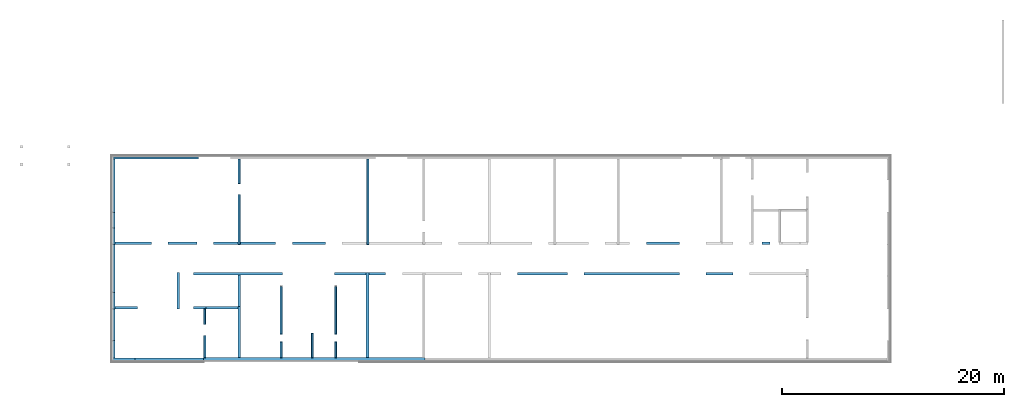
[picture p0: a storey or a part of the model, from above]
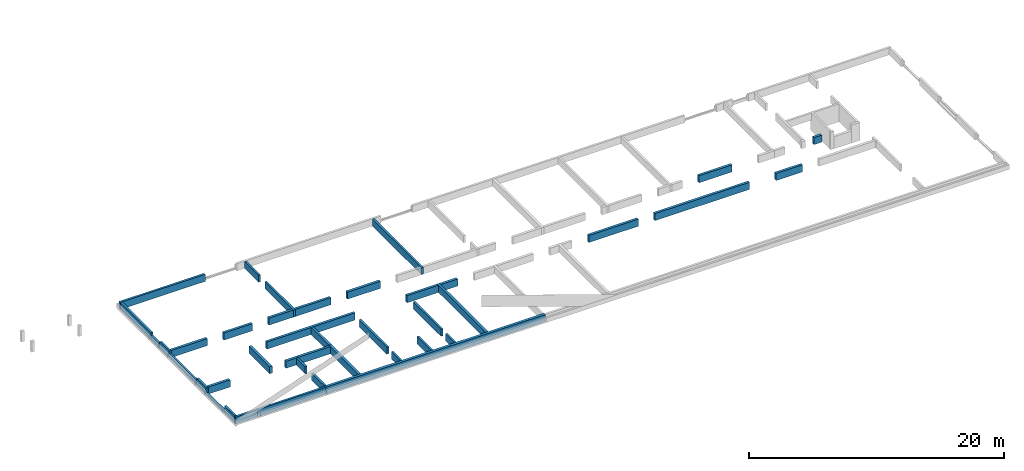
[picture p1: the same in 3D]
Properties of the parts of a building model (IFC2X3), part 1 of 8

# File
Description: ViewDefinition [CoordinationView_V2.0, SpaceBoundary2ndLevelAddOnView], Option [Elements to export: Visible elements (on all stories)], Option [Partial Structure Display: Entire Model], Option [IFC Domain: All], Option [Structural Function: All Elements], Option [Convert Grid elements: On], Option [Convert IFC Annotations and Archicad 2D elements: Off], Option [Convert 2D symbols of Doors and Windows: Off], Option [Export geometries that Participates in Collision Detection only: Off], Option [Split complex elements: On], Option [IFC Domain For Space Containment: Custom], Option [Elements in Solid Element Operations: BRep], Option [Elements with junctions: BRep], Option [IFC Model position: Survey Point and Project Origin], Option [Curtain Wall export mode: Container Element], Option [Railing export mode: Container Element], Option [Stair export mode: Container Element], Option [Properties To Export: All properties], Option [Space containment: Off], Option [Geometry to type objects: Off], Option [Element Properties: Visible Only], Option [Building Material Properties: Off], Option [Element Parameters: Off], Option [Component Parameters: Off], Option [IFC Base Quantities: Off], Option [Door Window Parameters: On], Option [IFC Space boundaries: On], Option [Archicad Zone Categories as IFC Space classification data: Off], Option [Element Classifications: On]
File name: C:\Users\User\OneDrive\Desktop\AK2_TP_AR.ifc
Time: 2025-07-31T16:51:45
Author: RKAS
Organization: Building Designer Office
Written by: DDS_IFC v3.0
Made in: IFC file generated by Graphisoft Archicad 26.0.0 INT FULL Windows version (IFC add-on version: 7004 INT FULL).
Authorization: RKAS

# IfcProject, METK Aretuskeskus 2
Phase: Tööprojekt

# IfcSite, ÜBN Kinnistu Nimi -> SOLIBRI
Description: Kinnistu Kirjeldus; RefLatitude: 59, 25, 17, 655600; RefLongitude: 24, 44, 44, 307600; RefElevation: 69000 mm; Classification: 1.0.1 IfcSite (kinnistu) (BIM ÜBN + Archicad Classification 26 + v 2.0)
AR_Kinnistu - 010_Katastritunnus: 24701:001:1420; 015_Ehitatav-pindala: 1380 m2; 020_Pindala: 7544 m2; 025_Max-kõrgus: 14000 mm

# IfcBuilding, METK ARETUSKESKUS II
Classification: 1.0.2 IfcBuilding (hoone) (BIM ÜBN + Archicad Classification 26 + v 2.0)
AR_Hoone - 030_Hoone-aadress: Seemne tn 10a, Jõgeva alevik, Jõgeva vald, Jõgeva maakond; 035_Sprinkler: no; 041_Sügavus: 0 mm; 701_ETAK-id: täiendamisel; 704_Kasutusotstarve: Büroohoone; 705_Kasutusotstarbe-kood: 12201; 707_Tuleohutusklass: TP2; 703_Kasutajate-arv: 100; 706_Eripõlemiskoormus: 599; 001_Nimetus: METK ARETUSKESKUS II; 040_Kõrgus: 10300 mm; 045_Hoonealune-pindala: 1334.3 m2; 050_Neto-pindala: 2214.8 m2; 055_Neto-ruumala: 9000 m3; 700_EHR-kood: 121423536; 702_ADS-OID: EE04134256

# IfcBuildingStorey (4)
In: METK ARETUSKESKUS II
Name | Elevation (mm) | 710_Määrusejärgne-korrus | 060_Korruse-nimi | 070_Maapealne
Vundament | -1610 | no | Vundament | no
Esimene korrus | 0 | yes | Esimene korrus | yes | Classification: 1.0.3 IfcBuildingStorey (korrus) (BIM ÜBN + Archicad Classification 26 + v 2.0); AR_Korrus - 065_Korruse-number: 1
Teine korrus | 4425 | yes | Teine korrus | yes | AR_Korrus - 065_Korruse-number: 2
Katus | 8635 | no | Katus | yes

# IfcBeam: 31 Konst: raudbetoon monoliitne 180 (28)
In: Vundament
Type - PredefinedType: BEAM
Classification: 1.01 IfcBeamType (tala) (BIM ÜBN + Archicad Classification); Material: 31 Konst: raudbetoon monoliitne
AR_ÜLD - 001_Nimetus: Tala; 009_Märkus: vt. EK-osa
Pset_BeamCommon - IsExternal: no; LoadBearing: yes
AC_Pset_RenovationAndPhasing - Renovation Status: New

# IfcBeam: 31 Konst: raudbetoon monoliitne 190 (22)
In: Vundament
Type - PredefinedType: BEAM
Classification: 1.01 IfcBeamType (tala) (BIM ÜBN + Archicad Classification); Material: 31 Konst: raudbetoon monoliitne
AR_ÜLD - 001_Nimetus: Tala; 009_Märkus: vt. EK-osa
AC_Pset_RenovationAndPhasing - Renovation Status: New
Pset_BeamCommon - IsExternal: no; LoadBearing: yes

# IfcBeam: 31 Konst: raudbetoon monoliitne 230 (17)
In: Vundament
Type - PredefinedType: BEAM
Classification: 1.01 IfcBeamType (tala) (BIM ÜBN + Archicad Classification); Material: 31 Konst: raudbetoon monoliitne
AR_ÜLD - 001_Nimetus: Tala; 009_Märkus: vt. EK-osa
AC_Pset_RenovationAndPhasing - Renovation Status: New
Pset_BeamCommon - IsExternal: no; LoadBearing: yes

# IfcBeam: 31 Konst: raudbetoon monoliitne 240
In: Vundament
Type - PredefinedType: BEAM
Classification: 1.01 IfcBeamType (tala) (BIM ÜBN + Archicad Classification); Material: 31 Konst: raudbetoon monoliitne
AC_Pset_RenovationAndPhasing - Renovation Status: New
Pset_BeamCommon - IsExternal: no; LoadBearing: yes
AR_ÜLD - 001_Nimetus: Tala; 009_Märkus: vt. EK-osa

# IfcBeam: 40 Kiht: Teras 150 x 1030, TALA
In: Teine korrus
Type - PredefinedType: BEAM
Classification: 1.01 IfcBeamType (tala) (BIM ÜBN + Archicad Classification); Material: 40 Kiht: Teras
Pset_BeamCommon - Span: 11650 mm; Slope: 0 deg; IsExternal: yes; LoadBearing: yes; Reference: 40 Kiht: Teras 150 x 1030
AC_Pset_RenovationAndPhasing - Renovation Status: New
AR_ÜLD - 009_Märkus: OMA märkus

# IfcBeam: 40 Kiht: Teras 300 x 490, TALA
In: Teine korrus
Type - PredefinedType: BEAM
Classification: 1.01 IfcBeamType (tala) (BIM ÜBN + Archicad Classification); Material: 40 Kiht: Teras
Pset_BeamCommon - Span: 11650 mm; Slope: 0 deg; IsExternal: yes; LoadBearing: yes; Reference: 40 Kiht: Teras 300 x 490
AC_Pset_RenovationAndPhasing - Renovation Status: New
AR_ÜLD - 009_Märkus: OMA märkus

# IfcBeam: 80 Siseviim: tolmutõke 180
In: Vundament
Type - PredefinedType: BEAM
Classification: 1.01 IfcBeamType (tala) (BIM ÜBN + Archicad Classification); Material: 80 Siseviim: tolmutõke
AR_ÜLD - 001_Nimetus: Tala; 009_Märkus: vt. EK-osa
AC_Pset_RenovationAndPhasing - Renovation Status: New
Pset_BeamCommon - IsExternal: no; LoadBearing: yes

# IfcBeam: 80 Siseviim: tolmutõke 230 (16)
In: Vundament
Type - PredefinedType: BEAM
Classification: 1.01 IfcBeamType (tala) (BIM ÜBN + Archicad Classification); Material: 80 Siseviim: tolmutõke
AR_ÜLD - 001_Nimetus: Tala; 009_Märkus: vt. EK-osa
AC_Pset_RenovationAndPhasing - Renovation Status: New
Pset_BeamCommon - IsExternal: no; LoadBearing: yes

# IfcBeam: Steel L Section 100 x 100 (3)
In: Esimene korrus
Type - PredefinedType: BEAM
Classification: 1.01 IfcBeamType (tala) (BIM ÜBN + Archicad Classification); Material: 30 Konst: Teras - Konstruktsioon
Pset_BeamCommon - IsExternal: yes; LoadBearing: yes; Reference: Steel L Section 100 x 100
AR_ÜLD - 001_Nimetus: Kandetala
AC_Pset_RenovationAndPhasing - Renovation Status: New
Name | Span (mm) | Slope (deg)
TALA | 9310 | 0
TALA | 9512.21 | 1.23489
TALA | 9510 | 0

# IfcBeam: Steel L Section 300 x 150 (3)
In: Esimene korrus
Type - PredefinedType: BEAM
Classification: 1.01 IfcBeamType (tala) (BIM ÜBN + Archicad Classification); Material: 30 Konst: Teras - Konstruktsioon
AR_ÜLD - 001_Nimetus: Kandetala
AC_Pset_RenovationAndPhasing - Renovation Status: New
Pset_BeamCommon - Slope: 0 deg; IsExternal: yes; LoadBearing: yes; Reference: Steel L Section 300 x 150
Name | Span (mm)
2 x TALA | 8700
TALA | 4350

# IfcBeam: Steel L Section 50 x 130 (3)
In: Teine korrus
Type - PredefinedType: BEAM
Classification: 1.01 IfcBeamType (tala) (BIM ÜBN + Archicad Classification); Material: 30 Konst: Teras - Konstruktsioon
Pset_BeamCommon - Slope: 0 deg; IsExternal: yes; LoadBearing: yes; Reference: Steel L Section 50 x 130
AR_ÜLD - 001_Nimetus: Kandetala
AC_Pset_RenovationAndPhasing - Renovation Status: New
Name | Span (mm)
TALA | 4028
2 x TALA | 8378

# IfcBeam: Steel L Section 50 x 50 (3)
In: Teine korrus
Type - PredefinedType: BEAM
Classification: 1.01 IfcBeamType (tala) (BIM ÜBN + Archicad Classification); Material: 30 Konst: Teras - Konstruktsioon
Pset_BeamCommon - Slope: 0 deg; IsExternal: yes; LoadBearing: yes; Reference: Steel L Section 50 x 50
AC_Pset_RenovationAndPhasing - Renovation Status: New
AR_ÜLD - 001_Nimetus: Kandetala
Name | Span (mm)
2 x TALA | 8398
TALA | 4048.01

# IfcBeam: Steel T Section 140 x 140, TALA
In: Esimene korrus
Type - PredefinedType: BEAM
Classification: 1.01 IfcBeamType (tala) (BIM ÜBN + Archicad Classification); Material: 40 Kiht: Teras
Pset_BeamCommon - Span: 4050 mm; Slope: 0 deg; IsExternal: yes; LoadBearing: yes; Reference: Steel T Section 140 x 140
AR_ÜLD - 001_Nimetus: Kandetala
AC_Pset_RenovationAndPhasing - Renovation Status: New

# IfcBeam: Trapets puit 50 x 195 (14)
In: Esimene korrus
Type - PredefinedType: BEAM
Classification: 1.01 IfcBeamType (tala) (BIM ÜBN + Archicad Classification); Material: 60 Plaat: liimpuitplaat
Pset_BeamCommon - Slope: 0 deg; IsExternal: yes; LoadBearing: yes; Reference: Trapets puit 50 x 195
AR_ÜLD - 001_Nimetus: Kandetala
AC_Pset_RenovationAndPhasing - Renovation Status: New
Name | Span (mm)
5 x TALA | 9940
3 x TALA | 3500.01
2 x TALA | 9940.01
4 x TALA | 1467

# IfcBeam: UPE100 60 x 140 (2)
In: Esimene korrus
Type - PredefinedType: BEAM
Classification: 1.01 IfcBeamType (tala) (BIM ÜBN + Archicad Classification); Material: 30 Konst: Teras - Konstruktsioon
Pset_BeamCommon - Span: 9799.39 mm; Slope: 0 deg; IsExternal: yes; LoadBearing: yes; Reference: UPE100 60 x 140
AR_ÜLD - 001_Nimetus: Kandetala
AC_Pset_RenovationAndPhasing - Renovation Status: New

# IfcBuildingElementPart (1536)
Name | In | Material | 009_Märkus
26 x 50 Soojustus: EPS | Vundament | 50 Soojustus: EPS
26 x 92 Viim: betoonlasuur | Vundament | 92 Viim: betoonlasuur
7 x 30 Konst: Columbia õõnesplokk | Esimene korrus | 30 Konst: Columbia õõnesplokk
17 x 50 Soojustus: PIR SW | Esimene korrus | 50 Soojustus: PIR SW
27 x 72 Kiht: SW plekk | Esimene korrus | 72 Kiht: SW plekk
28 x 50 Soojustus: EPS | Esimene korrus | 50 Soojustus: EPS | vt. EK-osa konstruktsioone
14 x 30 Konst: Raudbetoon monoliitne | Esimene korrus | 30 Konst: Raudbetoon monoliitne | vt. EK-osa konstruktsioone
28 x 20 Keskkond: killustikalus | Esimene korrus | 20 Keskkond: killustikalus | vt. EK-osa konstruktsioone
4 x 60 Plaat: Kipsplaat | Esimene korrus | 60 Plaat: Kipsplaat | SS-01 seinatüüp SL-01 lisavoodriga
4 x 50 Soojustus: PIR saun | Esimene korrus | 50 Soojustus: PIR saun | SS-01 seinatüüp SL-01 lisavoodriga
2 x 60 Plaat: Kipsplaat | Esimene korrus | 60 Plaat: Kipsplaat | SS-02 seinatüüp SL-01 lisavoodriga
2 x 50 Soojustus: PIR saun | Esimene korrus | 50 Soojustus: PIR saun | SS-02 seinatüüp SL-01 lisavoodriga
2 x 30 Konst: Columbia õõnesplokk | Esimene korrus | 30 Konst: Columbia õõnesplokk | SS-02 seinatüüp SL-01 lisavoodriga
2 x 60 Plaat: Kipsplaat | Esimene korrus | 60 Plaat: Kipsplaat | kergsein
2 x 60 Plaat: Kipsplaat tulekindel | Esimene korrus | 60 Plaat: Kipsplaat tulekindel | kergsein
50 Soojustus: klaasvill | Esimene korrus | 50 Soojustus: klaasvill | kergsein
16 x 50 Soojustus: XPS | Esimene korrus | 50 Soojustus: XPS | Põrand paksendatud betoonplaadiga, vt. EK-osa
16 x 20 Keskkond: killustikalus | Esimene korrus | 20 Keskkond: killustikalus | Põrand paksendatud betoonplaadiga, vt. EK-osa
8 x 30 Konst: Raudbetoon monoliitne | Esimene korrus | 30 Konst: Raudbetoon monoliitne | Põrand paksendatud betoonplaadiga, vt. EK-osa
8 x 50 Soojustus: PIR saun | Esimene korrus | 50 Soojustus: PIR saun | vt. SS-10/SS-10a konstruktsioonitüüpi
8 x 70 Kiht: Õhkvahe karkass | Esimene korrus | 70 Kiht: Õhkvahe karkass | vt. SS-10/SS-10a konstruktsioonitüüpi
8 x 92 Viim: Puit voodrilaud saun | Esimene korrus | 92 Viim: Puit voodrilaud saun | vt. SS-10/SS-10a konstruktsioonitüüpi
4 x 60 Plaat: Tsementkiudplaat | Esimene korrus | 60 Plaat: Tsementkiudplaat | vt. SA-osa
9 x 50 Soojustus: klaasvill | Esimene korrus | 50 Soojustus: klaasvill | vt. SA-osa
7 x 60 Plaat: Puitkiudplaat | Esimene korrus | 60 Plaat: Puitkiudplaat | vt. SA-osa
30 Konst: Raudbetoon monoliitne | Esimene korrus | 30 Konst: Raudbetoon monoliitne | vt. EK-osa
20 Keskkond: killustikalus | Esimene korrus | 20 Keskkond: killustikalus | vt. EK-osa
2 x 50 Soojustus: klaasvill | Esimene korrus | 50 Soojustus: klaasvill | Loputuskasti tagune
4 x 60 Plaat: Tsementkiudplaat | Esimene korrus | 60 Plaat: Tsementkiudplaat | Loputuskasti tagune
4 x 20 Keskkond: killustikalus | Esimene korrus | 20 Keskkond: killustikalus | NB! jälgida SA-osa porivaipa! Betoonplaadi paksus 80mm
4 x 50 Soojustus: EPS | Esimene korrus | 50 Soojustus: EPS | NB! jälgida SA-osa porivaipa! Betoonplaadi paksus 80mm
2 x 30 Konst: Raudbetoon monoliitne | Esimene korrus | 30 Konst: Raudbetoon monoliitne | NB! jälgida SA-osa porivaipa! Betoonplaadi paksus 80mm
101 x 71 Kiht: MDF | Esimene korrus | 71 Kiht: MDF | OMA märkus
101 x 80 Siseviimistlus dold | Esimene korrus | 80 Siseviimistlus dold | OMA märkus
10 x 60 Plaat: Kipsplaat | Esimene korrus | 60 Plaat: Kipsplaat | OMA märkus
12 x 50 Soojustus: kivivill | Esimene korrus | 50 Soojustus: kivivill | OMA märkus
29 x 70 Kiht: Õhkvahe karkass | Esimene korrus | 70 Kiht: Õhkvahe karkass | OMA märkus
50 Soojustus: XPS | Esimene korrus | 50 Soojustus: XPS | pinnase vastas
30 Konst: Columbia õõnesplokk | Esimene korrus | 30 Konst: Columbia õõnesplokk | pinnase vastas
15 x 50 Soojustus: klaasvill | Esimene korrus | 50 Soojustus: klaasvill | vt. AR-8 konstruktsioonitüüpe
15 x 60 Plaat: Puitkiudplaat | Esimene korrus | 60 Plaat: Puitkiudplaat | vt. AR-8 konstruktsioonitüüpe
15 x 50 Soojustus: klaasvill | Esimene korrus | 50 Soojustus: klaasvill | OMA märkus
15 x 60 Plaat: Puitkiudplaat | Esimene korrus | 60 Plaat: Puitkiudplaat | OMA märkus
20 x 60 Plaat: Kipsplaat | Esimene korrus | 60 Plaat: Kipsplaat | Akustiline paneel
10 x 50 Soojustus: klaasvill | Esimene korrus | 50 Soojustus: klaasvill | Akustiline paneel
2 x 71 Kiht: akustiline plaat | Esimene korrus | 71 Kiht: akustiline plaat | OMA märkus
2 x 92 Viim: Puit voodrilaud saun | Esimene korrus | 92 Viim: Puit voodrilaud saun | OMA märkus
4 x 72 Kiht: SW plekk | Esimene korrus | 72 Kiht: SW plekk | OMA märkus
2 x 50 Soojustus: PIR SW | Esimene korrus | 50 Soojustus: PIR SW | OMA märkus
2 x 50 Soojustus: PIR saun | Esimene korrus | 50 Soojustus: PIR saun | OMA märkus
4 x 60 Plaat: Kipsplaat | Esimene korrus | 60 Plaat: Kipsplaat | Šahtisein
2 x 50 Soojustus: klaasvill | Esimene korrus | 50 Soojustus: klaasvill | Šahtisein
4 x 40 Kiht: Teras | Esimene korrus | 40 Kiht: Teras | vt. AR-8 kujujooniseid
4 x 44 Konst: Alumiinium | Esimene korrus | 44 Konst: Alumiinium | vt. AR-8 kujujooniseid
2 x 45 Konst: puit hor | Esimene korrus | 45 Konst: puit hor | OMA märkus
30 Konstr: CLT-talad | Esimene korrus | 30 Konstr: CLT-talad | OMA märkus
2 x Concrete - Structural | Esimene korrus | Concrete - Structural | OMA märkus
2 x 60 Plaat: Vineer veekindel | Esimene korrus | 60 Plaat: Vineer veekindel | vt. EK-osa. Mudelis jaotatud osadeks
2 x 72 Kiht: SBS-katusekate | Esimene korrus | 72 Kiht: SBS-katusekate | vt. EK-osa. Mudelis jaotatud osadeks
2 x 72 Kiht: drenaažimatt | Esimene korrus | 72 Kiht: drenaažimatt | vt. EK-osa. Mudelis jaotatud osadeks
2 x 20 Keskkond: Pinnas | Esimene korrus | 20 Keskkond: Pinnas | vt. EK-osa. Mudelis jaotatud osadeks
2 x 21 Keskkond: Pinnas 01 | Esimene korrus | 21 Keskkond: Pinnas 01 | vt. EK-osa. Mudelis jaotatud osadeks
80 Siseviimistlus dold | Esimene korrus | 80 Siseviimistlus dold
70 Kiht: Õhkvahe karkass | Esimene korrus | 70 Kiht: Õhkvahe karkass
50 Soojustus: PIR SW | Esimene korrus | 50 Soojustus: PIR SW | vt. AR-8 konstruktsioonitüüpe
2 x 72 Kiht: SW plekk | Esimene korrus | 72 Kiht: SW plekk | vt. AR-8 konstruktsioonitüüpe
14 x 50 Soojustus: PIR SW | Teine korrus | 50 Soojustus: PIR SW
15 x 72 Kiht: SW plekk | Teine korrus | 72 Kiht: SW plekk
13 x 30 Konst: Columbia õõnesplokk | Teine korrus | 30 Konst: Columbia õõnesplokk
9 x 30 Konst: Raudbetoon monoliitne pealevalu | Teine korrus | 30 Konst: Raudbetoon monoliitne pealevalu | vt. EK-osa
18 x 50 Soojustus: EPS | Teine korrus | 50 Soojustus: EPS | vt. EK-osa
9 x 30 Konst: Raudbetoon monteeritav | Teine korrus | 30 Konst: Raudbetoon monteeritav | vt. EK-osa
4 x 72 Kiht: SW plekk | Teine korrus | 72 Kiht: SW plekk | vt. VS-08
2 x 50 Soojustus: PIR SW | Teine korrus | 50 Soojustus: PIR SW | vt. VS-08
92 x 60 Plaat: Kipsplaat | Teine korrus | 60 Plaat: Kipsplaat | kergsein
50 x 50 Soojustus: klaasvill | Teine korrus | 50 Soojustus: klaasvill | kergsein
92 x 60 Plaat: Kipsplaat tulekindel | Teine korrus | 60 Plaat: Kipsplaat tulekindel | kergsein
7 x 72 Kiht: SW plekk | Teine korrus | 72 Kiht: SW plekk | vt. AR-7 sõlmlahendusi
3 x 30 Konst: Columbia õõnesplokk | Teine korrus | 30 Konst: Columbia õõnesplokk | vt. AR-7 sõlmlahendusi
4 x 50 Soojustus: PIR SW | Teine korrus | 50 Soojustus: PIR SW | vt. AR-7 sõlmlahendusi
4 x 79 Kiht: õhkvahe | Teine korrus | 79 Kiht: õhkvahe | kergsein
32 x 60 Plaat: Kipsplaat | Teine korrus | 60 Plaat: Kipsplaat
8 x 60 Plaat: Kipsplaat tulekindel | Teine korrus | 60 Plaat: Kipsplaat tulekindel
12 x 50 Soojustus: klaasvill | Teine korrus | 50 Soojustus: klaasvill
6 x 60 Plaat: Kipsplaat | Teine korrus | 60 Plaat: Kipsplaat | Šahtisein
3 x 50 Soojustus: klaasvill | Teine korrus | 50 Soojustus: klaasvill | Šahtisein
3 x 30 Konst: Betoonplaat | Teine korrus | 30 Konst: Betoonplaat | vt. EK-osa. Mudelis jaotatud osadeks
13 x 72 Kiht: SBS-katusekate | Teine korrus | 72 Kiht: SBS-katusekate | vt. EK-osa. Mudelis jaotatud osadeks
15 x 50 Soojustus: EPS | Teine korrus | 50 Soojustus: EPS | vt. EK-osa. Mudelis jaotatud osadeks
3 x 72 Kiht: SBS-aurutõke | Teine korrus | 72 Kiht: SBS-aurutõke | vt. EK-osa. Mudelis jaotatud osadeks
2 x 64 Plaat: vineer | Teine korrus | 64 Plaat: vineer
6 x 72 Kiht: veeplekk | Teine korrus | 72 Kiht: veeplekk
8 x 60 Plaat: Tsementkiudplaat | Teine korrus | 60 Plaat: Tsementkiudplaat | Loputuskasti tagune
4 x 50 Soojustus: klaasvill | Teine korrus | 50 Soojustus: klaasvill | Loputuskasti tagune
2 x 92 Viim: Puit voodrilaud | Teine korrus | 92 Viim: Puit voodrilaud | 1. korruse lõuna ja põhja fassaadi välisuste kohal. vt. skeemi joonisel. vt. täpsemalt EK-osa ja AR-7 sõlmlahendusi
2 x 30 Konst: Teras - Konstruktsioon | Teine korrus | 30 Konst: Teras - Konstruktsioon | 1. korruse lõuna ja põhja fassaadi välisuste kohal. vt. skeemi joonisel. vt. täpsemalt EK-osa ja AR-7 sõlmlahendusi
2 x 40 Kiht: Teras | Teine korrus | 40 Kiht: Teras | 1. korruse lõuna ja põhja fassaadi välisuste kohal. vt. skeemi joonisel. vt. täpsemalt EK-osa ja AR-7 sõlmlahendusi
2 x 30 Konst: puit 01 | Teine korrus | 30 Konst: puit 01 | 1. korruse lõuna ja põhja fassaadi välisuste kohal. vt. skeemi joonisel. vt. täpsemalt EK-osa ja AR-7 sõlmlahendusi
4 x 60 Plaat: Tsementkiudplaat | Teine korrus | 60 Plaat: Tsementkiudplaat | vt. SA-osa
2 x 50 Soojustus: klaasvill | Teine korrus | 50 Soojustus: klaasvill | vt. SA-osa
6 x 60 Plaat: Kipsplaat | Teine korrus | 60 Plaat: Kipsplaat | Akustiline paneel
3 x 50 Soojustus: klaasvill | Teine korrus | 50 Soojustus: klaasvill | Akustiline paneel
6 x 80 Siseviimistlus dold | Teine korrus | 80 Siseviimistlus dold | OMA märkus
14 x 70 Kiht: Õhkvahe karkass | Teine korrus | 70 Kiht: Õhkvahe karkass | OMA märkus
9 x 60 Plaat: Kipsplaat | Teine korrus | 60 Plaat: Kipsplaat | OMA märkus
10 x 50 Soojustus: kivivill | Teine korrus | 50 Soojustus: kivivill | OMA märkus
2 x 71 Kiht: akustiline plaat | Teine korrus | 71 Kiht: akustiline plaat | OMA märkus
2 x 92 Viim: Puit voodrilaud | Teine korrus | 92 Viim: Puit voodrilaud | vt. AR-7 sõlmlahendusi
4 x 70 Kiht: Õhkvahe karkass | Teine korrus | 70 Kiht: Õhkvahe karkass | vt. AR-7 sõlmlahendusi
2 x 71 Kiht: MDF | Teine korrus | 71 Kiht: MDF
2 x 80 Siseviimistlus dold | Teine korrus | 80 Siseviimistlus dold
92 Viim: Puit voodrilaud | Teine korrus | 92 Viim: Puit voodrilaud | 1. korruse ida fassaadi välisukse kohal. vt. skeemi joonisel. vt. täpsemalt EK-osa ja AR-7 sõlmlahendusi
30 Konst: Teras - Konstruktsioon | Teine korrus | 30 Konst: Teras - Konstruktsioon | 1. korruse ida fassaadi välisukse kohal. vt. skeemi joonisel. vt. täpsemalt EK-osa ja AR-7 sõlmlahendusi
30 Konst: puit 01 | Teine korrus | 30 Konst: puit 01 | 1. korruse ida fassaadi välisukse kohal. vt. skeemi joonisel. vt. täpsemalt EK-osa ja AR-7 sõlmlahendusi
4 x 50 Soojustus: PIR | Teine korrus | 50 Soojustus: PIR | vt. EK-osa ja AR-7 sõlmlahendusi
4 x 72 Kiht: SBS-katusekate | Teine korrus | 72 Kiht: SBS-katusekate | vt. EK-osa ja AR-7 sõlmlahendusi
4 x 50 Soojustus: EPS | Teine korrus | 50 Soojustus: EPS | vt. EK-osa ja AR-7 sõlmlahendusi
2 x 72 Kiht: SW plekk | Teine korrus | 72 Kiht: SW plekk | vt. AR-7 sõlmlahendusi. KL-01 lisaks
50 Soojustus: PIR SW | Teine korrus | 50 Soojustus: PIR SW | vt. AR-7 sõlmlahendusi. KL-01 lisaks
2 x 72 Kiht: SBS-katusekate | Teine korrus | 72 Kiht: SBS-katusekate | vt. AR-7 sõlmlahendusi
2 x 60 Plaat: Vineer veekindel | Teine korrus | 60 Plaat: Vineer veekindel | vt. AR-7 sõlmlahendusi
5 x 92 Viim: Puit voodrilaud | Teine korrus | 92 Viim: Puit voodrilaud | vt. VS-08
5 x 90 Viim: Õhkvahe karkass | Teine korrus | 90 Viim: Õhkvahe karkass | vt. VS-08
60 Plaat: Kipsplaat tulekindel | Teine korrus | 60 Plaat: Kipsplaat tulekindel | OMA märkus
3 x 45 Konst: puit hor | Teine korrus | 45 Konst: puit hor | OMA märkus
2 x Concrete - Structural | Teine korrus | Concrete - Structural | OMA märkus
10 x 60 Plaat: Vineer veekindel | Teine korrus | 60 Plaat: Vineer veekindel | vt. EK-osa. Mudelis jaotatud osadeks
10 x 72 Kiht: drenaažimatt | Teine korrus | 72 Kiht: drenaažimatt | vt. EK-osa. Mudelis jaotatud osadeks
10 x 20 Keskkond: Pinnas | Teine korrus | 20 Keskkond: Pinnas | vt. EK-osa. Mudelis jaotatud osadeks
10 x 21 Keskkond: Pinnas 01 | Teine korrus | 21 Keskkond: Pinnas 01 | vt. EK-osa. Mudelis jaotatud osadeks
28 x 50 Soojustus: PIR | Katus | 50 Soojustus: PIR | vt. AR-7 sõlmlahendusi
33 x 72 Kiht: SBS-katusekate | Katus | 72 Kiht: SBS-katusekate | vt. AR-7 sõlmlahendusi
28 x 30 Konst: Columbia õõnesplokk | Katus | 30 Konst: Columbia õõnesplokk | vt. AR-7 sõlmlahendusi
8 x 72 Kiht: SBS-katusekate | Katus | 72 Kiht: SBS-katusekate
13 x 72 Kiht: SW plekk | Katus | 72 Kiht: SW plekk
8 x 50 Soojustus: PIR SW | Katus | 50 Soojustus: PIR SW
3 x 50 Soojustus: PIR | Katus | 50 Soojustus: PIR
3 x 30 Konst: Columbia õõnesplokk | Katus | 30 Konst: Columbia õõnesplokk
6 x 72 Kiht: veeplekk | Katus | 72 Kiht: veeplekk | vt. AR-7 sõlmlhaendusi
6 x 64 Plaat: vineer | Katus | 64 Plaat: vineer | vt. AR-7 sõlmlhaendusi
30 Konst: Teras - Konstruktsioon | Katus | 30 Konst: Teras - Konstruktsioon | 2. korruse lõuna fassaadi akna kohal. vt. skeemi joonisel. vt. täpsemalt EK-osa ja AR-7 sõlmlahendusi
40 Kiht: Teras | Katus | 40 Kiht: Teras | 2. korruse lõuna fassaadi akna kohal. vt. skeemi joonisel. vt. täpsemalt EK-osa ja AR-7 sõlmlahendusi
30 Konst: puit 01 | Katus | 30 Konst: puit 01 | 2. korruse lõuna fassaadi akna kohal. vt. skeemi joonisel. vt. täpsemalt EK-osa ja AR-7 sõlmlahendusi
92 Viim: Puit voodrilaud | Katus | 92 Viim: Puit voodrilaud | 2. korruse lõuna fassaadi akna kohal. vt. skeemi joonisel. vt. täpsemalt EK-osa ja AR-7 sõlmlahendusi
2 x 72 Kiht: SBS-katusekate | Katus | 72 Kiht: SBS-katusekate | vt. EK-osa, mudelis jaotatud osadeks
2 x 50 Soojustus: PIR | Katus | 50 Soojustus: PIR | vt. EK-osa, mudelis jaotatud osadeks
2 x 50 Soojustus: EPS | Katus | 50 Soojustus: EPS | vt. EK-osa, mudelis jaotatud osadeks
30 x 72 Kiht: SBS-katusekate | Katus | 72 Kiht: SBS-katusekate | vt. EK-osa. Mudelis jaotatud osadeks
29 x 50 Soojustus: EPS | Katus | 50 Soojustus: EPS | vt. EK-osa. Mudelis jaotatud osadeks
5 x 60 Plaat: Vineer veekindel | Katus | 60 Plaat: Vineer veekindel | vt. AR-7 sõlmlahendusi
5 x 70 Kiht: Õhkvahe karkass | Katus | 70 Kiht: Õhkvahe karkass | vt. AR-7 sõlmlahendusi
30 x 50 Soojustus: PIR | Katus | 50 Soojustus: PIR | vt. EK-osa. Mudelis jaotatud osadeks
72 Kiht: SW plekk | Katus | 72 Kiht: SW plekk | vt. AR-7 sõlmlahendusi
50 Soojustus: PIR SW | Katus | 50 Soojustus: PIR SW | vt. AR-7 sõlmlahendusi
92 Viim: Puit voodrilaud | Katus | 92 Viim: Puit voodrilaud | vt. AR-7 sõlmlahendusi

# IfcBuildingElementProxy: 01 Üldine: projekteeritud 50 x 50 (6)
In: Esimene korrus
Material: 01 Üldine: projekteeritud
AC_Pset_RenovationAndPhasing - Renovation Status: New

# IfcBuildingElementProxy: 30 Konst: Teras - Konstruktsioon 60 x 160 (85)
In: Katus
Classification: 1.02 IfcBuildingElementProxyType (objekt) (BIM ÜBN + Archicad Classification); Material: 30 Konst: Teras - Konstruktsioon
AR_ÜLD - 001_Nimetus: KF-profiil; 009_Märkus: vt. AR-8 spetsifikatsioone
AC_Pset_RenovationAndPhasing - Renovation Status: New
Name
7 x KA-16
10 x KA-12
7 x KA-14
7 x KA-10
28 x KA-11
19 x KA-13
7 x KA-15

# IfcBuildingElementProxy: 40 Kiht: Alumiinium profiilid 150 x 25 (3)
In: Teine korrus
Classification: 1.02 IfcBuildingElementProxyType (objekt) (BIM ÜBN + Archicad Classification); Material: 40 Kiht: Alumiinium profiilid
AR_ÜLD - 001_Nimetus: KF-profiil; 009_Märkus: vt. AR-8 spetsifikatsioone
AC_Pset_RenovationAndPhasing - Renovation Status: New

# IfcBuildingElementProxy: 40 Kiht: Alumiinium profiilid 180 x 25 (17)
In: Teine korrus
Classification: 1.02 IfcBuildingElementProxyType (objekt) (BIM ÜBN + Archicad Classification); Material: 40 Kiht: Alumiinium profiilid
AR_ÜLD - 001_Nimetus: KF-profiil; 009_Märkus: vt. AR-8 spetsifikatsioone
AC_Pset_RenovationAndPhasing - Renovation Status: New
Name
8 x KF-2
6 x KF-1
KF-3
2 x 

# IfcBuildingElementProxy: 40 Kiht: Alumiinium profiilid 75 x 25 (4)
In: Teine korrus
Classification: 1.02 IfcBuildingElementProxyType (objekt) (BIM ÜBN + Archicad Classification); Material: 40 Kiht: Alumiinium profiilid
AR_ÜLD - 001_Nimetus: KF-profiil; 009_Märkus: vt. AR-8 spetsifikatsioone
AC_Pset_RenovationAndPhasing - Renovation Status: New
Name
2 x KF-3
KF-2
KF-1

# IfcBuildingElementProxy: 40 Kiht: Teras 10 x 100
In: Esimene korrus
Material: 40 Kiht: Teras
AC_Pset_RenovationAndPhasing - Renovation Status: New

# IfcBuildingElementProxy: 40 Kiht: Teras D10
In: Esimene korrus
Material: 40 Kiht: Teras
AC_Pset_RenovationAndPhasing - Renovation Status: New

# IfcBuildingElementProxy: 45 Konst: Puit 01 10 x 1850 (12)
Material: 45 Konst: Puit 01
AC_Pset_RenovationAndPhasing - Renovation Status: New
Name | In
EM-04 | Esimene korrus
5 x  | Esimene korrus
5 x  | Teine korrus
EM-04 | Teine korrus

# IfcBuildingElementProxy: 45 Konst: Puit 01 126 x 20
In: Teine korrus
Material: 45 Konst: Puit 01
AC_Pset_RenovationAndPhasing - Renovation Status: New

# IfcBuildingElementProxy: 45 Konst: Puit 01 126 x 40 (2)
In: Teine korrus
Material: 45 Konst: Puit 01
AC_Pset_RenovationAndPhasing - Renovation Status: New
Name

S-08

# IfcBuildingElementProxy: 45 Konst: Puit 01 190 x 20 (12)
Material: 45 Konst: Puit 01
AC_Pset_RenovationAndPhasing - Renovation Status: New
Name | In
6 x  | Esimene korrus
6 x  | Teine korrus

# IfcBuildingElementProxy: 45 Konst: Puit 01 20 x 1660 (8)
Material: 45 Konst: Puit 01
AC_Pset_RenovationAndPhasing - Renovation Status: New
Name | In
2 x  | Esimene korrus
2 x EM-210 | Esimene korrus
2 x  | Teine korrus
2 x EM-210 | Teine korrus

# IfcBuildingElementProxy: 45 Konst: Puit 01 210 x 10 (8)
Material: 45 Konst: Puit 01
AC_Pset_RenovationAndPhasing - Renovation Status: New
Name | In
4 x  | Esimene korrus
4 x  | Teine korrus

# IfcBuildingElementProxy: 45 Konst: Puit 01 210 x 20 (2)
Material: 45 Konst: Puit 01
AC_Pset_RenovationAndPhasing - Renovation Status: New
Name | In
 | Esimene korrus
 | Teine korrus

# IfcBuildingElementProxy: 45 Konst: Puit 01 210 x 42
In: Teine korrus
Material: 45 Konst: Puit 01
AC_Pset_RenovationAndPhasing - Renovation Status: New

# IfcBuildingElementProxy: 45 Konst: Puit 01 250 x 150 (2)
In: Esimene korrus
Material: 45 Konst: Puit 01
AC_Pset_RenovationAndPhasing - Renovation Status: New

# IfcBuildingElementProxy: 45 Konst: Puit 01 260 x 5, S-02c
In: Esimene korrus
Material: 45 Konst: Puit 01
AC_Pset_RenovationAndPhasing - Renovation Status: New

# IfcBuildingElementProxy: 45 Konst: Puit 01 28 x 120 (4)
In: Esimene korrus
Material: 45 Konst: Puit 01
AC_Pset_RenovationAndPhasing - Renovation Status: New

# IfcBuildingElementProxy: 45 Konst: Puit 01 28 x 90 (20)
In: Esimene korrus
Material: 45 Konst: Puit 01
AC_Pset_RenovationAndPhasing - Renovation Status: New

# IfcBuildingElementProxy: 45 Konst: Puit 01 281 x 10 (2)
In: Esimene korrus
Material: 45 Konst: Puit 01
AC_Pset_RenovationAndPhasing - Renovation Status: New

# IfcBuildingElementProxy: 45 Konst: Puit 01 50 x 20 (5)
In: Esimene korrus
Material: 45 Konst: Puit 01
AC_Pset_RenovationAndPhasing - Renovation Status: New

# IfcBuildingElementProxy: 45 Konst: Puit 01 50 x 50 (15)
In: Esimene korrus
Material: 45 Konst: Puit 01
AC_Pset_RenovationAndPhasing - Renovation Status: New

# IfcBuildingElementProxy: 45 Konst: Puit 01 50 x 75 (20)
In: Esimene korrus
Material: 45 Konst: Puit 01
AC_Pset_RenovationAndPhasing - Renovation Status: New
Name
6 x TALA
14 x karkass

# IfcBuildingElementProxy: 45 Konst: Puit 01 90 x 28 (22)
In: Esimene korrus
Material: 45 Konst: Puit 01
AC_Pset_RenovationAndPhasing - Renovation Status: New

# IfcBuildingElementProxy: 45 Konst: puit hor 50 x 1 (4)
In: Teine korrus
Material: 45 Konst: puit hor
AC_Pset_RenovationAndPhasing - Renovation Status: New

# IfcBuildingElementProxy: 71 Kiht: MDF 19
In: Teine korrus
Material: 71 Kiht: MDF
AC_Pset_RenovationAndPhasing - Renovation Status: New

# IfcBuildingElementProxy: 80 Siseviimistlus dold 20 x 40 (116)
In: Teine korrus
Material: 80 Siseviimistlus dold
AC_Pset_RenovationAndPhasing - Renovation Status: New
Name
47 x POST
69 x S-02

# IfcBuildingElementProxy: 80 Siseviimistlus dold 40 x 160 (2)
In: Teine korrus
Material: 80 Siseviimistlus dold
AC_Pset_RenovationAndPhasing - Renovation Status: New

# IfcBuildingElementProxy: 80 Siseviimistlus dold 40 x 20 (371)
Material: 80 Siseviimistlus dold
AC_Pset_RenovationAndPhasing - Renovation Status: New
Name | In
41 x POST | Esimene korrus
325 x S-02 | Teine korrus
5 x POST | Teine korrus

# IfcBuildingElementProxy: 80 Siseviimistlus dold 41 x 20 (3)
In: Teine korrus
Material: 80 Siseviimistlus dold
AC_Pset_RenovationAndPhasing - Renovation Status: New

# IfcBuildingElementProxy: 80 Siseviimistlus dold 43 x 20 (12)
In: Esimene korrus
Material: 80 Siseviimistlus dold
AC_Pset_RenovationAndPhasing - Renovation Status: New

# IfcBuildingElementProxy: 92 Viim: Puit terrass 50 x 1 (4)
Material: 92 Viim: Puit terrass
AC_Pset_RenovationAndPhasing - Renovation Status: New
Name | In
profiil | Esimene korrus
3 x profiil | Teine korrus

# IfcBuildingElementProxy: FSP-01a (14)
In: Esimene korrus
Classification: 1.02 IfcBuildingElementProxyType (objekt) (BIM ÜBN + Archicad Classification); Material: 40 Kiht: Teras
AR_ÜLD - 001_Nimetus: Aknaplekk; 009_Märkus: vt. AR-7 sõlmlahendusi
AC_Pset_RenovationAndPhasing - Renovation Status: New

# IfcBuildingElementProxy: FSP-01b (5)
In: Esimene korrus
Classification: 1.02 IfcBuildingElementProxyType (objekt) (BIM ÜBN + Archicad Classification); Material: 40 Kiht: Teras
AR_ÜLD - 001_Nimetus: Aknaplekk; 009_Märkus: vt. AR-7 sõlmlahendusi
AC_Pset_RenovationAndPhasing - Renovation Status: New

# IfcBuildingElementProxy: FSP-02a (2)
In: Esimene korrus
Classification: 1.02 IfcBuildingElementProxyType (objekt) (BIM ÜBN + Archicad Classification); Material: 40 Kiht: Teras
AR_ÜLD - 001_Nimetus: Aknaplekk; 009_Märkus: vt. AR-7 sõlmlahendusi
AC_Pset_RenovationAndPhasing - Renovation Status: New

# IfcBuildingElementProxy: FSP-02b (2)
In: Esimene korrus
Classification: 1.02 IfcBuildingElementProxyType (objekt) (BIM ÜBN + Archicad Classification); Material: 40 Kiht: Teras
AR_ÜLD - 001_Nimetus: Aknaplekk; 009_Märkus: vt. AR-7 sõlmlahendusi
AC_Pset_RenovationAndPhasing - Renovation Status: New

# IfcBuildingElementProxy: FSP-03a (13)
In: Teine korrus
Classification: 1.02 IfcBuildingElementProxyType (objekt) (BIM ÜBN + Archicad Classification); Material: 40 Kiht: Teras
AR_ÜLD - 001_Nimetus: Aknaplekk; 009_Märkus: vt. AR-7 sõlmlahendusi
AC_Pset_RenovationAndPhasing - Renovation Status: New

# IfcBuildingElementProxy: FSP-03b (16)
In: Teine korrus
Classification: 1.02 IfcBuildingElementProxyType (objekt) (BIM ÜBN + Archicad Classification); Material: 40 Kiht: Teras
AR_ÜLD - 001_Nimetus: Aknaplekk; 009_Märkus: vt. AR-7 sõlmlahendusi
AC_Pset_RenovationAndPhasing - Renovation Status: New

# IfcBuildingElementProxy: FSP-04 (2)
In: Esimene korrus
Classification: 1.02 IfcBuildingElementProxyType (objekt) (BIM ÜBN + Archicad Classification); Material: 40 Kiht: Teras
AR_ÜLD - 001_Nimetus: Aknaplekk; 009_Märkus: vt. AR-7 sõlmlahendusi
AC_Pset_RenovationAndPhasing - Renovation Status: New

# IfcBuildingElementProxy: FSP-05
In: Esimene korrus
Classification: 1.02 IfcBuildingElementProxyType (objekt) (BIM ÜBN + Archicad Classification); Material: 40 Kiht: Teras
AR_ÜLD - 001_Nimetus: Aknaplekk; 009_Märkus: vt. AR-7 sõlmlahendusi
AC_Pset_RenovationAndPhasing - Renovation Status: New

# IfcBuildingElementProxy: FSP-06
In: Esimene korrus
Classification: 1.02 IfcBuildingElementProxyType (objekt) (BIM ÜBN + Archicad Classification); Material: 40 Kiht: Teras
AR_ÜLD - 001_Nimetus: Aknaplekk; 009_Märkus: vt. AR-7 sõlmlahendusi
AC_Pset_RenovationAndPhasing - Renovation Status: New

# IfcBuildingElementProxy: FSP-07 (5)
In: Esimene korrus
Classification: 1.02 IfcBuildingElementProxyType (objekt) (BIM ÜBN + Archicad Classification); Material: 40 Kiht: Teras
AR_ÜLD - 001_Nimetus: Aknaplekk; 009_Märkus: vt. AR-7 sõlmlahendusi
AC_Pset_RenovationAndPhasing - Renovation Status: New

# IfcBuildingElementProxy: FSP-08
In: Esimene korrus
Classification: 1.02 IfcBuildingElementProxyType (objekt) (BIM ÜBN + Archicad Classification); Material: 40 Kiht: Teras
AR_ÜLD - 001_Nimetus: Aknaplekk; 009_Märkus: vt. AR-7 sõlmlahendusi
AC_Pset_RenovationAndPhasing - Renovation Status: New

# IfcBuildingElementProxy: FSP-09 (2)
In: Esimene korrus
Classification: 1.02 IfcBuildingElementProxyType (objekt) (BIM ÜBN + Archicad Classification); Material: 40 Kiht: Teras
AC_Pset_RenovationAndPhasing - Renovation Status: New
AR_ÜLD - 001_Nimetus: Aknaplekk; 009_Märkus: vt. AR-7 sõlmlahendusi

# IfcBuildingElementProxy: FSP-10
In: Teine korrus
Classification: 1.02 IfcBuildingElementProxyType (objekt) (BIM ÜBN + Archicad Classification); Material: 40 Kiht: Teras
AR_ÜLD - 001_Nimetus: Aknaplekk; 009_Märkus: vt. AR-7 sõlmlahendusi
AC_Pset_RenovationAndPhasing - Renovation Status: New

# IfcBuildingElementProxy: FSP-11 (3)
In: Teine korrus
Classification: 1.02 IfcBuildingElementProxyType (objekt) (BIM ÜBN + Archicad Classification); Material: 40 Kiht: Teras
AR_ÜLD - 001_Nimetus: Aknaplekk; 009_Märkus: vt. AR-7 sõlmlahendusi
AC_Pset_RenovationAndPhasing - Renovation Status: New

# IfcBuildingElementProxy: FSP-12 (3)
In: Teine korrus
Classification: 1.02 IfcBuildingElementProxyType (objekt) (BIM ÜBN + Archicad Classification); Material: 40 Kiht: Teras
AC_Pset_RenovationAndPhasing - Renovation Status: New
AR_ÜLD - 001_Nimetus: Aknaplekk; 009_Märkus: vt. AR-7 sõlmlahendusi

# IfcBuildingElementProxy: FSP-13
In: Teine korrus
Classification: 1.02 IfcBuildingElementProxyType (objekt) (BIM ÜBN + Archicad Classification); Material: 40 Kiht: Teras
AR_ÜLD - 001_Nimetus: Aknaplekk; 009_Märkus: vt. AR-7 sõlmlahendusi
AC_Pset_RenovationAndPhasing - Renovation Status: New

# IfcBuildingElementProxy: FSP-14
In: Teine korrus
Classification: 1.02 IfcBuildingElementProxyType (objekt) (BIM ÜBN + Archicad Classification); Material: 40 Kiht: Teras
AR_ÜLD - 001_Nimetus: Aknaplekk; 009_Märkus: vt. AR-7 sõlmlahendusi
AC_Pset_RenovationAndPhasing - Renovation Status: New

# IfcBuildingElementProxy: FSV-10 (2)
In: Teine korrus
Classification: 1.02 IfcBuildingElementProxyType (objekt) (BIM ÜBN + Archicad Classification)
AR_ÜLD - 001_Nimetus: Varjestus-varjualune; 009_Märkus: 1. korruse lõuna ja põhja fassaadi välisuste kohal. vt. skeemi joonisel. vt. täpsemalt EK-osa ja AR-7 sõlmlahendusi
AC_Pset_RenovationAndPhasing - Renovation Status: New

# IfcBuildingElementProxy: FSV-11
In: Katus
Classification: 1.02 IfcBuildingElementProxyType (objekt) (BIM ÜBN + Archicad Classification)
AR_ÜLD - 001_Nimetus: Varjestus-varjualune; 009_Märkus: 2. korruse lõuna fassaadi akna kohal. vt. skeemi joonisel. vt. täpsemalt EK-osa ja AR-7 sõlmlahendusi
AC_Pset_RenovationAndPhasing - Renovation Status: New

# IfcBuildingElementProxy: FSV-12
In: Teine korrus
Classification: 1.02 IfcBuildingElementProxyType (objekt) (BIM ÜBN + Archicad Classification)
AR_ÜLD - 001_Nimetus: Varjestus-varjualune; 009_Märkus: 1. korruse ida fassaadi välisukse kohal. vt. skeemi joonisel. vt. täpsemalt EK-osa ja AR-7 sõlmlahendusi
AC_Pset_RenovationAndPhasing - Renovation Status: New

# IfcBuildingElementProxy: IfcBuildingElementProxy (5)
AC_Pset_RenovationAndPhasing - Renovation Status: New
Name | In | Material
TT KONSTRUKTSIOON - 009 | Esimene korrus | 30 Konst: Raudbetoon monteeritav
TT KONSTRUKTSIOON - 009 | Esimene korrus | 30 Konst: Raudbetoon monoliitne
TT KONSTRUKTSIOON - 010 | Esimene korrus | 30 Konst: Raudbetoon monoliitne
TT KONSTRUKTSIOON - 010 | Teine korrus | 30 Konst: Raudbetoon monteeritav
TT KONSTRUKTSIOON - 009 | Teine korrus | 30 Konst: Raudbetoon monoliitne

# IfcBuildingElementProxy: JUNG LS 990 1-gang (89)
Classification: 1.09 IfcDiscreteAccessoryType (tarvik) (RKAS BIM + ARCHICAD Classification)
AC_Pset_RenovationAndPhasing - Renovation Status: New
Name | In
17 x MÖÖBEL | Esimene korrus
2 x Pistik fööni jaoks | Esimene korrus
70 x MÖÖBEL | Teine korrus

# IfcBuildingElementProxy: JUNG LS 990 2-gang (84)
AC_Pset_RenovationAndPhasing - Renovation Status: New
Name | In | Classification
26 x MÖÖBEL | Esimene korrus | 1.09 IfcDiscreteAccessoryType (tarvik) (RKAS BIM + ARCHICAD Classification)
57 x MÖÖBEL | Teine korrus | 1.09 IfcDiscreteAccessoryType (tarvik) (RKAS BIM + ARCHICAD Classification)
MÖÖBEL | Teine korrus

# IfcBuildingElementProxy: JUNG LS 990 3-gang (17)
Classification: 1.09 IfcDiscreteAccessoryType (tarvik) (RKAS BIM + ARCHICAD Classification)
AC_Pset_RenovationAndPhasing - Renovation Status: New
Name | In
3 x MÖÖBEL | Esimene korrus
14 x MÖÖBEL | Teine korrus

# IfcBuildingElementProxy: JUNG LS 990 4-gang (11)
AC_Pset_RenovationAndPhasing - Renovation Status: New
Name | In | Classification
5 x MÖÖBEL | Esimene korrus
6 x MÖÖBEL | Teine korrus | 1.09 IfcDiscreteAccessoryType (tarvik) (RKAS BIM + ARCHICAD Classification)

# IfcBuildingElementProxy: JUNG LS 990 5-gang, MÖÖBEL
In: Esimene korrus
Classification: 1.09 IfcDiscreteAccessoryType (tarvik) (RKAS BIM + ARCHICAD Classification)
AC_Pset_RenovationAndPhasing - Renovation Status: New

# IfcBuildingElementProxy: Parapeti plekk R1 424 x 154 (2)
In: Teine korrus
Classification: 1.02 IfcBuildingElementProxyType (objekt) (BIM ÜBN + Archicad Classification)
AR_ÜLD - 001_Nimetus: Parapeti plekk
AC_Pset_RenovationAndPhasing - Renovation Status: New

# IfcBuildingElementProxy: Seinapaneel 13x12 b (2)
In: Teine korrus
AC_Pset_RenovationAndPhasing - Renovation Status: New

# IfcBuildingElementProxy: Venetian Blind 26, K-02
In: Teine korrus
AR_001-002 - 001_Nimetus: Kabineti poolpimendav ruloo
AC_Pset_RenovationAndPhasing - Renovation Status: Existing

# IfcColumn: 30 Konst: Teras - Konstruktsioon 140 x 140 (5)
In: Esimene korrus
Type - PredefinedType: COLUMN
Classification: 1.03 IfcColumnType (post) (BIM ÜBN + Archicad Classification); Material: 30 Konst: Teras - Konstruktsioon
Pset_ColumnCommon - Slope: 90 deg; IsExternal: yes; LoadBearing: yes; Reference: 30 Konst: Teras - Konstruktsioon 140 x 140
AR_ÜLD - 001_Nimetus: Kandepost
AC_Pset_RenovationAndPhasing - Renovation Status: New

# IfcColumn: 40 Kiht: Teras 180 x 180, S-04
In: Teine korrus
Type - PredefinedType: COLUMN
Classification: 1.03 IfcColumnType (post) (BIM ÜBN + Archicad Classification); Material: 40 Kiht: Teras
Pset_ColumnCommon - Slope: 90 deg; Reference: 40 Kiht: Teras 180 x 180
AR_ÜLD - 009_Märkus: OMA märkus
AC_Pset_RenovationAndPhasing - Renovation Status: New

# IfcColumn: Steel Universal Section 140 x 133 (4)
In: Esimene korrus
Type - PredefinedType: COLUMN
Classification: 1.03 IfcColumnType (post) (BIM ÜBN + Archicad Classification); Material: 30 Konst: Teras - Konstruktsioon
AR_ÜLD - 001_Nimetus: Kandepost
AC_Pset_RenovationAndPhasing - Renovation Status: New
Pset_ColumnCommon - Slope: 90 deg; IsExternal: yes; LoadBearing: yes; Reference: Steel Universal Section 140 x 133

# IfcCovering: 40 Kiht: Teras - Roostevaba 5, S-01.2
In: Esimene korrus
Type - PredefinedType: CLADDING
Classification: 1.05 IfcCoveringType.CLADDING (seina viimistlus) (BIM ÜBN + Archicad Classification); Material: 40 Kiht: Teras - Roostevaba
AR_ÜLD - 001_Nimetus: Puhasvuuk sein, värvitud helehalliks.
AR_ABI - 200_Materjal (MUDELIS): 40 Kiht: Teras - Roostevaba
AR_Viimistlus - 001_Nimetus: Puhasvuuk sein, värvitud helehalliks.; 200_Materjal: 40 Kiht: Teras - Roostevaba; 205_Tähis: S-01.2; 215_Tuletundlikkus: -; 220_Viimistlus: Jura 60 L88C1 H92; 230_Niiskuskindel: no; 900_Tootja: Caparol; 905_Mudel: Amphibolin; 910_Tooteinfo: ootel; 915_Kasutus-ja-hooldusjuhend: ootel; 240_Märghõõrdekindlus: ootel; 245_Aluspind: ootel; 225_Pindala: 4.784 m2; 210_Paksus: 5 mm
Pset_CoveringCommon - Reference: S-01.2; Material: 40 Kiht: Teras - Roostevaba; TotalThickness: 5 mm
AC_Pset_RenovationAndPhasing - Renovation Status: New

# IfcCovering: 45 Konst: Puit 01 126 x 40 (5)
In: Teine korrus
Type - PredefinedType: CLADDING
Classification: 1.05 IfcCoveringType.CLADDING (seina viimistlus) (BIM ÜBN + Archicad Classification); Material: 45 Konst: Puit 01
Pset_CoveringCommon - Reference: S-08b; Material: 45 Konst: Puit 01
AR_Viimistlus - 001_Nimetus: Ristkihtpuitpaneel (dold) 19 mm; 200_Materjal: 45 Konst: Puit 01; 205_Tähis: S-08b; 215_Tuletundlikkus: -; 220_Viimistlus: valge tooniv õlivaha Osmo 3111.; 230_Niiskuskindel: no; 900_Tootja: Dold Puidutööstus; 905_Mudel: -; 910_Tooteinfo: ootel; 915_Kasutus-ja-hooldusjuhend: ootel; 240_Märghõõrdekindlus: ootel; 245_Aluspind: ootel; 210_Paksus: 126 mm
AR_ÜLD - 001_Nimetus: Ristkihtpuitpaneel (dold) 19 mm; 009_Märkus: OMA märkus
AR_ABI - 200_Materjal (MUDELIS): 45 Konst: Puit 01
AC_Pset_RenovationAndPhasing - Renovation Status: New

# IfcCovering: 45 Konst: Puit 01 160 x 40, S-08b
In: Teine korrus
Type - PredefinedType: CLADDING
Classification: 1.05 IfcCoveringType.CLADDING (seina viimistlus) (BIM ÜBN + Archicad Classification); Material: 45 Konst: Puit 01
AR_Viimistlus - 001_Nimetus: Ristkihtpuitpaneel (dold) 19 mm; 200_Materjal: 45 Konst: Puit 01; 205_Tähis: S-08b; 215_Tuletundlikkus: -; 220_Viimistlus: valge tooniv õlivaha Osmo 3111.; 230_Niiskuskindel: no; 900_Tootja: Dold Puidutööstus; 905_Mudel: -; 910_Tooteinfo: ootel; 915_Kasutus-ja-hooldusjuhend: ootel; 240_Märghõõrdekindlus: ootel; 245_Aluspind: ootel; 210_Paksus: 160 mm
Pset_CoveringCommon - Reference: S-08b; Material: 45 Konst: Puit 01
AC_Pset_RenovationAndPhasing - Renovation Status: New
AR_ÜLD - 001_Nimetus: Ristkihtpuitpaneel (dold) 19 mm; 009_Märkus: OMA märkus
AR_ABI - 200_Materjal (MUDELIS): 45 Konst: Puit 01

# IfcCovering: 45 Konst: Puit 01 210 x 10 (2)
In: Esimene korrus
Type - PredefinedType: CLADDING
Classification: 1.05 IfcCoveringType.CLADDING (seina viimistlus) (BIM ÜBN + Archicad Classification); Material: 45 Konst: Puit 01
Pset_CoveringCommon - Reference: S-8b; Material: 45 Konst: Puit 01
AR_Viimistlus - 001_Nimetus: Uksepale, tume; 200_Materjal: 45 Konst: Puit 01; 205_Tähis: S-8b; 215_Tuletundlikkus: -; 220_Viimistlus: Matt must; 230_Niiskuskindel: no; 900_Tootja: Eritellimus; 905_Mudel: -; 910_Tooteinfo: ootel; 915_Kasutus-ja-hooldusjuhend: ootel; 240_Märghõõrdekindlus: ootel; 245_Aluspind: ootel; 210_Paksus: 210 mm
AR_ÜLD - 001_Nimetus: Uksepale, tume; 009_Märkus: OMA märkus
AR_ABI - 200_Materjal (MUDELIS): 45 Konst: Puit 01
AC_Pset_RenovationAndPhasing - Renovation Status: New

# IfcCovering: 45 Konst: Puit 01 227 x 20, S-08b
In: Teine korrus
Type - PredefinedType: CLADDING
Classification: 1.05 IfcCoveringType.CLADDING (seina viimistlus) (BIM ÜBN + Archicad Classification); Material: 45 Konst: Puit 01
Pset_CoveringCommon - Reference: S-08b; Material: 45 Konst: Puit 01
AR_Viimistlus - 001_Nimetus: Ristkihtpuitpaneel (dold) 19 mm; 200_Materjal: 45 Konst: Puit 01; 205_Tähis: S-08b; 215_Tuletundlikkus: -; 220_Viimistlus: valge tooniv õlivaha Osmo 3111.; 230_Niiskuskindel: no; 900_Tootja: Dold Puidutööstus; 905_Mudel: -; 910_Tooteinfo: ootel; 915_Kasutus-ja-hooldusjuhend: ootel; 240_Märghõõrdekindlus: ootel; 245_Aluspind: ootel; 210_Paksus: 227 mm
AR_ÜLD - 001_Nimetus: Ristkihtpuitpaneel (dold) 19 mm; 009_Märkus: OMA märkus
AR_ABI - 200_Materjal (MUDELIS): 45 Konst: Puit 01
AC_Pset_RenovationAndPhasing - Renovation Status: New

# IfcCovering: 45 Konst: Puit 01 260 x 20 (4)
In: Teine korrus
Type - PredefinedType: CLADDING
Classification: 1.05 IfcCoveringType.CLADDING (seina viimistlus) (BIM ÜBN + Archicad Classification); Material: 45 Konst: Puit 01
Pset_CoveringCommon - Reference: S-08b; Material: 45 Konst: Puit 01
AR_Viimistlus - 001_Nimetus: Ristkihtpuitpaneel (dold) 19 mm; 200_Materjal: 45 Konst: Puit 01; 205_Tähis: S-08b; 215_Tuletundlikkus: -; 220_Viimistlus: valge tooniv õlivaha Osmo 3111.; 230_Niiskuskindel: no; 900_Tootja: Dold Puidutööstus; 905_Mudel: -; 910_Tooteinfo: ootel; 915_Kasutus-ja-hooldusjuhend: ootel; 240_Märghõõrdekindlus: ootel; 245_Aluspind: ootel; 210_Paksus: 260 mm
AR_ABI - 200_Materjal (MUDELIS): 45 Konst: Puit 01
AC_Pset_RenovationAndPhasing - Renovation Status: New
AR_ÜLD - 001_Nimetus: Ristkihtpuitpaneel (dold) 19 mm; 009_Märkus: OMA märkus

# IfcCovering: 45 Konst: Puit 01 261 x 1, S-8b
In: Esimene korrus
Type - PredefinedType: CLADDING
Classification: 1.05 IfcCoveringType.CLADDING (seina viimistlus) (BIM ÜBN + Archicad Classification); Material: 45 Konst: Puit 01
Pset_CoveringCommon - Reference: S-8b; Material: 45 Konst: Puit 01
AR_Viimistlus - 001_Nimetus: Uksepale, tume; 200_Materjal: 45 Konst: Puit 01; 205_Tähis: S-8b; 215_Tuletundlikkus: -; 220_Viimistlus: Matt must; 230_Niiskuskindel: no; 900_Tootja: Eritellimus; 905_Mudel: -; 910_Tooteinfo: ootel; 915_Kasutus-ja-hooldusjuhend: ootel; 240_Märghõõrdekindlus: ootel; 245_Aluspind: ootel; 210_Paksus: 261 mm
AR_ABI - 200_Materjal (MUDELIS): 45 Konst: Puit 01
AC_Pset_RenovationAndPhasing - Renovation Status: New
AR_ÜLD - 001_Nimetus: Uksepale, tume; 009_Märkus: OMA märkus

# IfcCovering: 45 Konst: Puit 01 298 x 20 (2)
In: Teine korrus
Type - PredefinedType: CLADDING
Classification: 1.05 IfcCoveringType.CLADDING (seina viimistlus) (BIM ÜBN + Archicad Classification); Material: 45 Konst: Puit 01
AR_ABI - 200_Materjal (MUDELIS): 45 Konst: Puit 01
AC_Pset_RenovationAndPhasing - Renovation Status: New
AR_ÜLD - 001_Nimetus: Ristkihtpuitpaneel (dold) 19 mm; 009_Märkus: OMA märkus
Pset_CoveringCommon - Reference: S-08b; Material: 45 Konst: Puit 01
AR_Viimistlus - 001_Nimetus: Ristkihtpuitpaneel (dold) 19 mm; 200_Materjal: 45 Konst: Puit 01; 205_Tähis: S-08b; 215_Tuletundlikkus: -; 220_Viimistlus: valge tooniv õlivaha Osmo 3111.; 230_Niiskuskindel: no; 900_Tootja: Dold Puidutööstus; 905_Mudel: -; 910_Tooteinfo: ootel; 915_Kasutus-ja-hooldusjuhend: ootel; 240_Märghõõrdekindlus: ootel; 245_Aluspind: ootel; 210_Paksus: 298 mm

# IfcCovering: 45 Konst: Puit 01 40 x 20 (1344)
Type - PredefinedType: CEILING
Classification: 1.04 IfcCoveringType.CEILING (ripplagi) (BIM ÜBN + Archicad Classification); Material: 45 Konst: Puit 01
Pset_CoveringCommon - Reference: L-03a; Material: 45 Konst: Puit 01
AR_Viimistlus - 001_Nimetus: Puitribilagi; 200_Materjal: 45 Konst: Puit 01; 205_Tähis: L-03a; 215_Tuletundlikkus: C-s2,d1; 220_Viimistlus: 1 kiht valge tooniv õlivaha Osmo 3111; 230_Niiskuskindel: no; 235_Karkass: CD-kandekarkass 27mm; 900_Tootja: IWS; 905_Mudel: Linear 20C; 910_Tooteinfo: ootel; 915_Kasutus-ja-hooldusjuhend: ootel; 210_Paksus: 40 mm
AR_ÜLD - 001_Nimetus: Puitribilagi; 009_Märkus: OMA märkus
AR_ABI - 200_Materjal (MUDELIS): 45 Konst: Puit 01
AC_Pset_RenovationAndPhasing - Renovation Status: New
Name | In
580 x L-03a | Esimene korrus
764 x L-03a | Teine korrus

# IfcCovering: 45 Konst: Puit 01 41 x 20 (8)
Type - PredefinedType: CEILING
Classification: 1.04 IfcCoveringType.CEILING (ripplagi) (BIM ÜBN + Archicad Classification); Material: 45 Konst: Puit 01
Pset_CoveringCommon - Reference: L-03a; Material: 45 Konst: Puit 01
AR_Viimistlus - 001_Nimetus: Puitribilagi; 200_Materjal: 45 Konst: Puit 01; 205_Tähis: L-03a; 215_Tuletundlikkus: C-s2,d1; 220_Viimistlus: 1 kiht valge tooniv õlivaha Osmo 3111; 230_Niiskuskindel: no; 235_Karkass: CD-kandekarkass 27mm; 900_Tootja: IWS; 905_Mudel: Linear 20C; 910_Tooteinfo: ootel; 915_Kasutus-ja-hooldusjuhend: ootel; 210_Paksus: 41 mm
AR_ÜLD - 001_Nimetus: Puitribilagi; 009_Märkus: OMA märkus
AR_ABI - 200_Materjal (MUDELIS): 45 Konst: Puit 01
AC_Pset_RenovationAndPhasing - Renovation Status: New
Name | In
2 x L-03a | Esimene korrus
6 x L-03a | Teine korrus

# IfcCovering: 45 Konst: puit hor 50 x 1, Tala: puitprofiil
In: Esimene korrus
Type - PredefinedType: CLADDING
Classification: 1.05 IfcCoveringType.CLADDING (seina viimistlus) (BIM ÜBN + Archicad Classification); Material: 45 Konst: puit hor
Pset_CoveringCommon - Reference: Tala: puitprofiil; Material: 45 Konst: puit hor
AR_Viimistlus - 001_Nimetus: Märgitus; 200_Materjal: 45 Konst: puit hor; 205_Tähis: Tala: puitprofiil; 215_Tuletundlikkus: -; 220_Viimistlus: ootel; 230_Niiskuskindel: no; 900_Tootja: ootel; 905_Mudel: ootel; 910_Tooteinfo: ootel; 915_Kasutus-ja-hooldusjuhend: ootel; 240_Märghõõrdekindlus: ootel; 245_Aluspind: ootel; 210_Paksus: 50 mm
AR_ÜLD - 001_Nimetus: Märgitus; 009_Märkus: OMA märkus
AR_ABI - 200_Materjal (MUDELIS): 45 Konst: puit hor
AC_Pset_RenovationAndPhasing - Renovation Status: New

# IfcCovering: 60 Plaat: liimpuitplaat 41 (4)
In: Teine korrus
Type - PredefinedType: CLADDING
Classification: 1.05 IfcCoveringType.CLADDING (seina viimistlus) (BIM ÜBN + Archicad Classification); Material: 60 Plaat: liimpuitplaat
Pset_CoveringCommon - Reference: S-08b; Material: 60 Plaat: liimpuitplaat; TotalThickness: 41 mm
AR_Viimistlus - 001_Nimetus: Ristkihtpuitpaneel (dold) 19 mm; 200_Materjal: 60 Plaat: liimpuitplaat; 205_Tähis: S-08b; 215_Tuletundlikkus: -; 220_Viimistlus: valge tooniv õlivaha Osmo 3111.; 230_Niiskuskindel: no; 900_Tootja: Dold Puidutööstus; 905_Mudel: -; 910_Tooteinfo: ootel; 915_Kasutus-ja-hooldusjuhend: ootel; 240_Märghõõrdekindlus: ootel; 245_Aluspind: ootel; 210_Paksus: 41 mm
AR_ÜLD - 001_Nimetus: Ristkihtpuitpaneel (dold) 19 mm; 009_Märkus: OMA märkus
AR_ABI - 200_Materjal (MUDELIS): 60 Plaat: liimpuitplaat
AC_Pset_RenovationAndPhasing - Renovation Status: New
Name | 225_Pindala (m2)
S-08b | 18.1883
S-08b | 2.1966
S-08b | 2.27052
S-08b | 16.4077

# IfcCovering: 70 Kiht: Õhkvahe karkass 12, L-03c
In: Esimene korrus
Type - PredefinedType: CEILING
Classification: 1.04 IfcCoveringType.CEILING (ripplagi) (BIM ÜBN + Archicad Classification); Material: 70 Kiht: Õhkvahe karkass
Pset_CoveringCommon - Reference: L-03c; Material: 70 Kiht: Õhkvahe karkass; TotalThickness: 12 mm
AR_Viimistlus - 001_Nimetus: Puitribilae karkass; 200_Materjal: 70 Kiht: Õhkvahe karkass; 205_Tähis: L-03c; 215_Tuletundlikkus: -; 220_Viimistlus: ootel; 230_Niiskuskindel: no; 235_Karkass: -; 900_Tootja: ootel; 905_Mudel: ootel; 910_Tooteinfo: ootel; 915_Kasutus-ja-hooldusjuhend: ootel; 225_Pindala: 28.7259 m2; 210_Paksus: 12 mm
AR_ÜLD - 001_Nimetus: Puitribilae karkass; 009_Märkus: OMA märkus
AC_Pset_RenovationAndPhasing - Renovation Status: New
AR_ABI - 200_Materjal (MUDELIS): 70 Kiht: Õhkvahe karkass

# IfcCovering: 70 Kiht: Õhkvahe karkass 40, L-03b
In: Teine korrus
Type - PredefinedType: CEILING
Classification: 1.04 IfcCoveringType.CEILING (ripplagi) (BIM ÜBN + Archicad Classification); Material: 70 Kiht: Õhkvahe karkass
Pset_CoveringCommon - Reference: L-03b; Material: 70 Kiht: Õhkvahe karkass; TotalThickness: 40 mm
AR_Viimistlus - 001_Nimetus: Akustline villaplaat 40 mm, must.; 200_Materjal: 70 Kiht: Õhkvahe karkass; 205_Tähis: L-03b; 215_Tuletundlikkus: A2-s1,d0; 220_Viimistlus: Must; 230_Niiskuskindel: no; 235_Karkass: -; 900_Tootja: Ecophon; 905_Mudel: Industry; 910_Tooteinfo: ootel; 915_Kasutus-ja-hooldusjuhend: ootel; 225_Pindala: 93.0149 m2; 210_Paksus: 40 mm
AR_ÜLD - 001_Nimetus: Akustline villaplaat 40 mm, must.; 009_Märkus: OMA märkus
AR_ABI - 200_Materjal (MUDELIS): 70 Kiht: Õhkvahe karkass
AC_Pset_RenovationAndPhasing - Renovation Status: New

# IfcCovering: 71 Kiht: MDF 10 (8)
In: Esimene korrus
Type - PredefinedType: CLADDING
Classification: 1.05 IfcCoveringType.CLADDING (seina viimistlus) (BIM ÜBN + Archicad Classification); Material: 71 Kiht: MDF
Pset_CoveringCommon - Material: 71 Kiht: MDF; TotalThickness: 10 mm
AR_ABI - 200_Materjal (MUDELIS): 71 Kiht: MDF
AC_Pset_RenovationAndPhasing - Renovation Status: New
AR_Viimistlus - 200_Materjal: 71 Kiht: MDF; 215_Tuletundlikkus: -; 230_Niiskuskindel: no; 905_Mudel: -; 910_Tooteinfo: ootel; 915_Kasutus-ja-hooldusjuhend: ootel; 240_Märghõõrdekindlus: ootel; 245_Aluspind: ootel; 210_Paksus: 10 mm
Name | Reference = 205_Tähis | AR_ÜLD, 001_Nimetus = AR_Viimistlus, 001_Nimetus | 220_Viimistlus | 900_Tootja | 225_Pindala (m2)
2 x S-08b | S-08b | Ristkihtpuitpaneel (dold) 19 mm | valge tooniv õlivaha Osmo 3111. | Dold Puidutööstus | 0.7518
3 x S-8b | S-8b | Uksepale, tume | Matt must | Eritellimus | 0.61539
S-8b | S-8b | Uksepale, tume | Matt must | Eritellimus | 0.6182
2 x S-8b | S-8b | Uksepale, tume | Matt must | Eritellimus | 0.4599

# IfcCovering: 71 Kiht: MDF 20 (14)
Type - PredefinedType: CLADDING
Classification: 1.05 IfcCoveringType.CLADDING (seina viimistlus) (BIM ÜBN + Archicad Classification); Material: 71 Kiht: MDF
Pset_CoveringCommon - Reference: S-08b; Material: 71 Kiht: MDF; TotalThickness: 20 mm
AR_Viimistlus - 001_Nimetus: Ristkihtpuitpaneel (dold) 19 mm; 200_Materjal: 71 Kiht: MDF; 205_Tähis: S-08b; 215_Tuletundlikkus: -; 220_Viimistlus: valge tooniv õlivaha Osmo 3111.; 230_Niiskuskindel: no; 900_Tootja: Dold Puidutööstus; 905_Mudel: -; 910_Tooteinfo: ootel; 915_Kasutus-ja-hooldusjuhend: ootel; 240_Märghõõrdekindlus: ootel; 245_Aluspind: ootel; 210_Paksus: 20 mm
AR_ÜLD - 001_Nimetus: Ristkihtpuitpaneel (dold) 19 mm
AC_Pset_RenovationAndPhasing - Renovation Status: New
AR_ABI - 200_Materjal (MUDELIS): 71 Kiht: MDF
Name | In | 225_Pindala (m2)
2 x S-08b | Esimene korrus | 0.7518
2 x S-08b | Teine korrus | 0.90592
8 x S-08b | Teine korrus | 0.7904
2 x S-08b | Teine korrus | 0.49329

# IfcCovering: 71 Kiht: MDF 21, S-02
In: Teine korrus
Type - PredefinedType: CLADDING
Classification: 1.05 IfcCoveringType.CLADDING (seina viimistlus) (BIM ÜBN + Archicad Classification); Material: 71 Kiht: MDF
AR_Viimistlus - 001_Nimetus: Puitribi paneel, musta kangaga; 200_Materjal: 71 Kiht: MDF; 205_Tähis: S-02; 215_Tuletundlikkus: -; 220_Viimistlus: ootel; 230_Niiskuskindel: no; 900_Tootja: IWS; 905_Mudel: ootel; 910_Tooteinfo: ootel; 915_Kasutus-ja-hooldusjuhend: ootel; 240_Märghõõrdekindlus: ootel; 245_Aluspind: ootel; 225_Pindala: 3.71435 m2; 210_Paksus: 21 mm
AR_ÜLD - 001_Nimetus: Puitribi paneel, musta kangaga
Pset_CoveringCommon - Reference: S-02; Material: 71 Kiht: MDF; TotalThickness: 21 mm
AC_Pset_RenovationAndPhasing - Renovation Status: New
AR_ABI - 200_Materjal (MUDELIS): 71 Kiht: MDF

# IfcCovering: 71 Kiht: MDF 40 (3)
In: Teine korrus
Type - PredefinedType: CLADDING
Classification: 1.05 IfcCoveringType.CLADDING (seina viimistlus) (BIM ÜBN + Archicad Classification); Material: 71 Kiht: MDF
Pset_CoveringCommon - Reference: S-08b; Material: 71 Kiht: MDF; TotalThickness: 40 mm
AR_Viimistlus - 001_Nimetus: Ristkihtpuitpaneel (dold) 19 mm; 200_Materjal: 71 Kiht: MDF; 205_Tähis: S-08b; 215_Tuletundlikkus: -; 220_Viimistlus: valge tooniv õlivaha Osmo 3111.; 230_Niiskuskindel: no; 900_Tootja: Dold Puidutööstus; 905_Mudel: -; 910_Tooteinfo: ootel; 915_Kasutus-ja-hooldusjuhend: ootel; 240_Märghõõrdekindlus: ootel; 245_Aluspind: ootel; 210_Paksus: 40 mm
AR_ÜLD - 001_Nimetus: Ristkihtpuitpaneel (dold) 19 mm
AR_ABI - 200_Materjal (MUDELIS): 71 Kiht: MDF
AC_Pset_RenovationAndPhasing - Renovation Status: New
Name | 225_Pindala (m2)
2 x S-08b | 0.63448
S-08b | 0.56916

# IfcCovering: 71 Kiht: MDF 41 (14)
In: Teine korrus
Type - PredefinedType: CLADDING
Classification: 1.05 IfcCoveringType.CLADDING (seina viimistlus) (BIM ÜBN + Archicad Classification); Material: 71 Kiht: MDF
Pset_CoveringCommon - Material: 71 Kiht: MDF; TotalThickness: 41 mm
AR_Viimistlus - 200_Materjal: 71 Kiht: MDF; 215_Tuletundlikkus: -; 230_Niiskuskindel: no; 910_Tooteinfo: ootel; 915_Kasutus-ja-hooldusjuhend: ootel; 240_Märghõõrdekindlus: ootel; 245_Aluspind: ootel; 210_Paksus: 41 mm
AR_ABI - 200_Materjal (MUDELIS): 71 Kiht: MDF
AC_Pset_RenovationAndPhasing - Renovation Status: New
Name | Reference = 205_Tähis | AR_Viimistlus, 001_Nimetus = AR_ÜLD, 001_Nimetus | 220_Viimistlus | 900_Tootja | 905_Mudel | 225_Pindala (m2)
S-08b | S-08b | Ristkihtpuitpaneel (dold) 19 mm | valge tooniv õlivaha Osmo 3111. | Dold Puidutööstus | - | 2.45706
S-08b | S-08b | Ristkihtpuitpaneel (dold) 19 mm | valge tooniv õlivaha Osmo 3111. | Dold Puidutööstus | - | 5.40743
S-08b | S-08b | Ristkihtpuitpaneel (dold) 19 mm | valge tooniv õlivaha Osmo 3111. | Dold Puidutööstus | - | 2.1157
S-08b | S-08b | Ristkihtpuitpaneel (dold) 19 mm | valge tooniv õlivaha Osmo 3111. | Dold Puidutööstus | - | 4.70155
S-08b | S-08b | Ristkihtpuitpaneel (dold) 19 mm | valge tooniv õlivaha Osmo 3111. | Dold Puidutööstus | - | 2.2364
S-08b | S-08b | Ristkihtpuitpaneel (dold) 19 mm | valge tooniv õlivaha Osmo 3111. | Dold Puidutööstus | - | 4.27358
S-08b | S-08b | Ristkihtpuitpaneel (dold) 19 mm | valge tooniv õlivaha Osmo 3111. | Dold Puidutööstus | - | 10.9198
S-02 | S-02 | Puitribi paneel, musta kangaga | Valge tooniv õlivaha Osmo 3111. | IWS | IWS | 4.89118
S-08b | S-08b | Ristkihtpuitpaneel (dold) 19 mm | valge tooniv õlivaha Osmo 3111. | Dold Puidutööstus | - | 2.38776
S-02 | S-02 | Puitribi paneel, musta kangaga | Valge tooniv õlivaha Osmo 3111. | IWS | IWS | 2.3865
S-08b | S-08b | Ristkihtpuitpaneel (dold) 19 mm | valge tooniv õlivaha Osmo 3111. | Dold Puidutööstus | - | 4.5738
S-08b | S-08b | Ristkihtpuitpaneel (dold) 19 mm | valge tooniv õlivaha Osmo 3111. | Dold Puidutööstus | - | 10.6604
S-08b | S-08b | Ristkihtpuitpaneel (dold) 19 mm | valge tooniv õlivaha Osmo 3111. | Dold Puidutööstus | - | 2.4495
S-08b | S-08b | Ristkihtpuitpaneel (dold) 19 mm | valge tooniv õlivaha Osmo 3111. | Dold Puidutööstus | - | 3.6087

# IfcCovering: 71 Kiht: MDF 5 (4)
Type - PredefinedType: CLADDING
Classification: 1.05 IfcCoveringType.CLADDING (seina viimistlus) (BIM ÜBN + Archicad Classification); Material: 71 Kiht: MDF
Pset_CoveringCommon - Material: 71 Kiht: MDF; TotalThickness: 5 mm
AR_Viimistlus - 200_Materjal: 71 Kiht: MDF; 215_Tuletundlikkus: -; 230_Niiskuskindel: no; 910_Tooteinfo: ootel; 915_Kasutus-ja-hooldusjuhend: ootel; 240_Märghõõrdekindlus: ootel; 245_Aluspind: ootel; 210_Paksus: 5 mm
AR_ABI - 200_Materjal (MUDELIS): 71 Kiht: MDF
AC_Pset_RenovationAndPhasing - Renovation Status: New
Name | In | Reference = 205_Tähis | AR_Viimistlus, 001_Nimetus = AR_ÜLD, 001_Nimetus | 220_Viimistlus | 900_Tootja | 905_Mudel | 225_Pindala (m2)
S-8b | Esimene korrus | S-8b | Uksepale, tume | Matt must | Eritellimus | - | 0.539
S-08b | Esimene korrus | S-08b | Ristkihtpuitpaneel (dold) 19 mm | valge tooniv õlivaha Osmo 3111. | Dold Puidutööstus | - | 0.0507381
2 x S-10 | Teine korrus | S-10 | Roheline viltsein 9mm, toon roheline Glade | Glade | Soundtect | Wallpanel | 1.8224

# IfcCovering: 71 Kiht: MDF 9 (4)
In: Teine korrus
Type - PredefinedType: CLADDING
Classification: 1.05 IfcCoveringType.CLADDING (seina viimistlus) (BIM ÜBN + Archicad Classification); Material: 71 Kiht: MDF
Pset_CoveringCommon - Reference: S-10; Material: 71 Kiht: MDF; TotalThickness: 9 mm
AR_ÜLD - 001_Nimetus: Roheline viltsein 9mm, toon roheline Glade
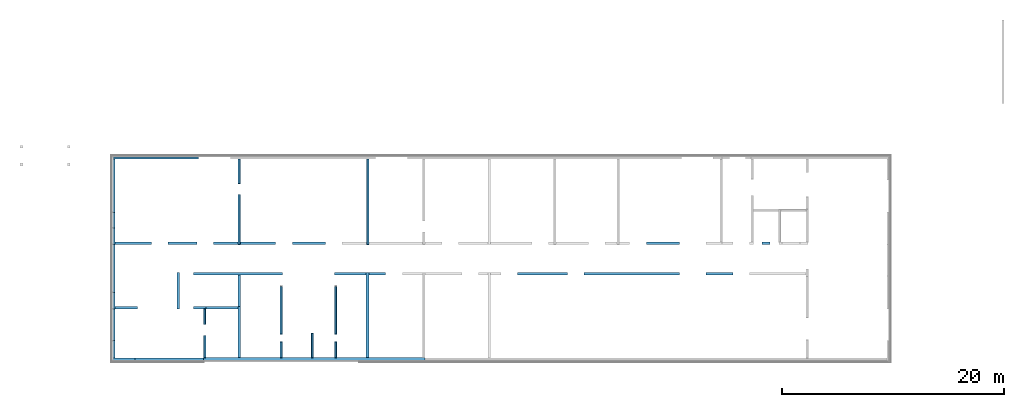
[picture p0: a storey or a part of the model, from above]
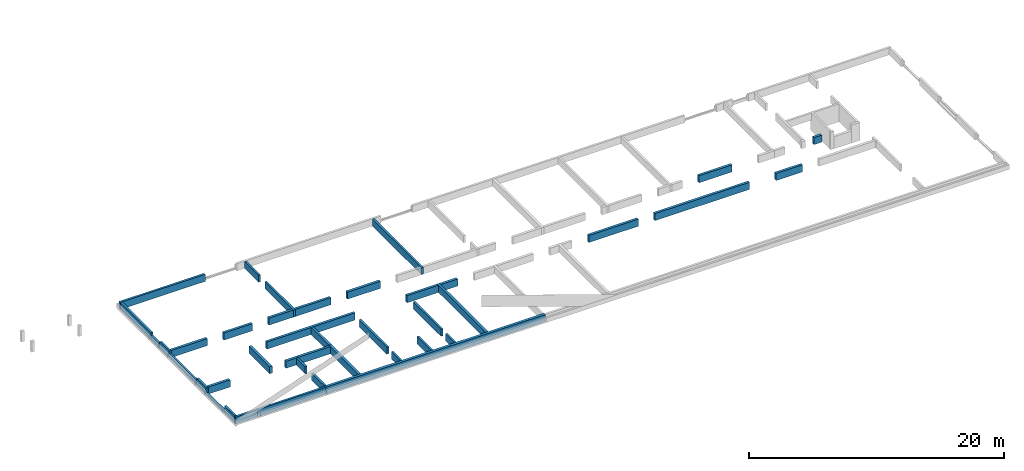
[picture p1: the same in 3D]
Properties of the parts of a building model (IFC2X3), part 2 of 8

# IfcCovering: 71 Kiht: MDF 9 (4)
AR_Viimistlus - 001_Nimetus: Roheline viltsein 9mm, toon roheline Glade; 200_Materjal: 71 Kiht: MDF; 205_Tähis: S-10; 215_Tuletundlikkus: -; 220_Viimistlus: Glade; 230_Niiskuskindel: no; 900_Tootja: Soundtect; 905_Mudel: Wallpanel; 910_Tooteinfo: ootel; 915_Kasutus-ja-hooldusjuhend: ootel; 240_Märghõõrdekindlus: ootel; 245_Aluspind: ootel; 210_Paksus: 9 mm
AR_ABI - 200_Materjal (MUDELIS): 71 Kiht: MDF
AC_Pset_RenovationAndPhasing - Renovation Status: New
Name | 225_Pindala (m2)
2 x S-10 | 1.8224
2 x S-10 | 3.3634

# IfcCovering: 71 Kiht: akustiline plaat 40 (26)
In: Esimene korrus
Type - PredefinedType: CLADDING
Classification: 1.05 IfcCoveringType.CLADDING (seina viimistlus) (BIM ÜBN + Archicad Classification); Material: 71 Kiht: akustiline plaat
AR_Viimistlus - 001_Nimetus: Akustiline paneel; 200_Materjal: 71 Kiht: akustiline plaat; 205_Tähis: S-13; 215_Tuletundlikkus: -; 220_Viimistlus: ootel; 230_Niiskuskindel: no; 900_Tootja: ootel; 905_Mudel: ootel; 910_Tooteinfo: ootel; 915_Kasutus-ja-hooldusjuhend: ootel; 240_Märghõõrdekindlus: ootel; 245_Aluspind: ootel; 210_Paksus: 40 mm
Pset_CoveringCommon - Reference: S-13; Material: 71 Kiht: akustiline plaat; TotalThickness: 40 mm
AR_ABI - 200_Materjal (MUDELIS): 71 Kiht: akustiline plaat
AC_Pset_RenovationAndPhasing - Renovation Status: New
AR_ÜLD - 001_Nimetus: Akustiline paneel
Name | 225_Pindala (m2)
S-13 | 7.9352
S-13 | 27.1544
S-13 | 10.1055
S-13 | 10.8381
S-13 | 2.7573
S-13 | 3.8766
S-13 | 1.30585
S-13 | 4.18145
S-13 | 5.4873
S-13 | 4.6865
S-13 | 0.757081
S-13 | 3.0121
S-13 | 26.067
S-13 | 2.64184
S-13 | 3.9221
S-13 | 5.2052
S-13 | 2.7664
2 x S-13 | 2.67995
S-13 | 2.8847
S-13 | 3.03576
S-13 | 1.54245
S-13 | 3.54925
S-13 | 3.37155
S-13 | 8.49121
S-13 | 2.45336

# IfcCovering: 72 Kiht: veeplekk 110 (2)
In: Katus
Classification: 1.07 IfcCoveringType (pinnadetailid) (BIM ÜBN + Archicad Classification); Material: 72 Kiht: veeplekk
Pset_CoveringCommon - TotalThickness: 110 mm
AR_Viimistlus - 001_Nimetus: KF plekk
AR_ABI - 200_Materjal (MUDELIS): 72 Kiht: veeplekk
AC_Pset_RenovationAndPhasing - Renovation Status: New
AR_ÜLD - 001_Nimetus: KF plekk; 009_Märkus: vt. AR-7 sõlmlahendusi

# IfcCovering: 72 Kiht: veeplekk 185 (7)
In: Katus
Classification: 1.07 IfcCoveringType (pinnadetailid) (BIM ÜBN + Archicad Classification); Material: 72 Kiht: veeplekk
Pset_CoveringCommon - TotalThickness: 185.215 mm
AR_Viimistlus - 001_Nimetus: KF plekk
AR_ABI - 200_Materjal (MUDELIS): 72 Kiht: veeplekk
AC_Pset_RenovationAndPhasing - Renovation Status: New
AR_ÜLD - 001_Nimetus: KF plekk; 009_Märkus: vt. AR-7 sõlmlahendusi

# IfcCovering: 72 Kiht: veeplekk 70 (4)
In: Katus
Classification: 1.07 IfcCoveringType (pinnadetailid) (BIM ÜBN + Archicad Classification); Material: 72 Kiht: veeplekk
Pset_CoveringCommon - TotalThickness: 70 mm
AR_Viimistlus - 001_Nimetus: KF plekk
AR_ÜLD - 001_Nimetus: KF plekk; 009_Märkus: vt. AR-7 sõlmlahendusi
AR_ABI - 200_Materjal (MUDELIS): 72 Kiht: veeplekk
AC_Pset_RenovationAndPhasing - Renovation Status: New

# IfcCovering: 79 Kiht: õhkvahe 12 (3)
In: Esimene korrus
Type - PredefinedType: CEILING
Classification: 1.04 IfcCoveringType.CEILING (ripplagi) (BIM ÜBN + Archicad Classification); Material: 79 Kiht: õhkvahe
Pset_CoveringCommon - Material: 79 Kiht: õhkvahe; TotalThickness: 12 mm
AR_Viimistlus - 200_Materjal: 79 Kiht: õhkvahe; 230_Niiskuskindel: no; 235_Karkass: -; 910_Tooteinfo: ootel; 915_Kasutus-ja-hooldusjuhend: ootel; 210_Paksus: 12 mm
AR_ÜLD - 009_Märkus: OMA märkus
AR_ABI - 200_Materjal (MUDELIS): 79 Kiht: õhkvahe
AC_Pset_RenovationAndPhasing - Renovation Status: New
Name | Reference = 205_Tähis | AR_Viimistlus, 001_Nimetus = AR_ÜLD, 001_Nimetus | 215_Tuletundlikkus | 220_Viimistlus | 900_Tootja | 905_Mudel | 225_Pindala (m2)
L-03b | L-03b | Akustline villaplaat 40 mm, must. | A2-s1,d0 | Must | Ecophon | Industry | 14.9004
L-03c | L-03c | Puitribilae karkass | - | ootel | ootel | ootel | 68.2668
L-03b | L-03b | Akustline villaplaat 40 mm, must. | A2-s1,d0 | Must | Ecophon | Industry | 5.10149

# IfcCovering: 79 Kiht: õhkvahe 12 (3)
In: Esimene korrus
Type - PredefinedType: FLOORING
Classification: 1.06 IfcCoveringType.FLOORING (põrandakatted) (BIM ÜBN + Archicad Classification); Material: 79 Kiht: õhkvahe
Pset_CoveringCommon - Material: 79 Kiht: õhkvahe; TotalThickness: 12 mm
AR_Viimistlus - 001_Nimetus: Nähtav betoon, kaetud tolmutõkkega; 200_Materjal: 79 Kiht: õhkvahe; 215_Tuletundlikkus: -; 220_Viimistlus: ootel; 230_Niiskuskindel: no; 900_Tootja: ootel; 905_Mudel: ootel; 910_Tooteinfo: ootel; 915_Kasutus-ja-hooldusjuhend: ootel; 245_Aluspind: ootel; 210_Paksus: 12 mm
AR_ÜLD - 001_Nimetus: Nähtav betoon, kaetud tolmutõkkega; 009_Märkus: OMA märkus
AR_ABI - 200_Materjal (MUDELIS): 79 Kiht: õhkvahe
AC_Pset_RenovationAndPhasing - Renovation Status: New
Name | Reference = 205_Tähis | 225_Pindala (m2)
L-03c | L-03c | 14.5936
L-03b | L-03b | 7.20726
L-03c | L-03c | 12.7487

# IfcCovering: 79 Kiht: õhkvahe 40 (3)
In: Esimene korrus
Type - PredefinedType: CLADDING
Classification: 1.05 IfcCoveringType.CLADDING (seina viimistlus) (BIM ÜBN + Archicad Classification); Material: 79 Kiht: õhkvahe
AC_Pset_RenovationAndPhasing - Renovation Status: New
AR_ÜLD - 001_Nimetus: Akustiline paneel
AR_Viimistlus - 001_Nimetus: Akustiline paneel; 200_Materjal: 79 Kiht: õhkvahe; 205_Tähis: S-13; 215_Tuletundlikkus: -; 220_Viimistlus: ootel; 230_Niiskuskindel: no; 900_Tootja: ootel; 905_Mudel: ootel; 910_Tooteinfo: ootel; 915_Kasutus-ja-hooldusjuhend: ootel; 240_Märghõõrdekindlus: ootel; 245_Aluspind: ootel; 225_Pindala: 1.2643 m2; 210_Paksus: 40 mm
Pset_CoveringCommon - Reference: S-13; Material: 79 Kiht: õhkvahe; TotalThickness: 40 mm
AR_ABI - 200_Materjal (MUDELIS): 79 Kiht: õhkvahe

# IfcCovering: 80 Siseviim: epo 50 x 1, Tala: puitprofiil
In: Esimene korrus
Type - PredefinedType: FLOORING
Classification: 1.06 IfcCoveringType.FLOORING (põrandakatted) (BIM ÜBN + Archicad Classification); Material: 80 Siseviim: epo
Pset_CoveringCommon - Reference: Tala: puitprofiil; Material: 80 Siseviim: epo
AR_Viimistlus - 200_Materjal: 80 Siseviim: epo; 205_Tähis: Tala: puitprofiil; 215_Tuletundlikkus: -; 220_Viimistlus: ootel; 230_Niiskuskindel: no; 900_Tootja: ootel; 905_Mudel: ootel; 910_Tooteinfo: ootel; 915_Kasutus-ja-hooldusjuhend: ootel; 245_Aluspind: ootel; 210_Paksus: 50 mm
AR_ABI - 200_Materjal (MUDELIS): 80 Siseviim: epo
AC_Pset_RenovationAndPhasing - Renovation Status: New
AR_ÜLD - 009_Märkus: OMA märkus

# IfcCovering: 80 Siseviim: industriaal 20 (16)
In: Teine korrus
Type - PredefinedType: FLOORING
Classification: 1.06 IfcCoveringType.FLOORING (põrandakatted) (BIM ÜBN + Archicad Classification); Material: 80 Siseviim: industriaal
Pset_CoveringCommon - Reference: P-02; Material: 80 Siseviim: industriaal; TotalThickness: 20 mm
AR_Viimistlus - 001_Nimetus: Industriaalparkett tamm rustic, maltspuiduga, paksus 10 mm, laius 8 mm, pikkus 160 mm, liimitud aluspõrandale.; 200_Materjal: 80 Siseviim: industriaal; 205_Tähis: P-02; 215_Tuletundlikkus: -; 220_Viimistlus: Bona Traffic HD 2-kopm.lakiga (2-3 kihti) matt; 230_Niiskuskindel: no; 900_Tootja: Lincona; 905_Mudel: -; 910_Tooteinfo: ootel; 915_Kasutus-ja-hooldusjuhend: ootel; 245_Aluspind: ootel; 210_Paksus: 20 mm
AR_ÜLD - 001_Nimetus: Industriaalparkett tamm rustic, maltspuiduga, paksus 10 mm, laius 8 mm, pikkus 160 mm, liimitud aluspõrandale.; 009_Märkus: OMA märkus
AR_ABI - 200_Materjal (MUDELIS): 80 Siseviim: industriaal
AC_Pset_RenovationAndPhasing - Renovation Status: New
Name | 225_Pindala (m2)
3 x P-02 | 12.7231
P-02 | 12.7729
P-02 | 12.6999
P-02 | 22.781
P-02 | 12.7694
P-02 | 12.9307
P-02 | 49.9788
P-02 | 11.0323
P-02 | 10.7331
P-02 | 10.5336
P-02 | 24.1491
P-02 | 207.15
P-02 | 1.53953
P-02 | 12.8853

# IfcCovering: 80 Siseviim: ker plaat sein 10 (36)
Type - PredefinedType: CLADDING
Classification: 1.05 IfcCoveringType.CLADDING (seina viimistlus) (BIM ÜBN + Archicad Classification); Material: 80 Siseviim: ker plaat sein
Pset_CoveringCommon - Reference: S-03; Material: 80 Siseviim: ker plaat sein; TotalThickness: 10 mm
AR_Viimistlus - 001_Nimetus: Ker. plaat 800x800 mm; 200_Materjal: 80 Siseviim: ker plaat sein; 205_Tähis: S-03; 215_Tuletundlikkus: -; 220_Viimistlus: Lithos white; 230_Niiskuskindel: no; 900_Tootja: Florim; 905_Mudel: Sensi; 910_Tooteinfo: ootel; 915_Kasutus-ja-hooldusjuhend: ootel; 240_Märghõõrdekindlus: ootel; 245_Aluspind: ootel; 210_Paksus: 10 mm
AR_ÜLD - 001_Nimetus: Ker. plaat 800x800 mm
AR_ABI - 200_Materjal (MUDELIS): 80 Siseviim: ker plaat sein
AC_Pset_RenovationAndPhasing - Renovation Status: New
Name | In | 225_Pindala (m2)
S-03 | Esimene korrus | 1.31455
4 x S-03 | Esimene korrus | 5.32804
2 x S-03 | Esimene korrus | 1.81753
2 x S-03 | Esimene korrus | 6.36
2 x S-03 | Esimene korrus | 5.56596
2 x S-03 | Esimene korrus | 8.544
2 x S-03 | Esimene korrus | 5.566
3 x S-03 | Esimene korrus | 1.293
2 x S-03 | Esimene korrus | 1.78793
4 x S-03 | Teine korrus | 1.78805
4 x S-03 | Teine korrus | 1.293
2 x S-03 | Teine korrus | 3.0816
2 x S-03 | Teine korrus | 3.8275
S-03 | Teine korrus | 1.4766
2 x S-03 | Teine korrus | 3.8277
S-03 | Teine korrus | 1.50228

# IfcCovering: 80 Siseviim: kipskrohv 3, S-04.2
In: Teine korrus
Type - PredefinedType: CLADDING
Classification: 1.05 IfcCoveringType.CLADDING (seina viimistlus) (BIM ÜBN + Archicad Classification); Material: 80 Siseviim: kipskrohv
Pset_CoveringCommon - Reference: S-04.2; Material: 80 Siseviim: kipskrohv; TotalThickness: 3 mm
AR_Viimistlus - 001_Nimetus: Krohvitud ja värvitud sein, toon loodusvalge; 200_Materjal: 80 Siseviim: kipskrohv; 205_Tähis: S-04.2; 215_Tuletundlikkus: -; 220_Viimistlus: Jura 60 L 88 C1 H92 (hele-hall); 230_Niiskuskindel: no; 900_Tootja: Caparol; 905_Mudel: Amphibolin; 910_Tooteinfo: ootel; 915_Kasutus-ja-hooldusjuhend: ootel; 240_Märghõõrdekindlus: ootel; 245_Aluspind: ootel; 225_Pindala: 3.77608 m2; 210_Paksus: 3 mm
AR_ÜLD - 001_Nimetus: Krohvitud ja värvitud sein, toon loodusvalge
AR_ABI - 200_Materjal (MUDELIS): 80 Siseviim: kipskrohv
AC_Pset_RenovationAndPhasing - Renovation Status: New

# IfcCovering: 80 Siseviim: kipskrohv 5 (46)
In: Teine korrus
Type - PredefinedType: CLADDING
Classification: 1.05 IfcCoveringType.CLADDING (seina viimistlus) (BIM ÜBN + Archicad Classification); Material: 80 Siseviim: kipskrohv
AR_Viimistlus - 200_Materjal: 80 Siseviim: kipskrohv; 215_Tuletundlikkus: -; 230_Niiskuskindel: no; 910_Tooteinfo: ootel; 915_Kasutus-ja-hooldusjuhend: ootel; 240_Märghõõrdekindlus: ootel; 245_Aluspind: ootel; 210_Paksus: 5 mm
AR_ABI - 200_Materjal (MUDELIS): 80 Siseviim: kipskrohv
Pset_CoveringCommon - Material: 80 Siseviim: kipskrohv; TotalThickness: 5 mm
AC_Pset_RenovationAndPhasing - Renovation Status: New
Name | AR_Viimistlus, 001_Nimetus = AR_ÜLD, 001_Nimetus | 205_Tähis = Reference | 220_Viimistlus | 900_Tootja | 905_Mudel | 225_Pindala (m2)
2 x S-04.2 | Krohvitud ja värvitud sein, toon loodusvalge | S-04.2 | Jura 60 L 88 C1 H92 (hele-hall) | Caparol | Amphibolin | 19.8074
7 x S-04.2 | Krohvitud ja värvitud sein, toon loodusvalge | S-04.2 | Jura 60 L 88 C1 H92 (hele-hall) | Caparol | Amphibolin | 18.6791
3 x S-04.2 | Krohvitud ja värvitud sein, toon loodusvalge | S-04.2 | Jura 60 L 88 C1 H92 (hele-hall) | Caparol | Amphibolin | 11.243
10 x S-04.2 | Krohvitud ja värvitud sein, toon loodusvalge | S-04.2 | Jura 60 L 88 C1 H92 (hele-hall) | Caparol | Amphibolin | 4.49595
S-04.2 | Krohvitud ja värvitud sein, toon loodusvalge | S-04.2 | Jura 60 L 88 C1 H92 (hele-hall) | Caparol | Amphibolin | 18.679
S-04.2 | Krohvitud ja värvitud sein, toon loodusvalge | S-04.2 | Jura 60 L 88 C1 H92 (hele-hall) | Caparol | Amphibolin | 11.2034
6 x S-04.2 | Krohvitud ja värvitud sein, toon loodusvalge | S-04.2 | Jura 60 L 88 C1 H92 (hele-hall) | Caparol | Amphibolin | 11.0623
2 x S-04.2 | Krohvitud ja värvitud sein, toon loodusvalge | S-04.2 | Jura 60 L 88 C1 H92 (hele-hall) | Caparol | Amphibolin | 11.0422
4 x S-04.2 | Krohvitud ja värvitud sein, toon loodusvalge | S-04.2 | Jura 60 L 88 C1 H92 (hele-hall) | Caparol | Amphibolin | 11.1026
S-04.2 | Krohvitud ja värvitud sein, toon loodusvalge | S-04.2 | Jura 60 L 88 C1 H92 (hele-hall) | Caparol | Amphibolin | 10.8407
S-04.2 | Krohvitud ja värvitud sein, toon loodusvalge | S-04.2 | Jura 60 L 88 C1 H92 (hele-hall) | Caparol | Amphibolin | 11.1429
S-04.2 | Krohvitud ja värvitud sein, toon loodusvalge | S-04.2 | Jura 60 L 88 C1 H92 (hele-hall) | Caparol | Amphibolin | 10.6392
S-04.2 | Krohvitud ja värvitud sein, toon loodusvalge | S-04.2 | Jura 60 L 88 C1 H92 (hele-hall) | Caparol | Amphibolin | 16.0797
6 x S-10 | Roheline viltsein 9mm, toon roheline Glade | S-10 | Glade | Soundtect | Wallpanel | 4.131

# IfcCovering: 80 Siseviim: kipskrohv 9 (6)
In: Teine korrus
Type - PredefinedType: CLADDING
Classification: 1.05 IfcCoveringType.CLADDING (seina viimistlus) (BIM ÜBN + Archicad Classification); Material: 80 Siseviim: kipskrohv
Pset_CoveringCommon - Reference: S-10; Material: 80 Siseviim: kipskrohv; TotalThickness: 9 mm
AR_Viimistlus - 001_Nimetus: Roheline viltsein 9mm, toon roheline Glade; 200_Materjal: 80 Siseviim: kipskrohv; 205_Tähis: S-10; 215_Tuletundlikkus: -; 220_Viimistlus: Glade; 230_Niiskuskindel: no; 900_Tootja: Soundtect; 905_Mudel: Wallpanel; 910_Tooteinfo: ootel; 915_Kasutus-ja-hooldusjuhend: ootel; 240_Märghõõrdekindlus: ootel; 245_Aluspind: ootel; 225_Pindala: 4.131 m2; 210_Paksus: 9 mm
AR_ABI - 200_Materjal (MUDELIS): 80 Siseviim: kipskrohv
AR_ÜLD - 001_Nimetus: Roheline viltsein 9mm, toon roheline Glade
AC_Pset_RenovationAndPhasing - Renovation Status: New

# IfcCovering: 80 Siseviim: kiviplaat 20 (14)
Type - PredefinedType: FLOORING
Classification: 1.06 IfcCoveringType.FLOORING (põrandakatted) (BIM ÜBN + Archicad Classification); Material: 80 Siseviim: kiviplaat
Pset_CoveringCommon - Reference: P-04; Material: 80 Siseviim: kiviplaat; TotalThickness: 20 mm
AR_Viimistlus - 001_Nimetus: Ker.plaat 800x800 libisemiskindel R10, tsementvuuk Mapei vuuk plaadi tooni.; 200_Materjal: 80 Siseviim: kiviplaat; 205_Tähis: P-04; 215_Tuletundlikkus: -; 230_Niiskuskindel: no; 900_Tootja: Florim; 905_Mudel: Sensi; 910_Tooteinfo: ootel; 915_Kasutus-ja-hooldusjuhend: ootel; 245_Aluspind: ootel; 210_Paksus: 20 mm
AR_ÜLD - 001_Nimetus: Ker.plaat 800x800 libisemiskindel R10, tsementvuuk Mapei vuuk plaadi tooni.; 009_Märkus: OMA märkus
AC_Pset_RenovationAndPhasing - Renovation Status: New
AR_ABI - 200_Materjal (MUDELIS): 80 Siseviim: kiviplaat
Name | In | 225_Pindala (m2)
P-04 | Esimene korrus | 3.32468
P-04 | Esimene korrus | 13.2762
P-04 | Esimene korrus | 17.8355
P-04 | Esimene korrus | 5.28996
P-04 | Esimene korrus | 7.75443
P-04 | Esimene korrus | 5.61831
P-04 | Esimene korrus | 7.54726
P-04 | Esimene korrus | 4.1933
P-04 | Esimene korrus | 5.64044
2 x P-04 | Teine korrus | 2.0544
2 x P-04 | Teine korrus | 1.79752
P-04 | Teine korrus | 2.42709

# IfcCovering: 80 Siseviim: tolmutõke 20 (13)
In: Teine korrus
Type - PredefinedType: FLOORING
Classification: 1.06 IfcCoveringType.FLOORING (põrandakatted) (BIM ÜBN + Archicad Classification); Material: 80 Siseviim: tolmutõke
Pset_CoveringCommon - Material: 80 Siseviim: tolmutõke; TotalThickness: 20 mm
AR_Viimistlus - 200_Materjal: 80 Siseviim: tolmutõke; 215_Tuletundlikkus: -; 230_Niiskuskindel: no; 900_Tootja: Sika; 910_Tooteinfo: ootel; 915_Kasutus-ja-hooldusjuhend: ootel; 245_Aluspind: ootel; 210_Paksus: 20 mm
AR_ÜLD - 009_Märkus: OMA märkus
AR_ABI - 200_Materjal (MUDELIS): 80 Siseviim: tolmutõke
AC_Pset_RenovationAndPhasing - Renovation Status: New
Name | Reference = 205_Tähis | AR_Viimistlus, 001_Nimetus = AR_ÜLD, 001_Nimetus | 905_Mudel | 225_Pindala (m2)
P-05 | P-05 | Polüretaan põrandakate, paksus 2-3 mm, toon hele-hall RAL 7038 | Sikafloor PS-22 | 19.8631
P-05 | P-05 | Polüretaan põrandakate, paksus 2-3 mm, toon hele-hall RAL 7038 | Sikafloor PS-22 | 98.7294
P-05 | P-05 | Polüretaan põrandakate, paksus 2-3 mm, toon hele-hall RAL 7038 | Sikafloor PS-22 | 58.3573
P-05 | P-05 | Polüretaan põrandakate, paksus 2-3 mm, toon hele-hall RAL 7038 | Sikafloor PS-22 | 21.4653
P-05* | P-05* | Polüretaan kate, R11*, paksus 2-3 mm, toon hele-hall RAL 7038. | Sikafloor PS23 | 84.5918 | AR_Viimistlus - 220_Viimistlus: Akrüülvaigul põhinev kate Sika R11, Casco hüdroisolatsioon2. Sikafloor PS23 süsteem+ klaaskuulid kihi 2-3 mm
P-05 | P-05 | Polüretaan põrandakate, paksus 2-3 mm, toon hele-hall RAL 7038 | Sikafloor PS-22 | 65.1129
P-05 | P-05 | Polüretaan põrandakate, paksus 2-3 mm, toon hele-hall RAL 7038 | Sikafloor PS-22 | 19.8111
P-05 | P-05 | Polüretaan põrandakate, paksus 2-3 mm, toon hele-hall RAL 7038 | Sikafloor PS-22 | 10.5889
P-05 | P-05 | Polüretaan põrandakate, paksus 2-3 mm, toon hele-hall RAL 7038 | Sikafloor PS-22 | 32.4779
P-05 | P-05 | Polüretaan põrandakate, paksus 2-3 mm, toon hele-hall RAL 7038 | Sikafloor PS-22 | 11.2083
P-05 | P-05 | Polüretaan põrandakate, paksus 2-3 mm, toon hele-hall RAL 7038 | Sikafloor PS-22 | 22.8896
P-05 | P-05 | Polüretaan põrandakate, paksus 2-3 mm, toon hele-hall RAL 7038 | Sikafloor PS-22 | 16.9708
P-05 | P-05 | Polüretaan põrandakate, paksus 2-3 mm, toon hele-hall RAL 7038 | Sikafloor PS-22 | 1.87674

# IfcCovering: 80 Siseviim: tolmutõke 5 (29)
Type - PredefinedType: FLOORING
Classification: 1.06 IfcCoveringType.FLOORING (põrandakatted) (BIM ÜBN + Archicad Classification); Material: 80 Siseviim: tolmutõke
Pset_CoveringCommon - Material: 80 Siseviim: tolmutõke; TotalThickness: 5 mm
AR_Viimistlus - 200_Materjal: 80 Siseviim: tolmutõke; 215_Tuletundlikkus: -; 230_Niiskuskindel: no; 910_Tooteinfo: ootel; 915_Kasutus-ja-hooldusjuhend: ootel; 245_Aluspind: ootel; 210_Paksus: 5 mm
AR_ÜLD - 009_Märkus: OMA märkus
AR_ABI - 200_Materjal (MUDELIS): 80 Siseviim: tolmutõke
AC_Pset_RenovationAndPhasing - Renovation Status: New
Name | In | Reference = 205_Tähis | AR_Viimistlus, 001_Nimetus = AR_ÜLD, 001_Nimetus | 220_Viimistlus | 900_Tootja | 905_Mudel | 225_Pindala (m2)
P-01 | Esimene korrus | P-01 | Betoonpõrand lihvitud tasandatud betoon, kaetud põrandaimpegneeriga | ootel | Caparol | Disbopox 443 | 2.534
P-01 | Esimene korrus | P-01 | Betoonpõrand lihvitud tasandatud betoon, kaetud põrandaimpegneeriga | ootel | Caparol | Disbopox 443 | 35.0812
P-01 | Esimene korrus | P-01 | Betoonpõrand lihvitud tasandatud betoon, kaetud põrandaimpegneeriga | ootel | Caparol | Disbopox 443 | 16.302
P-01 | Esimene korrus | P-01 | Betoonpõrand lihvitud tasandatud betoon, kaetud põrandaimpegneeriga | ootel | Caparol | Disbopox 443 | 21.4653
P-01 | Esimene korrus | P-01 | Betoonpõrand lihvitud tasandatud betoon, kaetud põrandaimpegneeriga | ootel | Caparol | Disbopox 443 | 1.60552
P-08 | Esimene korrus | P-08 | Antistaatiline ja ESD põrandakate | Toon: Ivory 550017 | Forbo | Sphera SD | 12.731
2 x P-01 | Esimene korrus | P-01 | Betoonpõrand lihvitud tasandatud betoon, kaetud põrandaimpegneeriga | ootel | Caparol | Disbopox 443 | 41.9814
P-01 | Esimene korrus | P-01 | Betoonpõrand lihvitud tasandatud betoon, kaetud põrandaimpegneeriga | ootel | Caparol | Disbopox 443 | 180.525
P-01 | Esimene korrus | P-01 | Betoonpõrand lihvitud tasandatud betoon, kaetud põrandaimpegneeriga | ootel | Caparol | Disbopox 443 | 1.60541
P-01 | Esimene korrus | P-01 | Betoonpõrand lihvitud tasandatud betoon, kaetud põrandaimpegneeriga | ootel | Caparol | Disbopox 443 | 4.0848
P-01 | Esimene korrus | P-01 | Betoonpõrand lihvitud tasandatud betoon, kaetud põrandaimpegneeriga | ootel | Caparol | Disbopox 443 | 25.0327
P-01 | Esimene korrus | P-01 | Betoonpõrand lihvitud tasandatud betoon, kaetud põrandaimpegneeriga | ootel | Caparol | Disbopox 443 | 126.642
2 x P-01 | Esimene korrus | P-01 | Betoonpõrand lihvitud tasandatud betoon, kaetud põrandaimpegneeriga | ootel | Caparol | Disbopox 443 | 42.3175
P-01 | Esimene korrus | P-01 | Betoonpõrand lihvitud tasandatud betoon, kaetud põrandaimpegneeriga | ootel | Caparol | Disbopox 443 | 42.6163
P-01 | Esimene korrus | P-01 | Betoonpõrand lihvitud tasandatud betoon, kaetud põrandaimpegneeriga | ootel | Caparol | Disbopox 443 | 125.944
P-01 | Esimene korrus | P-01 | Betoonpõrand lihvitud tasandatud betoon, kaetud põrandaimpegneeriga | ootel | Caparol | Disbopox 443 | 40.7862
2 x P-01 | Esimene korrus | P-01 | Betoonpõrand lihvitud tasandatud betoon, kaetud põrandaimpegneeriga | ootel | Caparol | Disbopox 443 | 41.1597
P-01 | Esimene korrus | P-01 | Betoonpõrand lihvitud tasandatud betoon, kaetud põrandaimpegneeriga | ootel | Caparol | Disbopox 443 | 34.3884
P-01 | Esimene korrus | P-01 | Betoonpõrand lihvitud tasandatud betoon, kaetud põrandaimpegneeriga | ootel | Caparol | Disbopox 443 | 7.416
P-01 | Esimene korrus | P-01 | Betoonpõrand lihvitud tasandatud betoon, kaetud põrandaimpegneeriga | ootel | Caparol | Disbopox 443 | 33.8782
P-01 | Esimene korrus | P-01 | Betoonpõrand lihvitud tasandatud betoon, kaetud põrandaimpegneeriga | ootel | Caparol | Disbopox 443 | 41.832
P-01 | Esimene korrus | P-01 | Betoonpõrand lihvitud tasandatud betoon, kaetud põrandaimpegneeriga | ootel | Caparol | Disbopox 443 | 39.2922
P-01 | Esimene korrus | P-01 | Betoonpõrand lihvitud tasandatud betoon, kaetud põrandaimpegneeriga | ootel | Caparol | Disbopox 443 | 14.3901
P-01 | Teine korrus | P-01 | Betoonpõrand lihvitud tasandatud betoon, kaetud põrandaimpegneeriga | ootel | Caparol | Disbopox 443 | 21.1401
P-01 | Teine korrus | P-01 | Betoonpõrand lihvitud tasandatud betoon, kaetud põrandaimpegneeriga | ootel | Caparol | Disbopox 443 | 7.62574
P-01 | Teine korrus | P-01 | Betoonpõrand lihvitud tasandatud betoon, kaetud põrandaimpegneeriga | ootel | Caparol | Disbopox 443 | 56.5479

# IfcCovering: 80 Siseviim: vaipkate 10 (4)
In: Teine korrus
Type - PredefinedType: FLOORING
Classification: 1.06 IfcCoveringType.FLOORING (põrandakatted) (BIM ÜBN + Archicad Classification); Material: 80 Siseviim: vaipkate
AR_Viimistlus - 001_Nimetus: Tufteeritud aasaline plaatvaip. 500x500mm, paksus 6,5 mm, materjal polyester fliis, toon roheline.; 200_Materjal: 80 Siseviim: vaipkate; 205_Tähis: P-03; 215_Tuletundlikkus: -; 220_Viimistlus: ootel; 230_Niiskuskindel: no; 900_Tootja: Tarkett; 905_Mudel: Fields B751 7231; 910_Tooteinfo: ootel; 915_Kasutus-ja-hooldusjuhend: ootel; 245_Aluspind: ootel; 225_Pindala: 1.8225 m2; 210_Paksus: 10 mm
Pset_CoveringCommon - Reference: P-03; Material: 80 Siseviim: vaipkate; TotalThickness: 10 mm
AR_ÜLD - 001_Nimetus: Tufteeritud aasaline plaatvaip. 500x500mm, paksus 6,5 mm, materjal polyester fliis, toon roheline.; 009_Märkus: OMA märkus
AC_Pset_RenovationAndPhasing - Renovation Status: New
AR_ABI - 200_Materjal (MUDELIS): 80 Siseviim: vaipkate

# IfcCovering: 80 Siseviimistlus dold 16 (4)
In: Teine korrus
Type - PredefinedType: CLADDING
Classification: 1.05 IfcCoveringType.CLADDING (seina viimistlus) (BIM ÜBN + Archicad Classification); Material: 80 Siseviimistlus dold
AC_Pset_RenovationAndPhasing - Renovation Status: New
AR_ABI - 200_Materjal (MUDELIS): 80 Siseviimistlus dold
AR_ÜLD - 001_Nimetus: Ristkihtpuitpaneel (dold) 19 mm
AR_Viimistlus - 001_Nimetus: Ristkihtpuitpaneel (dold) 19 mm; 200_Materjal: 80 Siseviimistlus dold; 205_Tähis: S-08b; 215_Tuletundlikkus: -; 220_Viimistlus: valge tooniv õlivaha Osmo 3111.; 230_Niiskuskindel: no; 900_Tootja: Dold Puidutööstus; 905_Mudel: -; 910_Tooteinfo: ootel; 915_Kasutus-ja-hooldusjuhend: ootel; 240_Märghõõrdekindlus: ootel; 245_Aluspind: ootel; 210_Paksus: 16 mm
Pset_CoveringCommon - Reference: S-08b; Material: 80 Siseviimistlus dold; TotalThickness: 16 mm
Name | 225_Pindala (m2)
S-08b | 1.308
3 x S-08b | 1.194

# IfcCovering: 80 Siseviimistlus dold 20 x 126 (2)
In: Teine korrus
Type - PredefinedType: CLADDING
Classification: 1.05 IfcCoveringType.CLADDING (seina viimistlus) (BIM ÜBN + Archicad Classification); Material: 80 Siseviimistlus dold
Pset_CoveringCommon - Reference: S-08b; Material: 80 Siseviimistlus dold
AR_Viimistlus - 001_Nimetus: Ristkihtpuitpaneel (dold) 19 mm; 200_Materjal: 80 Siseviimistlus dold; 205_Tähis: S-08b; 215_Tuletundlikkus: -; 220_Viimistlus: valge tooniv õlivaha Osmo 3111.; 230_Niiskuskindel: no; 900_Tootja: Dold Puidutööstus; 905_Mudel: -; 910_Tooteinfo: ootel; 915_Kasutus-ja-hooldusjuhend: ootel; 240_Märghõõrdekindlus: ootel; 245_Aluspind: ootel; 210_Paksus: 20 mm
AC_Pset_RenovationAndPhasing - Renovation Status: New
AR_ABI - 200_Materjal (MUDELIS): 80 Siseviimistlus dold
AR_ÜLD - 001_Nimetus: Ristkihtpuitpaneel (dold) 19 mm; 009_Märkus: OMA märkus

# IfcCovering: 80 Siseviimistlus dold 20 x 40 (86)
In: Teine korrus
Type - PredefinedType: CLADDING
Classification: 1.05 IfcCoveringType.CLADDING (seina viimistlus) (BIM ÜBN + Archicad Classification); Material: 80 Siseviimistlus dold
Pset_CoveringCommon - Reference: S-02; Material: 80 Siseviimistlus dold
AR_Viimistlus - 001_Nimetus: Puitribi paneel, musta kangaga; 200_Materjal: 80 Siseviimistlus dold; 205_Tähis: S-02; 215_Tuletundlikkus: -; 220_Viimistlus: ootel; 230_Niiskuskindel: no; 900_Tootja: IWS; 905_Mudel: ootel; 910_Tooteinfo: ootel; 915_Kasutus-ja-hooldusjuhend: ootel; 240_Märghõõrdekindlus: ootel; 245_Aluspind: ootel; 210_Paksus: 20 mm
AR_ABI - 200_Materjal (MUDELIS): 80 Siseviimistlus dold
AR_ÜLD - 001_Nimetus: Puitribi paneel, musta kangaga; 009_Märkus: OMA märkus
AC_Pset_RenovationAndPhasing - Renovation Status: New

# IfcCovering: 80 Siseviimistlus dold 21 (13)
Type - PredefinedType: CLADDING
Classification: 1.05 IfcCoveringType.CLADDING (seina viimistlus) (BIM ÜBN + Archicad Classification); Material: 80 Siseviimistlus dold
Pset_CoveringCommon - Material: 80 Siseviimistlus dold; TotalThickness: 21 mm
AR_Viimistlus - 200_Materjal: 80 Siseviimistlus dold; 215_Tuletundlikkus: -; 230_Niiskuskindel: no; 910_Tooteinfo: ootel; 915_Kasutus-ja-hooldusjuhend: ootel; 240_Märghõõrdekindlus: ootel; 245_Aluspind: ootel; 210_Paksus: 21 mm
AR_ABI - 200_Materjal (MUDELIS): 80 Siseviimistlus dold
AC_Pset_RenovationAndPhasing - Renovation Status: New
Name | In | Reference = 205_Tähis | AR_ÜLD, 001_Nimetus = AR_Viimistlus, 001_Nimetus | 220_Viimistlus | 900_Tootja | 905_Mudel | 225_Pindala (m2)
4 x S-02 | Esimene korrus | S-02 | Puitribi paneel, musta kangaga | ootel | IWS | ootel | 1.197
2 x S-02 | Esimene korrus | S-02 | Puitribi paneel, musta kangaga | ootel | IWS | ootel | 1.19574
S-02 | Esimene korrus | S-02 | Puitribi paneel, musta kangaga | ootel | IWS | ootel | 2.30607
S-02 | Esimene korrus | S-02 | Puitribi paneel, musta kangaga | ootel | IWS | ootel | 2.4666
S-05 | Esimene korrus | S-05 | Sikagard AL-12 süsteem, toon antrasiit | RAL 7016 | Sika | AL-12 | 4.9608
2 x S-02 | Esimene korrus | S-02 | Puitribi paneel, musta kangaga | ootel | IWS | ootel | 2.66
S-02 | Teine korrus | S-02 | Puitribi paneel, musta kangaga | ootel | IWS | ootel | 1.60383
S-02 | Teine korrus | S-02 | Puitribi paneel, musta kangaga | ootel | IWS | ootel | 1.59084

# IfcCovering: 80 Siseviimistlus dold 40 x 107 (2)
In: Teine korrus
Type - PredefinedType: CLADDING
Classification: 1.05 IfcCoveringType.CLADDING (seina viimistlus) (BIM ÜBN + Archicad Classification); Material: 80 Siseviimistlus dold
Pset_CoveringCommon - Reference: S-08b; Material: 80 Siseviimistlus dold
AR_ÜLD - 001_Nimetus: Ristkihtpuitpaneel (dold) 19 mm; 009_Märkus: OMA märkus
AR_ABI - 200_Materjal (MUDELIS): 80 Siseviimistlus dold
AC_Pset_RenovationAndPhasing - Renovation Status: New
AR_Viimistlus - 001_Nimetus: Ristkihtpuitpaneel (dold) 19 mm; 200_Materjal: 80 Siseviimistlus dold; 205_Tähis: S-08b; 215_Tuletundlikkus: -; 220_Viimistlus: valge tooniv õlivaha Osmo 3111.; 230_Niiskuskindel: no; 900_Tootja: Dold Puidutööstus; 905_Mudel: -; 910_Tooteinfo: ootel; 915_Kasutus-ja-hooldusjuhend: ootel; 240_Märghõõrdekindlus: ootel; 245_Aluspind: ootel; 210_Paksus: 40 mm

# IfcCovering: 80 Siseviimistlus dold 40 x 126 (12)
In: Teine korrus
Type - PredefinedType: CLADDING
Classification: 1.05 IfcCoveringType.CLADDING (seina viimistlus) (BIM ÜBN + Archicad Classification); Material: 80 Siseviimistlus dold
AR_Viimistlus - 001_Nimetus: Ristkihtpuitpaneel (dold) 19 mm; 200_Materjal: 80 Siseviimistlus dold; 205_Tähis: S-08b; 215_Tuletundlikkus: -; 220_Viimistlus: valge tooniv õlivaha Osmo 3111.; 230_Niiskuskindel: no; 900_Tootja: Dold Puidutööstus; 905_Mudel: -; 910_Tooteinfo: ootel; 915_Kasutus-ja-hooldusjuhend: ootel; 240_Märghõõrdekindlus: ootel; 245_Aluspind: ootel; 210_Paksus: 40 mm
Pset_CoveringCommon - Reference: S-08b; Material: 80 Siseviimistlus dold
AR_ÜLD - 001_Nimetus: Ristkihtpuitpaneel (dold) 19 mm; 009_Märkus: OMA märkus
AR_ABI - 200_Materjal (MUDELIS): 80 Siseviimistlus dold
AC_Pset_RenovationAndPhasing - Renovation Status: New

# IfcCovering: 80 Siseviimistlus dold 40 x 20 (620)
Type - PredefinedType: CLADDING
Classification: 1.05 IfcCoveringType.CLADDING (seina viimistlus) (BIM ÜBN + Archicad Classification); Material: 80 Siseviimistlus dold
Pset_CoveringCommon - Material: 80 Siseviimistlus dold
AR_ABI - 200_Materjal (MUDELIS): 80 Siseviimistlus dold
AC_Pset_RenovationAndPhasing - Renovation Status: New
AR_ÜLD - 001_Nimetus: Puitribi paneel, musta kangaga; 009_Märkus: OMA märkus
AR_Viimistlus - 001_Nimetus: Puitribi paneel, musta kangaga; 200_Materjal: 80 Siseviimistlus dold; 230_Niiskuskindel: no; 910_Tooteinfo: ootel; 915_Kasutus-ja-hooldusjuhend: ootel; 240_Märghõõrdekindlus: ootel; 245_Aluspind: ootel; 210_Paksus: 40 mm
Name | In | Reference = 205_Tähis | 215_Tuletundlikkus | 220_Viimistlus | 900_Tootja | 905_Mudel
168 x S-02 | Esimene korrus | S-02 | - | ootel | IWS | ootel
416 x S-02 | Teine korrus | S-02 | - | ootel | IWS | ootel
8 x S-02 | Teine korrus | S-02 | C-s2,d1 | Valge tooniv õlivaha Osmo 3111. | IWS | IWS
28 x S.02 | Teine korrus | S.02 | - | ootel | ootel | ootel

# IfcCovering: 80 Siseviimistlus dold 41 (14)
In: Teine korrus
Type - PredefinedType: CLADDING
Classification: 1.05 IfcCoveringType.CLADDING (seina viimistlus) (BIM ÜBN + Archicad Classification); Material: 80 Siseviimistlus dold
AR_Viimistlus - 200_Materjal: 80 Siseviimistlus dold; 215_Tuletundlikkus: -; 230_Niiskuskindel: no; 910_Tooteinfo: ootel; 915_Kasutus-ja-hooldusjuhend: ootel; 240_Märghõõrdekindlus: ootel; 245_Aluspind: ootel; 210_Paksus: 41 mm
Pset_CoveringCommon - Material: 80 Siseviimistlus dold; TotalThickness: 41 mm
AC_Pset_RenovationAndPhasing - Renovation Status: New
AR_ABI - 200_Materjal (MUDELIS): 80 Siseviimistlus dold
Name | AR_Viimistlus, 001_Nimetus = AR_ÜLD, 001_Nimetus | 205_Tähis = Reference | 220_Viimistlus | 900_Tootja | 905_Mudel | 225_Pindala (m2)
S-08b | Ristkihtpuitpaneel (dold) 19 mm | S-08b | valge tooniv õlivaha Osmo 3111. | Dold Puidutööstus | - | 12.3489
S-08b | Ristkihtpuitpaneel (dold) 19 mm | S-08b | valge tooniv õlivaha Osmo 3111. | Dold Puidutööstus | - | 3.66153
S-08b | Ristkihtpuitpaneel (dold) 19 mm | S-08b | valge tooniv õlivaha Osmo 3111. | Dold Puidutööstus | - | 3.50531
S-08b | Ristkihtpuitpaneel (dold) 19 mm | S-08b | valge tooniv õlivaha Osmo 3111. | Dold Puidutööstus | - | 6.54996
S-02 | Puitribi paneel, musta kangaga | S-02 | Valge tooniv õlivaha Osmo 3111. | IWS | IWS | 5.95211
S-02 | Puitribi paneel, musta kangaga | S-02 | Valge tooniv õlivaha Osmo 3111. | IWS | IWS | 2.22893
4 x S-08b | Ristkihtpuitpaneel (dold) 19 mm | S-08b | valge tooniv õlivaha Osmo 3111. | Dold Puidutööstus | - | 3.56453
S-08b | Ristkihtpuitpaneel (dold) 19 mm | S-08b | valge tooniv õlivaha Osmo 3111. | Dold Puidutööstus | - | 5.56556
S-08b | Ristkihtpuitpaneel (dold) 19 mm | S-08b | valge tooniv õlivaha Osmo 3111. | Dold Puidutööstus | - | 4.69904
S-08b | Ristkihtpuitpaneel (dold) 19 mm | S-08b | valge tooniv õlivaha Osmo 3111. | Dold Puidutööstus | - | 4.67426
S-08b | Ristkihtpuitpaneel (dold) 19 mm | S-08b | valge tooniv õlivaha Osmo 3111. | Dold Puidutööstus | - | 12.9128

# IfcCovering: 80 Siseviimistlus dold 41 x 20, S-02
In: Teine korrus
Type - PredefinedType: CLADDING
Classification: 1.05 IfcCoveringType.CLADDING (seina viimistlus) (BIM ÜBN + Archicad Classification); Material: 80 Siseviimistlus dold
Pset_CoveringCommon - Reference: S-02; Material: 80 Siseviimistlus dold
AR_Viimistlus - 001_Nimetus: Puitribi paneel, musta kangaga; 200_Materjal: 80 Siseviimistlus dold; 205_Tähis: S-02; 215_Tuletundlikkus: -; 220_Viimistlus: ootel; 230_Niiskuskindel: no; 900_Tootja: IWS; 905_Mudel: ootel; 910_Tooteinfo: ootel; 915_Kasutus-ja-hooldusjuhend: ootel; 240_Märghõõrdekindlus: ootel; 245_Aluspind: ootel; 210_Paksus: 41 mm
AR_ÜLD - 001_Nimetus: Puitribi paneel, musta kangaga; 009_Märkus: OMA märkus
AR_ABI - 200_Materjal (MUDELIS): 80 Siseviimistlus dold
AC_Pset_RenovationAndPhasing - Renovation Status: New

# IfcCovering: 80 Siseviimistlus dold 43 x 20 (3)
In: Esimene korrus
Type - PredefinedType: CLADDING
Classification: 1.05 IfcCoveringType.CLADDING (seina viimistlus) (BIM ÜBN + Archicad Classification); Material: 80 Siseviimistlus dold
AR_ABI - 200_Materjal (MUDELIS): 80 Siseviimistlus dold
AC_Pset_RenovationAndPhasing - Renovation Status: New
AR_ÜLD - 001_Nimetus: Puitribi paneel, musta kangaga; 009_Märkus: OMA märkus
AR_Viimistlus - 001_Nimetus: Puitribi paneel, musta kangaga; 200_Materjal: 80 Siseviimistlus dold; 205_Tähis: S-02; 215_Tuletundlikkus: -; 220_Viimistlus: ootel; 230_Niiskuskindel: no; 900_Tootja: IWS; 905_Mudel: ootel; 910_Tooteinfo: ootel; 915_Kasutus-ja-hooldusjuhend: ootel; 240_Märghõõrdekindlus: ootel; 245_Aluspind: ootel; 210_Paksus: 43 mm
Pset_CoveringCommon - Reference: S-02; Material: 80 Siseviimistlus dold

# IfcCovering: 80 Siseviimistlus dold 5 (50)
Type - PredefinedType: CLADDING
Classification: 1.05 IfcCoveringType.CLADDING (seina viimistlus) (BIM ÜBN + Archicad Classification); Material: 80 Siseviimistlus dold
Pset_CoveringCommon - Material: 80 Siseviimistlus dold; TotalThickness: 5 mm
AR_Viimistlus - 200_Materjal: 80 Siseviimistlus dold; 215_Tuletundlikkus: -; 230_Niiskuskindel: no; 910_Tooteinfo: ootel; 915_Kasutus-ja-hooldusjuhend: ootel; 240_Märghõõrdekindlus: ootel; 245_Aluspind: ootel; 210_Paksus: 5 mm
AR_ABI - 200_Materjal (MUDELIS): 80 Siseviimistlus dold
AC_Pset_RenovationAndPhasing - Renovation Status: New
Name | In | Reference = 205_Tähis | AR_Viimistlus, 001_Nimetus = AR_ÜLD, 001_Nimetus | 220_Viimistlus | 900_Tootja | 905_Mudel | 225_Pindala (m2)
S-04.1 | Esimene korrus | S-04.1 | Krohvitud ja värvitud sein, toon antrasiit | Jura 5 L30 C2 H92 | Caparol | Amphibolin | 6.23414
S-04.1 | Esimene korrus | S-04.1 | Krohvitud ja värvitud sein, toon antrasiit | Jura 5 L30 C2 H92 | Caparol | Amphibolin | 7.042
S-04.3 | Esimene korrus | S-04.3 | Krohvitud ja värvitud sein toon virsik | Ambra 75 L67 C32 H62 | Caparol | Amphibolin | 2.75269
2 x S-04.3 | Esimene korrus | S-04.3 | Krohvitud ja värvitud sein toon virsik | Ambra 75 L67 C32 H62 | Caparol | Amphibolin | 1.37999
2 x S-04.3 | Esimene korrus | S-04.3 | Krohvitud ja värvitud sein toon virsik | Ambra 75 L67 C32 H62 | Caparol | Amphibolin | 1.38
2 x S-04.3 | Esimene korrus | S-04.3 | Krohvitud ja värvitud sein toon virsik | Ambra 75 L67 C32 H62 | Caparol | Amphibolin | 2.00415
S-04.3 | Esimene korrus | S-04.3 | Krohvitud ja värvitud sein toon virsik | Ambra 75 L67 C32 H62 | Caparol | Amphibolin | 2.75288
S-05 | Esimene korrus | S-05 | Sikagard AL-12 süsteem, toon antrasiit | RAL 7016 | Sika | AL-12 | 2.2896
S-05 | Esimene korrus | S-05 | Sikagard AL-12 süsteem, toon antrasiit | RAL 7016 | Sika | AL-12 | 2.59499
S-04.1 | Esimene korrus | S-04.1 | Krohvitud ja värvitud sein, toon antrasiit | Jura 5 L30 C2 H92 | Caparol | Amphibolin | 10.465
S-04.1 | Esimene korrus | S-04.1 | Krohvitud ja värvitud sein, toon antrasiit | Jura 5 L30 C2 H92 | Caparol | Amphibolin | 2.58003
S-04.1 | Esimene korrus | S-04.1 | Krohvitud ja värvitud sein, toon antrasiit | Jura 5 L30 C2 H92 | Caparol | Amphibolin | 10.26
S-04.1 | Esimene korrus | S-04.1 | Krohvitud ja värvitud sein, toon antrasiit | Jura 5 L30 C2 H92 | Caparol | Amphibolin | 4.9322
S-04.1 | Esimene korrus | S-04.1 | Krohvitud ja värvitud sein, toon antrasiit | Jura 5 L30 C2 H92 | Caparol | Amphibolin | 2.2764
S-04.1 | Esimene korrus | S-04.1 | Krohvitud ja värvitud sein, toon antrasiit | Jura 5 L30 C2 H92 | Caparol | Amphibolin | 24.5925
S-04.1 | Esimene korrus | S-04.1 | Krohvitud ja värvitud sein, toon antrasiit | Jura 5 L30 C2 H92 | Caparol | Amphibolin | 25.2368
2 x S-04.4 | Teine korrus | S-04.4 | Krohvitud ja värvitud sein roheline | Tundra 35 L65 C13 H100 | Caparol | Amphibolin | 0.51615
2 x S-04.4 | Teine korrus | S-04.4 | Krohvitud ja värvitud sein roheline | Tundra 35 L65 C13 H100 | Caparol | Amphibolin | 2.75288
2 x S-04.4 | Teine korrus | S-04.4 | Krohvitud ja värvitud sein roheline | Tundra 35 L65 C13 H100 | Caparol | Amphibolin | 0.198
2 x S-04.4 | Teine korrus | S-04.4 | Krohvitud ja värvitud sein roheline | Tundra 35 L65 C13 H100 | Caparol | Amphibolin | 0.84744
2 x S-04.4 | Teine korrus | S-04.4 | Krohvitud ja värvitud sein roheline | Tundra 35 L65 C13 H100 | Caparol | Amphibolin | 1.056
2 x S-04.4 | Teine korrus | S-04.4 | Krohvitud ja värvitud sein roheline | Tundra 35 L65 C13 H100 | Caparol | Amphibolin | 2.45244
2 x S-04.4 | Teine korrus | S-04.4 | Krohvitud ja värvitud sein roheline | Tundra 35 L65 C13 H100 | Caparol | Amphibolin | 0.33
2 x S-04.1 | Teine korrus | S-04.1 | Krohvitud ja värvitud sein, toon antrasiit | Jura 5 L30 C2 H92 | Caparol | Amphibolin | 17.8932
S-04.1 | Teine korrus | S-04.1 | Krohvitud ja värvitud sein, toon antrasiit | Jura 5 L30 C2 H92 | Caparol | Amphibolin | 41.0556
S-14 | Teine korrus | S-14 | Forbo bulletinboard, toon antrasiit | Antrasiit | Forbo | Bulletinboard | 17.8626
S-04.1 | Teine korrus | S-04.1 | Krohvitud ja värvitud sein, toon antrasiit | Jura 5 L30 C2 H92 | Caparol | Amphibolin | 43.1814
2 x S-04.1 | Teine korrus | S-04.1 | Krohvitud ja värvitud sein, toon antrasiit | Jura 5 L30 C2 H92 | Caparol | Amphibolin | 44.6121
S-04.1 | Teine korrus | S-04.1 | Krohvitud ja värvitud sein, toon antrasiit | Jura 5 L30 C2 H92 | Caparol | Amphibolin | 72.2982
S-04.1 | Teine korrus | S-04.1 | Krohvitud ja värvitud sein, toon antrasiit | Jura 5 L30 C2 H92 | Caparol | Amphibolin | 8.56277
2 x S-04.1 | Teine korrus | S-04.1 | Krohvitud ja värvitud sein, toon antrasiit | Jura 5 L30 C2 H92 | Caparol | Amphibolin | 30.4029
2 x S-04.1 | Teine korrus | S-04.1 | Krohvitud ja värvitud sein, toon antrasiit | Jura 5 L30 C2 H92 | Caparol | Amphibolin | 10.582
2 x S-10 | Teine korrus | S-10 | Roheline viltsein 9mm, toon roheline Glade | Glade | Soundtect | Wallpanel | 4.131
S-04.1 | Teine korrus | S-04.1 | Krohvitud ja värvitud sein, toon antrasiit | Jura 5 L30 C2 H92 | Caparol | Amphibolin | 3.85343
S-04.1 | Teine korrus | S-04.1 | Krohvitud ja värvitud sein, toon antrasiit | Jura 5 L30 C2 H92 | Caparol | Amphibolin | 2.442

# IfcCovering: 80 Siseviimistlus dold 9 (2)
In: Teine korrus
Type - PredefinedType: CLADDING
Classification: 1.05 IfcCoveringType.CLADDING (seina viimistlus) (BIM ÜBN + Archicad Classification); Material: 80 Siseviimistlus dold
Pset_CoveringCommon - Reference: S-10; Material: 80 Siseviimistlus dold; TotalThickness: 9 mm
AR_Viimistlus - 001_Nimetus: Roheline viltsein 9mm, toon roheline Glade; 200_Materjal: 80 Siseviimistlus dold; 205_Tähis: S-10; 215_Tuletundlikkus: -; 220_Viimistlus: Glade; 230_Niiskuskindel: no; 900_Tootja: Soundtect; 905_Mudel: Wallpanel; 910_Tooteinfo: ootel; 915_Kasutus-ja-hooldusjuhend: ootel; 240_Märghõõrdekindlus: ootel; 245_Aluspind: ootel; 225_Pindala: 4.131 m2; 210_Paksus: 9 mm
AR_ÜLD - 001_Nimetus: Roheline viltsein 9mm, toon roheline Glade
AR_ABI - 200_Materjal (MUDELIS): 80 Siseviimistlus dold
AC_Pset_RenovationAndPhasing - Renovation Status: New

# IfcCovering: 80 must mööbliplaat 1, S-02
In: Teine korrus
Type - PredefinedType: CLADDING
Classification: 1.05 IfcCoveringType.CLADDING (seina viimistlus) (BIM ÜBN + Archicad Classification); Material: 80 must mööbliplaat
Pset_CoveringCommon - Reference: S-02; Material: 80 must mööbliplaat; TotalThickness: 1 mm
AR_Viimistlus - 001_Nimetus: Puitribi paneel, musta kangaga; 200_Materjal: 80 must mööbliplaat; 205_Tähis: S-02; 215_Tuletundlikkus: -; 220_Viimistlus: ootel; 230_Niiskuskindel: no; 900_Tootja: IWS; 905_Mudel: ootel; 910_Tooteinfo: ootel; 915_Kasutus-ja-hooldusjuhend: ootel; 240_Märghõõrdekindlus: ootel; 245_Aluspind: ootel; 225_Pindala: 5.19567 m2; 210_Paksus: 1 mm
AR_ÜLD - 001_Nimetus: Puitribi paneel, musta kangaga
AR_ABI - 200_Materjal (MUDELIS): 80 must mööbliplaat
AC_Pset_RenovationAndPhasing - Renovation Status: New

# IfcCovering: 80 must mööbliplaat 20 (3)
Type - PredefinedType: CLADDING
Classification: 1.05 IfcCoveringType.CLADDING (seina viimistlus) (BIM ÜBN + Archicad Classification); Material: 80 must mööbliplaat
Pset_CoveringCommon - Material: 80 must mööbliplaat; TotalThickness: 20 mm
AR_Viimistlus - 200_Materjal: 80 must mööbliplaat; 215_Tuletundlikkus: -; 230_Niiskuskindel: no; 910_Tooteinfo: ootel; 915_Kasutus-ja-hooldusjuhend: ootel; 240_Märghõõrdekindlus: ootel; 245_Aluspind: ootel; 210_Paksus: 20 mm
AC_Pset_RenovationAndPhasing - Renovation Status: New
AR_ABI - 200_Materjal (MUDELIS): 80 must mööbliplaat
Name | In | Reference = 205_Tähis | AR_ÜLD, 001_Nimetus = AR_Viimistlus, 001_Nimetus | 220_Viimistlus | 900_Tootja | 905_Mudel | 225_Pindala (m2)
S-02 | Esimene korrus | S-02 | Puitribi paneel, musta kangaga | ootel | IWS | ootel | 3.528
S-08b | Teine korrus | S-08b | Ristkihtpuitpaneel (dold) 19 mm | valge tooniv õlivaha Osmo 3111. | Dold Puidutööstus | - | 0.58446
S-02 | Teine korrus | S-02 | Puitribi paneel, musta kangaga | ootel | IWS | ootel | 15.5862

# IfcCovering: 80 must mööbliplaat 21 (34)
Type - PredefinedType: CLADDING
Classification: 1.05 IfcCoveringType.CLADDING (seina viimistlus) (BIM ÜBN + Archicad Classification); Material: 80 must mööbliplaat
AR_Viimistlus - 001_Nimetus: Puitribi paneel, musta kangaga; 200_Materjal: 80 must mööbliplaat; 205_Tähis: S-02; 215_Tuletundlikkus: -; 220_Viimistlus: ootel; 230_Niiskuskindel: no; 900_Tootja: IWS; 905_Mudel: ootel; 910_Tooteinfo: ootel; 915_Kasutus-ja-hooldusjuhend: ootel; 240_Märghõõrdekindlus: ootel; 245_Aluspind: ootel; 210_Paksus: 21 mm
Pset_CoveringCommon - Reference: S-02; Material: 80 must mööbliplaat; TotalThickness: 21 mm
AR_ÜLD - 001_Nimetus: Puitribi paneel, musta kangaga
AR_ABI - 200_Materjal (MUDELIS): 80 must mööbliplaat
AC_Pset_RenovationAndPhasing - Renovation Status: New
Name | In | 225_Pindala (m2)
S-02 | Esimene korrus | 7.1346
S-02 | Esimene korrus | 0.39902
S-02 | Esimene korrus | 0.091753
S-02 | Esimene korrus | 0.0865631
S-02 | Esimene korrus | 0.1269
S-02 | Esimene korrus | 0.06909
S-02 | Esimene korrus | 10.6763
S-02 | Esimene korrus | 1.39545
2 x S-02 | Teine korrus | 2.5452
S-02 | Teine korrus | 17.8356
S-02 | Teine korrus | 3.9431
S-02 | Teine korrus | 6.80561
S-02 | Teine korrus | 2.00466
S-02 | Teine korrus | 0.426907
S-02 | Teine korrus | 2.78124
2 x S-02 | Teine korrus | 0.8008
S-02 | Teine korrus | 2.7692
S-02 | Teine korrus | 9.71373
2 x S-02 | Teine korrus | 2.02846
2 x S-02 | Teine korrus | 2.016
2 x S-02 | Teine korrus | 2.3184
S-02 | Teine korrus | 2.51625
S-02 | Teine korrus | 2.50419
S-02 | Teine korrus | 2.5315
S-02 | Teine korrus | 3.76675
S-02 | Teine korrus | 2.53139
S-02 | Teine korrus | 3.44654
S-02 | Teine korrus | 12.0582
S-02 | Teine korrus | 11.4231

# IfcCovering: 80 must mööbliplaat 40, S-08b
In: Teine korrus
Type - PredefinedType: CLADDING
Classification: 1.05 IfcCoveringType.CLADDING (seina viimistlus) (BIM ÜBN + Archicad Classification); Material: 80 must mööbliplaat
Pset_CoveringCommon - Reference: S-08b; Material: 80 must mööbliplaat; TotalThickness: 40 mm
AR_ÜLD - 001_Nimetus: Ristkihtpuitpaneel (dold) 19 mm
AR_Viimistlus - 001_Nimetus: Ristkihtpuitpaneel (dold) 19 mm; 200_Materjal: 80 must mööbliplaat; 205_Tähis: S-08b; 215_Tuletundlikkus: -; 220_Viimistlus: valge tooniv õlivaha Osmo 3111.; 230_Niiskuskindel: no; 900_Tootja: Dold Puidutööstus; 905_Mudel: -; 910_Tooteinfo: ootel; 915_Kasutus-ja-hooldusjuhend: ootel; 240_Märghõõrdekindlus: ootel; 245_Aluspind: ootel; 225_Pindala: 0.627042 m2; 210_Paksus: 40 mm
AR_ABI - 200_Materjal (MUDELIS): 80 must mööbliplaat
AC_Pset_RenovationAndPhasing - Renovation Status: New

# IfcCovering: 80 must mööbliplaat 40 x 20 (843)
In: Teine korrus
Type - PredefinedType: CEILING
Classification: 1.04 IfcCoveringType.CEILING (ripplagi) (BIM ÜBN + Archicad Classification); Material: 80 must mööbliplaat
AR_Viimistlus - 001_Nimetus: Puitribilagi; 200_Materjal: 80 must mööbliplaat; 205_Tähis: L-03a; 215_Tuletundlikkus: C-s2,d1; 220_Viimistlus: 1 kiht valge tooniv õlivaha Osmo 3111; 230_Niiskuskindel: no; 235_Karkass: CD-kandekarkass 27mm; 900_Tootja: IWS; 905_Mudel: Linear 20C; 910_Tooteinfo: ootel; 915_Kasutus-ja-hooldusjuhend: ootel; 210_Paksus: 40 mm
Pset_CoveringCommon - Reference: L-03a; Material: 80 must mööbliplaat
AR_ÜLD - 001_Nimetus: Puitribilagi; 009_Märkus: OMA märkus
AR_ABI - 200_Materjal (MUDELIS): 80 must mööbliplaat
AC_Pset_RenovationAndPhasing - Renovation Status: New

# IfcCovering: 80 must mööbliplaat 41 x 20 (2)
In: Teine korrus
Type - PredefinedType: CEILING
Classification: 1.04 IfcCoveringType.CEILING (ripplagi) (BIM ÜBN + Archicad Classification); Material: 80 must mööbliplaat
AC_Pset_RenovationAndPhasing - Renovation Status: New
AR_ABI - 200_Materjal (MUDELIS): 80 must mööbliplaat
AR_ÜLD - 001_Nimetus: Puitribilagi; 009_Märkus: OMA märkus
AR_Viimistlus - 001_Nimetus: Puitribilagi; 200_Materjal: 80 must mööbliplaat; 205_Tähis: L-03a; 215_Tuletundlikkus: C-s2,d1; 220_Viimistlus: 1 kiht valge tooniv õlivaha Osmo 3111; 230_Niiskuskindel: no; 235_Karkass: CD-kandekarkass 27mm; 900_Tootja: IWS; 905_Mudel: Linear 20C; 910_Tooteinfo: ootel; 915_Kasutus-ja-hooldusjuhend: ootel; 210_Paksus: 41 mm
Pset_CoveringCommon - Reference: L-03a; Material: 80 must mööbliplaat

# IfcCovering: 80 vildiplaat cinnamon 5 (2)
In: Teine korrus
Type - PredefinedType: CLADDING
Classification: 1.05 IfcCoveringType.CLADDING (seina viimistlus) (BIM ÜBN + Archicad Classification); Material: 80 vildiplaat cinnamon
Pset_CoveringCommon - Material: 80 vildiplaat cinnamon; TotalThickness: 5 mm
AR_Viimistlus - 200_Materjal: 80 vildiplaat cinnamon; 215_Tuletundlikkus: -; 230_Niiskuskindel: no; 910_Tooteinfo: ootel; 915_Kasutus-ja-hooldusjuhend: ootel; 240_Märghõõrdekindlus: ootel; 245_Aluspind: ootel; 225_Pindala: 10.9386 m2; 210_Paksus: 5 mm
AR_ABI - 200_Materjal (MUDELIS): 80 vildiplaat cinnamon
AC_Pset_RenovationAndPhasing - Renovation Status: New
Name | Reference = 205_Tähis | AR_Viimistlus, 001_Nimetus = AR_ÜLD, 001_Nimetus | 220_Viimistlus | 900_Tootja | 905_Mudel
S-11 | S-11 | Viltsein 9 mm, oranž | Cinnamon | Noecho | Wallpanel
S-04.2 | S-04.2 | Krohvitud ja värvitud sein, toon loodusvalge | Jura 60 L 88 C1 H92 (hele-hall) | Caparol | Amphibolin

# IfcCovering: 80 vildiplaat cinnamon 9 (5)
In: Teine korrus
Type - PredefinedType: CLADDING
Classification: 1.05 IfcCoveringType.CLADDING (seina viimistlus) (BIM ÜBN + Archicad Classification); Material: 80 vildiplaat cinnamon
AR_ÜLD - 001_Nimetus: Viltsein 9 mm, oranž
AR_Viimistlus - 001_Nimetus: Viltsein 9 mm, oranž; 200_Materjal: 80 vildiplaat cinnamon; 205_Tähis: S-11; 215_Tuletundlikkus: -; 220_Viimistlus: Cinnamon; 230_Niiskuskindel: no; 900_Tootja: Noecho; 905_Mudel: Wallpanel; 910_Tooteinfo: ootel; 915_Kasutus-ja-hooldusjuhend: ootel; 240_Märghõõrdekindlus: ootel; 245_Aluspind: ootel; 210_Paksus: 9 mm
AR_ABI - 200_Materjal (MUDELIS): 80 vildiplaat cinnamon
AC_Pset_RenovationAndPhasing - Renovation Status: New
Pset_CoveringCommon - Reference: S-11; Material: 80 vildiplaat cinnamon; TotalThickness: 9 mm
Name | 225_Pindala (m2)
S-11 | 9.4164
3 x S-11 | 10.9386
S-11 | 12.2094

# IfcCovering: 80 vildiplaat nutmeg 9 (6)
In: Teine korrus
Type - PredefinedType: CLADDING
Classification: 1.05 IfcCoveringType.CLADDING (seina viimistlus) (BIM ÜBN + Archicad Classification); Material: 80 vildiplaat nutmeg
Pset_CoveringCommon - Reference: S-12; Material: 80 vildiplaat nutmeg; TotalThickness: 9 mm
AR_Viimistlus - 001_Nimetus: Viltsein 9 mm, beež; 200_Materjal: 80 vildiplaat nutmeg; 205_Tähis: S-12; 215_Tuletundlikkus: -; 220_Viimistlus: Nutmeg; 230_Niiskuskindel: no; 900_Tootja: Noecho; 905_Mudel: Wallpanel; 910_Tooteinfo: ootel; 915_Kasutus-ja-hooldusjuhend: ootel; 240_Märghõõrdekindlus: ootel; 245_Aluspind: ootel; 210_Paksus: 9 mm
AR_ÜLD - 001_Nimetus: Viltsein 9 mm, beež
AR_ABI - 200_Materjal (MUDELIS): 80 vildiplaat nutmeg
AC_Pset_RenovationAndPhasing - Renovation Status: New
Name | 225_Pindala (m2)
S-12 | 14.1831
4 x S-12 | 10.9386
S-12 | 9.4164

# IfcCovering: 91 Viim: Klaas 2 16 (7)
In: Katus
Classification: 1.07 IfcCoveringType (pinnadetailid) (BIM ÜBN + Archicad Classification); Material: 91 Viim: Klaas 2
AR_Viimistlus - 001_Nimetus: KF plekk
Pset_CoveringCommon - TotalThickness: 15.9999 mm
AR_ABI - 200_Materjal (MUDELIS): 91 Viim: Klaas 2
AR_ÜLD - 001_Nimetus: KF plekk; 009_Märkus: vt. AR-7 sõlmlahendusi
AC_Pset_RenovationAndPhasing - Renovation Status: New

# IfcCovering: 91 Viim: Klaas 53 (9)
In: Katus
Classification: 1.07 IfcCoveringType (pinnadetailid) (BIM ÜBN + Archicad Classification); Material: 91 Viim: Klaas
Pset_CoveringCommon - TotalThickness: 53 mm
AR_ÜLD - 001_Nimetus: KF plekk; 009_Märkus: vt. AR-7 sõlmlahendusi
AR_ABI - 200_Materjal (MUDELIS): 91 Viim: Klaas
AC_Pset_RenovationAndPhasing - Renovation Status: New
AR_Viimistlus - 001_Nimetus: KF plekk
Name
KF-16
KF-12
KF-14
KF-10
KF-11
3 x KF-13
KF-15

# IfcCovering: 91 Viimistlus: krohv 3 (29)
Type - PredefinedType: CLADDING
Classification: 1.05 IfcCoveringType.CLADDING (seina viimistlus) (BIM ÜBN + Archicad Classification); Material: 91 Viimistlus: krohv
Pset_CoveringCommon - Material: 91 Viimistlus: krohv; TotalThickness: 3 mm
AR_Viimistlus - 200_Materjal: 91 Viimistlus: krohv; 215_Tuletundlikkus: -; 230_Niiskuskindel: no; 900_Tootja: Caparol; 905_Mudel: Amphibolin; 910_Tooteinfo: ootel; 915_Kasutus-ja-hooldusjuhend: ootel; 240_Märghõõrdekindlus: ootel; 245_Aluspind: ootel; 210_Paksus: 3 mm
AC_Pset_RenovationAndPhasing - Renovation Status: New
AR_ABI - 200_Materjal (MUDELIS): 91 Viimistlus: krohv
Name | In | Reference = 205_Tähis | AR_Viimistlus, 001_Nimetus = AR_ÜLD, 001_Nimetus | 220_Viimistlus | 225_Pindala (m2)
4 x S-04.3 | Esimene korrus | S-04.3 | Krohvitud ja värvitud sein toon virsik | Ambra 75 L67 C32 H62 | 15.0299
2 x S-04.3 | Esimene korrus | S-04.3 | Krohvitud ja värvitud sein toon virsik | Ambra 75 L67 C32 H62 | 10.68
2 x S-04.3 | Esimene korrus | S-04.3 | Krohvitud ja värvitud sein toon virsik | Ambra 75 L67 C32 H62 | 1.33201
2 x S-04.3 | Esimene korrus | S-04.3 | Krohvitud ja värvitud sein toon virsik | Ambra 75 L67 C32 H62 | 2.136
2 x S-04.3 | Esimene korrus | S-04.3 | Krohvitud ja värvitud sein toon virsik | Ambra 75 L67 C32 H62 | 1.59
S-04.3 | Esimene korrus | S-04.3 | Krohvitud ja värvitud sein toon virsik | Ambra 75 L67 C32 H62 | 1.32607
S-04.3 | Esimene korrus | S-04.3 | Krohvitud ja värvitud sein toon virsik | Ambra 75 L67 C32 H62 | 1.33207
2 x S-04.3 | Esimene korrus | S-04.3 | Krohvitud ja värvitud sein toon virsik | Ambra 75 L67 C32 H62 | 7.95
S-06 | Teine korrus | S-06 | Niiskuskindel värv, toon hele-hall. | Jura 60 L80 C2 H92 | 4.8202
S-06 | Teine korrus | S-06 | Niiskuskindel värv, toon hele-hall. | Jura 60 L80 C2 H92 | 1.98506
S-04.2 | Teine korrus | S-04.2 | Krohvitud ja värvitud sein, toon loodusvalge | Jura 60 L 88 C1 H92 (hele-hall) | 3.78532
2 x S-04.2 | Teine korrus | S-04.2 | Krohvitud ja värvitud sein, toon loodusvalge | Jura 60 L 88 C1 H92 (hele-hall) | 3.55124
S-06 | Teine korrus | S-06 | Niiskuskindel värv, toon hele-hall. | Jura 60 L80 C2 H92 | 3.94548
S-06 | Teine korrus | S-06 | Niiskuskindel värv, toon hele-hall. | Jura 60 L80 C2 H92 | 6.81296
2 x S-06 | Teine korrus | S-06 | Niiskuskindel värv, toon hele-hall. | Jura 60 L80 C2 H92 | 11.9271
S-04.2 | Teine korrus | S-04.2 | Krohvitud ja värvitud sein, toon loodusvalge | Jura 60 L 88 C1 H92 (hele-hall) | 2.01124
2 x S-06 | Teine korrus | S-06 | Niiskuskindel värv, toon hele-hall. | Jura 60 L80 C2 H92 | 10.6954
S-06 | Teine korrus | S-06 | Niiskuskindel värv, toon hele-hall. | Jura 60 L80 C2 H92 | 1.9789

# IfcCovering: 91 Viimistlus: krohv 4, S-04.1
In: Teine korrus
Type - PredefinedType: CLADDING
Classification: 1.05 IfcCoveringType.CLADDING (seina viimistlus) (BIM ÜBN + Archicad Classification); Material: 91 Viimistlus: krohv
AR_Viimistlus - 001_Nimetus: Krohvitud ja värvitud sein, toon antrasiit; 200_Materjal: 91 Viimistlus: krohv; 205_Tähis: S-04.1; 215_Tuletundlikkus: -; 220_Viimistlus: Jura 5 L30 C2 H92; 230_Niiskuskindel: no; 900_Tootja: Caparol; 905_Mudel: Amphibolin; 910_Tooteinfo: ootel; 915_Kasutus-ja-hooldusjuhend: ootel; 240_Märghõõrdekindlus: ootel; 245_Aluspind: ootel; 225_Pindala: 118.643 m2; 210_Paksus: 4 mm
Pset_CoveringCommon - Reference: S-04.1; Material: 91 Viimistlus: krohv; TotalThickness: 4 mm
AR_ABI - 200_Materjal (MUDELIS): 91 Viimistlus: krohv
AC_Pset_RenovationAndPhasing - Renovation Status: New
AR_ÜLD - 001_Nimetus: Krohvitud ja värvitud sein, toon antrasiit

# IfcCovering: 91 Viimistlus: krohv 5 (227)
Type - PredefinedType: CLADDING
Classification: 1.05 IfcCoveringType.CLADDING (seina viimistlus) (BIM ÜBN + Archicad Classification); Material: 91 Viimistlus: krohv
Pset_CoveringCommon - Material: 91 Viimistlus: krohv; TotalThickness: 5 mm
AR_Viimistlus - 200_Materjal: 91 Viimistlus: krohv; 215_Tuletundlikkus: -; 230_Niiskuskindel: no; 910_Tooteinfo: ootel; 915_Kasutus-ja-hooldusjuhend: ootel; 240_Märghõõrdekindlus: ootel; 245_Aluspind: ootel; 210_Paksus: 5 mm
AR_ABI - 200_Materjal (MUDELIS): 91 Viimistlus: krohv
AC_Pset_RenovationAndPhasing - Renovation Status: New
Name | In | Reference = 205_Tähis | AR_Viimistlus, 001_Nimetus = AR_ÜLD, 001_Nimetus | 220_Viimistlus | 900_Tootja | 905_Mudel | 225_Pindala (m2)
S-01.1 | Esimene korrus | S-01.1 | Puhasvuuk sein, värvitud tumehalliks, toon: antrasiit. | Jura 5 L30 C2 H92 | Caparol | Amphibolin | 62.8402
S-04.1 | Esimene korrus | S-04.1 | Krohvitud ja värvitud sein, toon antrasiit | Jura 5 L30 C2 H92 | Caparol | Amphibolin | 11.1879
S-04.1 | Esimene korrus | S-04.1 | Krohvitud ja värvitud sein, toon antrasiit | Jura 5 L30 C2 H92 | Caparol | Amphibolin | 8.32194
2 x S-04.1 | Esimene korrus | S-04.1 | Krohvitud ja värvitud sein, toon antrasiit | Jura 5 L30 C2 H92 | Caparol | Amphibolin | 23.2755
S-01.1 | Esimene korrus | S-01.1 | Puhasvuuk sein, värvitud tumehalliks, toon: antrasiit. | Jura 5 L30 C2 H92 | Caparol | Amphibolin | 62.8403
2 x S-15 | Esimene korrus | S-15 | Krohvitud sein MP75 | Jura 60 L 88 C1 H92 (hele-hall). | Caparol | Amphibolin | 19.3989
S-15 | Esimene korrus | S-15 | Krohvitud sein MP75 | Jura 60 L 88 C1 H92 (hele-hall). | Caparol | Amphibolin | 14.2562
S-15 | Esimene korrus | S-15 | Krohvitud sein MP75 | Jura 60 L 88 C1 H92 (hele-hall). | Caparol | Amphibolin | 19.0638
4 x S-01.2 | Esimene korrus | S-01.2 | Puhasvuuk sein, värvitud helehalliks. | Jura 60 L88C1 H92 | Caparol | Amphibolin | 6.76
4 x S-01.2 | Esimene korrus | S-01.2 | Puhasvuuk sein, värvitud helehalliks. | Jura 60 L88C1 H92 | Caparol | Amphibolin | 17.5807
2 x S-01.2 | Esimene korrus | S-01.2 | Puhasvuuk sein, värvitud helehalliks. | Jura 60 L88C1 H92 | Caparol | Amphibolin | 14.729
4 x S-01.2 | Esimene korrus | S-01.2 | Puhasvuuk sein, värvitud helehalliks. | Jura 60 L88C1 H92 | Caparol | Amphibolin | 19.5794
S-01.2 | Esimene korrus | S-01.2 | Puhasvuuk sein, värvitud helehalliks. | Jura 60 L88C1 H92 | Caparol | Amphibolin | 14.833
2 x S-01.2 | Esimene korrus | S-01.2 | Puhasvuuk sein, värvitud helehalliks. | Jura 60 L88C1 H92 | Caparol | Amphibolin | 20.5951
3 x S-01.2 | Esimene korrus | S-01.2 | Puhasvuuk sein, värvitud helehalliks. | Jura 60 L88C1 H92 | Caparol | Amphibolin | 7.787
2 x S-01.2 | Esimene korrus | S-01.2 | Puhasvuuk sein, värvitud helehalliks. | Jura 60 L88C1 H92 | Caparol | Amphibolin | 20.4506
S-01.2 | Esimene korrus | S-01.2 | Puhasvuuk sein, värvitud helehalliks. | Jura 60 L88C1 H92 | Caparol | Amphibolin | 19.7106
S-01.2 | Esimene korrus | S-01.2 | Puhasvuuk sein, värvitud helehalliks. | Jura 60 L88C1 H92 | Caparol | Amphibolin | 14.1687
S-01.2 | Esimene korrus | S-01.2 | Puhasvuuk sein, värvitud helehalliks. | Jura 60 L88C1 H92 | Caparol | Amphibolin | 7.8
S-01.2 | Esimene korrus | S-01.2 | Puhasvuuk sein, värvitud helehalliks. | Jura 60 L88C1 H92 | Caparol | Amphibolin | 43.836
S-01.2 | Esimene korrus | S-01.2 | Puhasvuuk sein, värvitud helehalliks. | Jura 60 L88C1 H92 | Caparol | Amphibolin | 60.8646
2 x S-01.2 | Esimene korrus | S-01.2 | Puhasvuuk sein, värvitud helehalliks. | Jura 60 L88C1 H92 | Caparol | Amphibolin | 25.3783
S-15 | Esimene korrus | S-15 | Krohvitud sein MP75 | Jura 60 L 88 C1 H92 (hele-hall). | Caparol | Amphibolin | 64.7634
S-01.2 | Esimene korrus | S-01.2 | Puhasvuuk sein, värvitud helehalliks. | Jura 60 L88C1 H92 | Caparol | Amphibolin | 64.7634
2 x S-01.2 | Esimene korrus | S-01.2 | Puhasvuuk sein, värvitud helehalliks. | Jura 60 L88C1 H92 | Caparol | Amphibolin | 19.8911
5 x S-01.2 | Esimene korrus | S-01.2 | Puhasvuuk sein, värvitud helehalliks. | Jura 60 L88C1 H92 | Caparol | Amphibolin | 8.0865
11 x S-01.2 | Esimene korrus | S-01.2 | Puhasvuuk sein, värvitud helehalliks. | Jura 60 L88C1 H92 | Caparol | Amphibolin | 17.2197
2 x S-01.2 | Esimene korrus | S-01.2 | Puhasvuuk sein, värvitud helehalliks. | Jura 60 L88C1 H92 | Caparol | Amphibolin | 14.326
10 x S-01.2 | Esimene korrus | S-01.2 | Puhasvuuk sein, värvitud helehalliks. | Jura 60 L88C1 H92 | Caparol | Amphibolin | 7.02
S-01.2 | Esimene korrus | S-01.2 | Puhasvuuk sein, värvitud helehalliks. | Jura 60 L88C1 H92 | Caparol | Amphibolin | 8.866
S-01.2 | Esimene korrus | S-01.2 | Puhasvuuk sein, värvitud helehalliks. | Jura 60 L88C1 H92 | Caparol | Amphibolin | 2.29759
S-01.2 | Esimene korrus | S-01.2 | Puhasvuuk sein, värvitud helehalliks. | Jura 60 L88C1 H92 | Caparol | Amphibolin | 3.22403
S-01.2 | Esimene korrus | S-01.2 | Puhasvuuk sein, värvitud helehalliks. | Jura 60 L88C1 H92 | Caparol | Amphibolin | 6.60397
6 x S-01.2 | Esimene korrus | S-01.2 | Puhasvuuk sein, värvitud helehalliks. | Jura 60 L88C1 H92 | Caparol | Amphibolin | 19.1789
S-01.2 | Esimene korrus | S-01.2 | Puhasvuuk sein, värvitud helehalliks. | Jura 60 L88C1 H92 | Caparol | Amphibolin | 5.109
S-01.2 | Esimene korrus | S-01.2 | Puhasvuuk sein, värvitud helehalliks. | Jura 60 L88C1 H92 | Caparol | Amphibolin | 1.3
S-01.2 | Esimene korrus | S-01.2 | Puhasvuuk sein, värvitud helehalliks. | Jura 60 L88C1 H92 | Caparol | Amphibolin | 11.2163
S-01.2 | Esimene korrus | S-01.2 | Puhasvuuk sein, värvitud helehalliks. | Jura 60 L88C1 H92 | Caparol | Amphibolin | 14.56
2 x S-01.2 | Esimene korrus | S-01.2 | Puhasvuuk sein, värvitud helehalliks. | Jura 60 L88C1 H92 | Caparol | Amphibolin | 20.2882
S-01.2 | Esimene korrus | S-01.2 | Puhasvuuk sein, värvitud helehalliks. | Jura 60 L88C1 H92 | Caparol | Amphibolin | 20.216
S-01.2 | Esimene korrus | S-01.2 | Puhasvuuk sein, värvitud helehalliks. | Jura 60 L88C1 H92 | Caparol | Amphibolin | 9.4221
S-01.2 | Esimene korrus | S-01.2 | Puhasvuuk sein, värvitud helehalliks. | Jura 60 L88C1 H92 | Caparol | Amphibolin | 8.1
S-01.2 | Esimene korrus | S-01.2 | Puhasvuuk sein, värvitud helehalliks. | Jura 60 L88C1 H92 | Caparol | Amphibolin | 18.9886
S-01.2 | Esimene korrus | S-01.2 | Puhasvuuk sein, värvitud helehalliks. | Jura 60 L88C1 H92 | Caparol | Amphibolin | 14.612
S-01.2 | Esimene korrus | S-01.2 | Puhasvuuk sein, värvitud helehalliks. | Jura 60 L88C1 H92 | Caparol | Amphibolin | 13.676
S-01.2 | Esimene korrus | S-01.2 | Puhasvuuk sein, värvitud helehalliks. | Jura 60 L88C1 H92 | Caparol | Amphibolin | 26.9667
S-01.2 | Esimene korrus | S-01.2 | Puhasvuuk sein, värvitud helehalliks. | Jura 60 L88C1 H92 | Caparol | Amphibolin | 10.556
2 x S-01.2 | Esimene korrus | S-01.2 | Puhasvuuk sein, värvitud helehalliks. | Jura 60 L88C1 H92 | Caparol | Amphibolin | 16.2452
S-01.2 | Esimene korrus | S-01.2 | Puhasvuuk sein, värvitud helehalliks. | Jura 60 L88C1 H92 | Caparol | Amphibolin | 5.6316
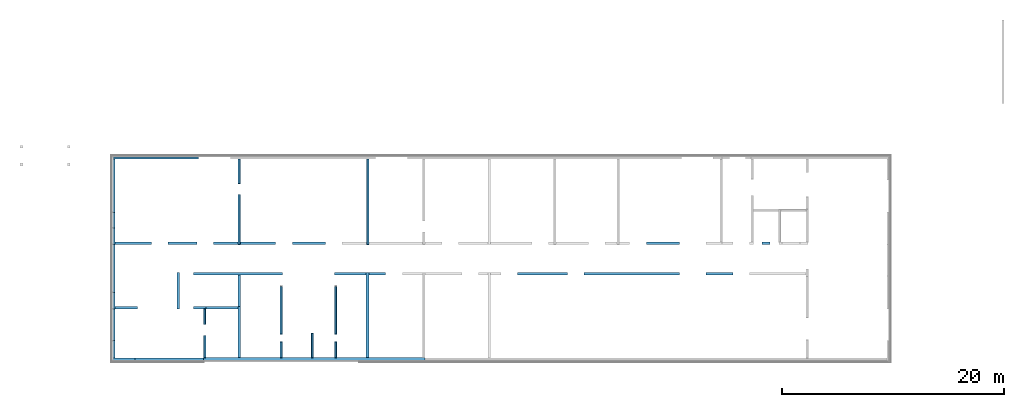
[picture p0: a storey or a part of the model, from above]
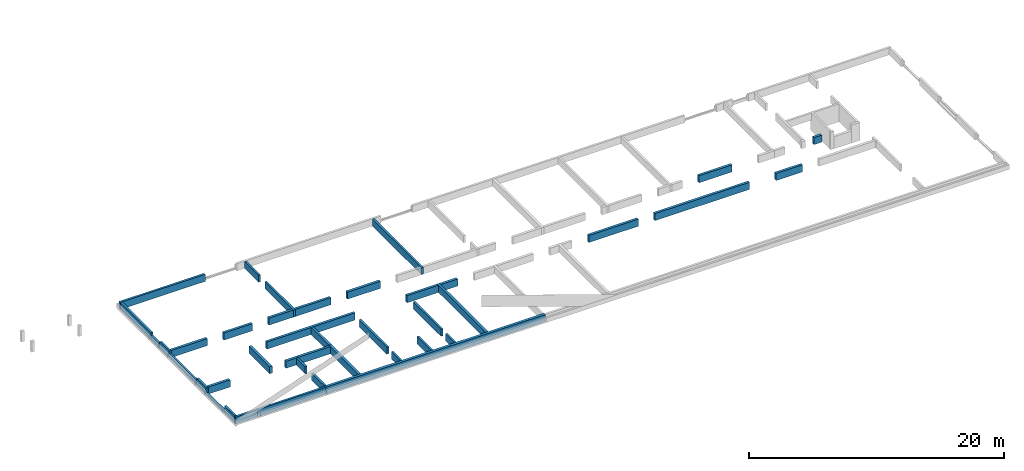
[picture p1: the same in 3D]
Properties of the parts of a building model (IFC2X3), part 3 of 8

# IfcCovering: 91 Viimistlus: krohv 5 (227)
Name | In | Reference = 205_Tähis | AR_Viimistlus, 001_Nimetus = AR_ÜLD, 001_Nimetus | 220_Viimistlus | 900_Tootja | 905_Mudel | 225_Pindala (m2)
2 x S-01.2 | Esimene korrus | S-01.2 | Puhasvuuk sein, värvitud helehalliks. | Jura 60 L88C1 H92 | Caparol | Amphibolin | 6.18
2 x S-01.2 | Esimene korrus | S-01.2 | Puhasvuuk sein, värvitud helehalliks. | Jura 60 L88C1 H92 | Caparol | Amphibolin | 10.8
2 x S-06 | Esimene korrus | S-06 | Niiskuskindel värv, toon hele-hall. | Jura 60 L80 C2 H92 | Caparol | Amphibolin | 3.98995
2 x S-06 | Esimene korrus | S-06 | Niiskuskindel värv, toon hele-hall. | Jura 60 L80 C2 H92 | Caparol | Amphibolin | 7.49995
2 x S-06 | Esimene korrus | S-06 | Niiskuskindel värv, toon hele-hall. | Jura 60 L80 C2 H92 | Caparol | Amphibolin | 11.4599
2 x S-06 | Esimene korrus | S-06 | Niiskuskindel värv, toon hele-hall. | Jura 60 L80 C2 H92 | Caparol | Amphibolin | 6.09005
2 x S-01.2 | Esimene korrus | S-01.2 | Puhasvuuk sein, värvitud helehalliks. | Jura 60 L88C1 H92 | Caparol | Amphibolin | 15.8479
2 x S-01.2 | Esimene korrus | S-01.2 | Puhasvuuk sein, värvitud helehalliks. | Jura 60 L88C1 H92 | Caparol | Amphibolin | 10.469
S-01.2 | Esimene korrus | S-01.2 | Puhasvuuk sein, värvitud helehalliks. | Jura 60 L88C1 H92 | Caparol | Amphibolin | 5.69
S-01.2 | Esimene korrus | S-01.2 | Puhasvuuk sein, värvitud helehalliks. | Jura 60 L88C1 H92 | Caparol | Amphibolin | 6.5341
S-01.2 | Esimene korrus | S-01.2 | Puhasvuuk sein, värvitud helehalliks. | Jura 60 L88C1 H92 | Caparol | Amphibolin | 7.3341
S-01.2 | Esimene korrus | S-01.2 | Puhasvuuk sein, värvitud helehalliks. | Jura 60 L88C1 H92 | Caparol | Amphibolin | 5.054
S-01.1 | Esimene korrus | S-01.1 | Puhasvuuk sein, värvitud tumehalliks, toon: antrasiit. | Jura 5 L30 C2 H92 | Caparol | Amphibolin | 50.7276
S-01.1 | Esimene korrus | S-01.1 | Puhasvuuk sein, värvitud tumehalliks, toon: antrasiit. | Jura 5 L30 C2 H92 | Caparol | Amphibolin | 2.7657
S-01.1 | Esimene korrus | S-01.1 | Puhasvuuk sein, värvitud tumehalliks, toon: antrasiit. | Jura 5 L30 C2 H92 | Caparol | Amphibolin | 4.20205
S-01.1 | Esimene korrus | S-01.1 | Puhasvuuk sein, värvitud tumehalliks, toon: antrasiit. | Jura 5 L30 C2 H92 | Caparol | Amphibolin | 11.2384
S-01.1 | Esimene korrus | S-01.1 | Puhasvuuk sein, värvitud tumehalliks, toon: antrasiit. | Jura 5 L30 C2 H92 | Caparol | Amphibolin | 0.5358
S-04.1 | Esimene korrus | S-04.1 | Krohvitud ja värvitud sein, toon antrasiit | Jura 5 L30 C2 H92 | Caparol | Amphibolin | 10.5134
S-04.1 | Esimene korrus | S-04.1 | Krohvitud ja värvitud sein, toon antrasiit | Jura 5 L30 C2 H92 | Caparol | Amphibolin | 3.28153
S-01.1 | Esimene korrus | S-01.1 | Puhasvuuk sein, värvitud tumehalliks, toon: antrasiit. | Jura 5 L30 C2 H92 | Caparol | Amphibolin | 16.9397
S-01.1 | Esimene korrus | S-01.1 | Puhasvuuk sein, värvitud tumehalliks, toon: antrasiit. | Jura 5 L30 C2 H92 | Caparol | Amphibolin | 4.40729
S-01.1 | Esimene korrus | S-01.1 | Puhasvuuk sein, värvitud tumehalliks, toon: antrasiit. | Jura 5 L30 C2 H92 | Caparol | Amphibolin | 14.4875
S-04.1 | Esimene korrus | S-04.1 | Krohvitud ja värvitud sein, toon antrasiit | Jura 5 L30 C2 H92 | Caparol | Amphibolin | 11.7292
2 x S-04.1 | Esimene korrus | S-04.1 | Krohvitud ja värvitud sein, toon antrasiit | Jura 5 L30 C2 H92 | Caparol | Amphibolin | 2.60669
S-01.1 | Esimene korrus | S-01.1 | Puhasvuuk sein, värvitud tumehalliks, toon: antrasiit. | Jura 5 L30 C2 H92 | Caparol | Amphibolin | 4.6116
S-04.1 | Esimene korrus | S-04.1 | Krohvitud ja värvitud sein, toon antrasiit | Jura 5 L30 C2 H92 | Caparol | Amphibolin | 0.537709
S-04.1 | Esimene korrus | S-04.1 | Krohvitud ja värvitud sein, toon antrasiit | Jura 5 L30 C2 H92 | Caparol | Amphibolin | 1.07148
S-04.1 | Esimene korrus | S-04.1 | Krohvitud ja värvitud sein, toon antrasiit | Jura 5 L30 C2 H92 | Caparol | Amphibolin | 4.31468
2 x S-15 | Esimene korrus | S-15 | Krohvitud sein MP75 | Jura 60 L 88 C1 H92 (hele-hall). | Caparol | Amphibolin | 7.63725
S-01.2 | Esimene korrus | S-01.2 | Puhasvuuk sein, värvitud helehalliks. | Jura 60 L88C1 H92 | Caparol | Amphibolin | 15.4666
S-01.2 | Esimene korrus | S-01.2 | Puhasvuuk sein, värvitud helehalliks. | Jura 60 L88C1 H92 | Caparol | Amphibolin | 15.2344
2 x S-04.2 | Teine korrus | S-04.2 | Krohvitud ja värvitud sein, toon loodusvalge | Jura 60 L 88 C1 H92 (hele-hall) | Caparol | Amphibolin | 20.997
2 x S-04.2 | Teine korrus | S-04.2 | Krohvitud ja värvitud sein, toon loodusvalge | Jura 60 L 88 C1 H92 (hele-hall) | Caparol | Amphibolin | 16.0797
3 x S-04.2 | Teine korrus | S-04.2 | Krohvitud ja värvitud sein, toon loodusvalge | Jura 60 L 88 C1 H92 (hele-hall) | Caparol | Amphibolin | 3.8703
S-04.2 | Teine korrus | S-04.2 | Krohvitud ja värvitud sein, toon loodusvalge | Jura 60 L 88 C1 H92 (hele-hall) | Caparol | Amphibolin | 24.6112
S-04.1 | Teine korrus | S-04.1 | Krohvitud ja värvitud sein, toon antrasiit | Jura 5 L30 C2 H92 | Caparol | Amphibolin | 34.1744
S-04.2 | Teine korrus | S-04.2 | Krohvitud ja värvitud sein, toon loodusvalge | Jura 60 L 88 C1 H92 (hele-hall) | Caparol | Amphibolin | 10.6392
S-04.2 | Teine korrus | S-04.2 | Krohvitud ja värvitud sein, toon loodusvalge | Jura 60 L 88 C1 H92 (hele-hall) | Caparol | Amphibolin | 10.8407
S-04.2 | Teine korrus | S-04.2 | Krohvitud ja värvitud sein, toon loodusvalge | Jura 60 L 88 C1 H92 (hele-hall) | Caparol | Amphibolin | 11.1429
8 x S-09.1 | Teine korrus | S-09.1 | Krohvitud ja värvitud labori seinad, toon hele-hall | Jura 60 L 88 C1 H92 (hele-hall). | Caparol | Amphibolin | 23.2733
2 x S-09.1 | Teine korrus | S-09.1 | Krohvitud ja värvitud labori seinad, toon hele-hall | Jura 60 L 88 C1 H92 (hele-hall). | Caparol | Amphibolin | 13.6617
S-04.2 | Teine korrus | S-04.2 | Krohvitud ja värvitud sein, toon loodusvalge | Jura 60 L 88 C1 H92 (hele-hall) | Caparol | Amphibolin | 18.679
S-09.1 | Teine korrus | S-09.1 | Krohvitud ja värvitud labori seinad, toon hele-hall | Jura 60 L 88 C1 H92 (hele-hall). | Caparol | Amphibolin | 3.64715
S-09.1 | Teine korrus | S-09.1 | Krohvitud ja värvitud labori seinad, toon hele-hall | Jura 60 L 88 C1 H92 (hele-hall). | Caparol | Amphibolin | 46.0025
2 x S-09.1 | Teine korrus | S-09.1 | Krohvitud ja värvitud labori seinad, toon hele-hall | Jura 60 L 88 C1 H92 (hele-hall). | Caparol | Amphibolin | 0.62465
S-09.1 | Teine korrus | S-09.1 | Krohvitud ja värvitud labori seinad, toon hele-hall | Jura 60 L 88 C1 H92 (hele-hall). | Caparol | Amphibolin | 22.7897
S-09.1 | Teine korrus | S-09.1 | Krohvitud ja värvitud labori seinad, toon hele-hall | Jura 60 L 88 C1 H92 (hele-hall). | Caparol | Amphibolin | 6.75025
2 x S-09.1 | Teine korrus | S-09.1 | Krohvitud ja värvitud labori seinad, toon hele-hall | Jura 60 L 88 C1 H92 (hele-hall). | Caparol | Amphibolin | 15.767
S-09.1 | Teine korrus | S-09.1 | Krohvitud ja värvitud labori seinad, toon hele-hall | Jura 60 L 88 C1 H92 (hele-hall). | Caparol | Amphibolin | 2.51875
2 x S-09.1 | Teine korrus | S-09.1 | Krohvitud ja värvitud labori seinad, toon hele-hall | Jura 60 L 88 C1 H92 (hele-hall). | Caparol | Amphibolin | 13.8249
S-09.1 | Teine korrus | S-09.1 | Krohvitud ja värvitud labori seinad, toon hele-hall | Jura 60 L 88 C1 H92 (hele-hall). | Caparol | Amphibolin | 22.6284
4 x S-09.1 | Teine korrus | S-09.1 | Krohvitud ja värvitud labori seinad, toon hele-hall | Jura 60 L 88 C1 H92 (hele-hall). | Caparol | Amphibolin | 15.6026
2 x S-09.1 | Teine korrus | S-09.1 | Krohvitud ja värvitud labori seinad, toon hele-hall | Jura 60 L 88 C1 H92 (hele-hall). | Caparol | Amphibolin | 22.6642
2 x S-09.1 | Teine korrus | S-09.1 | Krohvitud ja värvitud labori seinad, toon hele-hall | Jura 60 L 88 C1 H92 (hele-hall). | Caparol | Amphibolin | 11.6669
2 x S-09.1 | Teine korrus | S-09.1 | Krohvitud ja värvitud labori seinad, toon hele-hall | Jura 60 L 88 C1 H92 (hele-hall). | Caparol | Amphibolin | 11.0221
2 x S-09.1 | Teine korrus | S-09.1 | Krohvitud ja värvitud labori seinad, toon hele-hall | Jura 60 L 88 C1 H92 (hele-hall). | Caparol | Amphibolin | 9.65991
4 x S-09.1 | Teine korrus | S-09.1 | Krohvitud ja värvitud labori seinad, toon hele-hall | Jura 60 L 88 C1 H92 (hele-hall). | Caparol | Amphibolin | 28.5324
2 x S-09.1 | Teine korrus | S-09.1 | Krohvitud ja värvitud labori seinad, toon hele-hall | Jura 60 L 88 C1 H92 (hele-hall). | Caparol | Amphibolin | 13.029
2 x S-09.2 | Teine korrus | S-09.2 | Pestavad seinad ruumis 240, toode Sikagard AL-12 süsteem, toon hele-hall. | RAL 7047 | Sika | AL-12 | 28.5324
2 x S-09.1 | Teine korrus | S-09.1 | Krohvitud ja värvitud labori seinad, toon hele-hall | Jura 60 L 88 C1 H92 (hele-hall). | Caparol | Amphibolin | 19.2231
2 x S-09.1 | Teine korrus | S-09.1 | Krohvitud ja värvitud labori seinad, toon hele-hall | Jura 60 L 88 C1 H92 (hele-hall). | Caparol | Amphibolin | 18.1348
2 x S-09.2 | Teine korrus | S-09.2 | Pestavad seinad ruumis 240, toode Sikagard AL-12 süsteem, toon hele-hall. | RAL 7047 | Sika | AL-12 | 48.1504
S-04.2 | Teine korrus | S-04.2 | Krohvitud ja värvitud sein, toon loodusvalge | Jura 60 L 88 C1 H92 (hele-hall) | Caparol | Amphibolin | 30.1041
S-04.2 | Teine korrus | S-04.2 | Krohvitud ja värvitud sein, toon loodusvalge | Jura 60 L 88 C1 H92 (hele-hall) | Caparol | Amphibolin | 32.6833
S-09.1 | Teine korrus | S-09.1 | Krohvitud ja värvitud labori seinad, toon hele-hall | Jura 60 L 88 C1 H92 (hele-hall). | Caparol | Amphibolin | 26.1507
S-04.1 | Teine korrus | S-04.1 | Krohvitud ja värvitud sein, toon antrasiit | Jura 5 L30 C2 H92 | Caparol | Amphibolin | 11.16
2 x S-04.1 | Teine korrus | S-04.1 | Krohvitud ja värvitud sein, toon antrasiit | Jura 5 L30 C2 H92 | Caparol | Amphibolin | 21.04
S-04.1 | Teine korrus | S-04.1 | Krohvitud ja värvitud sein, toon antrasiit | Jura 5 L30 C2 H92 | Caparol | Amphibolin | 2.6226
S-04.2 | Teine korrus | S-04.2 | Krohvitud ja värvitud sein, toon loodusvalge | Jura 60 L 88 C1 H92 (hele-hall) | Caparol | Amphibolin | 114.674
S-04.2 | Teine korrus | S-04.2 | Krohvitud ja värvitud sein, toon loodusvalge | Jura 60 L 88 C1 H92 (hele-hall) | Caparol | Amphibolin | 32.3206
2 x S-04.2 | Teine korrus | S-04.2 | Krohvitud ja värvitud sein, toon loodusvalge | Jura 60 L 88 C1 H92 (hele-hall) | Caparol | Amphibolin | 10.7601
S-04.2 | Teine korrus | S-04.2 | Krohvitud ja värvitud sein, toon loodusvalge | Jura 60 L 88 C1 H92 (hele-hall) | Caparol | Amphibolin | 6.2465
S-04.2 | Teine korrus | S-04.2 | Krohvitud ja värvitud sein, toon loodusvalge | Jura 60 L 88 C1 H92 (hele-hall) | Caparol | Amphibolin | 17.3693
S-04.2 | Teine korrus | S-04.2 | Krohvitud ja värvitud sein, toon loodusvalge | Jura 60 L 88 C1 H92 (hele-hall) | Caparol | Amphibolin | 12.493
S-04.2 | Teine korrus | S-04.2 | Krohvitud ja värvitud sein, toon loodusvalge | Jura 60 L 88 C1 H92 (hele-hall) | Caparol | Amphibolin | 22.8904
S-04.2 | Teine korrus | S-04.2 | Krohvitud ja värvitud sein, toon loodusvalge | Jura 60 L 88 C1 H92 (hele-hall) | Caparol | Amphibolin | 45.398
4 x S-01.2 | Teine korrus | S-01.2 | Puhasvuuk sein, värvitud helehalliks. | Jura 60 L88C1 H92 | Caparol | Amphibolin | 30.1041
2 x S-01.2 | Teine korrus | S-01.2 | Puhasvuuk sein, värvitud helehalliks. | Jura 60 L88C1 H92 | Caparol | Amphibolin | 30.5071
2 x S-01.2 | Teine korrus | S-01.2 | Puhasvuuk sein, värvitud helehalliks. | Jura 60 L88C1 H92 | Caparol | Amphibolin | 11.4049
S-04.2 | Teine korrus | S-04.2 | Krohvitud ja värvitud sein, toon loodusvalge | Jura 60 L 88 C1 H92 (hele-hall) | Caparol | Amphibolin | 6.55278
S-04.2 | Teine korrus | S-04.2 | Krohvitud ja värvitud sein, toon loodusvalge | Umbraweiss L92 C4 H85 | Caparol | Amphibolin | 5.51304
S-09.1 | Teine korrus | S-09.1 | Krohvitud ja värvitud labori seinad, toon hele-hall | Jura 60 L 88 C1 H92 (hele-hall). | Caparol | Amphibolin | 6.06515

# IfcCovering: Aknapale_terass 2 42 x 364, FSP-100
In: Teine korrus
Classification: 1.07 IfcCoveringType (pinnadetailid) (BIM ÜBN + Archicad Classification); Material: 40 Kiht: Teras
AR_Viimistlus - 001_Nimetus: Paleplekk
AR_ÜLD - 001_Nimetus: Paleplekk; 009_Märkus: vt. AR-7 sõlmlahendusi
AR_ABI - 200_Materjal (MUDELIS): 40 Kiht: Teras
AC_Pset_RenovationAndPhasing - Renovation Status: New

# IfcCovering: Aknapale_terass 3 42 x 444, FSP-100
In: Teine korrus
Classification: 1.07 IfcCoveringType (pinnadetailid) (BIM ÜBN + Archicad Classification); Material: 40 Kiht: Teras
AR_ABI - 200_Materjal (MUDELIS): 40 Kiht: Teras
AC_Pset_RenovationAndPhasing - Renovation Status: New
AR_Viimistlus - 001_Nimetus: Paleplekk
AR_ÜLD - 001_Nimetus: Paleplekk; 009_Märkus: vt. AR-7 sõlmlahendusi

# IfcCovering: Aknapale_terass 42 x 261 (2)
In: Teine korrus
Classification: 1.07 IfcCoveringType (pinnadetailid) (BIM ÜBN + Archicad Classification); Material: 40 Kiht: Teras
AR_Viimistlus - 001_Nimetus: Paleplekk
AR_ÜLD - 001_Nimetus: Paleplekk; 009_Märkus: vt. AR-7 sõlmlahendusi
AR_ABI - 200_Materjal (MUDELIS): 40 Kiht: Teras
AC_Pset_RenovationAndPhasing - Renovation Status: New

# IfcCovering: FSD-01 (75)
In: Esimene korrus
Classification: 1.07 IfcCoveringType (pinnadetailid) (BIM ÜBN + Archicad Classification); Material: 30 Konst: puit 01
AR_Viimistlus - 001_Nimetus: Fassaadi sõrestik
AR_ÜLD - 001_Nimetus: Fassaadi sõrestik; 009_Märkus: vt. FSD-02 skeemi
AR_ABI - 200_Materjal (MUDELIS): 30 Konst: puit 01
AC_Pset_RenovationAndPhasing - Renovation Status: New

# IfcCovering: FSD-01_N1
In: Esimene korrus
Classification: 1.07 IfcCoveringType (pinnadetailid) (BIM ÜBN + Archicad Classification); Material: 30 Konst: puit 01
AR_Viimistlus - 001_Nimetus: Fassaadi sõrestik
AR_ÜLD - 001_Nimetus: Fassaadi sõrestik; 009_Märkus: vt. FSD-02 skeemi
AC_Pset_RenovationAndPhasing - Renovation Status: New
AR_ABI - 200_Materjal (MUDELIS): 30 Konst: puit 01

# IfcCovering: FSD-01_N2_2, FSD-01_N2
In: Esimene korrus
Classification: 1.07 IfcCoveringType (pinnadetailid) (BIM ÜBN + Archicad Classification); Material: 30 Konst: puit 01
AR_ÜLD - 001_Nimetus: Fassaadi sõrestik; 009_Märkus: vt. FSD-02 skeemi
AR_Viimistlus - 001_Nimetus: Fassaadi sõrestik
AC_Pset_RenovationAndPhasing - Renovation Status: New
AR_ABI - 200_Materjal (MUDELIS): 30 Konst: puit 01

# IfcCovering: FSD-01_N3
In: Esimene korrus
Classification: 1.07 IfcCoveringType (pinnadetailid) (BIM ÜBN + Archicad Classification); Material: 30 Konst: puit 01
AR_Viimistlus - 001_Nimetus: Fassaadi sõrestik
AR_ABI - 200_Materjal (MUDELIS): 30 Konst: puit 01
AC_Pset_RenovationAndPhasing - Renovation Status: New
AR_ÜLD - 001_Nimetus: Fassaadi sõrestik; 009_Märkus: vt. FSD-02 skeemi

# IfcCovering: FSD-01_N4
In: Esimene korrus
Classification: 1.07 IfcCoveringType (pinnadetailid) (BIM ÜBN + Archicad Classification); Material: 30 Konst: puit 01
AR_Viimistlus - 001_Nimetus: Fassaadi sõrestik
AR_ÜLD - 001_Nimetus: Fassaadi sõrestik; 009_Märkus: vt. FSD-02 skeemi
AR_ABI - 200_Materjal (MUDELIS): 30 Konst: puit 01
AC_Pset_RenovationAndPhasing - Renovation Status: New

# IfcCovering: FSD-02 (213)
Classification: 1.07 IfcCoveringType (pinnadetailid) (BIM ÜBN + Archicad Classification); Material: 30 Konst: puit 01
AR_ÜLD - 001_Nimetus: Fassaadi sõrestik; 009_Märkus: vt. FSD-02 skeemi
AR_Viimistlus - 001_Nimetus: Fassaadi sõrestik
AR_ABI - 200_Materjal (MUDELIS): 30 Konst: puit 01
AC_Pset_RenovationAndPhasing - Renovation Status: New
Name | In
108 x FSD-02 | Esimene korrus
105 x FSD-02 | Teine korrus

# IfcCovering: FSD-02_N1 (3)
In: Esimene korrus
Classification: 1.07 IfcCoveringType (pinnadetailid) (BIM ÜBN + Archicad Classification); Material: 30 Konst: puit 01
AR_Viimistlus - 001_Nimetus: Fassaadi sõrestik
AR_ÜLD - 001_Nimetus: Fassaadi sõrestik; 009_Märkus: vt. FSD-02 skeemi
AR_ABI - 200_Materjal (MUDELIS): 30 Konst: puit 01
AC_Pset_RenovationAndPhasing - Renovation Status: New

# IfcCovering: FSD-02_N2 (3)
In: Esimene korrus
Classification: 1.07 IfcCoveringType (pinnadetailid) (BIM ÜBN + Archicad Classification); Material: 30 Konst: puit 01
AR_Viimistlus - 001_Nimetus: Fassaadi sõrestik
AR_ÜLD - 001_Nimetus: Fassaadi sõrestik; 009_Märkus: vt. FSD-02 skeemi
AR_ABI - 200_Materjal (MUDELIS): 30 Konst: puit 01
AC_Pset_RenovationAndPhasing - Renovation Status: New

# IfcCovering: FSD-02_N3 (3)
Classification: 1.07 IfcCoveringType (pinnadetailid) (BIM ÜBN + Archicad Classification); Material: 30 Konst: puit 01
AR_Viimistlus - 001_Nimetus: Fassaadi sõrestik
AR_ÜLD - 001_Nimetus: Fassaadi sõrestik; 009_Märkus: vt. FSD-02 skeemi
AR_ABI - 200_Materjal (MUDELIS): 30 Konst: puit 01
AC_Pset_RenovationAndPhasing - Renovation Status: New
Name | In
2 x FSD-02_N3 | Esimene korrus
FSD-02_N3 | Teine korrus

# IfcCovering: FSD-02_N4 (3)
Classification: 1.07 IfcCoveringType (pinnadetailid) (BIM ÜBN + Archicad Classification); Material: 30 Konst: puit 01
AR_ÜLD - 001_Nimetus: Fassaadi sõrestik; 009_Märkus: vt. FSD-02 skeemi
AR_ABI - 200_Materjal (MUDELIS): 30 Konst: puit 01
AC_Pset_RenovationAndPhasing - Renovation Status: New
AR_Viimistlus - 001_Nimetus: Fassaadi sõrestik
Name | In
2 x FSD-02_N4 | Esimene korrus
FSD-02_N4 | Teine korrus

# IfcCovering: FSD-03 (359)
Classification: 1.07 IfcCoveringType (pinnadetailid) (BIM ÜBN + Archicad Classification); Material: 30 Konst: puit 01
AR_Viimistlus - 001_Nimetus: Fassaadi sõrestik
AR_ÜLD - 001_Nimetus: Fassaadi sõrestik; 009_Märkus: vt. FSD-02 skeemi
AR_ABI - 200_Materjal (MUDELIS): 30 Konst: puit 01
AC_Pset_RenovationAndPhasing - Renovation Status: New
Name | In
132 x FSD-03 | Teine korrus
227 x FSD-03 | Katus

# IfcCovering: FSD-03_N1 (4)
Classification: 1.07 IfcCoveringType (pinnadetailid) (BIM ÜBN + Archicad Classification); Material: 30 Konst: puit 01
AR_Viimistlus - 001_Nimetus: Fassaadi sõrestik
AR_ÜLD - 001_Nimetus: Fassaadi sõrestik; 009_Märkus: vt. FSD-02 skeemi
AR_ABI - 200_Materjal (MUDELIS): 30 Konst: puit 01
AC_Pset_RenovationAndPhasing - Renovation Status: New
Name | In
2 x FSD-03_N1 | Teine korrus
2 x FSD-03_N1 | Katus

# IfcCovering: FSD-03_N2 (4)
Classification: 1.07 IfcCoveringType (pinnadetailid) (BIM ÜBN + Archicad Classification); Material: 30 Konst: puit 01
AR_Viimistlus - 001_Nimetus: Fassaadi sõrestik
AC_Pset_RenovationAndPhasing - Renovation Status: New
AR_ÜLD - 001_Nimetus: Fassaadi sõrestik; 009_Märkus: vt. FSD-02 skeemi
AR_ABI - 200_Materjal (MUDELIS): 30 Konst: puit 01
Name | In
2 x FSD-03_N2 | Teine korrus
2 x FSD-03_N2 | Katus

# IfcCovering: FSD-03_N3 (4)
Classification: 1.07 IfcCoveringType (pinnadetailid) (BIM ÜBN + Archicad Classification); Material: 30 Konst: puit 01
AR_Viimistlus - 001_Nimetus: Fassaadi sõrestik
AR_ABI - 200_Materjal (MUDELIS): 30 Konst: puit 01
AC_Pset_RenovationAndPhasing - Renovation Status: New
AR_ÜLD - 001_Nimetus: Fassaadi sõrestik; 009_Märkus: vt. FSD-02 skeemi
Name | In
2 x FSD-03_N3 | Teine korrus
2 x FSD-03_N3 | Katus

# IfcCovering: FSD-03_N4 (4)
Classification: 1.07 IfcCoveringType (pinnadetailid) (BIM ÜBN + Archicad Classification); Material: 30 Konst: puit 01
AR_Viimistlus - 001_Nimetus: Fassaadi sõrestik
AR_ÜLD - 001_Nimetus: Fassaadi sõrestik; 009_Märkus: vt. FSD-02 skeemi
AR_ABI - 200_Materjal (MUDELIS): 30 Konst: puit 01
AC_Pset_RenovationAndPhasing - Renovation Status: New
Name | In
2 x FSD-03_N4 | Teine korrus
2 x FSD-03_N4 | Katus

# IfcCovering: FSD_M1 (2)
In: Esimene korrus
Classification: 1.07 IfcCoveringType (pinnadetailid) (BIM ÜBN + Archicad Classification); Material: 30 Konst: puit 01
AR_Viimistlus - 001_Nimetus: Fassaadi sõrestik
AR_ÜLD - 001_Nimetus: Fassaadi sõrestik; 009_Märkus: vt. FSD-02 skeemi
AR_ABI - 200_Materjal (MUDELIS): 30 Konst: puit 01
AC_Pset_RenovationAndPhasing - Renovation Status: New
Name
FSD-M1b
FSD-M1a

# IfcCovering: FSD_M2 (2)
In: Esimene korrus
Classification: 1.07 IfcCoveringType (pinnadetailid) (BIM ÜBN + Archicad Classification); Material: 30 Konst: puit 01
AR_Viimistlus - 001_Nimetus: Fassaadi sõrestik
AR_ÜLD - 001_Nimetus: Fassaadi sõrestik; 009_Märkus: vt. FSD-02 skeemi
AR_ABI - 200_Materjal (MUDELIS): 30 Konst: puit 01
AC_Pset_RenovationAndPhasing - Renovation Status: New
Name
FSD-M2b
FSD-M2a

# IfcCovering: FSD_M3 (2)
In: Esimene korrus
Classification: 1.07 IfcCoveringType (pinnadetailid) (BIM ÜBN + Archicad Classification); Material: 30 Konst: puit 01
AR_ÜLD - 001_Nimetus: Fassaadi sõrestik; 009_Märkus: vt. FSD-02 skeemi
AC_Pset_RenovationAndPhasing - Renovation Status: New
AR_ABI - 200_Materjal (MUDELIS): 30 Konst: puit 01
AR_Viimistlus - 001_Nimetus: Fassaadi sõrestik
Name
FSD-M3b
FSD-M3a

# IfcCovering: FSD_M4 (2)
In: Esimene korrus
Classification: 1.07 IfcCoveringType (pinnadetailid) (BIM ÜBN + Archicad Classification); Material: 30 Konst: puit 01
AR_Viimistlus - 001_Nimetus: Fassaadi sõrestik
AR_ÜLD - 001_Nimetus: Fassaadi sõrestik; 009_Märkus: vt. FSD-02 skeemi
AR_ABI - 200_Materjal (MUDELIS): 30 Konst: puit 01
AC_Pset_RenovationAndPhasing - Renovation Status: New
Name
FSD-M4b
FSD-M4a

# IfcCovering: FSD_M5 (2)
In: Esimene korrus
Classification: 1.07 IfcCoveringType (pinnadetailid) (BIM ÜBN + Archicad Classification); Material: 30 Konst: puit 01
AR_ÜLD - 001_Nimetus: Fassaadi sõrestik; 009_Märkus: vt. FSD-02 skeemi
AC_Pset_RenovationAndPhasing - Renovation Status: New
AR_Viimistlus - 001_Nimetus: Fassaadi sõrestik
AR_ABI - 200_Materjal (MUDELIS): 30 Konst: puit 01
Name
FSD-M5b
FSD-M5a

# IfcCovering: FSD_M6 (2)
In: Esimene korrus
Classification: 1.07 IfcCoveringType (pinnadetailid) (BIM ÜBN + Archicad Classification); Material: 30 Konst: puit 01
AR_Viimistlus - 001_Nimetus: Fassaadi sõrestik
AR_ÜLD - 001_Nimetus: Fassaadi sõrestik; 009_Märkus: vt. FSD-02 skeemi
AR_ABI - 200_Materjal (MUDELIS): 30 Konst: puit 01
AC_Pset_RenovationAndPhasing - Renovation Status: New
Name
FSD-M6b
FSD-M6a

# IfcCovering: FSD_M7 (2)
In: Esimene korrus
Classification: 1.07 IfcCoveringType (pinnadetailid) (BIM ÜBN + Archicad Classification); Material: 30 Konst: puit 01
AR_ÜLD - 001_Nimetus: Fassaadi sõrestik; 009_Märkus: vt. FSD-02 skeemi
AR_Viimistlus - 001_Nimetus: Fassaadi sõrestik
AR_ABI - 200_Materjal (MUDELIS): 30 Konst: puit 01
AC_Pset_RenovationAndPhasing - Renovation Status: New
Name
FSD-M7b
FSD-M7a

# IfcCovering: FSD_M8 (2)
In: Esimene korrus
Classification: 1.07 IfcCoveringType (pinnadetailid) (BIM ÜBN + Archicad Classification); Material: 30 Konst: puit 01
AR_ÜLD - 001_Nimetus: Fassaadi sõrestik; 009_Märkus: vt. FSD-02 skeemi
AR_ABI - 200_Materjal (MUDELIS): 30 Konst: puit 01
AR_Viimistlus - 001_Nimetus: Fassaadi sõrestik
AC_Pset_RenovationAndPhasing - Renovation Status: New
Name
FSD-M8b
FSD-M8a

# IfcCovering: FSD_M9, FSD-M9b
In: Esimene korrus
Classification: 1.07 IfcCoveringType (pinnadetailid) (BIM ÜBN + Archicad Classification); Material: 30 Konst: puit 01
AR_ÜLD - 001_Nimetus: Fassaadi sõrestik; 009_Märkus: vt. FSD-02 skeemi
AR_Viimistlus - 001_Nimetus: Fassaadi sõrestik
AR_ABI - 200_Materjal (MUDELIS): 30 Konst: puit 01
AC_Pset_RenovationAndPhasing - Renovation Status: New

# IfcCovering: L-01 (tolmutõke) 5 (5)
Type - PredefinedType: CEILING
Classification: 1.04 IfcCoveringType.CEILING (ripplagi) (BIM ÜBN + Archicad Classification); Material: 80 Siseviim: tolmutõke
Pset_CoveringCommon - Reference: L-01; TotalThickness: 5 mm
AR_Viimistlus - 001_Nimetus: Betoonlagi, viimistlus tolmutõke; 205_Tähis: L-01; 215_Tuletundlikkus: A2-s1,d0; 220_Viimistlus: Matt; 230_Niiskuskindel: no; 235_Karkass: -; 900_Tootja: Caparol; 905_Mudel: Disbopox 443; 910_Tooteinfo: ootel; 915_Kasutus-ja-hooldusjuhend: ootel; 210_Paksus: 5 mm
AR_ÜLD - 001_Nimetus: Betoonlagi, viimistlus tolmutõke; 009_Märkus: OMA märkus
AR_ABI - 200_Materjal (MUDELIS): 80 Siseviim: tolmutõke
AC_Pset_RenovationAndPhasing - Renovation Status: New
Name | In | 225_Pindala (m2)
L-01 | Esimene korrus | 2.502
L-01 | Teine korrus | 7.6401
L-01 | Teine korrus | 60.7133
L-01 | Teine korrus | 11.2228
L-01 | Teine korrus | 10.6025

# IfcCovering: L-02 (puitkiud plaat) 92 (15)
In: Esimene korrus
Type - PredefinedType: CEILING
Classification: 1.04 IfcCoveringType.CEILING (ripplagi) (BIM ÜBN + Archicad Classification)
Pset_CoveringCommon - Reference: L-02; TotalThickness: 92 mm
AR_Viimistlus - 001_Nimetus: 15 mm puitkiudlagi, toon hallikas-beež.; 205_Tähis: L-02; 215_Tuletundlikkus: B-s1,d0; 220_Viimistlus: Natural N; 230_Niiskuskindel: no; 235_Karkass: CD-kandekarkass 27mm; 900_Tootja: Cewood; 905_Mudel: Cewood panel; 910_Tooteinfo: ootel; 915_Kasutus-ja-hooldusjuhend: ootel; 210_Paksus: 92 mm
AR_ÜLD - 001_Nimetus: 15 mm puitkiudlagi, toon hallikas-beež.; 009_Märkus: OMA märkus
AC_Pset_RenovationAndPhasing - Renovation Status: New
AR_ABI - 200_Materjal (MUDELIS): 50 Soojustus: klaasvill; 70 Kiht: Õhkvahe karkass; 60 Plaat: Puitkiudplaat
Name | 225_Pindala (m2)
L-02 | 15.2955
L-02 | 7.416
2 x L-02 | 14.877
L-02 | 9.207
L-02 | 15.12
L-02 | 15.174
L-02 | 14.202
L-02 | 43.836
L-02 | 10.962
L-02 | 14.196
L-02 | 14.833
L-02 | 14.729
L-02 | 12.636
L-02 | 7.1755

# IfcCovering: L-03a puitribi karkass 40 (19)
Type - PredefinedType: CEILING
Classification: 1.04 IfcCoveringType.CEILING (ripplagi) (BIM ÜBN + Archicad Classification); Material: 90 Viim: Õhkvahe karkass
Pset_CoveringCommon - TotalThickness: 40 mm
AR_Viimistlus - 230_Niiskuskindel: no; 235_Karkass: -; 910_Tooteinfo: ootel; 915_Kasutus-ja-hooldusjuhend: ootel; 210_Paksus: 40 mm
AR_ÜLD - 009_Märkus: OMA märkus
AR_ABI - 200_Materjal (MUDELIS): 90 Viim: Õhkvahe karkass
AC_Pset_RenovationAndPhasing - Renovation Status: New
Name | In | Reference = 205_Tähis | AR_Viimistlus, 001_Nimetus = AR_ÜLD, 001_Nimetus | 215_Tuletundlikkus | 220_Viimistlus | 900_Tootja | 905_Mudel | 225_Pindala (m2)
L-03b | Esimene korrus | L-03b | Akustline villaplaat 40 mm, must. | A2-s1,d0 | Must | Ecophon | Industry | 6.954
L-03b | Teine korrus | L-03b | Akustline villaplaat 40 mm, must. | A2-s1,d0 | Must | Ecophon | Industry | 18.9772
L-03b | Teine korrus | L-03b | Akustline villaplaat 40 mm, must. | A2-s1,d0 | Must | Ecophon | Industry | 12.1637
L-03c | Teine korrus | L-03c | Puitribilae karkass | - | ootel | ootel | ootel | 22.2047
L-03b | Teine korrus | L-03b | Akustline villaplaat 40 mm, must. | A2-s1,d0 | Must | Ecophon | Industry | 170.54
2 x L-03b | Teine korrus | L-03b | Akustline villaplaat 40 mm, must. | A2-s1,d0 | Must | Ecophon | Industry | 12.1208
4 x L-03b | Teine korrus | L-03b | Akustline villaplaat 40 mm, must. | A2-s1,d0 | Must | Ecophon | Industry | 11.9682
L-03b | Teine korrus | L-03b | Akustline villaplaat 40 mm, must. | A2-s1,d0 | Must | Ecophon | Industry | 12.0118
L-03b | Teine korrus | L-03b | Akustline villaplaat 40 mm, must. | A2-s1,d0 | Must | Ecophon | Industry | 21.4294
L-03b | Teine korrus | L-03b | Akustline villaplaat 40 mm, must. | A2-s1,d0 | Must | Ecophon | Industry | 9.7916
L-03b | Teine korrus | L-03b | Akustline villaplaat 40 mm, must. | A2-s1,d0 | Must | Ecophon | Industry | 9.6096
L-03b | Teine korrus | L-03b | Akustline villaplaat 40 mm, must. | A2-s1,d0 | Must | Ecophon | Industry | 10.0646
L-03c | Teine korrus | L-03c | Akustline villaplaat 40 mm, must. | A2-s1,d0 | Must | Ecophon | Industry | 24.9964
L-03b | Teine korrus | L-03b | Akustline villaplaat 40 mm, must. | A2-s1,d0 | Must | Ecophon | Industry | 17.4173
L-03b | Teine korrus | L-03b | Akustline villaplaat 40 mm, must. | A2-s1,d0 | Must | Ecophon | Industry | 14.6754

# IfcCovering: L-03b akustline villaplaat 40 (50)
Type - PredefinedType: CEILING
Classification: 1.04 IfcCoveringType.CEILING (ripplagi) (BIM ÜBN + Archicad Classification); Material: 71 Kiht: akustiline plaat
Pset_CoveringCommon - TotalThickness: 40 mm
AR_Viimistlus - 001_Nimetus: Akustline villaplaat 40 mm, must.; 215_Tuletundlikkus: A2-s1,d0; 220_Viimistlus: Must; 230_Niiskuskindel: no; 235_Karkass: -; 900_Tootja: Ecophon; 905_Mudel: Industry; 910_Tooteinfo: ootel; 915_Kasutus-ja-hooldusjuhend: ootel; 210_Paksus: 40 mm
AR_ÜLD - 001_Nimetus: Akustline villaplaat 40 mm, must.; 009_Märkus: OMA märkus
AR_ABI - 200_Materjal (MUDELIS): 71 Kiht: akustiline plaat
AC_Pset_RenovationAndPhasing - Renovation Status: New
Name | In | Reference = 205_Tähis | 225_Pindala (m2)
L-03b | Esimene korrus | L-03b | 12.731
L-03b | Esimene korrus | L-03b | 31.0194
L-03b | Esimene korrus | L-03b | 25.0902
L-03b | Esimene korrus | L-03b | 26.8074
L-03b | Esimene korrus | L-03b | 26.712
L-03b | Esimene korrus | L-03b | 27.0221
L-03b | Esimene korrus | L-03b | 27.2136
2 x L-03b | Esimene korrus | L-03b | 26.2827
L-03b | Esimene korrus | L-03b | 16.2657
L-03b | Esimene korrus | L-03b | 21.4653
L-03b | Esimene korrus | L-03b | 27.5885
L-03b | Esimene korrus | L-03b | 82.1082
L-03b | Esimene korrus | L-03b | 26.5902
L-03b | Esimene korrus | L-03b | 27.7833
L-03b | Esimene korrus | L-03b | 28.4761
L-03b | Esimene korrus | L-03b | 6.954
L-03b | Esimene korrus | L-03b | 68.3602
4 x L-03b | Teine korrus | L-03b | 12.7231
L-03b | Teine korrus | L-03b | 12.7694
2 x L-03b | Teine korrus | L-03b | 12.8853
L-03b | Teine korrus | L-03b | 10.7331
L-03b | Teine korrus | L-03b | 12.9309
L-03b | Teine korrus | L-03b | 171.125
L-03b | Teine korrus | L-03b | 24.1028
L-03b | Teine korrus | L-03b | 32.4779
L-03b | Teine korrus | L-03b | 22.8896
L-03b | Teine korrus | L-03b | 11.2083
L-03b | Teine korrus | L-03b | 84.5918
L-03b | Teine korrus | L-03b | 16.9708
L-03b | Teine korrus | L-03b | 10.5889
L-03b | Teine korrus | L-03b | 19.8631
L-03b | Teine korrus | L-03b | 65.0524
L-03b | Teine korrus | L-03b | 21.4648
L-03b | Teine korrus | L-03b | 19.8111
L-03b | Teine korrus | L-03b | 55.1084
L-03b | Teine korrus | L-03b | 21.1401
L-03b | Teine korrus | L-03b | 60.5817
L-03b | Teine korrus | L-03b | 92.3916
L-03b | Teine korrus | L-03b | 22.781
L-03b | Teine korrus | L-03b | 27.3184
L-03c | Teine korrus | L-03c | 21.0411
L-03b | Teine korrus | L-03b | 10.5336
L-03b | Teine korrus | L-03b | 11.0323
L-03c | Teine korrus | L-03c | 27.2962
L-03b | Teine korrus | L-03b | 6.954

# IfcCovering: L-03b akustline villaplaat 40 (4)
In: Esimene korrus
Type - PredefinedType: FLOORING
Classification: 1.06 IfcCoveringType.FLOORING (põrandakatted) (BIM ÜBN + Archicad Classification); Material: 71 Kiht: akustiline plaat
Pset_CoveringCommon - Reference: L-03c; TotalThickness: 40 mm
AR_Viimistlus - 001_Nimetus: Nähtav betoon, kaetud tolmutõkkega; 205_Tähis: L-03c; 215_Tuletundlikkus: -; 220_Viimistlus: ootel; 230_Niiskuskindel: no; 900_Tootja: ootel; 905_Mudel: ootel; 910_Tooteinfo: ootel; 915_Kasutus-ja-hooldusjuhend: ootel; 245_Aluspind: ootel; 210_Paksus: 40 mm
AR_ÜLD - 001_Nimetus: Nähtav betoon, kaetud tolmutõkkega; 009_Märkus: OMA märkus
AR_ABI - 200_Materjal (MUDELIS): 71 Kiht: akustiline plaat
AC_Pset_RenovationAndPhasing - Renovation Status: New
Name | 225_Pindala (m2)
L-03c | 14.6034
L-03c | 12.474
L-03c | 6.87244
L-03c | 14.2477

# IfcCovering: L-04 (akustline kips, valge) 70 (4)
Type - PredefinedType: CEILING
Classification: 1.04 IfcCoveringType.CEILING (ripplagi) (BIM ÜBN + Archicad Classification)
AC_Pset_RenovationAndPhasing - Renovation Status: New
AR_ABI - 200_Materjal (MUDELIS): 50 Soojustus: kivivill; 70 Kiht: Õhkvahe karkass; 71 Kiht: akustiline plaat
AR_ÜLD - 001_Nimetus: Akustline kipslagi, valge; 009_Märkus: OMA märkus
AR_Viimistlus - 001_Nimetus: Akustline kipslagi, valge; 205_Tähis: L-04; 215_Tuletundlikkus: C-s2,d1; 220_Viimistlus: Valge; 230_Niiskuskindel: no; 235_Karkass: CD-kandekarkass 27mm; 900_Tootja: Knauf; 905_Mudel: Cleaneo; 910_Tooteinfo: ootel; 915_Kasutus-ja-hooldusjuhend: ootel; 210_Paksus: 70 mm
Pset_CoveringCommon - Reference: L-04; TotalThickness: 70 mm
Name | In | 225_Pindala (m2)
L-04 | Esimene korrus | 7.75501
L-04 | Esimene korrus | 3.32493
L-04 | Teine korrus | 2.00946
L-04 | Teine korrus | 1.99215

# IfcCovering: L-05-1 kips (terrakota) 102 (3)
In: Esimene korrus
Type - PredefinedType: CEILING
Classification: 1.04 IfcCoveringType.CEILING (ripplagi) (BIM ÜBN + Archicad Classification)
AR_ABI - 200_Materjal (MUDELIS): 50 Soojustus: kivivill; 70 Kiht: Õhkvahe karkass; 60 Plaat: Kipsplaat
AR_ÜLD - 009_Märkus: OMA märkus
AR_Viimistlus - 215_Tuletundlikkus: C-s2,d1; 220_Viimistlus: virsik; 230_Niiskuskindel: no; 235_Karkass: CD-kandekarkass 27mm; 900_Tootja: Knauf; 905_Mudel: -; 910_Tooteinfo: ootel; 915_Kasutus-ja-hooldusjuhend: ootel; 210_Paksus: 102 mm
Pset_CoveringCommon - TotalThickness: 102 mm
AC_Pset_RenovationAndPhasing - Renovation Status: New
Name | AR_ÜLD, 001_Nimetus = AR_Viimistlus, 001_Nimetus | 205_Tähis = Reference | 225_Pindala (m2)
L-05-1 | Niiskuskindel silekipslagi, virsik | L-05-1 | 17.8352
L-05-3 | Silekipslagi, virsik | L-05-3 | 5.27846
L-05-1 | Niiskuskindel silekipslagi, virsik | L-05-1 | 7.90362

# IfcCovering: L-05-2 kips (sinine) 102 (2)
In: Esimene korrus
Type - PredefinedType: CEILING
Classification: 1.04 IfcCoveringType.CEILING (ripplagi) (BIM ÜBN + Archicad Classification)
Pset_CoveringCommon - Reference: L-05-1; TotalThickness: 102 mm
AR_Viimistlus - 001_Nimetus: Niiskuskindel silekipslagi, virsik; 205_Tähis: L-05-1; 215_Tuletundlikkus: C-s2,d1; 220_Viimistlus: virsik; 230_Niiskuskindel: no; 235_Karkass: CD-kandekarkass 27mm; 900_Tootja: Knauf; 905_Mudel: -; 910_Tooteinfo: ootel; 915_Kasutus-ja-hooldusjuhend: ootel; 210_Paksus: 102 mm
AR_ABI - 200_Materjal (MUDELIS): 50 Soojustus: kivivill; 70 Kiht: Õhkvahe karkass; 60 Plaat: Kipsplaat
AC_Pset_RenovationAndPhasing - Renovation Status: New
AR_ÜLD - 001_Nimetus: Niiskuskindel silekipslagi, virsik; 009_Märkus: OMA märkus
Name | 225_Pindala (m2)
L-05-1 | 13.2765
L-05-1 | 5.88331

# IfcCovering: L-05-3 kips (roheline) 102 (10)
Type - PredefinedType: CEILING
Classification: 1.04 IfcCoveringType.CEILING (ripplagi) (BIM ÜBN + Archicad Classification)
Pset_CoveringCommon - Reference: L-05-2; TotalThickness: 102 mm
AR_Viimistlus - 001_Nimetus: Silekipslagi, roheline; 205_Tähis: L-05-2; 215_Tuletundlikkus: C-s2,d1; 220_Viimistlus: roheline; 230_Niiskuskindel: no; 235_Karkass: CD-kandekarkass 27mm; 900_Tootja: Knauf; 905_Mudel: -; 910_Tooteinfo: ootel; 915_Kasutus-ja-hooldusjuhend: ootel; 210_Paksus: 102 mm
AR_ÜLD - 001_Nimetus: Silekipslagi, roheline; 009_Märkus: OMA märkus
AR_ABI - 200_Materjal (MUDELIS): 70 Kiht: Õhkvahe karkass; 50 Soojustus: kivivill; 60 Plaat: Kipsplaat
AC_Pset_RenovationAndPhasing - Renovation Status: New
Name | In | 225_Pindala (m2)
2 x L-05-2 | Esimene korrus | 1.82091
3 x L-05-2 | Teine korrus | 1.8225
L-05-2 | Teine korrus | 1.82481
2 x L-05-2 | Teine korrus | 1.82102
2 x L-05-2 | Teine korrus | 2.0544

# IfcCovering: L-05-4 kips (must) 102, L-05-4
In: Esimene korrus
Type - PredefinedType: CEILING
Classification: 1.04 IfcCoveringType.CEILING (ripplagi) (BIM ÜBN + Archicad Classification)
AR_Viimistlus - 001_Nimetus: Silekipslagi, must; 205_Tähis: L-05-4; 215_Tuletundlikkus: C-s2,d1; 220_Viimistlus: must; 230_Niiskuskindel: no; 235_Karkass: CD-kandekarkass 27mm; 900_Tootja: Knauf; 905_Mudel: -; 910_Tooteinfo: ootel; 915_Kasutus-ja-hooldusjuhend: ootel; 225_Pindala: 4.72 m2; 210_Paksus: 102 mm
Pset_CoveringCommon - Reference: L-05-4; TotalThickness: 102 mm
AC_Pset_RenovationAndPhasing - Renovation Status: New
AR_ABI - 200_Materjal (MUDELIS): 50 Soojustus: kivivill; 70 Kiht: Õhkvahe karkass; 60 Plaat: Kipsplaat
AR_ÜLD - 001_Nimetus: Silekipslagi, must; 009_Märkus: OMA märkus

# IfcCovering: L-06 (dold) 41 (4)
In: Teine korrus
Type - PredefinedType: CEILING
Classification: 1.04 IfcCoveringType.CEILING (ripplagi) (BIM ÜBN + Archicad Classification)
AR_Viimistlus - 001_Nimetus: Ristkihtpuitpaneel 19 mm; 205_Tähis: L-06; 215_Tuletundlikkus: C-s2,d1; 220_Viimistlus: 1 kiht valge tooniv õlivaha Osmo 3111; 230_Niiskuskindel: no; 235_Karkass: Puitroov 22x100mm; 900_Tootja: Dold Puidutööstus; 905_Mudel: -; 910_Tooteinfo: ootel; 915_Kasutus-ja-hooldusjuhend: ootel; 210_Paksus: 41 mm
Pset_CoveringCommon - Reference: L-06; TotalThickness: 41 mm
AR_ÜLD - 001_Nimetus: Ristkihtpuitpaneel 19 mm; 009_Märkus: OMA märkus
AC_Pset_RenovationAndPhasing - Renovation Status: New
AR_ABI - 200_Materjal (MUDELIS): 70 Kiht: Õhkvahe karkass; 80 Siseviimistlus dold
Name | 225_Pindala (m2)
L-06 | 7.20104
L-06 | 3.6428
L-06 | 13.5833
L-06 | 2.26085

# IfcCovering: L-07 leil 97 (2)
In: Esimene korrus
Type - PredefinedType: CEILING
Classification: 1.04 IfcCoveringType.CEILING (ripplagi) (BIM ÜBN + Archicad Classification)
Pset_CoveringCommon - Reference: L-07; TotalThickness: 97 mm
AR_Viimistlus - 001_Nimetus: Sauna laudislagi 15 mm; 205_Tähis: L-07; 215_Tuletundlikkus: D-s2, d2; 220_Viimistlus: Värvitu vaha; 230_Niiskuskindel: yes; 235_Karkass: Puitroov 28x50mm; 900_Tootja: Thermory; 905_Mudel: -; 910_Tooteinfo: ootel; 915_Kasutus-ja-hooldusjuhend: ootel; 210_Paksus: 97 mm
AR_ÜLD - 001_Nimetus: Sauna laudislagi 15 mm; 009_Märkus: OMA märkus
AC_Pset_RenovationAndPhasing - Renovation Status: New
AR_ABI - 200_Materjal (MUDELIS): 70 Kiht: Õhkvahe karkass; 50 Soojustus: kivivill; 70 Kiht: Õhkvahe karkass; 92 Viim: Puit voodrilaud saun
Name | 225_Pindala (m2)
L-07 | 4.28483
L-07 | 5.7723

# IfcCovering: P-00b 20 (3)
In: Esimene korrus
Type - PredefinedType: FLOORING
Classification: 1.06 IfcCoveringType.FLOORING (põrandakatted) (BIM ÜBN + Archicad Classification); Material: 85 Viimistlus: jalapuhastusrest
AR_Viimistlus - 215_Tuletundlikkus: -; 230_Niiskuskindel: no; 910_Tooteinfo: ootel; 915_Kasutus-ja-hooldusjuhend: ootel; 245_Aluspind: ootel; 210_Paksus: 20 mm
Pset_CoveringCommon - TotalThickness: 20 mm
AR_ÜLD - 009_Märkus: OMA märkus
AR_ABI - 200_Materjal (MUDELIS): 85 Viimistlus: jalapuhastusrest
AC_Pset_RenovationAndPhasing - Renovation Status: New
Name | AR_Viimistlus, 001_Nimetus = AR_ÜLD, 001_Nimetus | 205_Tähis = Reference | 900_Tootja | 905_Mudel | 225_Pindala (m2)
P-06 | Gapa Topwell 22 mm Standard, alumiinium raamis, kumm, peg (must) + tekstiilriba 1 black vaheldumisi. | P-06 | Gapa | Topwell 22 | 5.99422
P-06 | Gapa Topwell 22 mm Standard, alumiinium raamis, kumm, peg (must) + tekstiilriba 1 black vaheldumisi. | P-06 | Gapa | Topwell 22 | 2.40046
P-07 | Kookose porirest | P-07 | Hamat | Ruco 007 | 22.4411 | AR_Viimistlus - 220_Viimistlus: Toon: Antrasiit

# IfcCovering: P-09 5, P-09
In: Teine korrus
Type - PredefinedType: FLOORING
Classification: 1.06 IfcCoveringType.FLOORING (põrandakatted) (BIM ÜBN + Archicad Classification); Material: 80 Siseviim: epo
AR_Viimistlus - 001_Nimetus: Polüretaan põrandakate, paksus 2-3 mm, toon hele-hall RAL 7038.; 205_Tähis: P-09; 215_Tuletundlikkus: -; 220_Viimistlus: Bona Traffic HD 2-kopm.lakiga (2-3 kihti) matt; 230_Niiskuskindel: no; 900_Tootja: Sika; 905_Mudel: Sikafloor PS-22; 910_Tooteinfo: ootel; 915_Kasutus-ja-hooldusjuhend: ootel; 245_Aluspind: ootel; 225_Pindala: 4.9626 m2; 210_Paksus: 5 mm
AR_ÜLD - 001_Nimetus: Polüretaan põrandakate, paksus 2-3 mm, toon hele-hall RAL 7038.; 009_Märkus: OMA märkus
AC_Pset_RenovationAndPhasing - Renovation Status: New
Pset_CoveringCommon - Reference: P-09; TotalThickness: 5 mm
AR_ABI - 200_Materjal (MUDELIS): 80 Siseviim: epo

# IfcCovering: Parapeti plekk 01 416 x 155 (5)
In: Katus
Classification: 1.07 IfcCoveringType (pinnadetailid) (BIM ÜBN + Archicad Classification)
AR_ÜLD - 001_Nimetus: Parapeti plekk; 009_Märkus: vt. AR-7 sõlmlhaendusi
AC_Pset_RenovationAndPhasing - Renovation Status: New
AR_Viimistlus - 001_Nimetus: Parapeti plekk
AR_ABI - 200_Materjal (MUDELIS): 72 Kiht: veeplekk; 64 Plaat: vineer

# IfcCovering: Parapeti plekk 01a 655 x 179
In: Katus
Classification: 1.07 IfcCoveringType (pinnadetailid) (BIM ÜBN + Archicad Classification)
AR_ÜLD - 001_Nimetus: Parapeti plekk; 009_Märkus: vt. AR-7 sõlmlhaendusi
AR_Viimistlus - 001_Nimetus: Parapeti plekk
AR_ABI - 200_Materjal (MUDELIS): 72 Kiht: veeplekk; 64 Plaat: vineer
AC_Pset_RenovationAndPhasing - Renovation Status: New

# IfcCovering: Puitribi 140, S-02
In: Esimene korrus
Type - PredefinedType: CLADDING
Classification: 1.05 IfcCoveringType.CLADDING (seina viimistlus) (BIM ÜBN + Archicad Classification)
Pset_CoveringCommon - Reference: S-02
AR_Viimistlus - 001_Nimetus: Puitribi paneel, musta kangaga; 205_Tähis: S-02; 215_Tuletundlikkus: -; 220_Viimistlus: ootel; 230_Niiskuskindel: no; 900_Tootja: IWS; 905_Mudel: ootel; 910_Tooteinfo: ootel; 915_Kasutus-ja-hooldusjuhend: ootel; 240_Märghõõrdekindlus: ootel; 245_Aluspind: ootel; 210_Paksus: 41 mm
AR_ABI - 200_Materjal (MUDELIS): 71 Kiht: MDF; 80 Siseviimistlus dold
AC_Pset_RenovationAndPhasing - Renovation Status: New
AR_ÜLD - 001_Nimetus: Puitribi paneel, musta kangaga; 009_Märkus: OMA märkus

# IfcCovering: Returned End 26, PINNADETAIL
In: Teine korrus
Classification: 1.07 IfcCoveringType (pinnadetailid) (BIM ÜBN + Archicad Classification)
AR_ÜLD - 009_Märkus: OMA märkus
AC_Pset_RenovationAndPhasing - Renovation Status: New
AR_ABI - 200_Materjal (MUDELIS): 60 Plaat: Kipsplaat; 60 Plaat: Kipsplaat tulekindel

# IfcCovering: SL-01 50 (2)
In: Esimene korrus
Type - PredefinedType: CEILING
Classification: 1.04 IfcCoveringType.CEILING (ripplagi) (BIM ÜBN + Archicad Classification)
Pset_CoveringCommon - Reference: SL-01; TotalThickness: 50 mm
AR_ABI - 200_Materjal (MUDELIS): 50 Soojustus: PIR saun; 60 Plaat: Kipsplaat
AC_Pset_RenovationAndPhasing - Renovation Status: New
AR_Viimistlus - 001_Nimetus: Akustline villaplaat 40 mm, must.; 205_Tähis: SL-01; 215_Tuletundlikkus: A2-s1,d0; 220_Viimistlus: Must; 230_Niiskuskindel: no; 235_Karkass: -; 900_Tootja: Ecophon; 905_Mudel: Industry; 910_Tooteinfo: ootel; 915_Kasutus-ja-hooldusjuhend: ootel; 210_Paksus: 50 mm
AR_ÜLD - 001_Nimetus: Akustline villaplaat 40 mm, must.; 009_Märkus: OMA märkus
Name | 225_Pindala (m2)
SL-01 | 23.4252
SL-01 | 127.015

# IfcCovering: SL-02 100 (2)
In: Esimene korrus
Type - PredefinedType: CEILING
Classification: 1.04 IfcCoveringType.CEILING (ripplagi) (BIM ÜBN + Archicad Classification)
Pset_CoveringCommon - Reference: SL-20; TotalThickness: 100 mm
AR_Viimistlus - 001_Nimetus: SW paneel; 205_Tähis: SL-20; 230_Niiskuskindel: no; 910_Tooteinfo: ootel; 915_Kasutus-ja-hooldusjuhend: ootel; 210_Paksus: 100 mm
AR_ABI - 200_Materjal (MUDELIS): 72 Kiht: SW plekk; 50 Soojustus: PIR SW; 72 Kiht: SW plekk
AC_Pset_RenovationAndPhasing - Renovation Status: New
AR_ÜLD - 001_Nimetus: SW paneel; 009_Märkus: OMA märkus
Name | 215_Tuletundlikkus | 220_Viimistlus | 235_Karkass | 900_Tootja | 905_Mudel | 225_Pindala (m2)
SL-20 | A2-s1,d0 | Must | - | Ecophon | Industry | 23.1822
SL-20 | B-s1,d0 | Natural N | CD-kandekarkass 27mm | Cewood | Cewood panel | 13.122

# IfcCovering: SS-10a 73 (8)
In: Esimene korrus
Type - PredefinedType: CLADDING
Classification: 1.05 IfcCoveringType.CLADDING (seina viimistlus) (BIM ÜBN + Archicad Classification)
Pset_CoveringCommon - Reference: S-07; TotalThickness: 73 mm
AR_Viimistlus - 001_Nimetus: Leiliruum puit, haab, laudise mõõt 15x90mm,; 205_Tähis: S-07; 215_Tuletundlikkus: D-s2, d2; 220_Viimistlus: Tikkurila Supi värvitu kaitsevahendiga; 230_Niiskuskindel: no; 900_Tootja: Thermory; 905_Mudel: Haab STS4 15x90; 910_Tooteinfo: ootel; 915_Kasutus-ja-hooldusjuhend: ootel; 240_Märghõõrdekindlus: ootel; 245_Aluspind: ootel; 210_Paksus: 73 mm
AR_ÜLD - 001_Nimetus: Leiliruum puit, haab, laudise mõõt 15x90mm,; 009_Märkus: vt. SS-10/SS-10a konstruktsioonitüüpi
AR_ABI - 200_Materjal (MUDELIS): 92 Viim: Puit voodrilaud saun; 70 Kiht: Õhkvahe karkass; 50 Soojustus: PIR saun
AC_Pset_RenovationAndPhasing - Renovation Status: New
Name | 225_Pindala (m2)
2 x S-07 | 5.37244
2 x S-07 | 6.292
2 x S-07 | 5.37268
2 x S-07 | 4.6706

# IfcCovering: Seinapaneel 1030, S-02
In: Esimene korrus
Type - PredefinedType: CLADDING
Classification: 1.05 IfcCoveringType.CLADDING (seina viimistlus) (BIM ÜBN + Archicad Classification)
Pset_CoveringCommon - Reference: S-02
AR_Viimistlus - 001_Nimetus: Puitribi paneel, musta kangaga; 205_Tähis: S-02; 215_Tuletundlikkus: -; 220_Viimistlus: ootel; 230_Niiskuskindel: no; 900_Tootja: IWS; 905_Mudel: ootel; 910_Tooteinfo: ootel; 915_Kasutus-ja-hooldusjuhend: ootel; 240_Märghõõrdekindlus: ootel; 245_Aluspind: ootel; 210_Paksus: 41 mm
AR_ÜLD - 001_Nimetus: Puitribi paneel, musta kangaga; 009_Märkus: OMA märkus
AC_Pset_RenovationAndPhasing - Renovation Status: New
AR_ABI - 200_Materjal (MUDELIS): 71 Kiht: MDF; 80 Siseviimistlus dold

# IfcCovering: Seinapaneel 108x12 (4)
In: Esimene korrus
Type - PredefinedType: CLADDING
Classification: 1.05 IfcCoveringType.CLADDING (seina viimistlus) (BIM ÜBN + Archicad Classification)
Pset_CoveringCommon - Reference: S-02
AR_ÜLD - 001_Nimetus: Puitribi paneel, musta kangaga; 009_Märkus: OMA märkus
AR_Viimistlus - 001_Nimetus: Puitribi paneel, musta kangaga; 205_Tähis: S-02; 215_Tuletundlikkus: -; 220_Viimistlus: ootel; 230_Niiskuskindel: no; 900_Tootja: IWS; 905_Mudel: ootel; 910_Tooteinfo: ootel; 915_Kasutus-ja-hooldusjuhend: ootel; 240_Märghõõrdekindlus: ootel; 245_Aluspind: ootel; 210_Paksus: 41 mm
AR_ABI - 200_Materjal (MUDELIS): 71 Kiht: MDF; 80 Siseviimistlus dold
AC_Pset_RenovationAndPhasing - Renovation Status: New

# IfcCovering: Seinapaneel 1240b, S-02
In: Esimene korrus
Type - PredefinedType: CLADDING
Classification: 1.05 IfcCoveringType.CLADDING (seina viimistlus) (BIM ÜBN + Archicad Classification)
Pset_CoveringCommon - Reference: S-02
AR_Viimistlus - 001_Nimetus: Puitribi paneel, musta kangaga; 205_Tähis: S-02; 215_Tuletundlikkus: -; 220_Viimistlus: ootel; 230_Niiskuskindel: no; 900_Tootja: IWS; 905_Mudel: ootel; 910_Tooteinfo: ootel; 915_Kasutus-ja-hooldusjuhend: ootel; 240_Märghõõrdekindlus: ootel; 245_Aluspind: ootel; 210_Paksus: 41 mm
AR_ÜLD - 001_Nimetus: Puitribi paneel, musta kangaga; 009_Märkus: OMA märkus
AR_ABI - 200_Materjal (MUDELIS): 71 Kiht: MDF; 80 Siseviimistlus dold
AC_Pset_RenovationAndPhasing - Renovation Status: New

# IfcCovering: Seinapaneel 138x12 (9)
In: Esimene korrus
Type - PredefinedType: CLADDING
Classification: 1.05 IfcCoveringType.CLADDING (seina viimistlus) (BIM ÜBN + Archicad Classification)
AR_Viimistlus - 001_Nimetus: Puitribi paneel, musta kangaga; 205_Tähis: S-02; 215_Tuletundlikkus: -; 220_Viimistlus: ootel; 230_Niiskuskindel: no; 900_Tootja: IWS; 905_Mudel: ootel; 910_Tooteinfo: ootel; 915_Kasutus-ja-hooldusjuhend: ootel; 240_Märghõõrdekindlus: ootel; 245_Aluspind: ootel; 210_Paksus: 41 mm
AC_Pset_RenovationAndPhasing - Renovation Status: New
AR_ABI - 200_Materjal (MUDELIS): 71 Kiht: MDF; 80 Siseviimistlus dold
AR_ÜLD - 001_Nimetus: Puitribi paneel, musta kangaga; 009_Märkus: OMA märkus
Pset_CoveringCommon - Reference: S-02

# IfcCovering: Seinapaneel 13x12 (38)
In: Esimene korrus
Type - PredefinedType: CLADDING
Classification: 1.05 IfcCoveringType.CLADDING (seina viimistlus) (BIM ÜBN + Archicad Classification)
Pset_CoveringCommon - Reference: S-02
AR_Viimistlus - 001_Nimetus: Puitribi paneel, musta kangaga; 205_Tähis: S-02; 215_Tuletundlikkus: -; 220_Viimistlus: ootel; 230_Niiskuskindel: no; 900_Tootja: IWS; 905_Mudel: ootel; 910_Tooteinfo: ootel; 915_Kasutus-ja-hooldusjuhend: ootel; 240_Märghõõrdekindlus: ootel; 245_Aluspind: ootel; 210_Paksus: 41 mm
AR_ÜLD - 001_Nimetus: Puitribi paneel, musta kangaga; 009_Märkus: OMA märkus
AR_ABI - 200_Materjal (MUDELIS): 71 Kiht: MDF; 80 Siseviimistlus dold
AC_Pset_RenovationAndPhasing - Renovation Status: New

# IfcCovering: Seinapaneel 13x12 b (36)
In: Esimene korrus
Type - PredefinedType: CLADDING
Classification: 1.05 IfcCoveringType.CLADDING (seina viimistlus) (BIM ÜBN + Archicad Classification)
Pset_CoveringCommon - Reference: S-02
AR_Viimistlus - 001_Nimetus: Puitribi paneel, musta kangaga; 205_Tähis: S-02; 215_Tuletundlikkus: -; 220_Viimistlus: ootel; 230_Niiskuskindel: no; 900_Tootja: IWS; 905_Mudel: ootel; 910_Tooteinfo: ootel; 915_Kasutus-ja-hooldusjuhend: ootel; 240_Märghõõrdekindlus: ootel; 245_Aluspind: ootel; 210_Paksus: 41 mm
AR_ÜLD - 001_Nimetus: Puitribi paneel, musta kangaga; 009_Märkus: OMA märkus
AR_ABI - 200_Materjal (MUDELIS): 71 Kiht: MDF; 80 Siseviimistlus dold
AC_Pset_RenovationAndPhasing - Renovation Status: New

# IfcCovering: Seinapaneel 500 (3)
In: Esimene korrus
Type - PredefinedType: CLADDING
Classification: 1.05 IfcCoveringType.CLADDING (seina viimistlus) (BIM ÜBN + Archicad Classification)
Pset_CoveringCommon - Reference: S-02
AR_Viimistlus - 001_Nimetus: Puitribi paneel, musta kangaga; 205_Tähis: S-02; 215_Tuletundlikkus: -; 220_Viimistlus: ootel; 230_Niiskuskindel: no; 900_Tootja: IWS; 905_Mudel: ootel; 910_Tooteinfo: ootel; 915_Kasutus-ja-hooldusjuhend: ootel; 240_Märghõõrdekindlus: ootel; 245_Aluspind: ootel; 210_Paksus: 41 mm
AR_ÜLD - 001_Nimetus: Puitribi paneel, musta kangaga; 009_Märkus: OMA märkus
AC_Pset_RenovationAndPhasing - Renovation Status: New
AR_ABI - 200_Materjal (MUDELIS): 71 Kiht: MDF; 80 Siseviimistlus dold

# IfcCovering: Seinapaneel 500_ (2)
In: Esimene korrus
Type - PredefinedType: CLADDING
Classification: 1.05 IfcCoveringType.CLADDING (seina viimistlus) (BIM ÜBN + Archicad Classification)
Pset_CoveringCommon - Reference: S-02
AR_ÜLD - 001_Nimetus: Puitribi paneel, musta kangaga; 009_Märkus: OMA märkus
AR_ABI - 200_Materjal (MUDELIS): 71 Kiht: MDF; 80 Siseviimistlus dold
AC_Pset_RenovationAndPhasing - Renovation Status: New
AR_Viimistlus - 001_Nimetus: Puitribi paneel, musta kangaga; 205_Tähis: S-02; 215_Tuletundlikkus: -; 220_Viimistlus: ootel; 230_Niiskuskindel: no; 900_Tootja: IWS; 905_Mudel: ootel; 910_Tooteinfo: ootel; 915_Kasutus-ja-hooldusjuhend: ootel; 240_Märghõõrdekindlus: ootel; 245_Aluspind: ootel; 210_Paksus: 41 mm

# IfcCovering: Seinapaneel 58x12 (3)
In: Esimene korrus
Type - PredefinedType: CLADDING
Classification: 1.05 IfcCoveringType.CLADDING (seina viimistlus) (BIM ÜBN + Archicad Classification)
AC_Pset_RenovationAndPhasing - Renovation Status: New
AR_ÜLD - 001_Nimetus: Puitribi paneel, musta kangaga; 009_Märkus: OMA märkus
AR_Viimistlus - 001_Nimetus: Puitribi paneel, musta kangaga; 205_Tähis: S-02; 215_Tuletundlikkus: -; 220_Viimistlus: ootel; 230_Niiskuskindel: no; 900_Tootja: IWS; 905_Mudel: ootel; 910_Tooteinfo: ootel; 915_Kasutus-ja-hooldusjuhend: ootel; 240_Märghõõrdekindlus: ootel; 245_Aluspind: ootel; 210_Paksus: 41 mm
Pset_CoveringCommon - Reference: S-02
AR_ABI - 200_Materjal (MUDELIS): 71 Kiht: MDF; 80 Siseviimistlus dold

# IfcCovering: Seinapaneel 810, S-02
In: Esimene korrus
Type - PredefinedType: CLADDING
Classification: 1.05 IfcCoveringType.CLADDING (seina viimistlus) (BIM ÜBN + Archicad Classification)
Pset_CoveringCommon - Reference: S-02
AR_Viimistlus - 001_Nimetus: Puitribi paneel, musta kangaga; 205_Tähis: S-02; 215_Tuletundlikkus: -; 220_Viimistlus: ootel; 230_Niiskuskindel: no; 900_Tootja: IWS; 905_Mudel: ootel; 910_Tooteinfo: ootel; 915_Kasutus-ja-hooldusjuhend: ootel; 240_Märghõõrdekindlus: ootel; 245_Aluspind: ootel; 210_Paksus: 41 mm
AR_ÜLD - 001_Nimetus: Puitribi paneel, musta kangaga; 009_Märkus: OMA märkus
AC_Pset_RenovationAndPhasing - Renovation Status: New
AR_ABI - 200_Materjal (MUDELIS): 71 Kiht: MDF; 80 Siseviimistlus dold

# IfcCovering: Seinapaneel 920 (2)
In: Esimene korrus
Type - PredefinedType: CLADDING
Classification: 1.05 IfcCoveringType.CLADDING (seina viimistlus) (BIM ÜBN + Archicad Classification)
Pset_CoveringCommon - Reference: S-02
AR_Viimistlus - 001_Nimetus: Puitribi paneel, musta kangaga; 205_Tähis: S-02; 215_Tuletundlikkus: -; 220_Viimistlus: ootel; 230_Niiskuskindel: no; 900_Tootja: IWS; 905_Mudel: ootel; 910_Tooteinfo: ootel; 915_Kasutus-ja-hooldusjuhend: ootel; 240_Märghõõrdekindlus: ootel; 245_Aluspind: ootel; 210_Paksus: 41 mm
AR_ABI - 200_Materjal (MUDELIS): 71 Kiht: MDF; 80 Siseviimistlus dold
AC_Pset_RenovationAndPhasing - Renovation Status: New
AR_ÜLD - 001_Nimetus: Puitribi paneel, musta kangaga; 009_Märkus: OMA märkus

# IfcCovering: Veeplekk-terrasi ülemine serv 2 364 x 45 (2)
In: Teine korrus
Classification: 1.07 IfcCoveringType (pinnadetailid) (BIM ÜBN + Archicad Classification); Material: 40 Kiht: Teras
AR_ÜLD - 001_Nimetus: Veeplekk; 009_Märkus: vt. AR-7 sõlmlahendusi
AR_Viimistlus - 001_Nimetus: Veeplekk
AC_Pset_RenovationAndPhasing - Renovation Status: New
AR_ABI - 200_Materjal (MUDELIS): 40 Kiht: Teras

# IfcCovering: Veeplekk-terrasi ülemine serv 211 x 118
In: Teine korrus
Classification: 1.07 IfcCoveringType (pinnadetailid) (BIM ÜBN + Archicad Classification); Material: 40 Kiht: Teras
AR_Viimistlus - 001_Nimetus: Veeplekk
AR_ÜLD - 001_Nimetus: Veeplekk; 009_Märkus: vt. AR-7 sõlmlahendusi
AR_ABI - 200_Materjal (MUDELIS): 40 Kiht: Teras
AC_Pset_RenovationAndPhasing - Renovation Status: New

# IfcCovering: Veeplekk-terrasi ülemine serv 3 444 x 45
In: Teine korrus
Classification: 1.07 IfcCoveringType (pinnadetailid) (BIM ÜBN + Archicad Classification); Material: 40 Kiht: Teras
AR_Viimistlus - 001_Nimetus: Veeplekk
AR_ÜLD - 001_Nimetus: Veeplekk; 009_Märkus: vt. AR-7 sõlmlahendusi
AC_Pset_RenovationAndPhasing - Renovation Status: New
AR_ABI - 200_Materjal (MUDELIS): 40 Kiht: Teras

# IfcDiscreteAccessory: Downspout 26 (2)
In: Esimene korrus
Classification: 1.09 IfcDiscreteAccessoryType (tarvik) (BIM ÜBN + Archicad Classification)
AR_ÜLD - 001_Nimetus: Sadeveetoru
AC_Pset_RenovationAndPhasing - Renovation Status: New

# IfcDiscreteAccessory: Downspout Complex 26 (12)
In: Esimene korrus
Classification: 1.09 IfcDiscreteAccessoryType (tarvik) (BIM ÜBN + Archicad Classification)
AR_ÜLD - 001_Nimetus: Sadeveetoru; 009_Märkus: vt. AR-osa sõlmlahendusi
AC_Pset_RenovationAndPhasing - Renovation Status: New

# IfcDiscreteAccessory: Downspout Elbow 26 (2)
In: Esimene korrus
Classification: 1.09 IfcDiscreteAccessoryType (tarvik) (BIM ÜBN + Archicad Classification)
AR_ÜLD - 001_Nimetus: Sadeveetoru
AC_Pset_RenovationAndPhasing - Renovation Status: New

# IfcDiscreteAccessory: FSV-01 (23)
In: Esimene korrus
Classification: 1.09 IfcDiscreteAccessoryType (tarvik) (BIM ÜBN + Archicad Classification); Material: 30 Konst: puit 01, 30 Konst: Teras - Konstruktsioon, 40 Kiht: Teras
AC_Pset_RenovationAndPhasing - Renovation Status: New
AR_ÜLD - 001_Nimetus: Varjestus
Name | 009_Märkus
14 x FSV-01a | 1. korruse ida fassaad: Terasraam (toon: RAL7016) puitsõrestik täitega (vt. AR-8-60). vt. täpsemalt EK-osa ja AR-7 sõlmlahendusi
9 x FSV-01b | 1. korruse lääne fassaad: Terasraam (toon: RAL7016) puitsõrestik täitega (vt. AR-8-60). vt. täpsemalt EK-osa ja AR-7 sõlmlahendusi

# IfcDiscreteAccessory: FSV-02 (4)
In: Esimene korrus
Classification: 1.09 IfcDiscreteAccessoryType (tarvik) (BIM ÜBN + Archicad Classification); Material: 30 Konst: puit 01, 30 Konst: Teras - Konstruktsioon, 40 Kiht: Teras
AR_ÜLD - 001_Nimetus: Varjestus
AC_Pset_RenovationAndPhasing - Renovation Status: New
Name | 009_Märkus
2 x FSV-02a | 1. korruse ida fassaad: Terasraam (toon: RAL7016) puitsõrestik täitega (vt. AR-8-60). vt. täpsemalt EK-osa ja AR-7 sõlmlahendusi
2 x FSV-02b | 1. korruse lääne fassaad: Terasraam (toon: RAL7016) puitsõrestik täitega (vt. AR-8-60). vt. täpsemalt EK-osa ja AR-7 sõlmlahendusi

# IfcDiscreteAccessory: FSV-03 (38)
In: Teine korrus
Classification: 1.09 IfcDiscreteAccessoryType (tarvik) (BIM ÜBN + Archicad Classification); Material: 30 Konst: puit 01, 30 Konst: Teras - Konstruktsioon, 40 Kiht: Teras
AR_ÜLD - 001_Nimetus: Varjestus
AC_Pset_RenovationAndPhasing - Renovation Status: New
Name | 009_Märkus
22 x FSV-03a | 2. korruse ida fassaad: Terasraam (toon: RAL7016) puitsõrestik täitega (vt. AR-8-60). vt. täpsemalt EK-osa ja AR-7 sõlmlahendusi
16 x FSV-03b | 2. korruse lääne fassaad: Terasraam (toon: RAL7016) puitsõrestik täitega (vt. AR-8-60). vt. täpsemalt EK-osa ja AR-7 sõlmlahendusi

# IfcDiscreteAccessory: METK_silt 1, SILT
In: Teine korrus
Classification: 1.09 IfcDiscreteAccessoryType (tarvik) (BIM ÜBN + Archicad Classification); Material: 41 Konst: teras
AR_ÜLD - 001_Nimetus: SILT FASSAADIL; 009_Märkus: vt. AR-6 vaatejoonised
AC_Pset_RenovationAndPhasing - Renovation Status: New

# IfcDiscreteAccessory: TRVP-01 (16)
In: Esimene korrus
Classification: 1.09 IfcDiscreteAccessoryType (tarvik) (BIM ÜBN + Archicad Classification); Material: 01 ÜLD: projekteeritav
AR_ÜLD - 001_Nimetus: Turvapost; 009_Märkus: ⌀90mm h=600mm turvapost taldmikuga. Kinnitatud 4 betooniankruga põrandaplaati. Turvaposti seinaga paralleelse kesktelje kaugus tõstuksega seinast 250mm/ seinaga risti kesktelg samal joonel ava palega. Turvaposti toon: antratsiithall RAL7016 ühe 30mm kollase ribaga üleval servas. vt. AR-5 plaanilahendusi ja AR-7-05 sõlmelahendusi.
AC_Pset_RenovationAndPhasing - Renovation Status: New

# IfcDiscreteAccessory: TRVP-02 (10)
In: Esimene korrus
Classification: 1.09 IfcDiscreteAccessoryType (tarvik) (BIM ÜBN + Archicad Classification); Material: 01 ÜLD: projekteeritav
AR_ÜLD - 001_Nimetus: Turvapost; 009_Märkus: ⌀90mm h=600mm turvapost, antud nähtav kõrgus. Valatud betoonplaati, täpsustada valuosa nõutav sügavus tootjaga. Turvaposti seinaga paralleelse kesktelje kaugus välisseina sisepinnast 770mm/ seinaga risti kesktelg 90mm betoonplaadist. Turvaposti toon: antratsiithall RAL7016. vt. AR-5 plaanilahendusi ja AR-7-05 sõlmelahendusi.
AC_Pset_RenovationAndPhasing - Renovation Status: New

# IfcDiscreteAccessory: Text 3D 26 (6)
In: Esimene korrus
Classification: 1.09 IfcDiscreteAccessoryType (tarvik) (BIM ÜBN + Archicad Classification)
AR_ÜLD - 009_Märkus: vt. AR-6 vaatejoonised
AC_Pset_RenovationAndPhasing - Renovation Status: New
Name | 001_Nimetus
2 x SILT | MAJANUMBER
4 x SILT | SILT FASSAADIL

# IfcDiscreteAccessory: Wall Mounted Ladder 26, RDL-01
In: Teine korrus
Classification: 1.09 IfcDiscreteAccessoryType (tarvik) (BIM ÜBN + Archicad Classification)
AR_ÜLD - 001_Nimetus: Siseredel; 009_Märkus: vt. AR-8 spetsifikatsiooni
AC_Pset_RenovationAndPhasing - Renovation Status: New

# IfcDoor: Door 26, SUT-14
In: Teine korrus
Type - OperationType: SINGLE_SWING_LEFT; ParameterTakesPrecedence: no; Sizeable: no
Type - Door Lining Properties - LiningDepth: 115 mm; LiningThickness: 40 mm; LiningOffset: -395 mm
Type - Door Panel Properties - Panel 1 - PanelDepth: 40 mm; PanelOperation: SWINGING; PanelWidth: 1; PanelPosition: MIDDLE
OverallHeight: 2100 mm; OverallWidth: 1000 mm; Classification: 1.10 IfcDoorStyle (uks) (BIM ÜBN + Archicad Classification)
AR_Uks - 001_Nimetus: Siseuks; 300_Tähis: SUT-14; 310_Materjal: MUDELIS: väljast-Avatäide: raam värv antrasiit RAL7016; Avatäide: raam värv antrasiit RAL7016; seest-Avatäide: raam värv antrasiit RAL7016; Avatäide: raam värv antrasiit RAL7016; MÄRKUS: metall; 315_Avanemine: -Parem ; ARCHICAD tüüp: Side Hung; 320_Klaas: ootel; 325_Helipidavus: R’w ≥ 40 dB; 330_Tulepüsivus: EI30 Sa; 335_Välispiire: no; 340_Soojusläbivus: 0; 350_Klaaspakett: -; 355_Pindala: 2.1 m2; 360_Ratastooliga: no; 365_Isesulguv: no; 370_Evakuatsiooniväljapääs: no; 375_Viimistlus-seest: MUDELIS: Avatäide: raam värv antrasiit RAL7016; Avatäide: raam värv antrasiit RAL7016; MÄRKUS: Matt must RAL9005; 376_Viimistlus-väljast: MUDELIS: Avatäide: raam värv antrasiit RAL7016; Avatäide: raam värv antrasiit RAL7016; MÄRKUS: Matt must RAL9005; 380_Lukustus: Sarjastatud; 900_Tootja: Saku metall; 905_Mudel: MFD131; 910_Tooteinfo: ootel; 915_Kasutus-ja-hooldusjuhend: ootel; 306_Ava-laius: 1000 mm; 307_Ava-kõrgus: 2100 mm; 377_Leng: Tootja standardtoode; 378_Lävepakk: Uksetootja madal lävepakk, maksimaalne h=20 mm, viimistletud harjatud naturaalne roostevaba teras, kooskõlastada projekteerijaga.; 379_Käepide: Abloy Forum 4, exit matt roostevaba; 381_Lukuraam: Standardtoode (EVS-EN 12209), luku viimistlus matt must, ruumi seest avanemine lingist; 382_Südamik: täpsustada TP-staadiumis; 383_Vasturaud: Tootja standard, matt roostevaba.; 384_Sulgur: -; 345_Päikesekiirgus-tegur: 0; 336_Sissepääs-hoonesse: no
Pset_DoorCommon - Reference: SUT-14; ThermalTransmittance: 0; IsExternal: no
AR_ÜLD - 009_Märkus: OMA märkus
AC_Pset_RenovationAndPhasing - Renovation Status: New

# IfcDoor: Door 26, VU-04b
In: Teine korrus
Type - OperationType: SINGLE_SWING_LEFT; ParameterTakesPrecedence: no; Sizeable: no
Type - Door Lining Properties - LiningDepth: 180 mm; LiningThickness: 45 mm; LiningOffset: 220 mm
Type - Door Panel Properties - Panel 1 - PanelDepth: 80 mm; PanelOperation: SWINGING; PanelWidth: 1; PanelPosition: MIDDLE
OverallHeight: 2479.91 mm; OverallWidth: 1100 mm; Classification: 1.10 IfcDoorStyle (uks) (BIM ÜBN + Archicad Classification)
AC_Pset_RenovationAndPhasing - Renovation Status: New
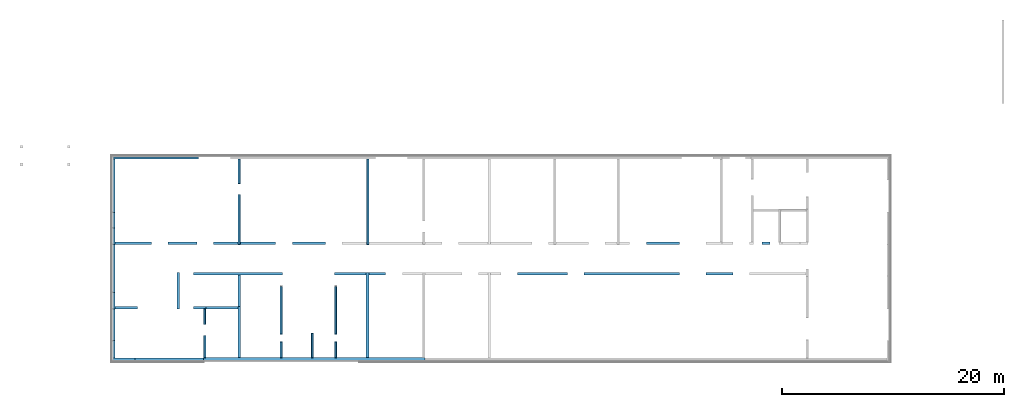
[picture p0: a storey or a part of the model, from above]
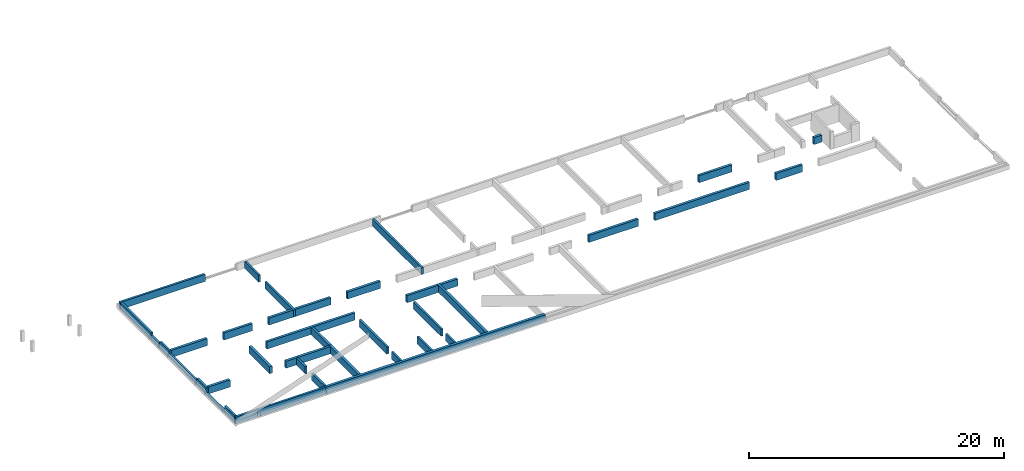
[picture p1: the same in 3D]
Properties of the parts of a building model (IFC2X3), part 4 of 8

# IfcDoor: Door 26, VU-04b
Pset_DoorCommon - Reference: VU-04b; ThermalTransmittance: 0; GlazingAreaFraction: 1.61599; IsExternal: yes
AR_Uks - 001_Nimetus: Alumiiniumraamil välisuks KF süsteemis; 300_Tähis: VU-04b; 310_Materjal: MUDELIS: väljast-Avatäide: raam värv antrasiit RAL7016; Avatäide: raam värv antrasiit RAL7016; seest-Avatäide: raam värv antrasiit RAL7016; Avatäide: raam värv antrasiit RAL7016; MÄRKUS: Alumiinium; 315_Avanemine: Pöördavatav rullhingedel ukselehtParem ; ARCHICAD tüüp: Side Hung; 320_Klaas: Kolmekordne klaaspakett, argoongaasiga, vaheliistud mustad, välimine: päikesekaitseklaas Cool-Lite SKN 183 II, LT=66%, karastatud klaas, klaasitoon: kirgas, keskmine: Planiclear, klaasitoon: kirgas, sisemine: Planitherm XN, lamineeritud floatklaas, klaasitoon: kirgas; 325_Helipidavus: R’tr,s,w = 30 dB; 330_Tulepüsivus: nõudeid ei esitata; 335_Välispiire: yes; 340_Soojusläbivus: 0; 350_Klaaspakett: 3k6SecSKN183II+4+44.1PlthXN-18Ar/18Ar (vaheliistude toon: must), Ug=0,5 W/(m2K); 355_Pindala: 2.7279 m2; 360_Ratastooliga: no; 365_Isesulguv: no; 370_Evakuatsiooniväljapääs: yes; 375_Viimistlus-seest: MUDELIS: Avatäide: raam värv antrasiit RAL7016; Avatäide: raam värv antrasiit RAL7016; MÄRKUS: Matt antrasiit RAL7016; 376_Viimistlus-väljast: MUDELIS: Avatäide: raam värv antrasiit RAL7016; Avatäide: raam värv antrasiit RAL7016; MÄRKUS: Matt antrasiit RAL7016; 380_Lukustus: Kolmepunkti lukustussüsteem, täpsustada TP-staadiumis; 900_Tootja: ootel; 905_Mudel: ootel; 910_Tooteinfo: ootel; 915_Kasutus-ja-hooldusjuhend: ootel; 306_Ava-laius: 1100 mm; 307_Ava-kõrgus: 2479.91 mm; 377_Leng: AD UP 90; 378_Lävepakk: tootja standardtoode; 379_Käepide: tootja standard, viimistlus: roostevaba; 381_Lukuraam: täpsustada TP-staadiumis; 382_Südamik: täpsustada TP-staadiumis; 383_Vasturaud: täpsustada TP-staadiumis; 384_Sulgur: tootja standardtoode; 345_Päikesekiirgus-tegur: 0; 336_Sissepääs-hoonesse: yes

# IfcDoor: Door 26, SUT-03
In: Esimene korrus
Type - OperationType: SINGLE_SWING_LEFT; ParameterTakesPrecedence: no; Sizeable: no
Type - Door Lining Properties - LiningDepth: 40 mm; LiningThickness: 40 mm; LiningOffset: -190 mm
Type - Door Panel Properties - Panel 1 - PanelDepth: 40 mm; PanelOperation: SWINGING; PanelWidth: 1; PanelPosition: MIDDLE
OverallHeight: 2200 mm; OverallWidth: 900 mm; Classification: 1.10 IfcDoorStyle (uks) (BIM ÜBN + Archicad Classification)
Pset_DoorCommon - Reference: SUT-03; ThermalTransmittance: 0; IsExternal: no
AR_Uks - 001_Nimetus: Siseuks EI30; 300_Tähis: SUT-03; 310_Materjal: MUDELIS: väljast-Avatäide: raam värv antrasiit RAL7016; Avatäide: raam värv antrasiit RAL7016; seest-Avatäide: raam värv antrasiit RAL7016; Avatäide: raam värv antrasiit RAL7016; MÄRKUS: MDF+värv; 315_Avanemine: -Parem ; ARCHICAD tüüp: Side Hung; 320_Klaas: ootel; 325_Helipidavus: R’w ≥ 30dB; 330_Tulepüsivus: EI30 Sa; 335_Välispiire: no; 340_Soojusläbivus: 0; 350_Klaaspakett: -; 355_Pindala: 1.98 m2; 360_Ratastooliga: no; 365_Isesulguv: no; 370_Evakuatsiooniväljapääs: no; 375_Viimistlus-seest: MUDELIS: Avatäide: raam värv antrasiit RAL7016; Avatäide: raam värv antrasiit RAL7016; MÄRKUS: Matt must RAL9005; 376_Viimistlus-väljast: MUDELIS: Avatäide: raam värv antrasiit RAL7016; Avatäide: raam värv antrasiit RAL7016; MÄRKUS: Matt must RAL9005; 380_Lukustus: Sarjastatud; 900_Tootja: Structo; 905_Mudel: Mod 92; 910_Tooteinfo: ootel; 915_Kasutus-ja-hooldusjuhend: ootel; 306_Ava-laius: 900 mm; 307_Ava-kõrgus: 2200 mm; 377_Leng: Tootja standardtoode; 378_Lävepakk: Allalaskuv lävepakk, helikindel.; 379_Käepide: Abloy Forum 4, matt roostevaba; 381_Lukuraam: Standardtoode (EVS-EN 12209), luku viimistlus matt must, ruumi seest avanemine lingist; 382_Südamik: täpsustada TP-staadiumis; 383_Vasturaud: Tootja standard, matt roostevaba.; 384_Sulgur: -; 345_Päikesekiirgus-tegur: 0; 336_Sissepääs-hoonesse: no
AR_ÜLD - 009_Märkus: OMA märkus
AC_Pset_RenovationAndPhasing - Renovation Status: New

# IfcDoor: Door 26 (3)
In: Esimene korrus
Type - OperationType: SINGLE_SWING_LEFT; ParameterTakesPrecedence: no; Sizeable: no
Type - Door Lining Properties - LiningThickness: 10 mm
Type - Door Panel Properties - Panel 1 - PanelDepth: 4 mm; PanelOperation: SWINGING; PanelWidth: 1; PanelPosition: MIDDLE
Classification: 1.10 IfcDoorStyle (uks) (BIM ÜBN + Archicad Classification)
AR_Uks - 315_Avanemine: -Parem ; ARCHICAD tüüp: Side Hung; 320_Klaas: ootel; 325_Helipidavus: nõudeid ei esitata; 330_Tulepüsivus: nõudeid ei esitata; 335_Välispiire: no; 340_Soojusläbivus: 0; 350_Klaaspakett: -; 360_Ratastooliga: no; 365_Isesulguv: no; 370_Evakuatsiooniväljapääs: no; 380_Lukustus: -; 900_Tootja: Glass solution; 905_Mudel: Modern black; 910_Tooteinfo: ootel; 915_Kasutus-ja-hooldusjuhend: ootel; 377_Leng: Must puidust leng, mustad hinged.; 378_Lävepakk: Lävepakk puudub; 379_Käepide: Modern black; 381_Lukuraam: -; 382_Südamik: täpsustada TP-staadiumis; 383_Vasturaud: -; 384_Sulgur: -; 345_Päikesekiirgus-tegur: 0; 336_Sissepääs-hoonesse: no
Pset_DoorCommon - ThermalTransmittance: 0; IsExternal: no
AC_Pset_RenovationAndPhasing - Renovation Status: New
AR_ÜLD - 009_Märkus: OMA märkus
Name | OverallHeight (mm) = 307_Ava-kõrgus (mm) | OverallWidth (mm) = 306_Ava-laius (mm) | 001_Nimetus | 300_Tähis = Reference | 310_Materjal | 355_Pindala (m2) | 375_Viimistlus-seest | 376_Viimistlus-väljast | GlazingAreaFraction
2 x KS-03 | 2200 | 800 | Klaasuks duširuumis | KS-03 | MUDELIS: väljast-Avatäide: raam värv antrasiit RAL7016; Klaas - satiin; seest-Klaas - satiin; Klaas - satiin; MÄRKUS: Klaas | 1.76 | MUDELIS: Klaas - satiin; Klaas - satiin; MÄRKUS: Satiin klaas | MUDELIS: Avatäide: raam värv antrasiit RAL7016; Klaas - satiin; MÄRKUS: Satiin klaas | 1.7082
KS-02 | 2100 | 700 | Sauna klaasuks | KS-02 | MUDELIS: väljast-Avatäide: leht värv antrasiit RAL7016; Avatäide: leht värv antrasiit RAL7016; seest-Avatäide: leht värv antrasiit RAL7016; Avatäide: leht värv antrasiit RAL7016; MÄRKUS: Satiin klaas | 1.47 | MUDELIS: Avatäide: leht värv antrasiit RAL7016; Avatäide: leht värv antrasiit RAL7016; MÄRKUS: Satiin klaas | MUDELIS: Avatäide: leht värv antrasiit RAL7016; Avatäide: leht värv antrasiit RAL7016; MÄRKUS: Satiin klaas | 1.4212

# IfcDoor: Door 26 (7)
Type - OperationType: SINGLE_SWING_LEFT; ParameterTakesPrecedence: no; Sizeable: no
Type - Door Lining Properties - LiningThickness: 40 mm
Type - Door Panel Properties - Panel 1 - PanelDepth: 40 mm; PanelOperation: SWINGING; PanelWidth: 1; PanelPosition: MIDDLE
OverallWidth: 1000 mm; Classification: 1.10 IfcDoorStyle (uks) (BIM ÜBN + Archicad Classification)
Pset_DoorCommon - ThermalTransmittance: 0; IsExternal: no
AR_Uks - 320_Klaas: ootel; 335_Välispiire: no; 340_Soojusläbivus: 0; 350_Klaaspakett: -; 365_Isesulguv: no; 370_Evakuatsiooniväljapääs: no; 375_Viimistlus-seest: MUDELIS: Avatäide: raam värv antrasiit RAL7016; Avatäide: raam värv antrasiit RAL7016; MÄRKUS: Matt must RAL9005; 376_Viimistlus-väljast: MUDELIS: Avatäide: raam värv antrasiit RAL7016; Avatäide: raam värv antrasiit RAL7016; MÄRKUS: Matt must RAL9005; 380_Lukustus: Sarjastatud; 910_Tooteinfo: ootel; 915_Kasutus-ja-hooldusjuhend: ootel; 306_Ava-laius: 1000 mm; 378_Lävepakk: Allalaskuv lävepakk, helikindel.; 382_Südamik: täpsustada TP-staadiumis; 383_Vasturaud: Tootja standard, matt roostevaba.; 345_Päikesekiirgus-tegur: 0; 336_Sissepääs-hoonesse: no
AC_Pset_RenovationAndPhasing - Renovation Status: New
AR_ÜLD - 009_Märkus: OMA märkus
Name | In | OverallHeight (mm) = 307_Ava-kõrgus (mm) | Reference = 300_Tähis | 001_Nimetus | 310_Materjal | 315_Avanemine | 325_Helipidavus | 330_Tulepüsivus | 355_Pindala (m2) | 360_Ratastooliga | 900_Tootja | 905_Mudel | 377_Leng | 379_Käepide | 381_Lukuraam | 384_Sulgur
SU-03 | Esimene korrus | 2200 | SU-03 | Siseuks | MUDELIS: väljast-Avatäide: raam värv antrasiit RAL7016; Avatäide: raam värv antrasiit RAL7016; seest-Avatäide: raam värv antrasiit RAL7016; Avatäide: raam värv antrasiit RAL7016; MÄRKUS: MDF+värv | Vasak ; ARCHICAD tüüp: Side Hung | R’w ≥ 30 dB | nõudeid ei esitata | 2.2 | no | Structo | Door-S | Pikendatud leng, viimistletud analooglselt ukselehega, peideud hinged, piirdeliistuta lahendus, vuuk täidetakse seinatoon mastiksiga, teha näidis. | Abloy Forum 4, exit matt roostevaba | Standardtoode (EVS-EN 12209), luku viimistlus matt must, ruumi seest avanemine väändenupust. | Peidetud sulgur
SU-02 | Esimene korrus | 2200 | SU-02 | Inva WC-uks | MUDELIS: väljast-Avatäide: raam värv antrasiit RAL7016; Avatäide: raam värv antrasiit RAL7016; seest-Avatäide: raam värv antrasiit RAL7016; Avatäide: raam värv antrasiit RAL7016; MÄRKUS: MDF+värv | Parem ; ARCHICAD tüüp: Side Hung | R’w ≥ 25 dB | nõudeid ei esitata | 2.2 | yes | Structo | Door-S | Pikendatud leng, viimistletud analooglselt ukselehega, peideud hinged, piirdeliistuta lahendus, vuuk täidetakse seinatoon mastiksiga, teha näidis. | Abloy Forum 4, exit matt roostevaba | Invanõuetele vastav tüüpne libliklukk, väljastpoolt avamise võimalusega, tüüp: standardtoode, vt ukselukustuse spetsifikatsioon, viimistlus: lingiga sama, kooskõlastada projekteerijaga. | Peidetud sulgur
SUT-14 | Esimene korrus | 2190 | SUT-14 | Siseuks EI30 (peab olema välisuks) | MUDELIS: väljast-Avatäide: raam värv antrasiit RAL7016; Avatäide: raam värv antrasiit RAL7016; seest-Avatäide: raam värv antrasiit RAL7016; Avatäide: raam värv antrasiit RAL7016; MÄRKUS: metall | -Parem ; ARCHICAD tüüp: Side Hung | R’w ≥ 25 dB | EI30 | 2.19 | no | Saku metall | MFD131 | Tootja standardtoode | Abloy Forum 4, matt roostevaba | Standardtoode (EVS-EN 12209), luku viimistlus matt must, ruumi seest avanemine lingist | -
SU-07 | Esimene korrus | 2200 | SU-07 | Siseuks | MUDELIS: väljast-Avatäide: raam värv antrasiit RAL7016; Avatäide: raam värv antrasiit RAL7016; seest-Avatäide: raam värv antrasiit RAL7016; Avatäide: raam värv antrasiit RAL7016; MÄRKUS: metall-leht | Parem ; ARCHICAD tüüp: Side Hung | R’w ≥ 30 dB | EI30 | 2.2 | no | Saku metall | MID131 | Tootja standardtoode | Abloy Forum 4, matt roostevaba | Standardtoode (EVS-EN 12209), luku viimistlus matt must, ruumi seest avanemine lingist | Peidetud sulgur
SUT-01 | Esimene korrus | 2200 | SUT-01 | Siseuks EI30 | MUDELIS: väljast-Avatäide: raam värv antrasiit RAL7016; Avatäide: raam värv antrasiit RAL7016; seest-Avatäide: raam värv antrasiit RAL7016; Avatäide: raam värv antrasiit RAL7016; MÄRKUS: metall | -Parem ; ARCHICAD tüüp: Side Hung | R’w ≥ 30dB | EI30 Sa | 2.2 | no | Saku metall | MFD131 | Tootja standardtoode | Abloy Forum 4, matt roostevaba | Standardtoode (EVS-EN 12209), luku viimistlus matt must, ruumi seest avanemine lingist | -
SUT-07 | Teine korrus | 2100 | SUT-07 | Siseuks EI30 | MUDELIS: väljast-Avatäide: raam värv antrasiit RAL7016; Avatäide: raam värv antrasiit RAL7016; seest-Avatäide: raam värv antrasiit RAL7016; Avatäide: raam värv antrasiit RAL7016; MÄRKUS: metall | -Parem ; ARCHICAD tüüp: Side Hung | R’w ≥ 30dB | EI30 Sa | 2.1 | no | Saku metall | MFD131 | Tootja standardtoode | Abloy Forum 4, matt roostevaba | Standardtoode (EVS-EN 12209), luku viimistlus matt must, ruumi seest avanemine lingist | -
SUT-13 | Teine korrus | 2100 | SUT-13 | Siseuks EI30 (peab olema välisuks) | MUDELIS: väljast-Avatäide: raam värv antrasiit RAL7016; Avatäide: raam värv antrasiit RAL7016; seest-Avatäide: raam värv antrasiit RAL7016; Avatäide: raam värv antrasiit RAL7016; MÄRKUS: metall | -Parem ; ARCHICAD tüüp: Side Hung | R’w ≥ 25 dB | EI30 | 2.1 | no | Saku metall | MFD131 | Tootja standardtoode | Abloy Forum 4, matt roostevaba | Standardtoode (EVS-EN 12209), luku viimistlus matt must, ruumi seest avanemine lingist | -

# IfcDoor: Door 26, SU-06
In: Esimene korrus
Type - OperationType: SINGLE_SWING_LEFT; ParameterTakesPrecedence: no; Sizeable: no
Type - Door Lining Properties - LiningThickness: 42 mm
Type - Door Panel Properties - Panel 1 - PanelDepth: 40 mm; PanelOperation: SWINGING; PanelWidth: 1; PanelPosition: MIDDLE
OverallHeight: 2200 mm; OverallWidth: 800 mm; Classification: 1.10 IfcDoorStyle (uks) (BIM ÜBN + Archicad Classification)
Pset_DoorCommon - Reference: SU-06; ThermalTransmittance: 0; IsExternal: no
AR_Uks - 001_Nimetus: Siseuks; 300_Tähis: SU-06; 310_Materjal: MUDELIS: väljast-Avatäide: raam värv antrasiit RAL7016; Avatäide: raam värv antrasiit RAL7016; seest-Avatäide: raam värv antrasiit RAL7016; Avatäide: raam värv antrasiit RAL7016; MÄRKUS: MDF+värv; 315_Avanemine: Parem ; ARCHICAD tüüp: Side Hung; 320_Klaas: ootel; 325_Helipidavus: R’w ≥ 25 dB; 330_Tulepüsivus: nõudeid ei esitata; 335_Välispiire: no; 340_Soojusläbivus: 0; 350_Klaaspakett: -; 355_Pindala: 1.76 m2; 360_Ratastooliga: no; 365_Isesulguv: no; 370_Evakuatsiooniväljapääs: no; 375_Viimistlus-seest: MUDELIS: Avatäide: raam värv antrasiit RAL7016; Avatäide: raam värv antrasiit RAL7016; MÄRKUS: Matt must RAL9005; 376_Viimistlus-väljast: MUDELIS: Avatäide: raam värv antrasiit RAL7016; Avatäide: raam värv antrasiit RAL7016; MÄRKUS: Matt must RAL9005; 380_Lukustus: Sarjastatud; 900_Tootja: Structo; 905_Mudel: Door-S; 910_Tooteinfo: ootel; 915_Kasutus-ja-hooldusjuhend: ootel; 306_Ava-laius: 800 mm; 307_Ava-kõrgus: 2200 mm; 377_Leng: Pikendatud leng, viimistletud analooglselt ukselehega, peideud hinged, piirdeliistuta lahendus, vuuk täidetakse seinatoon mastiksiga, teha näidis.; 378_Lävepakk: Allalaskuv lävepakk, helikindel.; 379_Käepide: Abloy Forum 4, matt roostevaba; 381_Lukuraam: Standardtoode (EVS-EN 12209), luku viimistlus matt must, ruumi seest avanemine väändenupust.; 382_Südamik: täpsustada TP-staadiumis; 383_Vasturaud: Tootja standard, matt roostevaba.; 384_Sulgur: Peidetud sulgur; 345_Päikesekiirgus-tegur: 0; 336_Sissepääs-hoonesse: no
AR_ÜLD - 009_Märkus: OMA märkus
AC_Pset_RenovationAndPhasing - Renovation Status: New

# IfcDoor: Door 26, VU-04a
In: Teine korrus
Type - OperationType: SINGLE_SWING_RIGHT; ParameterTakesPrecedence: no; Sizeable: no
Type - Door Lining Properties - LiningDepth: 180 mm; LiningThickness: 45 mm; LiningOffset: 220 mm
Type - Door Panel Properties - Panel 1 - PanelDepth: 80 mm; PanelOperation: SWINGING; PanelWidth: 1; PanelPosition: MIDDLE
OverallHeight: 2479.91 mm; OverallWidth: 1100 mm; Classification: 1.10 IfcDoorStyle (uks) (BIM ÜBN + Archicad Classification)
AR_Uks - 001_Nimetus: Alumiiniumraamil välisuks KF süsteemis; 300_Tähis: VU-04a; 310_Materjal: MUDELIS: väljast-Avatäide: raam värv antrasiit RAL7016; Avatäide: raam värv antrasiit RAL7016; seest-Avatäide: raam värv antrasiit RAL7016; Avatäide: raam värv antrasiit RAL7016; MÄRKUS: Alumiinium; 315_Avanemine: Pöördavatav rullhingedel ukselehtVasak ; ARCHICAD tüüp: Side Hung; 320_Klaas: Kolmekordne klaaspakett, argoongaasiga, vaheliistud mustad, välimine: päikesekaitseklaas Cool-Lite SKN 183 II, LT=66%, karastatud klaas, klaasitoon: kirgas, keskmine: Planiclear, klaasitoon: kirgas, sisemine: Planitherm XN, lamineeritud floatklaas, klaasitoon: kirgas; 325_Helipidavus: R’tr,s,w = 30 dB; 330_Tulepüsivus: nõudeid ei esitata; 335_Välispiire: yes; 340_Soojusläbivus: 0; 350_Klaaspakett: 3k6SecSKN183II+4+44.1PlthXN-18Ar/18Ar (vaheliistude toon: must), Ug=0,5 W/(m2K); 355_Pindala: 2.7279 m2; 360_Ratastooliga: no; 365_Isesulguv: no; 370_Evakuatsiooniväljapääs: yes; 375_Viimistlus-seest: MUDELIS: Avatäide: raam värv antrasiit RAL7016; Avatäide: raam värv antrasiit RAL7016; MÄRKUS: Matt antrasiit RAL7016; 376_Viimistlus-väljast: MUDELIS: Avatäide: raam värv antrasiit RAL7016; Avatäide: raam värv antrasiit RAL7016; MÄRKUS: Matt antrasiit RAL7016; 380_Lukustus: Kolmepunkti lukustussüsteem, täpsustada TP-staadiumis; 900_Tootja: ootel; 905_Mudel: ootel; 910_Tooteinfo: ootel; 915_Kasutus-ja-hooldusjuhend: ootel; 306_Ava-laius: 1100 mm; 307_Ava-kõrgus: 2479.91 mm; 377_Leng: AD UP 90; 378_Lävepakk: tootja standardtoode; 379_Käepide: tootja standard, viimistlus: roostevaba; 381_Lukuraam: täpsustada TP-staadiumis; 382_Südamik: täpsustada TP-staadiumis; 383_Vasturaud: täpsustada TP-staadiumis; 384_Sulgur: tootja standardtoode; 345_Päikesekiirgus-tegur: 0; 336_Sissepääs-hoonesse: yes
AC_Pset_RenovationAndPhasing - Renovation Status: New
Pset_DoorCommon - Reference: VU-04a; ThermalTransmittance: 0; GlazingAreaFraction: 1.61599; IsExternal: yes

# IfcDoor: Door 26, SUT-02
In: Esimene korrus
Type - OperationType: SINGLE_SWING_RIGHT; ParameterTakesPrecedence: no; Sizeable: no
Type - Door Lining Properties - LiningDepth: 40 mm; LiningThickness: 40 mm; LiningOffset: 6.93889e-15 mm
Type - Door Panel Properties - Panel 1 - PanelDepth: 40 mm; PanelOperation: SWINGING; PanelWidth: 1; PanelPosition: MIDDLE
OverallHeight: 2200 mm; OverallWidth: 900 mm; Classification: 1.10 IfcDoorStyle (uks) (BIM ÜBN + Archicad Classification)
Pset_DoorCommon - Reference: SUT-02; ThermalTransmittance: 0; IsExternal: no
AR_Uks - 001_Nimetus: Siseuks EI30; 300_Tähis: SUT-02; 310_Materjal: MUDELIS: väljast-Avatäide: raam värv antrasiit RAL7016; Avatäide: raam värv antrasiit RAL7016; seest-Avatäide: raam värv antrasiit RAL7016; Avatäide: raam värv antrasiit RAL7016; MÄRKUS: MDF+värv; 315_Avanemine: -Vasak ; ARCHICAD tüüp: Side Hung; 320_Klaas: ootel; 325_Helipidavus: R’w ≥ 30dB; 330_Tulepüsivus: EI30 Sa; 335_Välispiire: no; 340_Soojusläbivus: 0; 350_Klaaspakett: -; 355_Pindala: 1.98 m2; 360_Ratastooliga: no; 365_Isesulguv: no; 370_Evakuatsiooniväljapääs: no; 375_Viimistlus-seest: MUDELIS: Avatäide: raam värv antrasiit RAL7016; Avatäide: raam värv antrasiit RAL7016; MÄRKUS: Matt must RAL9005; 376_Viimistlus-väljast: MUDELIS: Avatäide: raam värv antrasiit RAL7016; Avatäide: raam värv antrasiit RAL7016; MÄRKUS: Matt must RAL9005; 380_Lukustus: Sarjastatud; 900_Tootja: Structo; 905_Mudel: Door-S; 910_Tooteinfo: ootel; 915_Kasutus-ja-hooldusjuhend: ootel; 306_Ava-laius: 900 mm; 307_Ava-kõrgus: 2200 mm; 377_Leng: Tootja standardtoode; 378_Lävepakk: Allalaskuv lävepakk, helikindel.; 379_Käepide: Abloy Forum 4, matt roostevaba; 381_Lukuraam: Standardtoode (EVS-EN 12209), luku viimistlus matt must, ruumi seest avanemine lingist; 382_Südamik: täpsustada TP-staadiumis; 383_Vasturaud: Tootja standard, matt roostevaba.; 384_Sulgur: -; 345_Päikesekiirgus-tegur: 0; 336_Sissepääs-hoonesse: no
AR_ÜLD - 009_Märkus: OMA märkus
AC_Pset_RenovationAndPhasing - Renovation Status: New

# IfcDoor: Door 26, KS-01
In: Esimene korrus
Type - OperationType: SINGLE_SWING_RIGHT; ParameterTakesPrecedence: no; Sizeable: no
Type - Door Lining Properties - LiningThickness: 10 mm
Type - Door Panel Properties - Panel 1 - PanelDepth: 4 mm; PanelOperation: SWINGING; PanelWidth: 1; PanelPosition: MIDDLE
OverallHeight: 2100 mm; OverallWidth: 700 mm; Classification: 1.10 IfcDoorStyle (uks) (BIM ÜBN + Archicad Classification)
Pset_DoorCommon - Reference: KS-01; ThermalTransmittance: 0; GlazingAreaFraction: 1.4212; IsExternal: no
AR_Uks - 001_Nimetus: Sauna klaasuks; 300_Tähis: KS-01; 310_Materjal: MUDELIS: väljast-Avatäide: leht värv antrasiit RAL7016; Avatäide: leht värv antrasiit RAL7016; seest-Avatäide: leht värv antrasiit RAL7016; Avatäide: leht värv antrasiit RAL7016; MÄRKUS: Satiin klaas; 315_Avanemine: -Vasak ; ARCHICAD tüüp: Side Hung; 320_Klaas: ootel; 325_Helipidavus: nõudeid ei esitata; 330_Tulepüsivus: nõudeid ei esitata; 335_Välispiire: no; 340_Soojusläbivus: 0; 350_Klaaspakett: -; 355_Pindala: 1.47 m2; 360_Ratastooliga: no; 365_Isesulguv: no; 370_Evakuatsiooniväljapääs: no; 375_Viimistlus-seest: MUDELIS: Avatäide: leht värv antrasiit RAL7016; Avatäide: leht värv antrasiit RAL7016; MÄRKUS: Satiin klaas; 376_Viimistlus-väljast: MUDELIS: Avatäide: leht värv antrasiit RAL7016; Avatäide: leht värv antrasiit RAL7016; MÄRKUS: Satiin klaas; 380_Lukustus: -; 900_Tootja: Glass solution; 905_Mudel: Modern black; 910_Tooteinfo: ootel; 915_Kasutus-ja-hooldusjuhend: ootel; 306_Ava-laius: 700 mm; 307_Ava-kõrgus: 2100 mm; 377_Leng: Must puidust leng, mustad hinged.; 378_Lävepakk: Lävepakk puudub; 379_Käepide: Modern black; 381_Lukuraam: -; 382_Südamik: täpsustada TP-staadiumis; 383_Vasturaud: -; 384_Sulgur: -; 345_Päikesekiirgus-tegur: 0; 336_Sissepääs-hoonesse: no
AR_ÜLD - 009_Märkus: OMA märkus
AC_Pset_RenovationAndPhasing - Renovation Status: New

# IfcDoor: Door 26 (5)
Type - OperationType: SINGLE_SWING_RIGHT; ParameterTakesPrecedence: no; Sizeable: no
Type - Door Lining Properties - LiningThickness: 40 mm
Type - Door Panel Properties - Panel 1 - PanelDepth: 40 mm; PanelOperation: SWINGING; PanelWidth: 1; PanelPosition: MIDDLE
OverallHeight: 2200 mm; Classification: 1.10 IfcDoorStyle (uks) (BIM ÜBN + Archicad Classification)
Pset_DoorCommon - ThermalTransmittance: 0; IsExternal: no
AR_Uks - 001_Nimetus: Siseuks; 310_Materjal: MUDELIS: väljast-Avatäide: raam värv antrasiit RAL7016; Avatäide: raam värv antrasiit RAL7016; seest-Avatäide: raam värv antrasiit RAL7016; Avatäide: raam värv antrasiit RAL7016; MÄRKUS: metall-leht; 330_Tulepüsivus: nõudeid ei esitata; 335_Välispiire: no; 340_Soojusläbivus: 0; 350_Klaaspakett: -; 360_Ratastooliga: no; 365_Isesulguv: no; 370_Evakuatsiooniväljapääs: no; 375_Viimistlus-seest: MUDELIS: Avatäide: raam värv antrasiit RAL7016; Avatäide: raam värv antrasiit RAL7016; MÄRKUS: Matt must RAL9005; 376_Viimistlus-väljast: MUDELIS: Avatäide: raam värv antrasiit RAL7016; Avatäide: raam värv antrasiit RAL7016; MÄRKUS: Matt must RAL9005; 380_Lukustus: Sarjastatud; 900_Tootja: Saku metall; 905_Mudel: MID131; 910_Tooteinfo: ootel; 915_Kasutus-ja-hooldusjuhend: ootel; 307_Ava-kõrgus: 2200 mm; 377_Leng: Tootja standardtoode; 379_Käepide: Abloy Forum 4, matt roostevaba; 381_Lukuraam: Standardtoode (EVS-EN 12209), luku viimistlus matt must, ruumi seest avanemine lingist; 382_Südamik: täpsustada TP-staadiumis; 383_Vasturaud: Tootja standard, matt roostevaba.; 384_Sulgur: -; 345_Päikesekiirgus-tegur: 0; 336_Sissepääs-hoonesse: no
AR_ÜLD - 009_Märkus: OMA märkus
AC_Pset_RenovationAndPhasing - Renovation Status: New
Name | In | OverallWidth (mm) = 306_Ava-laius (mm) | Reference = 300_Tähis | 315_Avanemine | 320_Klaas | 325_Helipidavus | 355_Pindala (m2) | 378_Lävepakk
SU-08 | Esimene korrus | 1000 | SU-08 | Vasak ; ARCHICAD tüüp: Side Hung | ootel | R’w ≥ 30 dB | 2.2 | Allalaskuv lävepakk, helikindel.
SU-01 | Esimene korrus | 900 | SU-01 | Parem ; ARCHICAD tüüp: Side Hung | puudub | R’w ≥ 30 dB | 1.98 | Uksetootja madal lävepakk, maksimaalne h=20 mm, viimistletud harjatud naturaalne roostevaba teras, kooskõlastada projekteerijaga.
SU-08 | Esimene korrus | 1000 | SU-08 | Vasak ; ARCHICAD tüüp: Side Hung | ootel | nõudeid ei esitata | 2.2 | Allalaskuv lävepakk, helikindel.
SU-04 | Esimene korrus | 900 | SU-04 | Vasak ; ARCHICAD tüüp: Side Hung | ootel | nõudeid ei esitata | 1.98 | Uksetootja madal lävepakk, maksimaalne h=20 mm, viimistletud harjatud naturaalne roostevaba teras, kooskõlastada projekteerijaga.
SU-14 | Teine korrus | 900 | SU-14 | Vasak ; ARCHICAD tüüp: Side Hung | ootel | nõudeid ei esitata | 1.98 | Allalaskuv lävepakk, helikindel.

# IfcDoor: Door 26, SU-05
In: Esimene korrus
Type - OperationType: SINGLE_SWING_RIGHT; ParameterTakesPrecedence: no; Sizeable: no
Type - Door Lining Properties - LiningThickness: 42 mm
Type - Door Panel Properties - Panel 1 - PanelDepth: 40 mm; PanelOperation: SWINGING; PanelWidth: 1; PanelPosition: MIDDLE
OverallHeight: 2200 mm; OverallWidth: 800 mm; Classification: 1.10 IfcDoorStyle (uks) (BIM ÜBN + Archicad Classification)
Pset_DoorCommon - Reference: SU-05; ThermalTransmittance: 0; IsExternal: no
AR_ÜLD - 009_Märkus: OMA märkus
AC_Pset_RenovationAndPhasing - Renovation Status: New
AR_Uks - 001_Nimetus: Siseuks; 300_Tähis: SU-05; 310_Materjal: MUDELIS: väljast-Avatäide: raam värv antrasiit RAL7016; Avatäide: raam värv antrasiit RAL7016; seest-Avatäide: raam värv antrasiit RAL7016; Avatäide: raam värv antrasiit RAL7016; MÄRKUS: MDF+värv; 315_Avanemine: Vasak ; ARCHICAD tüüp: Side Hung; 320_Klaas: ootel; 325_Helipidavus: R’w ≥ 25 dB; 330_Tulepüsivus: nõudeid ei esitata; 335_Välispiire: no; 340_Soojusläbivus: 0; 350_Klaaspakett: -; 355_Pindala: 1.76 m2; 360_Ratastooliga: no; 365_Isesulguv: no; 370_Evakuatsiooniväljapääs: no; 375_Viimistlus-seest: MUDELIS: Avatäide: raam värv antrasiit RAL7016; Avatäide: raam värv antrasiit RAL7016; MÄRKUS: Matt must RAL9005; 376_Viimistlus-väljast: MUDELIS: Avatäide: raam värv antrasiit RAL7016; Avatäide: raam värv antrasiit RAL7016; MÄRKUS: Matt must RAL9005; 380_Lukustus: Sarjastatud; 900_Tootja: Structo; 905_Mudel: Door-S; 910_Tooteinfo: ootel; 915_Kasutus-ja-hooldusjuhend: ootel; 306_Ava-laius: 800 mm; 307_Ava-kõrgus: 2200 mm; 377_Leng: Pikendatud leng, viimistletud analooglselt ukselehega, peideud hinged, piirdeliistuta lahendus, vuuk täidetakse seinatoon mastiksiga, teha näidis.; 378_Lävepakk: Allalaskuv lävepakk, helikindel.; 379_Käepide: Abloy Forum 4, matt roostevaba; 381_Lukuraam: Standardtoode (EVS-EN 12209), luku viimistlus matt must, ruumi seest avanemine väändenupust.; 382_Südamik: täpsustada TP-staadiumis; 383_Vasturaud: Tootja standard, matt roostevaba.; 384_Sulgur: Peidetud sulgur; 345_Päikesekiirgus-tegur: 0; 336_Sissepääs-hoonesse: no

# IfcDoor: Door with 2 Sidelights and Transom 26, SUK-10
In: Teine korrus
Type - OperationType: USERDEFINED; ParameterTakesPrecedence: no; Sizeable: no
OverallHeight: 3060 mm; OverallWidth: 4475 mm; Classification: 1.10 IfcDoorStyle (uks) (BIM ÜBN + Archicad Classification)
Pset_DoorCommon - Reference: SUK-10; ThermalTransmittance: 0; GlazingAreaFraction: 10.7663; IsExternal: no
AR_Uks - 001_Nimetus: Küljeklaasidega siseuks; 300_Tähis: SUK-10; 310_Materjal: MUDELIS: väljast-Avatäide: raam värv antrasiit RAL7016; Avatäide: raam värv antrasiit RAL7016; seest-Avatäide: raam värv antrasiit RAL7016; Avatäide: raam värv antrasiit RAL7016; MÄRKUS: MDF/klaas; 315_Avanemine: Parem ; ARCHICAD tüüp: Side Hung; 320_Klaas: ootel; 325_Helipidavus: R’w ≥ 30dB; 330_Tulepüsivus: nõudeid ei esitata; 335_Välispiire: no; 340_Soojusläbivus: 0; 350_Klaaspakett: Kahekordne klaaspakett, vaheliistude toon: must, lamineering; 355_Pindala: 13.6935 m2; 360_Ratastooliga: no; 365_Isesulguv: no; 370_Evakuatsiooniväljapääs: no; 375_Viimistlus-seest: MUDELIS: Avatäide: raam värv antrasiit RAL7016; Avatäide: raam värv antrasiit RAL7016; MÄRKUS: Matt must RAL9005; 376_Viimistlus-väljast: MUDELIS: Avatäide: raam värv antrasiit RAL7016; Avatäide: raam värv antrasiit RAL7016; MÄRKUS: Matt must RAL9005; 380_Lukustus: Sarjastatud; 900_Tootja: Structo; 905_Mudel: PORTA– 53WS; 910_Tooteinfo: ootel; 915_Kasutus-ja-hooldusjuhend: ootel; 306_Ava-laius: 4475 mm; 307_Ava-kõrgus: 3060 mm; 377_Leng: Tootja standardtoode; 378_Lävepakk: Allalaskuv lävepakk, helikindel.; 379_Käepide: Abloy Forum 4, matt roostevaba; 381_Lukuraam: Standardtoode (EVS-EN 12209), luku viimistlus matt must, ruumi seest avanemine lingist; 382_Südamik: täpsustada TP-staadiumis; 383_Vasturaud: Tootja standard, matt roostevaba.; 384_Sulgur: -; 345_Päikesekiirgus-tegur: 0; 336_Sissepääs-hoonesse: no
AR_ÜLD - 009_Märkus: OMA märkus
AC_Pset_RenovationAndPhasing - Renovation Status: New

# IfcDoor: Door with Sidelight on Side 1 and Transom 26 (10)
In: Teine korrus
Type - OperationType: SINGLE_SWING_RIGHT; ParameterTakesPrecedence: no; Sizeable: no
Type - Door Panel Properties - Panel 1 - PanelDepth: 40 mm; PanelOperation: SWINGING; PanelWidth: 1; PanelPosition: MIDDLE
OverallHeight: 3060 mm; OverallWidth: 1550 mm; Classification: 1.10 IfcDoorStyle (uks) (BIM ÜBN + Archicad Classification)
Pset_DoorCommon - Reference: SUK-08; ThermalTransmittance: 0; IsExternal: no
AR_Uks - 001_Nimetus: Küljeklaasiga siseuks; 300_Tähis: SUK-08; 315_Avanemine: Vasak ; ARCHICAD tüüp: Side Hung; 320_Klaas: ootel; 325_Helipidavus: R’w ≥ 30dB; 330_Tulepüsivus: nõudeid ei esitata; 335_Välispiire: no; 340_Soojusläbivus: 0; 350_Klaaspakett: Kahekordne klaaspakett, vaheliistude toon: must, lamineering; 355_Pindala: 4.743 m2; 360_Ratastooliga: no; 365_Isesulguv: no; 370_Evakuatsiooniväljapääs: no; 380_Lukustus: Sarjastatud; 900_Tootja: Structo; 905_Mudel: PORTA– 53WS; 910_Tooteinfo: ootel; 915_Kasutus-ja-hooldusjuhend: ootel; 306_Ava-laius: 1550 mm; 307_Ava-kõrgus: 3060 mm; 377_Leng: Tootja standardtoode; 378_Lävepakk: Allalaskuv lävepakk, helikindel.; 379_Käepide: Abloy Forum 4, matt roostevaba; 381_Lukuraam: Standardtoode (EVS-EN 12209), luku viimistlus matt must, ruumi seest avanemine lingist; 382_Südamik: täpsustada TP-staadiumis; 383_Vasturaud: Tootja standard, matt roostevaba.; 384_Sulgur: -; 345_Päikesekiirgus-tegur: 0; 336_Sissepääs-hoonesse: no
AR_ÜLD - 009_Märkus: OMA märkus
AC_Pset_RenovationAndPhasing - Renovation Status: New
Name | GlazingAreaFraction | 310_Materjal | 375_Viimistlus-seest = 376_Viimistlus-väljast
SUK-08 | 2.2214 | MUDELIS: väljast-Avatäide: raam värv antrasiit RAL7016; Avatäide: raam värv antrasiit RAL7016; seest-Avatäide: raam värv antrasiit RAL7016; Avatäide: raam värv antrasiit RAL7016; MÄRKUS: MDF/klaas | MUDELIS: Avatäide: raam värv antrasiit RAL7016; Avatäide: raam värv antrasiit RAL7016; MÄRKUS: Matt must RAL9005
SUK-08 | 2.3397 | MUDELIS: väljast-Avatäide: leht värv antrasiit RAL7016; Avatäide: leht värv antrasiit RAL7016; seest-Avatäide: leht värv antrasiit RAL7016; Avatäide: leht värv antrasiit RAL7016; MÄRKUS: MDF/klaas | MUDELIS: Avatäide: leht värv antrasiit RAL7016; Avatäide: leht värv antrasiit RAL7016; MÄRKUS: Matt must RAL9005
8 x SUK-08 | 2.3397 | MUDELIS: väljast-Avatäide: raam värv antrasiit RAL7016; Avatäide: raam värv antrasiit RAL7016; seest-Avatäide: raam värv antrasiit RAL7016; Avatäide: raam värv antrasiit RAL7016; MÄRKUS: MDF/klaas | MUDELIS: Avatäide: raam värv antrasiit RAL7016; Avatäide: raam värv antrasiit RAL7016; MÄRKUS: Matt must RAL9005

# IfcDoor: Door with Sidelight on Side 2 and Transom 26 (2)
In: Teine korrus
Type - OperationType: SINGLE_SWING_LEFT; ParameterTakesPrecedence: no; Sizeable: no
Type - Door Panel Properties - Panel 1 - PanelDepth: 40 mm; PanelOperation: SWINGING; PanelWidth: 1; PanelPosition: MIDDLE
OverallHeight: 3060 mm; Classification: 1.10 IfcDoorStyle (uks) (BIM ÜBN + Archicad Classification)
Pset_DoorCommon - ThermalTransmittance: 0; IsExternal: no
AR_Uks - 001_Nimetus: Küljeklaasiga siseuks; 310_Materjal: MUDELIS: väljast-Avatäide: raam värv antrasiit RAL7016; Avatäide: raam värv antrasiit RAL7016; seest-Avatäide: raam värv antrasiit RAL7016; Avatäide: raam värv antrasiit RAL7016; MÄRKUS: MDF/klaas; 315_Avanemine: Parem ; ARCHICAD tüüp: Side Hung; 320_Klaas: ootel; 325_Helipidavus: R’w ≥ 35 dB; 330_Tulepüsivus: nõudeid ei esitata; 335_Välispiire: no; 340_Soojusläbivus: 0; 350_Klaaspakett: Kahekordne klaaspakett, vaheliistude toon: must, lamineering; 360_Ratastooliga: no; 365_Isesulguv: no; 370_Evakuatsiooniväljapääs: no; 375_Viimistlus-seest: MUDELIS: Avatäide: raam värv antrasiit RAL7016; Avatäide: raam värv antrasiit RAL7016; MÄRKUS: Matt must RAL9005; 376_Viimistlus-väljast: MUDELIS: Avatäide: raam värv antrasiit RAL7016; Avatäide: raam värv antrasiit RAL7016; MÄRKUS: Matt must RAL9005; 380_Lukustus: Sarjastatud; 900_Tootja: Structo; 905_Mudel: PORTA– 53WS; 910_Tooteinfo: ootel; 915_Kasutus-ja-hooldusjuhend: ootel; 307_Ava-kõrgus: 3060 mm; 377_Leng: Tootja standardtoode; 378_Lävepakk: Allalaskuv lävepakk, helikindel.; 379_Käepide: Abloy Forum 4, exit matt roostevaba; 381_Lukuraam: Standardtoode (EVS-EN 12209), luku viimistlus matt must, ruumi seest avanemine lingist; 382_Südamik: täpsustada TP-staadiumis; 383_Vasturaud: Tootja standard, matt roostevaba.; 384_Sulgur: -; 345_Päikesekiirgus-tegur: 0; 336_Sissepääs-hoonesse: no
AR_ÜLD - 009_Märkus: OMA märkus
AC_Pset_RenovationAndPhasing - Renovation Status: New
Name | OverallWidth (mm) = 306_Ava-laius (mm) | Reference = 300_Tähis | GlazingAreaFraction | 355_Pindala (m2)
SUK-07 | 1435 | SUK-07 | 1.84995 | 4.3911
SUK-06 | 1250 | SUK-06 | 1.419 | 3.825

# IfcDoor: Door with Sidelight on Side 2 and Transom 26 (2)
In: Teine korrus
Type - OperationType: SINGLE_SWING_RIGHT; ParameterTakesPrecedence: no; Sizeable: no
Type - Door Panel Properties - Panel 1 - PanelDepth: 40 mm; PanelOperation: SWINGING; PanelWidth: 1; PanelPosition: MIDDLE
OverallHeight: 3060 mm; Classification: 1.10 IfcDoorStyle (uks) (BIM ÜBN + Archicad Classification)
Pset_DoorCommon - ThermalTransmittance: 0; IsExternal: no
AR_Uks - 001_Nimetus: Küljeklaasiga siseuks; 315_Avanemine: Vasak ; ARCHICAD tüüp: Side Hung; 320_Klaas: ootel; 325_Helipidavus: R’w ≥ 30dB; 330_Tulepüsivus: nõudeid ei esitata; 335_Välispiire: no; 340_Soojusläbivus: 0; 350_Klaaspakett: Kahekordne klaaspakett, vaheliistude toon: must, lamineering; 360_Ratastooliga: no; 365_Isesulguv: no; 370_Evakuatsiooniväljapääs: no; 380_Lukustus: Sarjastatud; 900_Tootja: Structo; 905_Mudel: PORTA– 53WS; 910_Tooteinfo: ootel; 915_Kasutus-ja-hooldusjuhend: ootel; 307_Ava-kõrgus: 3060 mm; 377_Leng: Tootja standardtoode; 378_Lävepakk: Allalaskuv lävepakk, helikindel.; 379_Käepide: Abloy Forum 4, matt roostevaba; 381_Lukuraam: Standardtoode (EVS-EN 12209), luku viimistlus matt must, ruumi seest avanemine lingist; 382_Südamik: täpsustada TP-staadiumis; 383_Vasturaud: Tootja standard, matt roostevaba.; 384_Sulgur: -; 345_Päikesekiirgus-tegur: 0; 336_Sissepääs-hoonesse: no
AR_ÜLD - 009_Märkus: OMA märkus
AC_Pset_RenovationAndPhasing - Renovation Status: New
Name | OverallWidth (mm) = 306_Ava-laius (mm) | Reference = 300_Tähis | GlazingAreaFraction | 310_Materjal | 355_Pindala (m2) | 375_Viimistlus-seest = 376_Viimistlus-väljast
SUK-08 | 1550 | SUK-08 | 2.316 | MUDELIS: väljast-Avatäide: leht värv antrasiit RAL7016; Avatäide: leht värv antrasiit RAL7016; seest-Avatäide: leht värv antrasiit RAL7016; Avatäide: leht värv antrasiit RAL7016; MÄRKUS: MDF/klaas | 4.743 | MUDELIS: Avatäide: leht värv antrasiit RAL7016; Avatäide: leht värv antrasiit RAL7016; MÄRKUS: Matt must RAL9005
SUK-09 | 1250 | SUK-09 | 1.3953 | MUDELIS: väljast-Avatäide: raam värv antrasiit RAL7016; Avatäide: raam värv antrasiit RAL7016; seest-Avatäide: raam värv antrasiit RAL7016; Avatäide: raam värv antrasiit RAL7016; MÄRKUS: MDF/klaas | 3.825 | MUDELIS: Avatäide: raam värv antrasiit RAL7016; Avatäide: raam värv antrasiit RAL7016; MÄRKUS: Matt must RAL9005

# IfcDoor: Door with Transom 26, SU-10
In: Teine korrus
Type - OperationType: SINGLE_SWING_LEFT; ParameterTakesPrecedence: no; Sizeable: no
Type - Door Lining Properties - LiningDepth: 60 mm; LiningThickness: 40 mm; TransomThickness: 40 mm; TransomOffset: 2400 mm; LiningOffset: -126 mm
Type - Door Panel Properties - Panel 1 - PanelDepth: 40 mm; PanelOperation: SWINGING; PanelWidth: 1; PanelPosition: MIDDLE
OverallHeight: 3060 mm; OverallWidth: 800 mm; Classification: 1.10 IfcDoorStyle (uks) (BIM ÜBN + Archicad Classification)
Pset_DoorCommon - Reference: SU-10; ThermalTransmittance: 0; IsExternal: no
AR_Uks - 001_Nimetus: Siirdeõhupaneeliga siseuks; 300_Tähis: SU-10; 310_Materjal: MUDELIS: väljast-Avatäide: raam värv antrasiit RAL7016; Avatäide: raam värv antrasiit RAL7016; seest-Avatäide: raam värv antrasiit RAL7016; Avatäide: raam värv antrasiit RAL7016; MÄRKUS: MDF+värv; 315_Avanemine: Parem ; ARCHICAD tüüp: Side Hung; 320_Klaas: ootel; 325_Helipidavus: R’w ≥ 30 dB; 330_Tulepüsivus: nõudeid ei esitata; 335_Välispiire: no; 340_Soojusläbivus: 0; 350_Klaaspakett: -; 355_Pindala: 2.448 m2; 360_Ratastooliga: no; 365_Isesulguv: no; 370_Evakuatsiooniväljapääs: no; 375_Viimistlus-seest: MUDELIS: Avatäide: raam värv antrasiit RAL7016; Avatäide: raam värv antrasiit RAL7016; MÄRKUS: Matt must RAL9005; 376_Viimistlus-väljast: MUDELIS: Avatäide: raam värv antrasiit RAL7016; Avatäide: raam värv antrasiit RAL7016; MÄRKUS: Matt must RAL9005; 380_Lukustus: Sarjastatud; 900_Tootja: Structo; 905_Mudel: Door-S; 910_Tooteinfo: ootel; 915_Kasutus-ja-hooldusjuhend: ootel; 306_Ava-laius: 800 mm; 307_Ava-kõrgus: 3060 mm; 377_Leng: Tootja standardtoode; 378_Lävepakk: Allalaskuv lävepakk, helikindel.; 379_Käepide: Abloy Forum 4, matt roostevaba; 381_Lukuraam: Standardtoode (EVS-EN 12209), luku viimistlus matt must, ruumi seest avanemine väändenupust.; 382_Südamik: täpsustada TP-staadiumis; 383_Vasturaud: Tootja standard, matt roostevaba.; 384_Sulgur: -; 345_Päikesekiirgus-tegur: 0; 336_Sissepääs-hoonesse: no
AR_ÜLD - 009_Märkus: OMA märkus
AC_Pset_RenovationAndPhasing - Renovation Status: New

# IfcDoor: Door with Transom 26, SU-09
In: Teine korrus
Type - OperationType: SINGLE_SWING_LEFT; ParameterTakesPrecedence: no; Sizeable: no
Type - Door Lining Properties - LiningDepth: 60 mm; LiningThickness: 40 mm; TransomThickness: 40 mm; TransomOffset: 2400 mm; LiningOffset: -145 mm
Type - Door Panel Properties - Panel 1 - PanelDepth: 40 mm; PanelOperation: SWINGING; PanelWidth: 1; PanelPosition: MIDDLE
OverallHeight: 3060 mm; OverallWidth: 1000 mm; Classification: 1.10 IfcDoorStyle (uks) (BIM ÜBN + Archicad Classification)
Pset_DoorCommon - Reference: SU-09; ThermalTransmittance: 0; IsExternal: no
AR_Uks - 001_Nimetus: Ülaframuugiga siseuks; 300_Tähis: SU-09; 310_Materjal: MUDELIS: väljast-Avatäide: raam värv antrasiit RAL7016; Avatäide: raam värv antrasiit RAL7016; seest-Avatäide: raam värv antrasiit RAL7016; Avatäide: raam värv antrasiit RAL7016; MÄRKUS: MDF+värv; 315_Avanemine: Parem ; ARCHICAD tüüp: Side Hung; 320_Klaas: ootel; 325_Helipidavus: R’w ≥ 25 dB; 330_Tulepüsivus: nõudeid ei esitata; 335_Välispiire: no; 340_Soojusläbivus: 0; 350_Klaaspakett: ootel; 355_Pindala: 3.06 m2; 360_Ratastooliga: no; 365_Isesulguv: no; 370_Evakuatsiooniväljapääs: no; 375_Viimistlus-seest: MUDELIS: Avatäide: raam värv antrasiit RAL7016; Avatäide: raam värv antrasiit RAL7016; MÄRKUS: Matt must RAL9005; 376_Viimistlus-väljast: MUDELIS: Avatäide: raam värv antrasiit RAL7016; Avatäide: raam värv antrasiit RAL7016; MÄRKUS: Matt must RAL9005; 380_Lukustus: Sarjastatud; 900_Tootja: Structo; 905_Mudel: Door-S; 910_Tooteinfo: ootel; 915_Kasutus-ja-hooldusjuhend: ootel; 306_Ava-laius: 1000 mm; 307_Ava-kõrgus: 3060 mm; 377_Leng: Tootja standardtoode; 378_Lävepakk: Allalaskuv lävepakk, helikindel.; 379_Käepide: Abloy Forum 4, matt roostevaba; 381_Lukuraam: Standardtoode (EVS-EN 12209), luku viimistlus matt must, ruumi seest avanemine lingist; 382_Südamik: täpsustada TP-staadiumis; 383_Vasturaud: täpsustada TP-staadiumis; 384_Sulgur: -; 345_Päikesekiirgus-tegur: 0; 336_Sissepääs-hoonesse: no
AC_Pset_RenovationAndPhasing - Renovation Status: New
AR_ÜLD - 009_Märkus: OMA märkus

# IfcDoor: Door with Transom 26 (2)
In: Teine korrus
Type - OperationType: SINGLE_SWING_LEFT; ParameterTakesPrecedence: no; Sizeable: no
Type - Door Lining Properties - LiningDepth: 60 mm; LiningThickness: 55 mm; TransomThickness: 55 mm; TransomOffset: 2400 mm; LiningOffset: -145 mm
Type - Door Panel Properties - Panel 1 - PanelDepth: 40 mm; PanelOperation: SWINGING; PanelWidth: 1; PanelPosition: MIDDLE
OverallHeight: 3060 mm; OverallWidth: 800 mm; Classification: 1.10 IfcDoorStyle (uks) (BIM ÜBN + Archicad Classification)
Pset_DoorCommon - Reference: SUK-04; ThermalTransmittance: 0; GlazingAreaFraction: 2.03955; IsExternal: no
AR_Uks - 001_Nimetus: Pesa klaasuks; 300_Tähis: SUK-04; 310_Materjal: MUDELIS: väljast-Avatäide: leht värv antrasiit RAL7016; Klaas - kirgas; seest-Avatäide: raam värv antrasiit RAL7016; Klaas - kirgas; MÄRKUS: Metall/klaas; 315_Avanemine: Parem ; ARCHICAD tüüp: Side Hung; 320_Klaas: ootel; 325_Helipidavus: R’w ≥ 35 dB; 330_Tulepüsivus: nõudeid ei esitata; 335_Välispiire: no; 340_Soojusläbivus: 0; 350_Klaaspakett: Kahekordne klaaspakett, vaheliistude toon: must, lamineering; 355_Pindala: 2.448 m2; 360_Ratastooliga: no; 365_Isesulguv: no; 370_Evakuatsiooniväljapääs: no; 375_Viimistlus-seest: MUDELIS: Avatäide: raam värv antrasiit RAL7016; Klaas - kirgas; MÄRKUS: Matt must RAL9005; 376_Viimistlus-väljast: MUDELIS: Avatäide: leht värv antrasiit RAL7016; Klaas - kirgas; MÄRKUS: Matt must RAL9005; 380_Lukustus: Sarjastatud; 900_Tootja: Structo; 905_Mudel: PORTA– 53WS; 910_Tooteinfo: ootel; 915_Kasutus-ja-hooldusjuhend: ootel; 306_Ava-laius: 800 mm; 307_Ava-kõrgus: 3060 mm; 377_Leng: Tootja standardtoode; 378_Lävepakk: Allalaskuv lävepakk, helikindel.; 379_Käepide: Tootja standard, matt roostevaba; 381_Lukuraam: Standardtoode (EVS-EN 12209), luku viimistlus matt must, ruumi seest avanemine lingist; 382_Südamik: täpsustada TP-staadiumis; 383_Vasturaud: Tootja standard, matt roostevaba.; 384_Sulgur: Peidetud sulgur; 345_Päikesekiirgus-tegur: 0; 336_Sissepääs-hoonesse: no
AR_ÜLD - 009_Märkus: OMA märkus
AC_Pset_RenovationAndPhasing - Renovation Status: New

# IfcDoor: Door with Transom 26 (2)
In: Teine korrus
Type - OperationType: SINGLE_SWING_LEFT; ParameterTakesPrecedence: no; Sizeable: no
Type - Door Lining Properties - LiningThickness: 40 mm; TransomThickness: 40 mm; TransomOffset: 2310 mm
Type - Door Panel Properties - Panel 1 - PanelDepth: 40 mm; PanelOperation: SWINGING; PanelWidth: 1; PanelPosition: MIDDLE
OverallHeight: 3060 mm; OverallWidth: 1000 mm; Classification: 1.10 IfcDoorStyle (uks) (BIM ÜBN + Archicad Classification)
AR_Uks - 001_Nimetus: Siseuks/ ülaframuugiga; 300_Tähis: SU-13; 310_Materjal: MUDELIS: väljast-Avatäide: raam värv antrasiit RAL7016; Avatäide: raam värv antrasiit RAL7016; seest-Avatäide: raam värv antrasiit RAL7016; Avatäide: raam värv antrasiit RAL7016; MÄRKUS: MDF+värv; 315_Avanemine: Parem ; ARCHICAD tüüp: Side Hung; 320_Klaas: ootel; 325_Helipidavus: R’w ≥ 30 dB; 330_Tulepüsivus: nõudeid ei esitata; 335_Välispiire: no; 340_Soojusläbivus: 0; 350_Klaaspakett: -; 355_Pindala: 3.06 m2; 360_Ratastooliga: no; 365_Isesulguv: no; 370_Evakuatsiooniväljapääs: no; 375_Viimistlus-seest: MUDELIS: Avatäide: raam värv antrasiit RAL7016; Avatäide: raam värv antrasiit RAL7016; MÄRKUS: Matt must RAL9005; 376_Viimistlus-väljast: MUDELIS: Avatäide: raam värv antrasiit RAL7016; Avatäide: raam värv antrasiit RAL7016; MÄRKUS: Matt must RAL9005; 380_Lukustus: Sarjastatud; 900_Tootja: Structo; 905_Mudel: Door-S; 910_Tooteinfo: ootel; 915_Kasutus-ja-hooldusjuhend: ootel; 306_Ava-laius: 1000 mm; 307_Ava-kõrgus: 3060 mm; 377_Leng: Tootja standardtoode; 378_Lävepakk: Allalaskuv lävepakk, helikindel.; 379_Käepide: Abloy Forum 4, matt roostevaba; 381_Lukuraam: Standardtoode (EVS-EN 12209), luku viimistlus matt must, ruumi seest avanemine lingist; 382_Südamik: täpsustada TP-staadiumis; 383_Vasturaud: Tootja standard, matt roostevaba.; 384_Sulgur: -; 345_Päikesekiirgus-tegur: 0; 336_Sissepääs-hoonesse: no
Pset_DoorCommon - Reference: SU-13; ThermalTransmittance: 0; IsExternal: no
AR_ÜLD - 009_Märkus: OMA märkus
AC_Pset_RenovationAndPhasing - Renovation Status: New

# IfcDoor: Door with Transom 26, SU-10
In: Teine korrus
Type - OperationType: SINGLE_SWING_LEFT; ParameterTakesPrecedence: no; Sizeable: no
Type - Door Lining Properties - LiningThickness: 40 mm; TransomThickness: 40 mm; TransomOffset: 2400 mm
Type - Door Panel Properties - Panel 1 - PanelDepth: 40 mm; PanelOperation: SWINGING; PanelWidth: 1; PanelPosition: MIDDLE
OverallHeight: 3060 mm; OverallWidth: 800 mm; Classification: 1.10 IfcDoorStyle (uks) (BIM ÜBN + Archicad Classification)
Pset_DoorCommon - Reference: SU-10; ThermalTransmittance: 0; IsExternal: no
AR_Uks - 001_Nimetus: Siirdeõhupaneeliga siseuks; 300_Tähis: SU-10; 310_Materjal: MUDELIS: väljast-Avatäide: raam värv antrasiit RAL7016; Avatäide: raam värv antrasiit RAL7016; seest-Avatäide: raam värv antrasiit RAL7016; Avatäide: raam värv antrasiit RAL7016; MÄRKUS: MDF+värv; 315_Avanemine: Parem ; ARCHICAD tüüp: Side Hung; 320_Klaas: ootel; 325_Helipidavus: R’w ≥ 25 dB; 330_Tulepüsivus: nõudeid ei esitata; 335_Välispiire: no; 340_Soojusläbivus: 0; 350_Klaaspakett: -; 355_Pindala: 2.448 m2; 360_Ratastooliga: no; 365_Isesulguv: no; 370_Evakuatsiooniväljapääs: no; 375_Viimistlus-seest: MUDELIS: Avatäide: raam värv antrasiit RAL7016; Avatäide: raam värv antrasiit RAL7016; MÄRKUS: Matt must RAL9005; 376_Viimistlus-väljast: MUDELIS: Avatäide: raam värv antrasiit RAL7016; Avatäide: raam värv antrasiit RAL7016; MÄRKUS: Matt must RAL9005; 380_Lukustus: Sarjastatud; 900_Tootja: Structo; 905_Mudel: Door-S; 910_Tooteinfo: ootel; 915_Kasutus-ja-hooldusjuhend: ootel; 306_Ava-laius: 800 mm; 307_Ava-kõrgus: 3060 mm; 377_Leng: Tootja standardtoode; 378_Lävepakk: Allalaskuv lävepakk, helikindel.; 379_Käepide: Abloy Forum 4, matt roostevaba; 381_Lukuraam: Standardtoode (EVS-EN 12209), luku viimistlus matt must, ruumi seest avanemine väändenupust.; 382_Südamik: täpsustada TP-staadiumis; 383_Vasturaud: Tootja standard, matt roostevaba.; 384_Sulgur: -; 345_Päikesekiirgus-tegur: 0; 336_Sissepääs-hoonesse: no
AR_ÜLD - 009_Märkus: OMA märkus
AC_Pset_RenovationAndPhasing - Renovation Status: New

# IfcDoor: Door with Transom 26, SU-12
In: Teine korrus
Type - OperationType: SINGLE_SWING_RIGHT; ParameterTakesPrecedence: no; Sizeable: no
Type - Door Lining Properties - LiningDepth: 60 mm; LiningThickness: 40 mm; TransomThickness: 40 mm; TransomOffset: 2400 mm; LiningOffset: -116 mm
Type - Door Panel Properties - Panel 1 - PanelDepth: 40 mm; PanelOperation: SWINGING; PanelWidth: 1; PanelPosition: MIDDLE
OverallHeight: 3060 mm; OverallWidth: 900 mm; Classification: 1.10 IfcDoorStyle (uks) (BIM ÜBN + Archicad Classification)
Pset_DoorCommon - Reference: SU-12; ThermalTransmittance: 0; IsExternal: no
AR_Uks - 001_Nimetus: Ülaframuugiga siseuks; 300_Tähis: SU-12; 310_Materjal: MUDELIS: väljast-Avatäide: raam värv antrasiit RAL7016; Avatäide: raam värv antrasiit RAL7016; seest-Avatäide: raam värv antrasiit RAL7016; Avatäide: raam värv antrasiit RAL7016; MÄRKUS: MDF+värv; 315_Avanemine: Vasak ; ARCHICAD tüüp: Side Hung; 320_Klaas: ootel; 325_Helipidavus: R’w ≥ 30 dB; 330_Tulepüsivus: nõudeid ei esitata; 335_Välispiire: no; 340_Soojusläbivus: 0; 350_Klaaspakett: -; 355_Pindala: 2.754 m2; 360_Ratastooliga: no; 365_Isesulguv: no; 370_Evakuatsiooniväljapääs: no; 375_Viimistlus-seest: MUDELIS: Avatäide: raam värv antrasiit RAL7016; Avatäide: raam värv antrasiit RAL7016; MÄRKUS: Matt must RAL9005; 376_Viimistlus-väljast: MUDELIS: Avatäide: raam värv antrasiit RAL7016; Avatäide: raam värv antrasiit RAL7016; MÄRKUS: Matt must RAL9005; 380_Lukustus: Sarjastatud; 900_Tootja: Structo; 905_Mudel: Door-S; 910_Tooteinfo: ootel; 915_Kasutus-ja-hooldusjuhend: ootel; 306_Ava-laius: 900 mm; 307_Ava-kõrgus: 3060 mm; 377_Leng: Pikendatud leng, viimistletud analooglselt ukselehega, peideud hinged, piirdeliistuta lahendus, vuuk täidetakse seinatoon mastiksiga, teha näidis.; 378_Lävepakk: Allalaskuv lävepakk, helikindel.; 379_Käepide: Abloy Forum 4, matt roostevaba; 381_Lukuraam: Standardtoode (EVS-EN 12209), luku viimistlus matt must, ruumi seest avanemine väändenupust.; 382_Südamik: täpsustada TP-staadiumis; 383_Vasturaud: Tootja standard, matt roostevaba.; 384_Sulgur: -; 345_Päikesekiirgus-tegur: 0; 336_Sissepääs-hoonesse: no
AC_Pset_RenovationAndPhasing - Renovation Status: New
AR_ÜLD - 009_Märkus: OMA märkus

# IfcDoor: Door with Transom 26, SU-11
In: Teine korrus
Type - OperationType: SINGLE_SWING_RIGHT; ParameterTakesPrecedence: no; Sizeable: no
Type - Door Lining Properties - LiningDepth: 60 mm; LiningThickness: 40 mm; TransomThickness: 40 mm; TransomOffset: 2400 mm; LiningOffset: -126 mm
Type - Door Panel Properties - Panel 1 - PanelDepth: 40 mm; PanelOperation: SWINGING; PanelWidth: 1; PanelPosition: MIDDLE
OverallHeight: 3060 mm; OverallWidth: 800 mm; Classification: 1.10 IfcDoorStyle (uks) (BIM ÜBN + Archicad Classification)
Pset_DoorCommon - Reference: SU-11; ThermalTransmittance: 0; IsExternal: no
AR_ÜLD - 009_Märkus: OMA märkus
AC_Pset_RenovationAndPhasing - Renovation Status: New
AR_Uks - 001_Nimetus: Siirdeõhupaneeliga siseuks; 300_Tähis: SU-11; 310_Materjal: MUDELIS: väljast-Avatäide: raam värv antrasiit RAL7016; Avatäide: raam värv antrasiit RAL7016; seest-Avatäide: raam värv antrasiit RAL7016; Avatäide: raam värv antrasiit RAL7016; MÄRKUS: MDF+värv; 315_Avanemine: Vasak ; ARCHICAD tüüp: Side Hung; 320_Klaas: ootel; 325_Helipidavus: R’w ≥ 30 dB; 330_Tulepüsivus: nõudeid ei esitata; 335_Välispiire: no; 340_Soojusläbivus: 0; 350_Klaaspakett: -; 355_Pindala: 2.448 m2; 360_Ratastooliga: no; 365_Isesulguv: no; 370_Evakuatsiooniväljapääs: no; 375_Viimistlus-seest: MUDELIS: Avatäide: raam värv antrasiit RAL7016; Avatäide: raam värv antrasiit RAL7016; MÄRKUS: Matt must RAL9005; 376_Viimistlus-väljast: MUDELIS: Avatäide: raam värv antrasiit RAL7016; Avatäide: raam värv antrasiit RAL7016; MÄRKUS: Matt must RAL9005; 380_Lukustus: Sarjastatud; 900_Tootja: Structo; 905_Mudel: Door-S; 910_Tooteinfo: ootel; 915_Kasutus-ja-hooldusjuhend: ootel; 306_Ava-laius: 800 mm; 307_Ava-kõrgus: 3060 mm; 377_Leng: Pikendatud leng, viimistletud analooglselt ukselehega, peideud hinged, piirdeliistuta lahendus, vuuk täidetakse seinatoon mastiksiga, teha näidis.; 378_Lävepakk: Allalaskuv lävepakk, helikindel.; 379_Käepide: Abloy Forum 4, matt roostevaba; 381_Lukuraam: Standardtoode (EVS-EN 12209), luku viimistlus matt must, ruumi seest avanemine lingist; 382_Südamik: täpsustada TP-staadiumis; 383_Vasturaud: Tootja standard, matt roostevaba.; 384_Sulgur: -; 345_Päikesekiirgus-tegur: 0; 336_Sissepääs-hoonesse: no

# IfcDoor: Door with Transom 26 (2)
In: Teine korrus
Type - OperationType: SINGLE_SWING_RIGHT; ParameterTakesPrecedence: no; Sizeable: no
Type - Door Lining Properties - LiningDepth: 60 mm; LiningThickness: 55 mm; TransomThickness: 55 mm; TransomOffset: 2400 mm; LiningOffset: -145 mm
Type - Door Panel Properties - Panel 1 - PanelDepth: 40 mm; PanelOperation: SWINGING; PanelWidth: 1; PanelPosition: MIDDLE
OverallHeight: 3060 mm; OverallWidth: 800 mm; Classification: 1.10 IfcDoorStyle (uks) (BIM ÜBN + Archicad Classification)
Pset_DoorCommon - Reference: SUK-05; ThermalTransmittance: 0; GlazingAreaFraction: 2.03955; IsExternal: no
AR_Uks - 001_Nimetus: Pesa klaasuks; 300_Tähis: SUK-05; 310_Materjal: MUDELIS: väljast-Avatäide: leht värv antrasiit RAL7016; Klaas - kirgas; seest-Avatäide: raam värv antrasiit RAL7016; Klaas - kirgas; MÄRKUS: Metall/klaas; 315_Avanemine: Vasak ; ARCHICAD tüüp: Side Hung; 320_Klaas: ootel; 325_Helipidavus: R’w ≥ 35 dB; 330_Tulepüsivus: nõudeid ei esitata; 335_Välispiire: no; 340_Soojusläbivus: 0; 350_Klaaspakett: Kahekordne klaaspakett, vaheliistude toon: must, lamineering; 355_Pindala: 2.448 m2; 360_Ratastooliga: no; 365_Isesulguv: no; 370_Evakuatsiooniväljapääs: no; 375_Viimistlus-seest: MUDELIS: Avatäide: raam värv antrasiit RAL7016; Klaas - kirgas; MÄRKUS: Matt must RAL9005; 376_Viimistlus-väljast: MUDELIS: Avatäide: leht värv antrasiit RAL7016; Klaas - kirgas; MÄRKUS: Matt must RAL9005; 380_Lukustus: Sarjastatud; 900_Tootja: Structo; 905_Mudel: PORTA– 53WS; 910_Tooteinfo: ootel; 915_Kasutus-ja-hooldusjuhend: ootel; 306_Ava-laius: 800 mm; 307_Ava-kõrgus: 3060 mm; 377_Leng: Tootja standardtoode; 378_Lävepakk: Allalaskuv lävepakk, helikindel.; 379_Käepide: Tootja standard, matt roostevaba; 381_Lukuraam: Standardtoode (EVS-EN 12209), luku viimistlus matt must, ruumi seest avanemine lingist; 382_Südamik: täpsustada TP-staadiumis; 383_Vasturaud: Tootja standard, matt roostevaba.; 384_Sulgur: Peidetud sulgur; 345_Päikesekiirgus-tegur: 0; 336_Sissepääs-hoonesse: no
AR_ÜLD - 009_Märkus: OMA märkus
AC_Pset_RenovationAndPhasing - Renovation Status: New

# IfcDoor: Door with Transom 26 (6)
In: Teine korrus
Type - OperationType: SINGLE_SWING_RIGHT; ParameterTakesPrecedence: no; Sizeable: no
Type - Door Lining Properties - LiningThickness: 40 mm; TransomThickness: 40 mm; TransomOffset: 2400 mm
Type - Door Panel Properties - Panel 1 - PanelDepth: 40 mm; PanelOperation: SWINGING; PanelWidth: 1; PanelPosition: MIDDLE
OverallHeight: 3060 mm; Classification: 1.10 IfcDoorStyle (uks) (BIM ÜBN + Archicad Classification)
Pset_DoorCommon - ThermalTransmittance: 0; IsExternal: no
AR_ÜLD - 009_Märkus: OMA märkus
AR_Uks - 320_Klaas: ootel; 335_Välispiire: no; 340_Soojusläbivus: 0; 360_Ratastooliga: no; 365_Isesulguv: no; 370_Evakuatsiooniväljapääs: no; 375_Viimistlus-seest: MUDELIS: Avatäide: raam värv antrasiit RAL7016; Avatäide: raam värv antrasiit RAL7016; MÄRKUS: Matt must RAL9005; 376_Viimistlus-väljast: MUDELIS: Avatäide: raam värv antrasiit RAL7016; Avatäide: raam värv antrasiit RAL7016; MÄRKUS: Matt must RAL9005; 380_Lukustus: Sarjastatud; 910_Tooteinfo: ootel; 915_Kasutus-ja-hooldusjuhend: ootel; 307_Ava-kõrgus: 3060 mm; 378_Lävepakk: Allalaskuv lävepakk, helikindel.; 379_Käepide: Abloy Forum 4, matt roostevaba; 382_Südamik: täpsustada TP-staadiumis; 383_Vasturaud: Tootja standard, matt roostevaba.; 384_Sulgur: -; 345_Päikesekiirgus-tegur: 0; 336_Sissepääs-hoonesse: no
AC_Pset_RenovationAndPhasing - Renovation Status: New
Name | OverallWidth (mm) = 306_Ava-laius (mm) | Reference = 300_Tähis | GlazingAreaFraction | 001_Nimetus | 310_Materjal | 315_Avanemine | 325_Helipidavus | 330_Tulepüsivus | 350_Klaaspakett | 355_Pindala (m2) | 900_Tootja | 905_Mudel | 377_Leng | 381_Lukuraam
SUK-11 | 900 | SUK-11 | 0.4756 | Ülaframuugiga siseuks | MUDELIS: väljast-Avatäide: raam värv antrasiit RAL7016; Avatäide: raam värv antrasiit RAL7016; seest-Avatäide: raam värv antrasiit RAL7016; Avatäide: raam värv antrasiit RAL7016; MÄRKUS: MDF+värv | Vasak ; ARCHICAD tüüp: Side Hung | R’w ≥ 30dB | nõudeid ei esitata | - | 2.754 | Structo | PORTA– 53WS | Tootja standardtoode | Standardtoode (EVS-EN 12209), luku viimistlus matt must, ruumi seest avanemine lingist
2 x SUK-16 | 1000 | SUK-16 | 2.1176 | Siseuks/ ülaframuugiga | MUDELIS: väljast-Avatäide: raam värv antrasiit RAL7016; Avatäide: raam värv antrasiit RAL7016; seest-Avatäide: raam värv antrasiit RAL7016; Avatäide: raam värv antrasiit RAL7016; MÄRKUS: metall/klaas | -Vasak ; ARCHICAD tüüp: Side Hung | R’w ≥ 30dB | nõudeid ei esitata | Kahekordne klaaspakett, vaheliistude toon: must, lamineering | 3.06 | Saku metall | PIC021 | Tootja standardtoode | Standardtoode (EVS-EN 12209), luku viimistlus matt must, ruumi seest avanemine lingist
SUK-16 | 1000 | SUK-16 | 2.1176 | Siseuks/ ülaframuugiga | MUDELIS: väljast-Avatäide: raam värv antrasiit RAL7016; Avatäide: raam värv antrasiit RAL7016; seest-Avatäide: raam värv antrasiit RAL7016; Avatäide: raam värv antrasiit RAL7016; MÄRKUS: metall/klaas | -Vasak ; ARCHICAD tüüp: Side Hung | R’w ≥ 40 dB | nõudeid ei esitata | Kahekordne klaaspakett, vaheliistude toon: must, lamineering | 3.06 | Saku metall | PIC021 | Tootja standardtoode | Standardtoode (EVS-EN 12209), luku viimistlus matt must, ruumi seest avanemine lingist
SU-11 | 800 | SU-11 |  | Siirdeõhupaneeliga siseuks | MUDELIS: väljast-Avatäide: raam värv antrasiit RAL7016; Avatäide: raam värv antrasiit RAL7016; seest-Avatäide: raam värv antrasiit RAL7016; Avatäide: raam värv antrasiit RAL7016; MÄRKUS: MDF+värv | Vasak ; ARCHICAD tüüp: Side Hung | R’w ≥ 25 dB | nõudeid ei esitata | - | 2.448 | Structo | Door-S | Pikendatud leng, viimistletud analooglselt ukselehega, peideud hinged, piirdeliistuta lahendus, vuuk täidetakse seinatoon mastiksiga, teha näidis. | Standardtoode (EVS-EN 12209), luku viimistlus matt must, ruumi seest avanemine lingist
SUT-12 | 1000 | SUT-12 | 2.1176 | Siseuks/ ülaframuugiga EI30 | MUDELIS: väljast-Avatäide: raam värv antrasiit RAL7016; Avatäide: raam värv antrasiit RAL7016; seest-Avatäide: raam värv antrasiit RAL7016; Avatäide: raam värv antrasiit RAL7016; MÄRKUS: metall/klaas | -Vasak ; ARCHICAD tüüp: Side Hung | R’w ≥ 25 dB | EI30 Sa | - | 3.06 | Saku metall | PFC011 | Tootja standardtoode | Standardtoode (EVS-EN 12209), luku viimistlus matt must, ruumi seest avanemine väändenupust.

# IfcDoor: Double Door 26, VU-04d
In: Teine korrus
Type - OperationType: DOUBLE_DOOR_SINGLE_SWING; ParameterTakesPrecedence: no; Sizeable: no
Type - Door Lining Properties - LiningDepth: 180 mm; LiningThickness: 45 mm; LiningOffset: 220 mm
Type - Door Panel Properties - Panel 1 - PanelDepth: 80 mm; PanelOperation: SWINGING; PanelWidth: 0.5; PanelPosition: LEFT
Type - Door Panel Properties - Panel 2 - PanelDepth: 80 mm; PanelOperation: SWINGING; PanelWidth: 0.5; PanelPosition: RIGHT
OverallHeight: 2479.91 mm; OverallWidth: 2250 mm; Classification: 1.10 IfcDoorStyle (uks) (BIM ÜBN + Archicad Classification)
Pset_DoorCommon - Reference: VU-04d; ThermalTransmittance: 0; GlazingAreaFraction: 3.53044; IsExternal: yes
AR_Uks - 001_Nimetus: Alumiiniumraamil välisuks KF süsteemis; 300_Tähis: VU-04d; 310_Materjal: MUDELIS: väljast-Avatäide: raam värv antrasiit RAL7016; Avatäide: raam värv antrasiit RAL7016; seest-Avatäide: raam värv antrasiit RAL7016; Avatäide: raam värv antrasiit RAL7016; MÄRKUS: Alumiinium; 315_Avanemine: Pöördavatav rullhingedel ukselehtVasak ; ARCHICAD tüüp: Side Hung; 320_Klaas: Kolmekordne klaaspakett, argoongaasiga, vaheliistud mustad, välimine: päikesekaitseklaas Cool-Lite SKN 183 II, LT=66%, karastatud klaas, klaasitoon: kirgas, keskmine: Planiclear, klaasitoon: kirgas, sisemine: Planitherm XN, lamineeritud floatklaas, klaasitoon: kirgas; 325_Helipidavus: R’tr,s,w = 30 dB; 330_Tulepüsivus: nõudeid ei esitata; 335_Välispiire: yes; 340_Soojusläbivus: 0; 350_Klaaspakett: 3k6SecSKN183II+4+44.1PlthXN-18Ar/18Ar (vaheliistude toon: must), Ug=0,5 W/(m2K); 355_Pindala: 5.57979 m2; 360_Ratastooliga: no; 365_Isesulguv: no; 370_Evakuatsiooniväljapääs: yes; 375_Viimistlus-seest: MUDELIS: Avatäide: raam värv antrasiit RAL7016; Avatäide: raam värv antrasiit RAL7016; MÄRKUS: Matt antrasiit RAL7016; 376_Viimistlus-väljast: MUDELIS: Avatäide: raam värv antrasiit RAL7016; Avatäide: raam värv antrasiit RAL7016; MÄRKUS: Matt antrasiit RAL7016; 380_Lukustus: Kolmepunkti lukustussüsteem, täpsustada TP-staadiumis; 900_Tootja: ootel; 905_Mudel: ootel; 910_Tooteinfo: ootel; 915_Kasutus-ja-hooldusjuhend: ootel; 306_Ava-laius: 2250 mm; 307_Ava-kõrgus: 2479.91 mm; 377_Leng: AD UP 90; 378_Lävepakk: tootja standardtoode; 379_Käepide: tootja standard, viimistlus: roostevaba; 381_Lukuraam: täpsustada TP-staadiumis; 382_Südamik: täpsustada TP-staadiumis; 383_Vasturaud: täpsustada TP-staadiumis; 384_Sulgur: tootja standardtoode; 345_Päikesekiirgus-tegur: 0; 336_Sissepääs-hoonesse: yes
AC_Pset_RenovationAndPhasing - Renovation Status: New

# IfcDoor: Double Door 26, VU-04c
In: Teine korrus
Type - OperationType: DOUBLE_DOOR_SINGLE_SWING; ParameterTakesPrecedence: no; Sizeable: no
Type - Door Lining Properties - LiningDepth: 180 mm; LiningThickness: 45 mm; LiningOffset: 220 mm
Type - Door Panel Properties - Panel 1 - PanelDepth: 80 mm; PanelOperation: SWINGING; PanelWidth: 0.5; PanelPosition: RIGHT
Type - Door Panel Properties - Panel 2 - PanelDepth: 80 mm; PanelOperation: SWINGING; PanelWidth: 0.5; PanelPosition: LEFT
OverallHeight: 2479.91 mm; OverallWidth: 2250 mm; Classification: 1.10 IfcDoorStyle (uks) (BIM ÜBN + Archicad Classification)
Pset_DoorCommon - Reference: VU-04c; ThermalTransmittance: 0; GlazingAreaFraction: 3.53044; IsExternal: yes
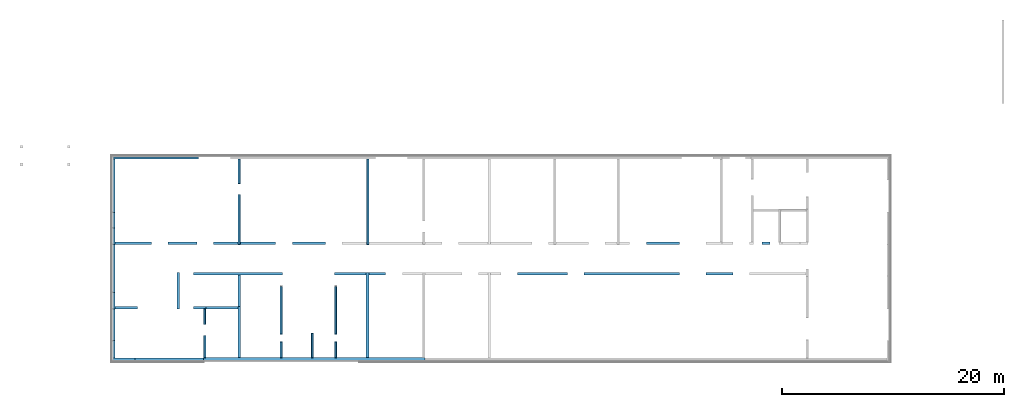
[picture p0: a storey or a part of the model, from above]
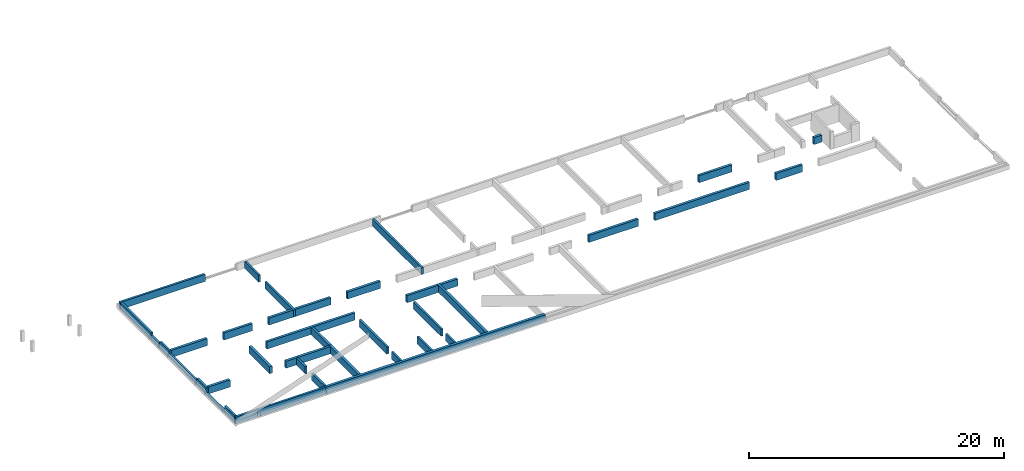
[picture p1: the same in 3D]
Properties of the parts of a building model (IFC2X3), part 5 of 8

# IfcDoor: Double Door 26, VU-04c
AR_Uks - 001_Nimetus: Alumiiniumraamil välisuks KF süsteemis; 300_Tähis: VU-04c; 310_Materjal: MUDELIS: väljast-Avatäide: raam värv antrasiit RAL7016; Avatäide: raam värv antrasiit RAL7016; seest-Avatäide: raam värv antrasiit RAL7016; Avatäide: raam värv antrasiit RAL7016; MÄRKUS: Alumiinium; 315_Avanemine: Pöördavatav rullhingedel ukselehtParem ; ARCHICAD tüüp: Side Hung; 320_Klaas: Kolmekordne klaaspakett, argoongaasiga, vaheliistud mustad, välimine: päikesekaitseklaas Cool-Lite SKN 183 II, LT=66%, karastatud klaas, klaasitoon: kirgas, keskmine: Planiclear, klaasitoon: kirgas, sisemine: Planitherm XN, lamineeritud floatklaas, klaasitoon: kirgas; 325_Helipidavus: R’tr,s,w = 30 dB; 330_Tulepüsivus: nõudeid ei esitata; 335_Välispiire: yes; 340_Soojusläbivus: 0; 350_Klaaspakett: 3k6SecSKN183II+4+44.1PlthXN-18Ar/18Ar (vaheliistude toon: must), Ug=0,5 W/(m2K); 355_Pindala: 5.57979 m2; 360_Ratastooliga: no; 365_Isesulguv: no; 370_Evakuatsiooniväljapääs: yes; 375_Viimistlus-seest: MUDELIS: Avatäide: raam värv antrasiit RAL7016; Avatäide: raam värv antrasiit RAL7016; MÄRKUS: Matt antrasiit RAL7016; 376_Viimistlus-väljast: MUDELIS: Avatäide: raam värv antrasiit RAL7016; Avatäide: raam värv antrasiit RAL7016; MÄRKUS: Matt antrasiit RAL7016; 380_Lukustus: Kolmepunkti lukustussüsteem, täpsustada TP-staadiumis; 900_Tootja: ootel; 905_Mudel: ootel; 910_Tooteinfo: ootel; 915_Kasutus-ja-hooldusjuhend: ootel; 306_Ava-laius: 2250 mm; 307_Ava-kõrgus: 2479.91 mm; 377_Leng: AD UP 90; 378_Lävepakk: tootja standardtoode; 379_Käepide: tootja standard, viimistlus: roostevaba; 381_Lukuraam: täpsustada TP-staadiumis; 382_Südamik: täpsustada TP-staadiumis; 383_Vasturaud: täpsustada TP-staadiumis; 384_Sulgur: tootja standardtoode; 345_Päikesekiirgus-tegur: 0; 336_Sissepääs-hoonesse: yes
AC_Pset_RenovationAndPhasing - Renovation Status: New

# IfcDoor: Double Door 26, VU-02
In: Esimene korrus
Type - OperationType: DOUBLE_DOOR_SINGLE_SWING; ParameterTakesPrecedence: no; Sizeable: no
Type - Door Lining Properties - LiningDepth: 90 mm; LiningThickness: 74 mm; LiningOffset: 200 mm
Type - Door Panel Properties - Panel 1 - PanelDepth: 90 mm; PanelOperation: SWINGING; PanelWidth: 0.275362; PanelPosition: LEFT
Type - Door Panel Properties - Panel 2 - PanelDepth: 90 mm; PanelOperation: SWINGING; PanelWidth: 0.724638; PanelPosition: RIGHT
OverallHeight: 2210 mm; OverallWidth: 1410 mm; Classification: 1.10 IfcDoorStyle (uks) (BIM ÜBN + Archicad Classification)
Pset_DoorCommon - Reference: VU-02; ThermalTransmittance: 0; GlazingAreaFraction: 1.62169; IsExternal: yes
AR_Uks - 001_Nimetus: Alumiiniumraamil välisuks; 300_Tähis: VU-02; 310_Materjal: MUDELIS: väljast-Avatäide: raam värv antrasiit RAL7016; Avatäide: raam värv antrasiit RAL7016; seest-Avatäide: raam värv antrasiit RAL7016; Avatäide: raam värv antrasiit RAL7016; MÄRKUS: Alumiinium; 315_Avanemine: Pöördavatav rullhingedel ukselehed, parempool aktiivneVasak ; ARCHICAD tüüp: Side Hung; 320_Klaas: Kolmekordne klaaspakett, argoongaasiga, vaheliistud mustad, välimine: päikesekaitseklaas Cool-Lite SKN 183 II, LT=66%, karastatud klaas, klaasitoon: kirgas, keskmine: Planiclear, klaasitoon: kirgas, sisemine: Planitherm XN, lamineeritud floatklaas, klaasitoon: kirgas; 325_Helipidavus: R’tr,s,w = 30 dB; 330_Tulepüsivus: nõudeid ei esitata; 335_Välispiire: yes; 340_Soojusläbivus: 0; 350_Klaaspakett: 3k6SecSKN183II+4+44.1PlthXN-18Ar/18Ar (vaheliistude toon: must), Ug=0,5 W/(m2K); 355_Pindala: 3.1161 m2; 360_Ratastooliga: no; 365_Isesulguv: no; 370_Evakuatsiooniväljapääs: yes; 375_Viimistlus-seest: MUDELIS: Avatäide: raam värv antrasiit RAL7016; Avatäide: raam värv antrasiit RAL7016; MÄRKUS: Matt antrasiit RAL7016; 376_Viimistlus-väljast: MUDELIS: Avatäide: raam värv antrasiit RAL7016; Avatäide: raam värv antrasiit RAL7016; MÄRKUS: Matt antrasiit RAL7016; 380_Lukustus: Kolmepunkti lukustussüsteem, täpsustada TP-staadiumis; 900_Tootja: ootel; 905_Mudel: ootel; 910_Tooteinfo: ootel; 915_Kasutus-ja-hooldusjuhend: ootel; 306_Ava-laius: 1410 mm; 307_Ava-kõrgus: 2210 mm; 377_Leng: AD UP 90; 378_Lävepakk: tootja standardtoode; 379_Käepide: tootja standard, viimistlus: roostevaba; 381_Lukuraam: täpsustada TP-staadiumis; 382_Südamik: täpsustada TP-staadiumis; 383_Vasturaud: täpsustada TP-staadiumis; 384_Sulgur: tootja standardtoode; 345_Päikesekiirgus-tegur: 0; 336_Sissepääs-hoonesse: yes
AC_Pset_RenovationAndPhasing - Renovation Status: New

# IfcDoor: Double Door 26, SUT-10
In: Esimene korrus
Type - OperationType: DOUBLE_DOOR_SINGLE_SWING; ParameterTakesPrecedence: no; Sizeable: no
Type - Door Lining Properties - LiningThickness: 40 mm
Type - Door Panel Properties - Panel 1 - PanelDepth: 40 mm; PanelOperation: SWINGING; PanelWidth: 0.295775; PanelPosition: LEFT
Type - Door Panel Properties - Panel 2 - PanelDepth: 40 mm; PanelOperation: SWINGING; PanelWidth: 0.704225; PanelPosition: RIGHT
OverallHeight: 2200 mm; OverallWidth: 1500 mm; Classification: 1.10 IfcDoorStyle (uks) (BIM ÜBN + Archicad Classification)
Pset_DoorCommon - Reference: SUT-10; ThermalTransmittance: 0; GlazingAreaFraction: 1.9992; IsExternal: no
AR_ÜLD - 009_Märkus: OMA märkus
AC_Pset_RenovationAndPhasing - Renovation Status: New
AR_Uks - 001_Nimetus: Kahepoolne siseuks EI30; 300_Tähis: SUT-10; 310_Materjal: MUDELIS: väljast-Avatäide: raam värv antrasiit RAL7016; Avatäide: raam värv antrasiit RAL7016; seest-Avatäide: raam värv antrasiit RAL7016; Avatäide: raam värv antrasiit RAL7016; MÄRKUS: metall/klaas; 315_Avanemine: -Vasak ; ARCHICAD tüüp: Side Hung; 320_Klaas: ootel; 325_Helipidavus: R’w ≥ 30dB; 330_Tulepüsivus: EI30 S200; 335_Välispiire: no; 340_Soojusläbivus: 0; 350_Klaaspakett: Kahekordne klaaspakett, vaheliistude toon: must, lamineering; 355_Pindala: 3.3 m2; 360_Ratastooliga: no; 365_Isesulguv: no; 370_Evakuatsiooniväljapääs: no; 375_Viimistlus-seest: MUDELIS: Avatäide: raam värv antrasiit RAL7016; Avatäide: raam värv antrasiit RAL7016; MÄRKUS: Matt must RAL9005; 376_Viimistlus-väljast: MUDELIS: Avatäide: raam värv antrasiit RAL7016; Avatäide: raam värv antrasiit RAL7016; MÄRKUS: Matt must RAL9005; 380_Lukustus: Sarjastatud; 900_Tootja: Saku metall; 905_Mudel: PFC011; 910_Tooteinfo: ootel; 915_Kasutus-ja-hooldusjuhend: ootel; 306_Ava-laius: 1500 mm; 307_Ava-kõrgus: 2200 mm; 377_Leng: Tootja standardtoode; 378_Lävepakk: Allalaskuv lävepakk, helikindel.; 379_Käepide: Abloy Forum 4, matt roostevaba; 381_Lukuraam: Standardtoode (EVS-EN 12209), luku viimistlus matt must, ruumi seest avanemine lingist; 382_Südamik: täpsustada TP-staadiumis; 383_Vasturaud: Tootja standard, matt roostevaba.; 384_Sulgur: -; 345_Päikesekiirgus-tegur: 0; 336_Sissepääs-hoonesse: no

# IfcDoor: Double Door 26, SUT-11
In: Esimene korrus
Type - OperationType: DOUBLE_DOOR_SINGLE_SWING; ParameterTakesPrecedence: no; Sizeable: no
Type - Door Lining Properties - LiningThickness: 40 mm
Type - Door Panel Properties - Panel 1 - PanelDepth: 40 mm; PanelOperation: SWINGING; PanelWidth: 0.295775; PanelPosition: RIGHT
Type - Door Panel Properties - Panel 2 - PanelDepth: 40 mm; PanelOperation: SWINGING; PanelWidth: 0.704225; PanelPosition: LEFT
OverallHeight: 2190 mm; OverallWidth: 1500 mm; Classification: 1.10 IfcDoorStyle (uks) (BIM ÜBN + Archicad Classification)
AR_Uks - 001_Nimetus: Kahepoolne siseuks EI30; 300_Tähis: SUT-11; 310_Materjal: MUDELIS: väljast-Avatäide: raam värv antrasiit RAL7016; Avatäide: raam värv antrasiit RAL7016; seest-Avatäide: raam värv antrasiit RAL7016; Avatäide: raam värv antrasiit RAL7016; MÄRKUS: metall/klaas; 315_Avanemine: -Parem ; ARCHICAD tüüp: Side Hung; 320_Klaas: ootel; 325_Helipidavus: R’w ≥ 30 dB; 330_Tulepüsivus: EI30 S200; 335_Välispiire: no; 340_Soojusläbivus: 0; 350_Klaaspakett: Kahekordne klaaspakett, vaheliistude toon: must, lamineering; 355_Pindala: 3.285 m2; 360_Ratastooliga: no; 365_Isesulguv: no; 370_Evakuatsiooniväljapääs: no; 375_Viimistlus-seest: MUDELIS: Avatäide: raam värv antrasiit RAL7016; Avatäide: raam värv antrasiit RAL7016; MÄRKUS: Matt must RAL9005; 376_Viimistlus-väljast: MUDELIS: Avatäide: raam värv antrasiit RAL7016; Avatäide: raam värv antrasiit RAL7016; MÄRKUS: Matt must RAL9005; 380_Lukustus: Sarjastatud; 900_Tootja: Saku metall; 905_Mudel: PFC011; 910_Tooteinfo: ootel; 915_Kasutus-ja-hooldusjuhend: ootel; 306_Ava-laius: 1500 mm; 307_Ava-kõrgus: 2190 mm; 377_Leng: Tootja standardtoode; 378_Lävepakk: Allalaskuv lävepakk, helikindel.; 379_Käepide: Abloy Forum 4, matt roostevaba; 381_Lukuraam: Standardtoode (EVS-EN 12209), luku viimistlus matt must, ruumi seest avanemine lingist; 382_Südamik: täpsustada TP-staadiumis; 383_Vasturaud: Tootja standard, matt roostevaba.; 384_Sulgur: -; 345_Päikesekiirgus-tegur: 0; 336_Sissepääs-hoonesse: no
Pset_DoorCommon - Reference: SUT-11; ThermalTransmittance: 0; GlazingAreaFraction: 1.989; IsExternal: no
AC_Pset_RenovationAndPhasing - Renovation Status: New
AR_ÜLD - 009_Märkus: OMA märkus

# IfcDoor: Double Door 26 (3)
In: Esimene korrus
Type - OperationType: DOUBLE_DOOR_SINGLE_SWING; ParameterTakesPrecedence: no; Sizeable: no
Type - Door Lining Properties - LiningThickness: 40 mm
Type - Door Panel Properties - Panel 1 - PanelDepth: 40 mm; PanelOperation: SWINGING; PanelWidth: 0.5; PanelPosition: LEFT
Type - Door Panel Properties - Panel 2 - PanelDepth: 40 mm; PanelOperation: SWINGING; PanelWidth: 0.5; PanelPosition: RIGHT
Classification: 1.10 IfcDoorStyle (uks) (BIM ÜBN + Archicad Classification)
Pset_DoorCommon - ThermalTransmittance: 0; IsExternal: no
AR_Uks - 310_Materjal: MUDELIS: väljast-Avatäide: raam värv antrasiit RAL7016; Avatäide: raam värv antrasiit RAL7016; seest-Avatäide: raam värv antrasiit RAL7016; Avatäide: raam värv antrasiit RAL7016; MÄRKUS: metall; 315_Avanemine: -Vasak ; ARCHICAD tüüp: Side Hung; 320_Klaas: ootel; 330_Tulepüsivus: EI30 Sa; 335_Välispiire: no; 340_Soojusläbivus: 0; 350_Klaaspakett: -; 360_Ratastooliga: no; 365_Isesulguv: no; 370_Evakuatsiooniväljapääs: no; 375_Viimistlus-seest: MUDELIS: Avatäide: raam värv antrasiit RAL7016; Avatäide: raam värv antrasiit RAL7016; MÄRKUS: Matt must RAL9005; 376_Viimistlus-väljast: MUDELIS: Avatäide: raam värv antrasiit RAL7016; Avatäide: raam värv antrasiit RAL7016; MÄRKUS: Matt must RAL9005; 380_Lukustus: Sarjastatud; 900_Tootja: Saku metall; 905_Mudel: MFD131; 910_Tooteinfo: ootel; 915_Kasutus-ja-hooldusjuhend: ootel; 377_Leng: Tootja standardtoode; 378_Lävepakk: Allalaskuv lävepakk, helikindel.; 381_Lukuraam: Standardtoode (EVS-EN 12209), luku viimistlus matt must, ruumi seest avanemine lingist; 382_Südamik: täpsustada TP-staadiumis; 383_Vasturaud: Tootja standard, matt roostevaba.; 384_Sulgur: -; 345_Päikesekiirgus-tegur: 0; 336_Sissepääs-hoonesse: no
AR_ÜLD - 009_Märkus: OMA märkus
AC_Pset_RenovationAndPhasing - Renovation Status: New
Name | OverallHeight (mm) = 307_Ava-kõrgus (mm) | OverallWidth (mm) = 306_Ava-laius (mm) | Reference = 300_Tähis | 001_Nimetus | 325_Helipidavus | 355_Pindala (m2) | 379_Käepide
SUT-04 | 2200 | 2520 | SUT-04 | Kahepoolne siseuks 30 | R’w ≥ 25 dB | 5.544 | Abloy Forum 4, matt roostevaba
SUT-06 | 2200 | 2200 | SUT-06 | Kahepoolne siseuks | R’w ≥ 40 dB | 4.84 | Abloy Forum 4, exit matt roostevaba
SUT-06 | 2190 | 2200 | SUT-06 | Kahepoolne siseuks | R’w ≥ 35 dB | 4.818 | Abloy Forum 4, exit matt roostevaba

# IfcDoor: Double Door 26, SUT-05
In: Esimene korrus
Type - OperationType: DOUBLE_DOOR_SINGLE_SWING; ParameterTakesPrecedence: no; Sizeable: no
Type - Door Lining Properties - LiningThickness: 40 mm
Type - Door Panel Properties - Panel 1 - PanelDepth: 40 mm; PanelOperation: SWINGING; PanelWidth: 0.5; PanelPosition: RIGHT
Type - Door Panel Properties - Panel 2 - PanelDepth: 40 mm; PanelOperation: SWINGING; PanelWidth: 0.5; PanelPosition: LEFT
OverallHeight: 2190 mm; OverallWidth: 2000 mm; Classification: 1.10 IfcDoorStyle (uks) (BIM ÜBN + Archicad Classification)
Pset_DoorCommon - Reference: SUT-05; ThermalTransmittance: 0; IsExternal: no
AR_Uks - 001_Nimetus: Kahepoolne siseuks 30; 300_Tähis: SUT-05; 310_Materjal: MUDELIS: väljast-Avatäide: raam värv antrasiit RAL7016; Avatäide: raam värv antrasiit RAL7016; seest-Avatäide: raam värv antrasiit RAL7016; Avatäide: raam värv antrasiit RAL7016; MÄRKUS: metall; 315_Avanemine: Parem ; ARCHICAD tüüp: Side Hung; 320_Klaas: ootel; 325_Helipidavus: R’w ≥ 35 dB; 330_Tulepüsivus: EI30 Sa; 335_Välispiire: no; 340_Soojusläbivus: 0; 350_Klaaspakett: -; 355_Pindala: 4.38 m2; 360_Ratastooliga: no; 365_Isesulguv: no; 370_Evakuatsiooniväljapääs: no; 375_Viimistlus-seest: MUDELIS: Avatäide: raam värv antrasiit RAL7016; Avatäide: raam värv antrasiit RAL7016; MÄRKUS: Matt must RAL9005; 376_Viimistlus-väljast: MUDELIS: Avatäide: raam värv antrasiit RAL7016; Avatäide: raam värv antrasiit RAL7016; MÄRKUS: Matt must RAL9005; 380_Lukustus: Sarjastatud; 900_Tootja: Saku metall; 905_Mudel: MFD131; 910_Tooteinfo: ootel; 915_Kasutus-ja-hooldusjuhend: ootel; 306_Ava-laius: 2000 mm; 307_Ava-kõrgus: 2190 mm; 377_Leng: Tootja standardtoode; 378_Lävepakk: Allalaskuv lävepakk, helikindel.; 379_Käepide: Abloy Forum 4, matt roostevaba; 381_Lukuraam: Standardtoode (EVS-EN 12209), luku viimistlus matt must, ruumi seest avanemine lingist; 382_Südamik: täpsustada TP-staadiumis; 383_Vasturaud: Tootja standard, matt roostevaba.; 384_Sulgur: -; 345_Päikesekiirgus-tegur: 0; 336_Sissepääs-hoonesse: no
AR_ÜLD - 009_Märkus: OMA märkus
AC_Pset_RenovationAndPhasing - Renovation Status: New

# IfcDoor: Double Door Asymmetric 26 (6)
In: Esimene korrus
Type - OperationType: DOUBLE_DOOR_SINGLE_SWING; ParameterTakesPrecedence: no; Sizeable: no
Type - Door Lining Properties - LiningThickness: 40 mm
Type - Door Panel Properties - Panel 1 - PanelDepth: 40 mm; PanelOperation: SWINGING; PanelWidth: 0.295775; PanelPosition: LEFT
Type - Door Panel Properties - Panel 2 - PanelDepth: 40 mm; PanelOperation: SWINGING; PanelWidth: 0.704225; PanelPosition: RIGHT
OverallHeight: 2200 mm; OverallWidth: 1500 mm; Classification: 1.10 IfcDoorStyle (uks) (BIM ÜBN + Archicad Classification)
Pset_DoorCommon - Reference: SUK-02; ThermalTransmittance: 0; GlazingAreaFraction: 1.568; IsExternal: no
AR_Uks - 001_Nimetus: Küljeklaasiga siseuks; 300_Tähis: SUK-02; 310_Materjal: MUDELIS: väljast-Avatäide: raam värv antrasiit RAL7016; Avatäide: raam värv antrasiit RAL7016; seest-Avatäide: raam värv antrasiit RAL7016; Avatäide: raam värv antrasiit RAL7016; MÄRKUS: metall/klaas; 315_Avanemine: Vasak ; ARCHICAD tüüp: Side Hung; 320_Klaas: ootel; 330_Tulepüsivus: nõudeid ei esitata; 335_Välispiire: no; 340_Soojusläbivus: 0; 350_Klaaspakett: Kahekordne klaaspakett, vaheliistude toon: must, lamineering; 355_Pindala: 3.3 m2; 360_Ratastooliga: no; 365_Isesulguv: no; 370_Evakuatsiooniväljapääs: no; 375_Viimistlus-seest: MUDELIS: Avatäide: raam värv antrasiit RAL7016; Avatäide: raam värv antrasiit RAL7016; MÄRKUS: Matt must RAL9005; 376_Viimistlus-väljast: MUDELIS: Avatäide: raam värv antrasiit RAL7016; Avatäide: raam värv antrasiit RAL7016; MÄRKUS: Matt must RAL9005; 380_Lukustus: Sarjastatud; 900_Tootja: Saku metall; 905_Mudel: MID131; 910_Tooteinfo: ootel; 915_Kasutus-ja-hooldusjuhend: ootel; 306_Ava-laius: 1500 mm; 307_Ava-kõrgus: 2200 mm; 377_Leng: Tootja standardtoode; 378_Lävepakk: Allalaskuv lävepakk, helikindel.; 379_Käepide: Abloy Forum 4, matt roostevaba; 381_Lukuraam: Standardtoode (EVS-EN 12209), luku viimistlus matt must, ruumi seest avanemine lingist; 382_Südamik: täpsustada TP-staadiumis; 383_Vasturaud: Tootja standard, matt roostevaba.; 384_Sulgur: Peidetud sulgur; 345_Päikesekiirgus-tegur: 0; 336_Sissepääs-hoonesse: no
AR_ÜLD - 009_Märkus: OMA märkus
AC_Pset_RenovationAndPhasing - Renovation Status: New
Name | 325_Helipidavus
5 x SUK-02 | R’w ≥ 30dB
SUK-02 | R’w ≥ 35 dB

# IfcDoor: Double Door Asymmetric 26 (7)
In: Esimene korrus
Type - OperationType: DOUBLE_DOOR_SINGLE_SWING; ParameterTakesPrecedence: no; Sizeable: no
Type - Door Lining Properties - LiningThickness: 40 mm
Type - Door Panel Properties - Panel 1 - PanelDepth: 40 mm; PanelOperation: SWINGING; PanelWidth: 0.295775; PanelPosition: RIGHT
Type - Door Panel Properties - Panel 2 - PanelDepth: 40 mm; PanelOperation: SWINGING; PanelWidth: 0.704225; PanelPosition: LEFT
OverallHeight: 2200 mm; OverallWidth: 1500 mm; Classification: 1.10 IfcDoorStyle (uks) (BIM ÜBN + Archicad Classification)
Pset_DoorCommon - Reference: SUK-01; ThermalTransmittance: 0; GlazingAreaFraction: 1.568; IsExternal: no
AR_Uks - 001_Nimetus: Küljeklaasiga siseuks; 300_Tähis: SUK-01; 310_Materjal: MUDELIS: väljast-Avatäide: raam värv antrasiit RAL7016; Avatäide: raam värv antrasiit RAL7016; seest-Avatäide: raam värv antrasiit RAL7016; Avatäide: raam värv antrasiit RAL7016; MÄRKUS: metall/klaas; 320_Klaas: ootel; 325_Helipidavus: R’w ≥ 30dB; 330_Tulepüsivus: nõudeid ei esitata; 335_Välispiire: no; 340_Soojusläbivus: 0; 350_Klaaspakett: Kahekordne klaaspakett, vaheliistude toon: must, lamineering; 355_Pindala: 3.3 m2; 360_Ratastooliga: no; 365_Isesulguv: no; 370_Evakuatsiooniväljapääs: no; 375_Viimistlus-seest: MUDELIS: Avatäide: raam värv antrasiit RAL7016; Avatäide: raam värv antrasiit RAL7016; MÄRKUS: Matt must RAL9005; 376_Viimistlus-väljast: MUDELIS: Avatäide: raam värv antrasiit RAL7016; Avatäide: raam värv antrasiit RAL7016; MÄRKUS: Matt must RAL9005; 380_Lukustus: Sarjastatud; 900_Tootja: Saku metall; 905_Mudel: MID131; 910_Tooteinfo: ootel; 915_Kasutus-ja-hooldusjuhend: ootel; 306_Ava-laius: 1500 mm; 307_Ava-kõrgus: 2200 mm; 377_Leng: Tootja standardtoode; 378_Lävepakk: Allalaskuv lävepakk, helikindel.; 381_Lukuraam: Standardtoode (EVS-EN 12209), luku viimistlus matt must, ruumi seest avanemine lingist; 382_Südamik: täpsustada TP-staadiumis; 383_Vasturaud: Tootja standard, matt roostevaba.; 345_Päikesekiirgus-tegur: 0; 336_Sissepääs-hoonesse: no
AR_ÜLD - 009_Märkus: OMA märkus
AC_Pset_RenovationAndPhasing - Renovation Status: New
Name | 315_Avanemine | 379_Käepide | 384_Sulgur
2 x SUK-01 | Parem ; ARCHICAD tüüp: Side Hung | Tootja standard, matt roostevaba | -
4 x SUK-01 | Parem; ARCHICAD tüüp: Side Hung | Abloy Forum 4, matt roostevaba | Peidetud sulgur
SUK-01 | Parem; ARCHICAD tüüp: Side Hung | Abloy Forum 4, matt roostevaba | -

# IfcDoor: Double Door with 2 Sidelights 26, VU-01
In: Esimene korrus
Type - OperationType: USERDEFINED; ParameterTakesPrecedence: no; Sizeable: no
OverallHeight: 2200 mm; OverallWidth: 2860 mm; Classification: 1.10 IfcDoorStyle (uks) (BIM ÜBN + Archicad Classification)
Pset_DoorCommon - Reference: VU-01; ThermalTransmittance: 0; GlazingAreaFraction: 4.0268; IsExternal: yes
AR_Uks - 001_Nimetus: Alumiiniumraamil välisuks; 300_Tähis: VU-01; 310_Materjal: MUDELIS: väljast-Avatäide: raam värv antrasiit RAL7016; Avatäide: raam värv antrasiit RAL7016; seest-Avatäide: raam värv antrasiit RAL7016; Avatäide: raam värv antrasiit RAL7016; MÄRKUS: Alumiinium; 315_Avanemine: Pöördavatav rullhingedel ukselehed, parempool aktiivneParem ; ARCHICAD tüüp: Side Hung; 320_Klaas: Kolmekordne klaaspakett, argoongaasiga, vaheliistud mustad, välimine: päikesekaitseklaas Cool-Lite SKN 183 II, LT=66%, karastatud klaas, klaasitoon: kirgas, keskmine: Planiclear, klaasitoon: kirgas, sisemine: Planitherm XN, lamineeritud floatklaas, klaasitoon: kirgas; 325_Helipidavus: R’tr,s,w = 35 dB; 330_Tulepüsivus: nõudeid ei esitata; 335_Välispiire: yes; 340_Soojusläbivus: 0; 350_Klaaspakett: 3k6SecSKN183II+4+44.1PlthXN-18Ar/18Ar (vaheliistude toon: must), Ug=0,5 W/(m2K); 355_Pindala: 6.292 m2; 360_Ratastooliga: no; 365_Isesulguv: no; 370_Evakuatsiooniväljapääs: yes; 375_Viimistlus-seest: MUDELIS: Avatäide: raam värv antrasiit RAL7016; Avatäide: raam värv antrasiit RAL7016; MÄRKUS: Matt antrasiit RAL7016; 376_Viimistlus-väljast: MUDELIS: Avatäide: raam värv antrasiit RAL7016; Avatäide: raam värv antrasiit RAL7016; MÄRKUS: Matt antrasiit RAL7016; 380_Lukustus: Kolmepunkti lukustussüsteem, täpsustada TP-staadiumis; 900_Tootja: ootel; 905_Mudel: ootel; 910_Tooteinfo: ootel; 915_Kasutus-ja-hooldusjuhend: ootel; 306_Ava-laius: 2860 mm; 307_Ava-kõrgus: 2200 mm; 377_Leng: AD UP 90; 378_Lävepakk: tootja standardtoode; 379_Käepide: tootja standard, viimistlus: roostevaba; 381_Lukuraam: täpsustada TP-staadiumis; 382_Südamik: täpsustada TP-staadiumis; 383_Vasturaud: täpsustada TP-staadiumis; 384_Sulgur: tootja standard peidetud sulgur; 345_Päikesekiirgus-tegur: 0; 336_Sissepääs-hoonesse: yes
AC_Pset_RenovationAndPhasing - Renovation Status: New

# IfcDoor: Double Door with 2 Sidelights, Transom 26, VU01a
In: Esimene korrus
Type - OperationType: USERDEFINED; ParameterTakesPrecedence: no; Sizeable: no
OverallHeight: 3600 mm; OverallWidth: 2850 mm; Classification: 1.10 IfcDoorStyle (uks) (BIM ÜBN + Archicad Classification)
Pset_DoorCommon - Reference: VU01a; ThermalTransmittance: 0; GlazingAreaFraction: 7.84595; IsExternal: yes
AR_Uks - 001_Nimetus: Klaasprofiiluks; 300_Tähis: VU01a; 310_Materjal: MUDELIS: väljast-Avatäide: raam värv antrasiit RAL7016; Avatäide: raam värv antrasiit RAL7016; seest-Avatäide: raam värv antrasiit RAL7016; Avatäide: raam värv antrasiit RAL7016; MÄRKUS: metall/klaas; 315_Avanemine: Parem ; ARCHICAD tüüp: Side Hung; 320_Klaas: Kahekordne klaaspakett, klaasitoon: kirgas, tootja standard; 325_Helipidavus: nõudeid ei esitata; 330_Tulepüsivus: nõudeid ei esitata; 335_Välispiire: no; 340_Soojusläbivus: 0; 350_Klaaspakett: Kahekordne klaaspakett, vaheliistude toon: must, lamineering; 355_Pindala: 10.26 m2; 360_Ratastooliga: no; 365_Isesulguv: no; 370_Evakuatsiooniväljapääs: no; 375_Viimistlus-seest: MUDELIS: Avatäide: raam värv antrasiit RAL7016; Avatäide: raam värv antrasiit RAL7016; MÄRKUS: Matt antrasiit RAL7016; 376_Viimistlus-väljast: MUDELIS: Avatäide: raam värv antrasiit RAL7016; Avatäide: raam värv antrasiit RAL7016; MÄRKUS: Matt antrasiit RAL7016; 380_Lukustus: Kolmepunkti lukustussüsteem, täpsustada TP-staadiumis; 900_Tootja: ootel; 905_Mudel: Schüco ADS 75.SI; 910_Tooteinfo: ootel; 915_Kasutus-ja-hooldusjuhend: ootel; 306_Ava-laius: 2850 mm; 307_Ava-kõrgus: 3600 mm; 377_Leng: ADS 65; 378_Lävepakk: tootja standardtoode; 379_Käepide: tootja standard, viimistlus: roostevaba; 381_Lukuraam: Standardtoode (EVS-EN 12209), luku viimistlus matt must, ruumi seest avanemine lingist; 382_Südamik: täpsustada TP-staadiumis; 383_Vasturaud: Tootja standard, matt roostevaba.; 384_Sulgur: tootja standard peidetud sulgur; 345_Päikesekiirgus-tegur: 0; 336_Sissepääs-hoonesse: no
AR_ÜLD - 009_Märkus: OMA märkus
AC_Pset_RenovationAndPhasing - Renovation Status: New

# IfcDoor: Double Door with Sidelight 26, VU-03
In: Esimene korrus
Type - OperationType: USERDEFINED; ParameterTakesPrecedence: no; Sizeable: no
OverallHeight: 2210 mm; OverallWidth: 2860 mm; Classification: 1.10 IfcDoorStyle (uks) (BIM ÜBN + Archicad Classification)
Pset_DoorCommon - Reference: VU-03; ThermalTransmittance: 0; GlazingAreaFraction: 0.8282; IsExternal: yes
AR_Uks - 001_Nimetus: Alumiiniumraamil välisuks; 300_Tähis: VU-03; 310_Materjal: MUDELIS: väljast-Avatäide: raam värv antrasiit RAL7016; Avatäide: raam värv antrasiit RAL7016; seest-Avatäide: raam värv antrasiit RAL7016; Avatäide: raam värv antrasiit RAL7016; MÄRKUS: Alumiinium; 315_Avanemine: Pöördavatav rullhingedel ukselehed, parempool aktiivneParem ; ARCHICAD tüüp: Side Hung; 320_Klaas: Kolmekordne klaaspakett, argoongaasiga, vaheliistud mustad, välimine: päikesekaitseklaas Cool-Lite SKN 183 II, LT=66%, karastatud klaas, klaasitoon: kirgas, keskmine: Planiclear, klaasitoon: kirgas, sisemine: Planitherm XN, lamineeritud floatklaas, klaasitoon: kirgas; 325_Helipidavus: R’tr,s,w = 30 dB; 330_Tulepüsivus: nõudeid ei esitata; 335_Välispiire: yes; 340_Soojusläbivus: 0; 350_Klaaspakett: 3k6SecSKN183II+4+44.1PlthXN-18Ar/18Ar (vaheliistude toon: must), Ug=0,5 W/(m2K); 355_Pindala: 6.3206 m2; 360_Ratastooliga: no; 365_Isesulguv: no; 370_Evakuatsiooniväljapääs: yes; 375_Viimistlus-seest: MUDELIS: Avatäide: raam värv antrasiit RAL7016; Avatäide: raam värv antrasiit RAL7016; MÄRKUS: Matt antrasiit RAL7016; 376_Viimistlus-väljast: MUDELIS: Avatäide: raam värv antrasiit RAL7016; Avatäide: raam värv antrasiit RAL7016; MÄRKUS: Matt antrasiit RAL7016; 380_Lukustus: Kolmepunkti lukustussüsteem, täpsustada TP-staadiumis; 900_Tootja: ootel; 905_Mudel: ootel; 910_Tooteinfo: ootel; 915_Kasutus-ja-hooldusjuhend: ootel; 306_Ava-laius: 2860 mm; 307_Ava-kõrgus: 2210 mm; 377_Leng: AD UP 90; 378_Lävepakk: tootja standardtoode; 379_Käepide: tootja standard, viimistlus: roostevaba; 381_Lukuraam: täpsustada TP-staadiumis; 382_Südamik: täpsustada TP-staadiumis; 383_Vasturaud: täpsustada TP-staadiumis; 384_Sulgur: tootja standardtoode; 345_Päikesekiirgus-tegur: 0; 336_Sissepääs-hoonesse: yes
AC_Pset_RenovationAndPhasing - Renovation Status: New

# IfcDoor: Double Door with Transom 26 (4)
In: Teine korrus
Type - OperationType: DOUBLE_DOOR_SINGLE_SWING; ParameterTakesPrecedence: no; Sizeable: no
Type - Door Lining Properties - LiningThickness: 40 mm; TransomThickness: 40 mm; TransomOffset: 2400 mm
Type - Door Panel Properties - Panel 1 - PanelDepth: 40 mm; PanelOperation: SWINGING; PanelWidth: 0.270073; PanelPosition: LEFT
Type - Door Panel Properties - Panel 2 - PanelDepth: 40 mm; PanelOperation: SWINGING; PanelWidth: 0.729927; PanelPosition: RIGHT
OverallHeight: 3060 mm; OverallWidth: 1450 mm; Classification: 1.10 IfcDoorStyle (uks) (BIM ÜBN + Archicad Classification)
Pset_DoorCommon - Reference: SUK-15; ThermalTransmittance: 0; GlazingAreaFraction: 2.9286; IsExternal: no
AR_Uks - 001_Nimetus: Kahepoolne siseuks/ ülaframuugiga; 300_Tähis: SUK-15; 310_Materjal: MUDELIS: väljast-Avatäide: raam värv antrasiit RAL7016; Avatäide: raam värv antrasiit RAL7016; seest-Avatäide: raam värv antrasiit RAL7016; Avatäide: raam värv antrasiit RAL7016; MÄRKUS: metall/klaas; 315_Avanemine: Vasak ; ARCHICAD tüüp: Side Hung; 320_Klaas: ootel; 330_Tulepüsivus: nõudeid ei esitata; 335_Välispiire: no; 340_Soojusläbivus: 0; 350_Klaaspakett: Kahekordne klaaspakett, vaheliistude toon: must, lamineering; 355_Pindala: 4.437 m2; 360_Ratastooliga: no; 365_Isesulguv: no; 370_Evakuatsiooniväljapääs: no; 375_Viimistlus-seest: MUDELIS: Avatäide: raam värv antrasiit RAL7016; Avatäide: raam värv antrasiit RAL7016; MÄRKUS: Matt must RAL9005; 376_Viimistlus-väljast: MUDELIS: Avatäide: raam värv antrasiit RAL7016; Avatäide: raam värv antrasiit RAL7016; MÄRKUS: Matt must RAL9005; 380_Lukustus: Sarjastatud; 900_Tootja: Saku metall; 905_Mudel: PIC021; 910_Tooteinfo: ootel; 915_Kasutus-ja-hooldusjuhend: ootel; 306_Ava-laius: 1450 mm; 307_Ava-kõrgus: 3060 mm; 377_Leng: Tootja standardtoode; 378_Lävepakk: Allalaskuv lävepakk, helikindel.; 379_Käepide: Abloy Forum 4, matt roostevaba; 381_Lukuraam: Standardtoode (EVS-EN 12209), luku viimistlus matt must, ruumi seest avanemine lingist; 382_Südamik: täpsustada TP-staadiumis; 383_Vasturaud: Tootja standard, matt roostevaba.; 384_Sulgur: Peidetud sulgur; 345_Päikesekiirgus-tegur: 0; 336_Sissepääs-hoonesse: no
AC_Pset_RenovationAndPhasing - Renovation Status: New
AR_ÜLD - 009_Märkus: OMA märkus
Name | 325_Helipidavus
3 x SUK-15 | R’w ≥ 30dB
SUK-15 | R’w ≥ 40 dB

# IfcDoor: Double Door with Transom 26, SUK-14
In: Teine korrus
Type - OperationType: DOUBLE_DOOR_SINGLE_SWING; ParameterTakesPrecedence: no; Sizeable: no
Type - Door Lining Properties - LiningThickness: 40 mm; TransomThickness: 40 mm; TransomOffset: 2400 mm
Type - Door Panel Properties - Panel 1 - PanelDepth: 40 mm; PanelOperation: SWINGING; PanelWidth: 0.295775; PanelPosition: LEFT
Type - Door Panel Properties - Panel 2 - PanelDepth: 40 mm; PanelOperation: SWINGING; PanelWidth: 0.704225; PanelPosition: RIGHT
OverallHeight: 3060 mm; OverallWidth: 1500 mm; Classification: 1.10 IfcDoorStyle (uks) (BIM ÜBN + Archicad Classification)
Pset_DoorCommon - Reference: SUK-14; ThermalTransmittance: 0; GlazingAreaFraction: 3.0676; IsExternal: no
AR_Uks - 001_Nimetus: Küljeklaasiga siseuks/ ülaframuugiga; 300_Tähis: SUK-14; 310_Materjal: MUDELIS: väljast-Avatäide: raam värv antrasiit RAL7016; Avatäide: raam värv antrasiit RAL7016; seest-Avatäide: raam värv antrasiit RAL7016; Avatäide: raam värv antrasiit RAL7016; MÄRKUS: metall/klaas; 315_Avanemine: Vasak ; ARCHICAD tüüp: Side Hung; 320_Klaas: ootel; 325_Helipidavus: R’w ≥ 30dB; 330_Tulepüsivus: EI30 S200; 335_Välispiire: no; 340_Soojusläbivus: 0; 350_Klaaspakett: Kahekordne klaaspakett, vaheliistude toon: must, lamineering; 355_Pindala: 4.59 m2; 360_Ratastooliga: no; 365_Isesulguv: no; 370_Evakuatsiooniväljapääs: no; 375_Viimistlus-seest: MUDELIS: Avatäide: raam värv antrasiit RAL7016; Avatäide: raam värv antrasiit RAL7016; MÄRKUS: Matt must RAL9005; 376_Viimistlus-väljast: MUDELIS: Avatäide: raam värv antrasiit RAL7016; Avatäide: raam värv antrasiit RAL7016; MÄRKUS: Matt must RAL9005; 380_Lukustus: Sarjastatud; 900_Tootja: Saku metall; 905_Mudel: PIC021; 910_Tooteinfo: ootel; 915_Kasutus-ja-hooldusjuhend: ootel; 306_Ava-laius: 1500 mm; 307_Ava-kõrgus: 3060 mm; 377_Leng: Tootja standardtoode; 378_Lävepakk: Allalaskuv lävepakk, helikindel.; 379_Käepide: Abloy Forum 4, matt roostevaba; 381_Lukuraam: Standardtoode (EVS-EN 12209), luku viimistlus matt must, ruumi seest avanemine lingist; 382_Südamik: täpsustada TP-staadiumis; 383_Vasturaud: Tootja standard, matt roostevaba.; 384_Sulgur: Peidetud sulgur; 345_Päikesekiirgus-tegur: 0; 336_Sissepääs-hoonesse: no
AR_ÜLD - 009_Märkus: OMA märkus
AC_Pset_RenovationAndPhasing - Renovation Status: New

# IfcDoor: Double Door with Transom 26, SUT-09
In: Teine korrus
Type - OperationType: DOUBLE_DOOR_SINGLE_SWING; ParameterTakesPrecedence: no; Sizeable: no
Type - Door Lining Properties - LiningThickness: 40 mm; TransomThickness: 40 mm; TransomOffset: 2400 mm
Type - Door Panel Properties - Panel 1 - PanelDepth: 40 mm; PanelOperation: SWINGING; PanelWidth: 0.319728; PanelPosition: RIGHT
Type - Door Panel Properties - Panel 2 - PanelDepth: 40 mm; PanelOperation: SWINGING; PanelWidth: 0.680272; PanelPosition: LEFT
OverallHeight: 3060 mm; OverallWidth: 1550 mm; Classification: 1.10 IfcDoorStyle (uks) (BIM ÜBN + Archicad Classification)
Pset_DoorCommon - Reference: SUT-09; ThermalTransmittance: 0; GlazingAreaFraction: 3.2066; IsExternal: no
AR_Uks - 001_Nimetus: Kahepoolne siseuks/ ülaframuugiga; 300_Tähis: SUT-09; 310_Materjal: MUDELIS: väljast-Avatäide: raam värv antrasiit RAL7016; Avatäide: raam värv antrasiit RAL7016; seest-Avatäide: raam värv antrasiit RAL7016; Avatäide: raam värv antrasiit RAL7016; MÄRKUS: metall/klaas; 315_Avanemine: -Parem ; ARCHICAD tüüp: Side Hung; 320_Klaas: ootel; 325_Helipidavus: R’w ≥ 30dB; 330_Tulepüsivus: EI30 Sa; 335_Välispiire: no; 340_Soojusläbivus: 0; 350_Klaaspakett: -; 355_Pindala: 4.743 m2; 360_Ratastooliga: no; 365_Isesulguv: no; 370_Evakuatsiooniväljapääs: no; 375_Viimistlus-seest: MUDELIS: Avatäide: raam värv antrasiit RAL7016; Avatäide: raam värv antrasiit RAL7016; MÄRKUS: Matt must RAL9005; 376_Viimistlus-väljast: MUDELIS: Avatäide: raam värv antrasiit RAL7016; Avatäide: raam värv antrasiit RAL7016; MÄRKUS: Matt must RAL9005; 380_Lukustus: Sarjastatud; 900_Tootja: Saku metall; 905_Mudel: PFC011; 910_Tooteinfo: ootel; 915_Kasutus-ja-hooldusjuhend: ootel; 306_Ava-laius: 1550 mm; 307_Ava-kõrgus: 3060 mm; 377_Leng: Tootja standardtoode; 378_Lävepakk: Allalaskuv lävepakk, helikindel.; 379_Käepide: Abloy Forum 4, matt roostevaba; 381_Lukuraam: Standardtoode (EVS-EN 12209), luku viimistlus matt must, ruumi seest avanemine lingist; 382_Südamik: täpsustada TP-staadiumis; 383_Vasturaud: Tootja standard, matt roostevaba.; 384_Sulgur: -; 345_Päikesekiirgus-tegur: 0; 336_Sissepääs-hoonesse: no
AR_ÜLD - 009_Märkus: OMA märkus
AC_Pset_RenovationAndPhasing - Renovation Status: New

# IfcDoor: Double Door with Transom 26, SUK-12
In: Teine korrus
Type - OperationType: DOUBLE_DOOR_SINGLE_SWING; ParameterTakesPrecedence: no; Sizeable: no
Type - Door Lining Properties - LiningThickness: 40 mm; TransomThickness: 40 mm; TransomOffset: 2400 mm
Type - Door Panel Properties - Panel 1 - PanelDepth: 40 mm; PanelOperation: SWINGING; PanelWidth: 0.5; PanelPosition: RIGHT
Type - Door Panel Properties - Panel 2 - PanelDepth: 40 mm; PanelOperation: SWINGING; PanelWidth: 0.5; PanelPosition: LEFT
OverallHeight: 3060 mm; OverallWidth: 1800 mm; Classification: 1.10 IfcDoorStyle (uks) (BIM ÜBN + Archicad Classification)
Pset_DoorCommon - Reference: SUK-12; ThermalTransmittance: 0; GlazingAreaFraction: 3.9016; IsExternal: no
AR_Uks - 001_Nimetus: Kahepoolne siseuks/ ülaframuugiga; 300_Tähis: SUK-12; 310_Materjal: MUDELIS: väljast-Avatäide: raam värv antrasiit RAL7016; Avatäide: raam värv antrasiit RAL7016; seest-Avatäide: raam värv antrasiit RAL7016; Avatäide: raam värv antrasiit RAL7016; MÄRKUS: metall/klaas; 315_Avanemine: Parem ; ARCHICAD tüüp: Side Hung; 320_Klaas: ootel; 325_Helipidavus: R’w ≥ 40 dB; 330_Tulepüsivus: nõudeid ei esitata; 335_Välispiire: no; 340_Soojusläbivus: 0; 350_Klaaspakett: Kahekordne klaaspakett, vaheliistude toon: must, lamineering; 355_Pindala: 5.508 m2; 360_Ratastooliga: no; 365_Isesulguv: no; 370_Evakuatsiooniväljapääs: no; 375_Viimistlus-seest: MUDELIS: Avatäide: raam värv antrasiit RAL7016; Avatäide: raam värv antrasiit RAL7016; MÄRKUS: Matt must RAL9005; 376_Viimistlus-väljast: MUDELIS: Avatäide: raam värv antrasiit RAL7016; Avatäide: raam värv antrasiit RAL7016; MÄRKUS: Matt must RAL9005; 380_Lukustus: Sarjastatud; 900_Tootja: Saku metall; 905_Mudel: PIC021; 910_Tooteinfo: ootel; 915_Kasutus-ja-hooldusjuhend: ootel; 306_Ava-laius: 1800 mm; 307_Ava-kõrgus: 3060 mm; 377_Leng: Tootja standardtoode; 378_Lävepakk: Allalaskuv lävepakk, helikindel.; 379_Käepide: Abloy Forum 4, exit matt roostevaba; 381_Lukuraam: Standardtoode (EVS-EN 12209), luku viimistlus matt must, ruumi seest avanemine lingist; 382_Südamik: täpsustada TP-staadiumis; 383_Vasturaud: Tootja standard, matt roostevaba.; 384_Sulgur: Peidetud sulgur; 345_Päikesekiirgus-tegur: 0; 336_Sissepääs-hoonesse: no
AR_ÜLD - 009_Märkus: OMA märkus
AC_Pset_RenovationAndPhasing - Renovation Status: New

# IfcDoor: Exterior Sliding Door 26, LU-01
In: Teine korrus
Type - OperationType: SLIDING_TO_RIGHT; ParameterTakesPrecedence: no; Sizeable: no
Type - Door Panel Properties - Panel 1 - PanelDepth: 40 mm; PanelOperation: SLIDING; PanelWidth: 1; PanelPosition: MIDDLE
OverallHeight: 2400 mm; OverallWidth: 1200 mm; Classification: 1.10 IfcDoorStyle (uks) (BIM ÜBN + Archicad Classification)
Pset_DoorCommon - Reference: LU-01; ThermalTransmittance: 0; GlazingAreaFraction: 2.3625; IsExternal: no
AR_Uks - 001_Nimetus: Lükanduks laboris; 300_Tähis: LU-01; 310_Materjal: MUDELIS: väljast-Avatäide: raam värv antrasiit RAL7016; Avatäide: raam värv antrasiit RAL7016; seest-Avatäide: raam värv antrasiit RAL7016; Avatäide: raam värv antrasiit RAL7016; MÄRKUS: metall raam ja kirgass klaas; 315_Avanemine: ; ARCHICAD tüüp: External Sliding; 320_Klaas: ootel; 325_Helipidavus: R’w ≥ 33 dB; 330_Tulepüsivus: nõudeid ei esitata; 335_Välispiire: no; 340_Soojusläbivus: 0; 350_Klaaspakett: Kahekordne klaaspakett, vaheliistude toon: must, lamineering; 355_Pindala: 2.88 m2; 360_Ratastooliga: no; 365_Isesulguv: no; 370_Evakuatsiooniväljapääs: no; 375_Viimistlus-seest: MUDELIS: Avatäide: raam värv antrasiit RAL7016; Avatäide: raam värv antrasiit RAL7016; MÄRKUS: Kirgas klaas; 376_Viimistlus-väljast: MUDELIS: Avatäide: raam värv antrasiit RAL7016; Avatäide: raam värv antrasiit RAL7016; MÄRKUS: Kirgas klaas; 380_Lukustus: Sarjastatud; 900_Tootja: Structo; 905_Mudel: -; 910_Tooteinfo: ootel; 915_Kasutus-ja-hooldusjuhend: ootel; 306_Ava-laius: 1200 mm; 307_Ava-kõrgus: 2400 mm; 377_Leng: Tootja standardtoode; 378_Lävepakk: Lävepakk puudub; 379_Käepide: Tootja standard, matt roostevaba; 381_Lukuraam: -; 382_Südamik: täpsustada TP-staadiumis; 383_Vasturaud: Tootja standard, matt roostevaba.; 384_Sulgur: -; 345_Päikesekiirgus-tegur: 0; 336_Sissepääs-hoonesse: no
AR_ÜLD - 009_Märkus: OMA märkus
AC_Pset_RenovationAndPhasing - Renovation Status: New

# IfcDoor: Movable Wall 26, SRD-01
In: Teine korrus
Type - ParameterTakesPrecedence: no; Sizeable: no
Classification: 1.10 IfcDoorStyle (uks) (BIM ÜBN + Archicad Classification); Material: 80 must mööbliplaat
Pset_DoorCommon - Reference: SRD-01; IsExternal: no
AR_Uks - 355_Pindala: 0 m2; 325_Helipidavus: R´w ≥ 52 dB; 001_Nimetus: Siirdesein koosolekute ruumis; 300_Tähis: SRD-01; 310_Materjal: MDF+vilt Noeche toon Cinnemon; 320_Klaas: ootel; 330_Tulepüsivus: nõudeid ei esitata; 335_Välispiire: no; 340_Soojusläbivus: 0; 350_Klaaspakett: -; 360_Ratastooliga: no; 365_Isesulguv: no; 370_Evakuatsiooniväljapääs: no; 375_Viimistlus-seest: 8 mm vilt, toon hall; 376_Viimistlus-väljast: 8 mm vilt, toon hall; 380_Lukustus: -; 900_Tootja: Emero; 905_Mudel: Emero Z1; 910_Tooteinfo: ootel; 915_Kasutus-ja-hooldusjuhend: ootel; 306_Ava-laius: 1110 mm; 307_Ava-kõrgus: 3500 mm; 377_Leng: Tootja standardtoode; 378_Lävepakk: Lävepakk puudub; 379_Käepide: Puudub; 383_Vasturaud: -; 384_Sulgur: -; 345_Päikesekiirgus-tegur: 0; 336_Sissepääs-hoonesse: no
AC_Pset_RenovationAndPhasing - Renovation Status: New
AR_ÜLD - 009_Märkus: OMA märkus

# IfcDoor: Vertical Sliding Garage Door 26 (7)
In: Esimene korrus
Type - OperationType: ROLLINGUP; ParameterTakesPrecedence: no; Sizeable: no
Type - Door Lining Properties - LiningDepth: 100 mm; LiningThickness: 50 mm; LiningOffset: 0 mm
Type - Door Panel Properties - Panel 1 - PanelDepth: 40 mm; PanelOperation: ROLLINGUP; PanelWidth: 1; PanelPosition: MIDDLE
Classification: 1.10 IfcDoorStyle (uks) (BIM ÜBN + Archicad Classification)
Pset_DoorCommon - ThermalTransmittance: 0
AR_Uks - 320_Klaas: puudub; 330_Tulepüsivus: nõudeid ei esitata; 340_Soojusläbivus: 0; 350_Klaaspakett: -; 360_Ratastooliga: no; 365_Isesulguv: no; 370_Evakuatsiooniväljapääs: no; 900_Tootja: ootel; 905_Mudel: ootel; 910_Tooteinfo: ootel; 915_Kasutus-ja-hooldusjuhend: ootel; 377_Leng: Tootja standardtoode; 378_Lävepakk: täpsustada TP-staadiumis; 381_Lukuraam: täpsustada TP-staadiumis; 382_Südamik: täpsustada TP-staadiumis; 383_Vasturaud: täpsustada TP-staadiumis; 384_Sulgur: tootja standardtoode; 345_Päikesekiirgus-tegur: 0
AC_Pset_RenovationAndPhasing - Renovation Status: New
Name | OverallHeight (mm) = 307_Ava-kõrgus (mm) | OverallWidth (mm) = 306_Ava-laius (mm) | Reference = 300_Tähis | IsExternal = 335_Välispiire = 336_Sissepääs-hoonesse | 001_Nimetus | 310_Materjal | 315_Avanemine | 325_Helipidavus | 355_Pindala (m2) | 375_Viimistlus-seest | 376_Viimistlus-väljast | 380_Lukustus | 379_Käepide
2 x GU-02 | 3600 | 2860 | GU-02 | yes | Tõstuks | MUDELIS: väljast-Avatäide: raam värv antrasiit RAL7016; Avatäide: raam värv antrasiit RAL7016; seest-Avatäide: raam värv antrasiit RAL7016; Avatäide: raam värv antrasiit RAL7016; MÄRKUS: Terasest soojustatud paneeliga sektsioonuks, 42mm paneel | Automaatikaga avanev tõstuks, madal N-tõstetüüpVasak | nõudeid ei esitata | 10.296 | MUDELIS: Avatäide: raam värv antrasiit RAL7016; Avatäide: raam värv antrasiit RAL7016; MÄRKUS: Matt antrasiit RAL7016 | MUDELIS: Avatäide: raam värv antrasiit RAL7016; Avatäide: raam värv antrasiit RAL7016; MÄRKUS: Matt antrasiit RAL7016, sile pind "Silkgrain" | Tootja standard lukustussüsteem, täpsustada TP-staadiumis | Tootja standard, viimistlus: matt must, käepide ainult sisemisel küljel
2 x GU-01 | 3600 | 2860 | GU-01 | yes | Tõstuks | MUDELIS: väljast-Avatäide: raam värv antrasiit RAL7016; Avatäide: raam värv antrasiit RAL7016; seest-Avatäide: raam värv antrasiit RAL7016; Avatäide: raam värv antrasiit RAL7016; MÄRKUS: Terasest soojustatud paneeliga sektsioonuks, 67mm paneel | Automaatikaga avanev tõstuks, madal N-tõstetüüp. Käigutee uks 905x2195mm keskelVasak | nõudeid ei esitata | 10.296 | MUDELIS: Avatäide: raam värv antrasiit RAL7016; Avatäide: raam värv antrasiit RAL7016; MÄRKUS: Matt antrasiit RAL7016 | MUDELIS: Avatäide: raam värv antrasiit RAL7016; Avatäide: raam värv antrasiit RAL7016; MÄRKUS: Matt antrasiit RAL7016, sile pind "Silkgrain". Käiguteeukse raam värvitud sama värvi, mis ukse põhitoon: RAL7016! | Tootja standard lukustussüsteem, käigutee uks sarjastatud lukustussüsteemiga, täpsustada TP-staadiumis | Tootja standard, viimistlus: matt must, käepide ainult sisemisel küljel. Käigutee ukse käepide/ukselink tootja standard, viimistlus: RAL7016
GU-01V | 3600 | 2860 | GU-01V | yes | Tõstuks | MUDELIS: väljast-Avatäide: raam värv antrasiit RAL7016; Avatäide: raam värv antrasiit RAL7016; seest-Avatäide: raam värv valge RAL9016; Avatäide: raam värv valge RAL9016; MÄRKUS: Terasest soojustatud paneeliga sektsioonuks, 67mm paneel | Automaatikaga avanev tõstuks, madal N-tõstetüüp. Käigutee uks 905x2195mm keskelVasak | nõudeid ei esitata | 10.296 | MUDELIS: Avatäide: raam värv valge RAL9016; Avatäide: raam värv valge RAL9016; MÄRKUS: Matt, tootja standard valge | MUDELIS: Avatäide: raam värv antrasiit RAL7016; Avatäide: raam värv antrasiit RAL7016; MÄRKUS: Matt antrasiit RAL7016, sile pind "Silkgrain". Käiguteeukse raam värvitud sama värvi, mis ukse põhitoon: RAL7016! | Tootja standard lukustussüsteem, käigutee uks sarjastatud lukustussüsteemiga, täpsustada TP-staadiumis | Tootja standard, viimistlus: matt must, käepide ainult sisemisel küljel. Käigutee ukse käepide/ukselink tootja standard, viimistlus: RAL7016
2 x GU-03 | 2200 | 2400 | GU-03 | no | Tõstuks siseruumis | MUDELIS: väljast-Avatäide: raam värv antrasiit RAL7016; Avatäide: raam värv antrasiit RAL7016; seest-Avatäide: raam värv antrasiit RAL7016; Avatäide: raam värv antrasiit RAL7016; MÄRKUS: Terasest sektsioonuks | Automaatikaga avanev tõstuks, kõrge H-tõstetüüp | R’w ≥ 25 dB | 5.28 | MUDELIS: Avatäide: raam värv antrasiit RAL7016; Avatäide: raam värv antrasiit RAL7016; MÄRKUS: Matt antrasiit RAL7016 | MUDELIS: Avatäide: raam värv antrasiit RAL7016; Avatäide: raam värv antrasiit RAL7016; MÄRKUS: Matt antrasiit RAL7016, sile pind "Silkgrain" | Tootja standard lukustussüsteem, täpsustada TP-staadiumis | Tootja standard, viimistlus: matt must, käepide ainult sisemisel küljel | AR_ÜLD - 009_Märkus: OMA märkus

# IfcFlowTerminal: 01 Üldine: projekteeritud 1120 (7)
Classification: 1.18 IfcSanitaryTerminalType (santehnika) (BIM ÜBN + Archicad Classification); Material: 01 Üldine: projekteeritud
AR_Viimistlus - 205_Tähis: P-02
AR_Santehnika - 001_Nimetus: Seinasisee WC-raam; 455_Eriomadused: -; 900_Tootja: Tece; 905_Mudel: Square; 910_Tooteinfo: ootel; 915_Kasutus-ja-hooldusjuhend: ootel; 002_Tähis: ST-01b
Pset_DistributionFlowElementCommon - Reference: ST-01b
AR_ÜLD - 009_Märkus: OMA märkus
AC_Pset_RenovationAndPhasing - Renovation Status: New
AR_Valgusti - 001_Nimetus: Seinasisee WC-raam; 900_Tootja: Tece; 905_Mudel: Square; 910_Tooteinfo: ootel; 915_Kasutus-ja-hooldusjuhend: ootel; 002_Tähis: ST-01b
Name | In
3 x ST-01b | Esimene korrus
4 x ST-01b | Teine korrus

# IfcFlowTerminal: 33 Konst: Columbia õõnesplokk 100 (30)
Classification: 1.18 IfcSanitaryTerminalType (santehnika) (BIM ÜBN + Archicad Classification); Material: 33 Konst: Columbia õõnesplokk
AR_Valgusti - 910_Tooteinfo: ootel; 915_Kasutus-ja-hooldusjuhend: ootel
AR_Santehnika - 455_Eriomadused: -; 910_Tooteinfo: ootel; 915_Kasutus-ja-hooldusjuhend: ootel
AC_Pset_RenovationAndPhasing - Renovation Status: New
AR_ÜLD - 009_Märkus: OMA märkus
Name | In | AR_Valgusti, 001_Nimetus = AR_Santehnika, 001_Nimetus | AR_Valgusti, 900_Tootja = AR_Santehnika, 900_Tootja | AR_Valgusti, 905_Mudel = AR_Santehnika, 905_Mudel | AR_Valgusti, 002_Tähis = AR_Santehnika, 002_Tähis = Reference
7 x ST-07 | Esimene korrus | Plaaditav renntrapp | Tece | Drainline | ST-07
5 x ST-11 | Esimene korrus | Põrandatrapp WC ruumis | Unidrain | Nurgatrapp | ST-11
7 x ST-08 | Esimene korrus | Liivapüüduriga põrandatrapp | Vieser | - | ST-08
ST-08 | Teine korrus | Liivapüüduriga põrandatrapp | Vieser | - | ST-08
6 x ST-09 | Teine korrus | Põrandatrapp II korruse laborites | Tece | - | ST-09
4 x ST-11 | Teine korrus | Põrandatrapp WC ruumis | Unidrain | Nurgatrapp | ST-11

# IfcFlowTerminal: Base Cabinet Block 26, ST-22
In: Teine korrus
Classification: 1.18 IfcSanitaryTerminalType (santehnika) (BIM ÜBN + Archicad Classification)
AR_Valgusti - 001_Nimetus: Roostevaba valamu köögis; 900_Tootja: Franke; 905_Mudel: -; 910_Tooteinfo: ootel; 915_Kasutus-ja-hooldusjuhend: ootel; 002_Tähis: ST-22
Pset_DistributionFlowElementCommon - Reference: ST-22
AR_ÜLD - 009_Märkus: OMA märkus
AR_Santehnika - 001_Nimetus: Roostevaba valamu köögis; 455_Eriomadused: -; 900_Tootja: Franke; 905_Mudel: -; 910_Tooteinfo: ootel; 915_Kasutus-ja-hooldusjuhend: ootel; 002_Tähis: ST-22
AC_Pset_RenovationAndPhasing - Renovation Status: New

# IfcFlowTerminal: Basin 26, ST-02
In: Esimene korrus
Classification: 1.18 IfcSanitaryTerminalType (santehnika) (BIM ÜBN + Archicad Classification)
Pset_DistributionFlowElementCommon - Reference: ST-02
AR_Santehnika - 001_Nimetus: Inva valamu; 455_Eriomadused: -; 900_Tootja: Laufen; 905_Mudel: Liberty; 910_Tooteinfo: ootel; 915_Kasutus-ja-hooldusjuhend: ootel; 002_Tähis: ST-02
AR_Valgusti - 001_Nimetus: Inva valamu; 900_Tootja: Laufen; 905_Mudel: Liberty; 910_Tooteinfo: ootel; 915_Kasutus-ja-hooldusjuhend: ootel; 002_Tähis: ST-02
AR_ÜLD - 009_Märkus: OMA märkus
AC_Pset_RenovationAndPhasing - Renovation Status: New

# IfcFlowTerminal: Basin Cabinet 26 (22)
Classification: 1.18 IfcSanitaryTerminalType (santehnika) (BIM ÜBN + Archicad Classification)
AR_Valgusti - 900_Tootja: ootel; 905_Mudel: ootel; 910_Tooteinfo: ootel; 915_Kasutus-ja-hooldusjuhend: ootel
AR_Santehnika - 455_Eriomadused: -; 900_Tootja: ootel; 905_Mudel: ootel; 910_Tooteinfo: ootel; 915_Kasutus-ja-hooldusjuhend: ootel
AR_ÜLD - 009_Märkus: OMA märkus
AC_Pset_RenovationAndPhasing - Renovation Status: New
Name | In | AR_Valgusti, 001_Nimetus = AR_Santehnika, 001_Nimetus | AR_Valgusti, 002_Tähis = AR_Santehnika, 002_Tähis = Reference
OML-11 | Esimene korrus | Valamukapp | OML-11
3 x OML-11 | Esimene korrus | Valamukapp 18 | OML-11
OML-10 | Esimene korrus | Kesklaua valmukapp | OML-10
3 x OML-10 | Esimene korrus | Valamukapp | OML-10
OML-11 | Esimene korrus | Valamulaud 18 | OML-11
OML-13 | Esimene korrus | Valamukapp | OML-13
OML-13 | Esimene korrus | Valamukapp seinaääres 15 | OML-13
3 x OML-10 | Teine korrus | labor ivalmukapp | OML-10
OML-10 | Teine korrus | Seinakinnitusega laborivalamu 12 | OML-10
2 x OML-30 | Teine korrus | labor ivalmukapp | OML-30
3 x OML-14 | Teine korrus | Seinakinnitusega laborivalamu 12 | OML-14
2 x OML-14 | Teine korrus | Laborivalamu | OML-14

# IfcFlowTerminal: Bideedušš (7)
Classification: 1.18 IfcSanitaryTerminalType (santehnika) (BIM ÜBN + Archicad Classification)
AR_Valgusti - 001_Nimetus: Bideedušš; 900_Tootja: Damixa; 905_Mudel: Silhouet; 910_Tooteinfo: ootel; 915_Kasutus-ja-hooldusjuhend: ootel; 002_Tähis: ST-18
AR_Santehnika - 001_Nimetus: Bideedušš; 455_Eriomadused: -; 900_Tootja: Damixa; 905_Mudel: Silhouet; 910_Tooteinfo: ootel; 915_Kasutus-ja-hooldusjuhend: ootel; 002_Tähis: ST-18
Pset_DistributionFlowElementCommon - Reference: ST-18
AR_ÜLD - 009_Märkus: OMA märkus
AC_Pset_RenovationAndPhasing - Renovation Status: New
Name | In
3 x ST-18 | Esimene korrus
4 x ST-18 | Teine korrus

# IfcFlowTerminal: Carpet 26, OM-18
In: Teine korrus
Classification: 1.18 IfcSanitaryTerminalType (santehnika) (BIM ÜBN + Archicad Classification)
AR_Valgusti - 001_Nimetus: Lahtine vaip; 900_Tootja: ootel; 905_Mudel: ootel; 910_Tooteinfo: ootel; 915_Kasutus-ja-hooldusjuhend: ootel; 002_Tähis: OM-18
AR_Santehnika - 001_Nimetus: Lahtine vaip; 455_Eriomadused: ootel; 900_Tootja: ootel; 905_Mudel: ootel; 910_Tooteinfo: ootel; 915_Kasutus-ja-hooldusjuhend: ootel; 002_Tähis: OM-18
Pset_DistributionFlowElementCommon - Reference: OM-18
AR_ÜLD - 009_Märkus: OMA märkus
AC_Pset_RenovationAndPhasing - Renovation Status: New

# IfcFlowTerminal: Cube 26 (3)
In: Teine korrus
Classification: 1.18 IfcSanitaryTerminalType (santehnika) (BIM ÜBN + Archicad Classification)
AR_Valgusti - 900_Tootja: ootel; 905_Mudel: ootel; 910_Tooteinfo: ootel; 915_Kasutus-ja-hooldusjuhend: ootel
AR_Santehnika - 455_Eriomadused: ootel; 900_Tootja: ootel; 905_Mudel: ootel; 910_Tooteinfo: ootel; 915_Kasutus-ja-hooldusjuhend: ootel
AR_ÜLD - 009_Märkus: OMA märkus
AC_Pset_RenovationAndPhasing - Renovation Status: New
Name | AR_Valgusti, 001_Nimetus = AR_Santehnika, 001_Nimetus
010 | Millipore originaal 500L | AR_Valgusti - 002_Tähis: 010; AR_Santehnika - 002_Tähis: 010; Pset_DistributionFlowElementCommon - Reference: 010
 | Tarbevee eelpehmendi
 | Puhtaveetrassi pump

# IfcFlowTerminal: Elkay_LBWD06BKK_veeautomaat (2)
In: Teine korrus
Classification: 1.18 IfcSanitaryTerminalType (santehnika) (BIM ÜBN + Archicad Classification); Material: 31 Konst: raudbetoon monoliitne
AR_Valgusti - 001_Nimetus: Veemasin; 900_Tootja: Elkay; 905_Mudel: -; 910_Tooteinfo: ootel; 915_Kasutus-ja-hooldusjuhend: ootel
AR_Santehnika - 001_Nimetus: Veemasin; 455_Eriomadused: -; 900_Tootja: Elkay; 905_Mudel: -; 910_Tooteinfo: ootel; 915_Kasutus-ja-hooldusjuhend: ootel
AR_ÜLD - 009_Märkus: OMA märkus
AC_Pset_RenovationAndPhasing - Renovation Status: New

# IfcFlowTerminal: Emergency safety shower (2)
Classification: 1.18 IfcSanitaryTerminalType (santehnika) (BIM ÜBN + Archicad Classification); Material: 80 must mööbliplaat, 01 ÜLD: projekteeritav, 40 Kiht: Teras
AR_Santehnika - 001_Nimetus: Hädaabidušš seinapealne; 455_Eriomadused: -; 900_Tootja: Broen-Lab; 905_Mudel: -; 910_Tooteinfo: ootel; 915_Kasutus-ja-hooldusjuhend: ootel; 002_Tähis: STL-01
AR_Valgusti - 001_Nimetus: Hädaabidušš seinapealne; 900_Tootja: Broen-Lab; 905_Mudel: -; 910_Tooteinfo: ootel; 915_Kasutus-ja-hooldusjuhend: ootel; 002_Tähis: STL-01
Pset_DistributionFlowElementCommon - Reference: STL-01
AR_ÜLD - 009_Märkus: OMA märkus
AC_Pset_RenovationAndPhasing - Renovation Status: New
Name | In
STL-01 | Esimene korrus
STL-01 | Teine korrus

# IfcFlowTerminal: Mop Sink 26, ST-16
In: Teine korrus
Classification: 1.18 IfcSanitaryTerminalType (santehnika) (BIM ÜBN + Archicad Classification)
AR_Valgusti - 001_Nimetus: Valamu tehnoruumis; 900_Tootja: Intra; 905_Mudel: -; 910_Tooteinfo: ootel; 915_Kasutus-ja-hooldusjuhend: ootel; 002_Tähis: ST-16
AR_Santehnika - 001_Nimetus: Valamu tehnoruumis; 455_Eriomadused: -; 900_Tootja: Intra; 905_Mudel: -; 910_Tooteinfo: ootel; 915_Kasutus-ja-hooldusjuhend: ootel; 002_Tähis: ST-16
Pset_DistributionFlowElementCommon - Reference: ST-16
AR_ÜLD - 009_Märkus: OMA märkus
AC_Pset_RenovationAndPhasing - Renovation Status: New

# IfcFlowTerminal: Multi-Basin Counter 26 (6)
Classification: 1.18 IfcSanitaryTerminalType (santehnika) (BIM ÜBN + Archicad Classification)
AR_Valgusti - 001_Nimetus: Seinakinnitusega valamu; 910_Tooteinfo: ootel; 915_Kasutus-ja-hooldusjuhend: ootel
AR_Santehnika - 001_Nimetus: Seinakinnitusega valamu; 455_Eriomadused: -; 910_Tooteinfo: ootel; 915_Kasutus-ja-hooldusjuhend: ootel
AR_ÜLD - 009_Märkus: OMA märkus
AC_Pset_RenovationAndPhasing - Renovation Status: New
Name | In | AR_Valgusti, 900_Tootja = AR_Santehnika, 900_Tootja | AR_Valgusti, 905_Mudel = AR_Santehnika, 905_Mudel | AR_Valgusti, 002_Tähis = AR_Santehnika, 002_Tähis = Reference
2 x ST-12 | Esimene korrus | Laufen | Meda | ST-12
2 x ST-14 | Teine korrus | Paa baths | Flow 450 | ST-14
2 x ST-12 | Teine korrus | Laufen | Meda | ST-12

# IfcFlowTerminal: P-00b 20, ST-10
In: Esimene korrus
Classification: 1.18 IfcSanitaryTerminalType (santehnika) (BIM ÜBN + Archicad Classification); Material: 85 Viimistlus: jalapuhastusrest
AR_Valgusti - 001_Nimetus: Poripüüdja; 900_Tootja: Kavika; 905_Mudel: -; 910_Tooteinfo: ootel; 915_Kasutus-ja-hooldusjuhend: ootel; 002_Tähis: ST-10
AR_Santehnika - 001_Nimetus: Poripüüdja; 455_Eriomadused: -; 900_Tootja: Kavika; 905_Mudel: -; 910_Tooteinfo: ootel; 915_Kasutus-ja-hooldusjuhend: ootel; 002_Tähis: ST-10
Pset_DistributionFlowElementCommon - Reference: ST-10
AR_ÜLD - 009_Märkus: OMA märkus
AC_Pset_RenovationAndPhasing - Renovation Status: New

# IfcFlowTerminal: Shower Kit 26 (7)
In: Esimene korrus
Classification: 1.18 IfcSanitaryTerminalType (santehnika) (BIM ÜBN + Archicad Classification)
AR_Valgusti - 001_Nimetus: Dušisegisti pesuruumis; 900_Tootja: Damixa; 905_Mudel: Silhouet; 910_Tooteinfo: ootel; 915_Kasutus-ja-hooldusjuhend: ootel
AR_Santehnika - 001_Nimetus: Dušisegisti pesuruumis; 455_Eriomadused: 8L; 900_Tootja: Damixa; 905_Mudel: Silhouet; 910_Tooteinfo: ootel; 915_Kasutus-ja-hooldusjuhend: ootel
AR_ÜLD - 009_Märkus: OMA märkus
AC_Pset_RenovationAndPhasing - Renovation Status: New
Name | AR_Valgusti, 002_Tähis = AR_Santehnika, 002_Tähis = Reference
5 x ST-06 | ST-06
2 x ST-06* | ST-06*

# IfcFlowTerminal: Sink Belfast 26 (2)
Classification: 1.18 IfcSanitaryTerminalType (santehnika) (BIM ÜBN + Archicad Classification)
AR_Santehnika - 001_Nimetus: Koristus valamu koristaja ruumis; 455_Eriomadused: -; 900_Tootja: Franke; 905_Mudel: Kalla; 910_Tooteinfo: ootel; 915_Kasutus-ja-hooldusjuhend: ootel; 002_Tähis: ST-04
Pset_DistributionFlowElementCommon - Reference: ST-04
AR_ÜLD - 009_Märkus: OMA märkus
AR_Valgusti - 001_Nimetus: Koristus valamu koristaja ruumis; 900_Tootja: Franke; 905_Mudel: Kalla; 910_Tooteinfo: ootel; 915_Kasutus-ja-hooldusjuhend: ootel; 002_Tähis: ST-04
AC_Pset_RenovationAndPhasing - Renovation Status: New
Name | In
ST-04 | Esimene korrus
ST-04 | Teine korrus

# IfcFlowTerminal: Tap 26 (41)
Classification: 1.18 IfcSanitaryTerminalType (santehnika) (BIM ÜBN + Archicad Classification)
AR_Valgusti - 910_Tooteinfo: ootel; 915_Kasutus-ja-hooldusjuhend: ootel
AR_ÜLD - 009_Märkus: OMA märkus
AC_Pset_RenovationAndPhasing - Renovation Status: New
Name | In | AR_Valgusti, 001_Nimetus | AR_Valgusti, 900_Tootja | AR_Valgusti, 905_Mudel | AR_Valgusti, 002_Tähis = Reference | AR_Santehnika, 001_Nimetus | 455_Eriomadused | AR_Santehnika, 900_Tootja | AR_Santehnika, 905_Mudel | 910_Tooteinfo = 915_Kasutus-ja-hooldusjuhend | AR_Santehnika, 002_Tähis
ST-03 | Esimene korrus | Inva segsiti | Wagner Ewar | WA100-1 | ST-03 | Inva segsiti | 5/3-L | Wagner Ewar | WA100-1 | ootel | ST-03
4 x STL-02 | Esimene korrus | Laborisegisti, kangiga | Broen-Lab | - | STL-01 | Laborisegisti, kangiga | 5/3-L | Broen-Lab | - | ootel | STL-01
STL-03 | Esimene korrus | Hädaabi silmadušš | Broen-Lab | - | STL-03 | Hädaabi silmadušš | - | Broen-Lab | - | ootel | STL-03
2 x ST-13 | Esimene korrus | Volamusegisti | Damixa | Silhouet | ST-13 | AR_Valgusti - sets with these values: 2
7 x STL-02 | Esimene korrus | Laborisegisti, kangiga | Broen-Lab | - | STL-02 | Laborisegisti, kangiga | 5/3-L | Broen-Lab | - | ootel | STL-02
STL-04 | Esimene korrus | Dest.vee segisti | Broen-Lab | - | STL-04 | Dest.vee segisti | 5/3-L | Broen-Lab | - | ootel | STL-04
ST-20 | Teine korrus | Köögisegisti köögis | Franke | Atlas | ST-20 | Köögisegisti köögis | 6L/min | Franke | Atlas | ootel | ST-20 | AR_Uks - 355_Pindala: 0 m2
2 x STL-03 | Teine korrus | Hädaabi silmadušš | Broen-Lab | - | STL-03 | Hädaabi silmadušš | - | Broen-Lab | - | ootel | STL-03
9 x STL-04 | Teine korrus | Dest.vee segisti | Broen-Lab | - | STL-04 | Dest.vee segisti | 5/3-L | Broen-Lab | - | ootel | STL-04
2 x ST-13 | Teine korrus | Volamusegisti | Damixa | Silhouet | ST-13 | AR_Valgusti - sets with these values: 2
11 x STL-02 | Teine korrus | Laborisegisti, kangiga | Broen-Lab | - | STL-02 | Laborisegisti, kangiga | 5/3-L | Broen-Lab | - | ootel | STL-02

# IfcFlowTerminal: WC 26 (5)
Classification: 1.18 IfcSanitaryTerminalType (santehnika) (BIM ÜBN + Archicad Classification)
AR_Santehnika - 001_Nimetus: Seinakinnitusega WC-pott; 455_Eriomadused: 8L; 900_Tootja: Laufen; 910_Tooteinfo: ootel; 915_Kasutus-ja-hooldusjuhend: ootel; 002_Tähis: ST-01a
AR_Valgusti - 001_Nimetus: Seinakinnitusega WC-pott; 900_Tootja: Laufen; 905_Mudel: Pro; 910_Tooteinfo: ootel; 915_Kasutus-ja-hooldusjuhend: ootel; 002_Tähis: ST-01a
AR_ÜLD - 009_Märkus: OMA märkus
AC_Pset_RenovationAndPhasing - Renovation Status: New
Pset_DistributionFlowElementCommon - Reference: ST-01a
Name | In
3 x ST-01a | Esimene korrus
2 x ST-01a | Teine korrus

# IfcFlowTerminal: Wall Mounted Tap 26 (5)
Classification: 1.18 IfcSanitaryTerminalType (santehnika) (BIM ÜBN + Archicad Classification)
AR_Valgusti - 910_Tooteinfo: ootel; 915_Kasutus-ja-hooldusjuhend: ootel
AR_Santehnika - 910_Tooteinfo: ootel; 915_Kasutus-ja-hooldusjuhend: ootel
AR_ÜLD - 009_Märkus: OMA märkus
AC_Pset_RenovationAndPhasing - Renovation Status: New
Name | In | AR_Valgusti, 001_Nimetus = AR_Santehnika, 001_Nimetus | AR_Valgusti, 900_Tootja = AR_Santehnika, 900_Tootja | AR_Valgusti, 905_Mudel = AR_Santehnika, 905_Mudel | AR_Valgusti, 002_Tähis = AR_Santehnika, 002_Tähis = Reference | 455_Eriomadused
ST-21 | Esimene korrus | Kangsegisti kummikute pesuks | Oras | Safira | ST-21 | 8L
ST-05 | Esimene korrus | Seinapealne koristaja segisti | Idral | - | ST-05 | 5/3-L
ST-19 | Esimene korrus | Inva dušisegisti | Fimacf | - | ST-19 | 8L
2 x ST-05 | Teine korrus | Seinapealne koristaja segisti | Idral | - | ST-05 | 5/3-L

# IfcFlowTerminal: siphon 2 (7)
Classification: 1.18 IfcSanitaryTerminalType (santehnika) (BIM ÜBN + Archicad Classification); Material: 91 Viimistlus: krohv
Pset_ProductRequirements - Category: Generic Models
Constraints - Elevation from Level: 0 mm; Moves With Nearby Elements: no; Offset from Host: 0 mm
Dimensions - Area: 36.1165 m2; Volume: 0.968197 m3
Other - Category: Generic Models; Family: BIM Motala Hissar: MasterType; Family and Type: BIM Motala Hissar: MasterType; Type: BIM Motala Hissar: MasterType; Type Id: BIM Motala Hissar: MasterType
Phasing - Phase Created: New Construction
AR_ÜLD - 009_Märkus: OMA märkus
AC_Pset_RenovationAndPhasing - Renovation Status: New
Pset_DistributionFlowElementCommon - Reference: ST-15
Name (BIM Motala Hissar:MasterType:...) | In | Pset_BuildingElementProxyCommon, Reference | Pset_BuildingElementProxyCommon, sets with these values | AR_Valgusti, 001_Nimetus | AR_Valgusti, 900_Tootja = AR_Valgusti, 910_Tooteinfo = AR_Valgusti, 915_Kasutus-ja-hooldusjuhend | AR_Valgusti, 905_Mudel | AR_Valgusti, 002_Tähis | AR_Valgusti, sets with these values
2 x 7813 | Esimene korrus | MasterType | 2 | Sifoon | ootel | - | ST-15 | 2
7813 | Esimene korrus | AR_Santehnika - 001_Nimetus: Sifoon; 900_Tootja: ootel; 905_Mudel: -; 910_Tooteinfo: ootel; 915_Kasutus-ja-hooldusjuhend: ootel; 002_Tähis: ST-15; sets with these values: 2; Pset_QuantityTakeOff - Reference: MasterType; sets with these values: 2
2 x 7813 | Teine korrus | MasterType | 2 | Sifoon | ootel | - | ST-15 | 2
7813 | Teine korrus | MasterType | 2 | AR_Santehnika - 001_Nimetus: Sifoon; 900_Tootja: ootel; 905_Mudel: -; 910_Tooteinfo: ootel; 915_Kasutus-ja-hooldusjuhend: ootel; 002_Tähis: ST-15; sets with these values: 2
7813 | Teine korrus | AR_Santehnika - 001_Nimetus: Sifoon; 900_Tootja: ootel; 905_Mudel: -; 910_Tooteinfo: ootel; 915_Kasutus-ja-hooldusjuhend: ootel; 002_Tähis: ST-15; sets with these values: 2; Pset_QuantityTakeOff - Reference: MasterType; sets with these values: 2

# IfcFlowTerminal: tap for basin idral (2)
In: Teine korrus
Classification: 1.18 IfcSanitaryTerminalType (santehnika) (BIM ÜBN + Archicad Classification); Material: 01 Üldine: projekteeritud
AR_Valgusti - 001_Nimetus: Seinakinnitusega segisti; 900_Tootja: Idral; 905_Mudel: AISI 316L; 910_Tooteinfo: ootel; 915_Kasutus-ja-hooldusjuhend: ootel; 002_Tähis: ST-23
Pset_DistributionFlowElementCommon - Reference: ST-23
AR_Santehnika - 001_Nimetus: Seinakinnitusega segisti; 455_Eriomadused: 6L/min; 220V; 900_Tootja: Idral; 905_Mudel: AISI 316L; 910_Tooteinfo: ootel; 915_Kasutus-ja-hooldusjuhend: ootel; 002_Tähis: ST-23
AR_ÜLD - 009_Märkus: OMA märkus
AC_Pset_RenovationAndPhasing - Renovation Status: New

# IfcFurnishingElement: 01 ÜLD: projekteeritav 1, EM-10
In: Teine korrus
Classification: 1.11 IfcFurnitureType (mööbel) (BIM ÜBN + Archicad Classification); Material: 01 ÜLD: projekteeritav
AR_Mööbel - 900_Tootja: ootel; 905_Mudel: ootel; 002_Tähis: EM-10
Pset_QuantityTakeOff - Reference: EM-10
AR_ÜLD - 009_Märkus: OMA märkus
AC_Pset_RenovationAndPhasing - Renovation Status: New

# IfcFurnishingElement: 01 ÜLD: projekteeritav 1180 (2)
In: Teine korrus
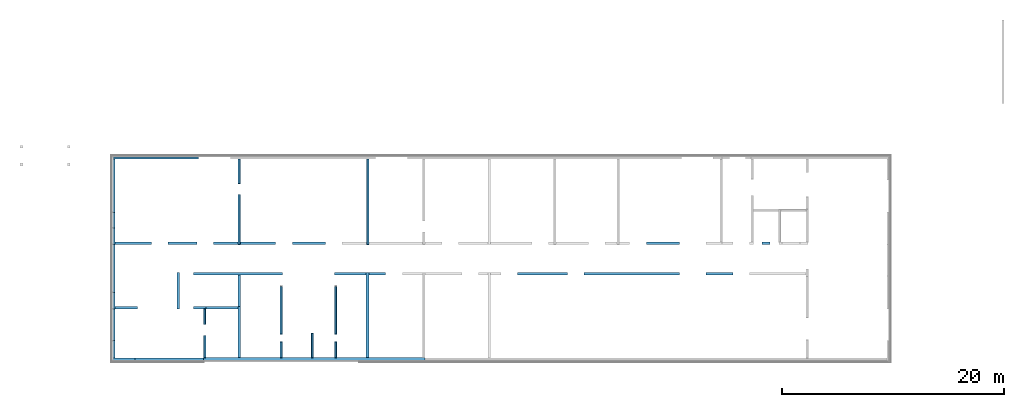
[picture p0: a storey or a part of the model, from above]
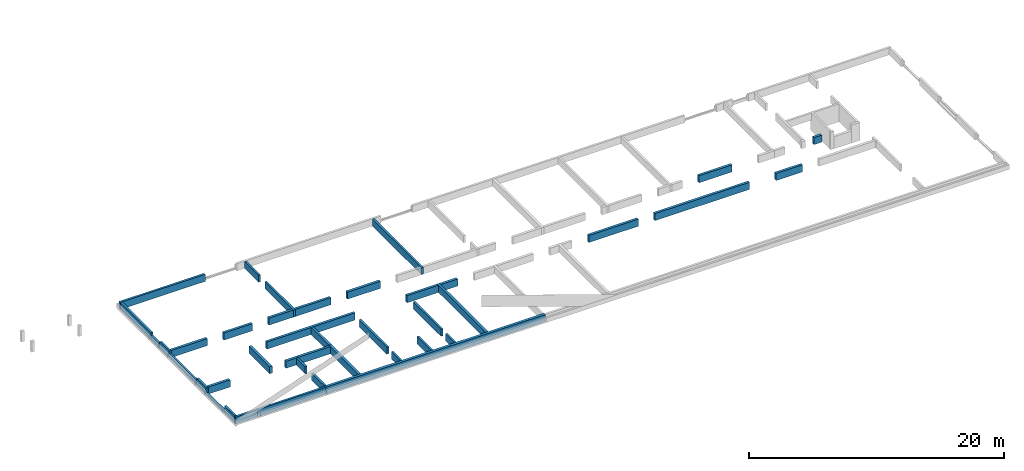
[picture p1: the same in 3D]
Properties of the parts of a building model (IFC2X3), part 6 of 8

# IfcFurnishingElement: 01 ÜLD: projekteeritav 1180 (2)
Classification: 1.11 IfcFurnitureType (mööbel) (BIM ÜBN + Archicad Classification); Material: 01 ÜLD: projekteeritav
AC_Pset_RenovationAndPhasing - Renovation Status: New
AR_ÜLD - 009_Märkus: OMA märkus
AR_Mööbel - 900_Tootja: ootel; 905_Mudel: ootel
Name | Reference = 002_Tähis
EM-06 | EM-06
EM-10 | EM-10

# IfcFurnishingElement: 01 ÜLD: projekteeritav 1200, EM-10
In: Teine korrus
Classification: 1.11 IfcFurnitureType (mööbel) (BIM ÜBN + Archicad Classification); Material: 01 ÜLD: projekteeritav
AR_Mööbel - 900_Tootja: ootel; 905_Mudel: ootel; 002_Tähis: EM-10
AR_ÜLD - 009_Märkus: OMA märkus
Pset_QuantityTakeOff - Reference: EM-10
AC_Pset_RenovationAndPhasing - Renovation Status: New

# IfcFurnishingElement: 01 ÜLD: projekteeritav 20, EM-08
In: Teine korrus
Classification: 1.11 IfcFurnitureType (mööbel) (BIM ÜBN + Archicad Classification); Material: 01 ÜLD: projekteeritav
AR_Mööbel - 001_Nimetus: Köögiriiul; 900_Tootja: ootel; 905_Mudel: ootel; 002_Tähis: EM-08
Pset_QuantityTakeOff - Reference: EM-08
AR_ÜLD - 009_Märkus: OMA märkus
AC_Pset_RenovationAndPhasing - Renovation Status: New

# IfcFurnishingElement: 01 ÜLD: projekteeritav 250 (8)
In: Teine korrus
Classification: 1.11 IfcFurnitureType (mööbel) (BIM ÜBN + Archicad Classification); Material: 01 ÜLD: projekteeritav
AR_ÜLD - 009_Märkus: OMA märkus
AC_Pset_RenovationAndPhasing - Renovation Status: New
AR_Mööbel - 001_Nimetus: Laekonsool; 900_Tootja: ootel; 905_Mudel: ootel
Name | Reference = 002_Tähis
015 | 015
012 | 012
011 | 011
013 | 013
OML-27 | OML-27
009 | 009
014 | 014
010 | 010

# IfcFurnishingElement: 01 ÜLD: projekteeritav 50 (2)
In: Teine korrus
Classification: 1.11 IfcFurnitureType (mööbel) (BIM ÜBN + Archicad Classification); Material: 01 ÜLD: projekteeritav
AR_Mööbel - 900_Tootja: ootel; 905_Mudel: ootel; 002_Tähis: EM-10
Pset_QuantityTakeOff - Reference: EM-10
AR_ÜLD - 009_Märkus: OMA märkus
AC_Pset_RenovationAndPhasing - Renovation Status: New

# IfcFurnishingElement: 01 ÜLD: projekteeritav 850, EM-10
In: Teine korrus
Classification: 1.11 IfcFurnitureType (mööbel) (BIM ÜBN + Archicad Classification); Material: 01 ÜLD: projekteeritav
AR_ÜLD - 009_Märkus: OMA märkus
AC_Pset_RenovationAndPhasing - Renovation Status: New
Pset_QuantityTakeOff - Reference: EM-10
AR_Mööbel - 900_Tootja: ootel; 905_Mudel: ootel; 002_Tähis: EM-10

# IfcFurnishingElement: 01 ÜLD: projekteeritav 900, EM-10
In: Teine korrus
Classification: 1.11 IfcFurnitureType (mööbel) (BIM ÜBN + Archicad Classification); Material: 01 ÜLD: projekteeritav
AR_Mööbel - 900_Tootja: ootel; 905_Mudel: ootel; 002_Tähis: EM-10
AC_Pset_RenovationAndPhasing - Renovation Status: New
AR_ÜLD - 009_Märkus: OMA märkus
Pset_QuantityTakeOff - Reference: EM-10

# IfcFurnishingElement: 01 ÜLD: projekteeritav 980, EM-05
In: Teine korrus
Classification: 1.11 IfcFurnitureType (mööbel) (BIM ÜBN + Archicad Classification); Material: 01 ÜLD: projekteeritav
AR_Mööbel - 900_Tootja: ootel; 905_Mudel: ootel; 002_Tähis: EM-05
AR_ÜLD - 009_Märkus: OMA märkus
Pset_QuantityTakeOff - Reference: EM-05
AC_Pset_RenovationAndPhasing - Renovation Status: New

# IfcFurnishingElement: 01 Üldine: projekteeritud 254 (2)
In: Teine korrus
Classification: 1.11 IfcFurnitureType (mööbel) (BIM ÜBN + Archicad Classification); Material: 01 Üldine: projekteeritud
AR_Mööbel - 001_Nimetus: Tualettpaberihoidja; 900_Tootja: JNF; 905_Mudel: Industrial; 002_Tähis: AK-02.2
Pset_QuantityTakeOff - Reference: AK-02.2
AR_ÜLD - 009_Märkus: OMA märkus
AC_Pset_RenovationAndPhasing - Renovation Status: New

# IfcFurnishingElement: 01 Üldine: projekteeritud 300 (6)
Classification: 1.11 IfcFurnitureType (mööbel) (BIM ÜBN + Archicad Classification); Material: 01 Üldine: projekteeritud
Pset_QuantityTakeOff - Reference: AK-01.2
AR_ÜLD - 009_Märkus: OMA märkus
AC_Pset_RenovationAndPhasing - Renovation Status: New
AR_Mööbel - 001_Nimetus: Seinakinnitusega väike prugikast; 900_Tootja: JNF; 905_Mudel: Industrial; 002_Tähis: AK-01.2
Name | In
2 x AK-01.2 | Esimene korrus
4 x AK-01.2 | Teine korrus

# IfcFurnishingElement: 01 Üldine: projekteeritud 380 (6)
Classification: 1.11 IfcFurnitureType (mööbel) (BIM ÜBN + Archicad Classification); Material: 01 Üldine: projekteeritud
AR_Mööbel - 001_Nimetus: Põrandale prügikast; 900_Tootja: Mediclinics; 905_Mudel: -; 002_Tähis: AK-01.3
Pset_QuantityTakeOff - Reference: AK-01.3
AC_Pset_RenovationAndPhasing - Renovation Status: New
AR_ÜLD - 009_Märkus: OMA märkus
Name | In
2 x AK-01.3 | Esimene korrus
4 x AK-01.3 | Teine korrus

# IfcFurnishingElement: 31 Konst: raudbetoon monoliitne 10 (2)
In: Esimene korrus
Classification: 1.11 IfcFurnitureType (mööbel) (BIM ÜBN + Archicad Classification); Material: 31 Konst: raudbetoon monoliitne
AR_Mööbel - 001_Nimetus: Elektrikeris; 900_Tootja: HUUM; 905_Mudel: DROP; 002_Tähis: TH-05
Pset_QuantityTakeOff - Reference: TH-05
AR_ÜLD - 009_Märkus: OMA märkus
AC_Pset_RenovationAndPhasing - Renovation Status: New

# IfcFurnishingElement: 80 Siseviim: kipskrohv 1 (4)
In: Teine korrus
Classification: 1.11 IfcFurnitureType (mööbel) (BIM ÜBN + Archicad Classification); Material: 80 Siseviim: kipskrohv
AR_Mööbel - 900_Tootja: Soundtect; 905_Mudel: Wallpanel
AC_Pset_RenovationAndPhasing - Renovation Status: New
Name | 001_Nimetus | 002_Tähis = Reference
S-10 | Roheline viltsein 9mm, toon roheline Glade | S-10
2 x EM-05 | Roheline viltsein 9mm, toon roheline Glade | EM-05
EM-06 | Sisseehitatud kapp | EM-06

# IfcFurnishingElement: 80 Siseviim: kipskrohv 40 (4)
In: Teine korrus
Classification: 1.11 IfcFurnitureType (mööbel) (BIM ÜBN + Archicad Classification); Material: 80 Siseviim: kipskrohv
AR_Mööbel - 900_Tootja: Soundtect; 905_Mudel: Wallpanel
AC_Pset_RenovationAndPhasing - Renovation Status: New
Name | 001_Nimetus | 002_Tähis = Reference
2 x EM-06 | Sisseehitatud kapp | EM-06
2 x EM-05 | Roheline viltsein 9mm, toon roheline Glade | EM-05

# IfcFurnishingElement: 80 Siseviim: kummikate 5
In: Teine korrus
Classification: 1.11 IfcFurnitureType (mööbel) (BIM ÜBN + Archicad Classification); Material: 80 Siseviim: kummikate
AR_Mööbel - 001_Nimetus: Liftipõrand, kummikate; 900_Tootja: ootel; 905_Mudel: ootel
AC_Pset_RenovationAndPhasing - Renovation Status: New
AR_ÜLD - 009_Märkus: OMA märkus

# IfcFurnishingElement: 80 Siseviim: tolmutõke 100, EM-05
In: Teine korrus
Classification: 1.11 IfcFurnitureType (mööbel) (BIM ÜBN + Archicad Classification); Material: 80 Siseviim: tolmutõke
AR_Mööbel - 001_Nimetus: pink; 900_Tootja: ootel; 905_Mudel: ootel; 002_Tähis: EM-05
Pset_QuantityTakeOff - Reference: EM-05
AR_ÜLD - 009_Märkus: OMA märkus
AC_Pset_RenovationAndPhasing - Renovation Status: New

# IfcFurnishingElement: 80 Siseviim: tolmutõke 20 (7)
In: Teine korrus
Classification: 1.11 IfcFurnitureType (mööbel) (BIM ÜBN + Archicad Classification); Material: 80 Siseviim: tolmutõke
AR_Mööbel - 900_Tootja: ootel; 905_Mudel: ootel; 002_Tähis: EM-10.1B
AR_ÜLD - 009_Märkus: OMA märkus
Pset_QuantityTakeOff - Reference: EM-10.1B
AC_Pset_RenovationAndPhasing - Renovation Status: New
Name | 001_Nimetus
6 x EM-10.1B | Töölaud
EM-10.1B | Nähtav betoon, kaetud tolmutõkkega

# IfcFurnishingElement: 80 Siseviim: tolmutõke 350 (2)
In: Teine korrus
Classification: 1.11 IfcFurnitureType (mööbel) (BIM ÜBN + Archicad Classification); Material: 80 Siseviim: tolmutõke
Pset_QuantityTakeOff - Reference: EM-13
AR_Mööbel - 001_Nimetus: Nähtav betoon, kaetud tolmutõkkega; 900_Tootja: ootel; 905_Mudel: ootel; 002_Tähis: EM-13
AC_Pset_RenovationAndPhasing - Renovation Status: New
AR_ÜLD - 009_Märkus: OMA märkus

# IfcFurnishingElement: 80 Siseviim: tolmutõke 400, EM-05
In: Teine korrus
Classification: 1.11 IfcFurnitureType (mööbel) (BIM ÜBN + Archicad Classification); Material: 80 Siseviim: tolmutõke
AR_Mööbel - 001_Nimetus: pink; 900_Tootja: ootel; 905_Mudel: ootel; 002_Tähis: EM-05
Pset_QuantityTakeOff - Reference: EM-05
AC_Pset_RenovationAndPhasing - Renovation Status: New
AR_ÜLD - 009_Märkus: OMA märkus

# IfcFurnishingElement: 80 Siseviim: tolmutõke 420, EM-15
In: Teine korrus
Classification: 1.11 IfcFurnitureType (mööbel) (BIM ÜBN + Archicad Classification); Material: 80 Siseviim: tolmutõke
AR_Mööbel - 001_Nimetus: pink; 900_Tootja: ootel; 905_Mudel: ootel; 002_Tähis: EM-15
Pset_QuantityTakeOff - Reference: EM-15
AR_ÜLD - 009_Märkus: OMA märkus
AC_Pset_RenovationAndPhasing - Renovation Status: New

# IfcFurnishingElement: 80 Siseviim: tolmutõke 50 (3)
In: Teine korrus
Classification: 1.11 IfcFurnitureType (mööbel) (BIM ÜBN + Archicad Classification); Material: 80 Siseviim: tolmutõke
AR_ÜLD - 009_Märkus: OMA märkus
AC_Pset_RenovationAndPhasing - Renovation Status: New
AR_Mööbel - 001_Nimetus: Nähtav betoon, kaetud tolmutõkkega; 900_Tootja: ootel; 905_Mudel: ootel
Name | Reference = 002_Tähis
EM-15 | EM-15
EM.05 | EM.05
EM-12 | EM-12

# IfcFurnishingElement: 80 Siseviim: tolmutõke 70, EM-15
In: Teine korrus
Classification: 1.11 IfcFurnitureType (mööbel) (BIM ÜBN + Archicad Classification); Material: 80 Siseviim: tolmutõke
AR_ÜLD - 009_Märkus: OMA märkus
AC_Pset_RenovationAndPhasing - Renovation Status: New
AR_Mööbel - 001_Nimetus: Nähtav betoon, kaetud tolmutõkkega; 900_Tootja: ootel; 905_Mudel: ootel; 002_Tähis: EM-15
Pset_QuantityTakeOff - Reference: EM-15

# IfcFurnishingElement: 80 Siseviim: tolmutõke 750 (2)
In: Teine korrus
Classification: 1.11 IfcFurnitureType (mööbel) (BIM ÜBN + Archicad Classification); Material: 80 Siseviim: tolmutõke
AR_Mööbel - 001_Nimetus: Sisseehitatud pink; 900_Tootja: ootel; 905_Mudel: ootel; 002_Tähis: EM-13
Pset_QuantityTakeOff - Reference: EM-13
AR_ÜLD - 009_Märkus: OMA märkus
AC_Pset_RenovationAndPhasing - Renovation Status: New

# IfcFurnishingElement: 80 Siseviimistlus dold 20 (3)
In: Teine korrus
Classification: 1.11 IfcFurnitureType (mööbel) (BIM ÜBN + Archicad Classification); Material: 80 Siseviimistlus dold
AR_Mööbel - 001_Nimetus: Töölaud; 900_Tootja: ootel; 905_Mudel: ootel
AR_ÜLD - 009_Märkus: OMA märkus
AC_Pset_RenovationAndPhasing - Renovation Status: New
Name | 002_Tähis = Reference
EM-10.1B | EM-10.1B
EM-10-2B | EM-10-2B
EM-10.2B | EM-10.2B

# IfcFurnishingElement: 80 must mööbliplaat 1, EM-12
In: Teine korrus
Classification: 1.11 IfcFurnitureType (mööbel) (BIM ÜBN + Archicad Classification); Material: 80 must mööbliplaat
Pset_QuantityTakeOff - Reference: EM-12
AR_Mööbel - 001_Nimetus: Puitribi; 900_Tootja: ootel; 905_Mudel: ootel; 002_Tähis: EM-12
AC_Pset_RenovationAndPhasing - Renovation Status: New

# IfcFurnishingElement: 80 must mööbliplaat 21 (4)
In: Teine korrus
Classification: 1.11 IfcFurnitureType (mööbel) (BIM ÜBN + Archicad Classification); Material: 80 must mööbliplaat
AR_Mööbel - 001_Nimetus: Puitribi; 900_Tootja: ootel; 905_Mudel: ootel
AC_Pset_RenovationAndPhasing - Renovation Status: New
Name | 002_Tähis = Reference
3 x EM-12 | EM-12
EM-13 | EM-13

# IfcFurnishingElement: Base Cabinet Block 26 (7)
In: Teine korrus
Classification: 1.11 IfcFurnitureType (mööbel) (BIM ÜBN + Archicad Classification)
AR_Mööbel - 900_Tootja: ootel; 905_Mudel: ootel
AR_ÜLD - 009_Märkus: OMA märkus
AC_Pset_RenovationAndPhasing - Renovation Status: New
Name | 002_Tähis = Reference
6 x EM-95 | EM-95
EM-08 | EM-08

# IfcFurnishingElement: Bedside Cabinet 26 (15)
Classification: 1.11 IfcFurnitureType (mööbel) (BIM ÜBN + Archicad Classification)
AR_Mööbel - 900_Tootja: Laboriekspert; 905_Mudel: -
AC_Pset_RenovationAndPhasing - Renovation Status: New
AR_ÜLD - 009_Märkus: OMA märkus
Name | In | 001_Nimetus | 002_Tähis = Reference
7 x OMLK-05 | Esimene korrus | Platvormkäru | OMLK-05
OMLK-04 | Esimene korrus | Riiulkäru | OMLK-04
OMLK-03 | Esimene korrus | Käru M | OMLK-03
OMLK-01 | Esimene korrus | Käru rst | OMLK-01
OMLK-02 | Esimene korrus | Töökäru | OMLK-02
4 x OMLK-01 | Teine korrus | Käru rst | OMLK-01

# IfcFurnishingElement: Bench 26 (10)
In: Esimene korrus
Classification: 1.11 IfcFurnitureType (mööbel) (BIM ÜBN + Archicad Classification)
AR_ÜLD - 001_Nimetus: Riietusruumi pink; 009_Märkus: OMA märkus
AR_Mööbel - 001_Nimetus: Istepink; 900_Tootja: Kitman Thulema; 905_Mudel: -
AC_Pset_RenovationAndPhasing - Renovation Status: New
Name | 002_Tähis = Reference
8 x OM-01b | OM-01b
2 x OM-01c | OM-01c

# IfcFurnishingElement: Bookshelf 02 26 (69)
Classification: 1.11 IfcFurnitureType (mööbel) (BIM ÜBN + Archicad Classification)
AR_Mööbel - 905_Mudel: -
AR_ÜLD - 009_Märkus: OMA märkus
AC_Pset_RenovationAndPhasing - Renovation Status: New
Name | In | AR_Mööbel, 001_Nimetus | 900_Tootja | 002_Tähis = Reference
30 x OMLR-04 | Esimene korrus | Kaubaaluste riiulid | Laboriekspert | OMLR-04
OMLR-06 | Esimene korrus | Riiul 90 | Laboriekspert | OMLR-06
4 x OMLR-03 | Esimene korrus | Metallriiul | Laboriekspert | OMLR-03
2 x OMLR-10 | Esimene korrus | Metallriiul 90 | Laboriekspert | OMLR-10
OMSS-02 | Esimene korrus | Stanged | Eritellimus | OMSS-02
OMSS-01 | Esimene korrus | Stanged | Eritellimus | OMSS-01
11 x OMLR-01 | Esimene korrus | Metallriiul 18 | Laboriekspert | OMLR-01
OMR-01 | Esimene korrus | Metall-riiul | Laboriekspert | OMR-01 | AR_ÜLD - 001_Nimetus: Riietusruumi pink
OMSK-04 | Esimene korrus | Riiul | Medkoe | OMSK-04
OMLR-05 | Esimene korrus | Kaubaaluste riiulid | Laboriekspert | OMLR-05
2 x OMLR-04* | Esimene korrus | Kaubaaluste riiulid | Laboriekspert | OMLR-04*
4 x OMLR-07 | Esimene korrus | Metallriiul | Laboriekspert | OMLR-07
2 x OMR-02 | Teine korrus | Metall-riiul | Laboriekspert | OMR-02
4 x OMLR-08 | Teine korrus | Metallriiul 14 | Laboriekspert | OMLR-08
4 x OMLR-09 | Teine korrus | Metallriiul 24x21 | Laboriekspert | OMLR-09

# IfcFurnishingElement: Built-In Fireplace 26 (3)
Classification: 1.11 IfcFurnitureType (mööbel) (BIM ÜBN + Archicad Classification)
AR_ÜLD - 009_Märkus: OMA märkus
AC_Pset_RenovationAndPhasing - Renovation Status: New
Name | In | 001_Nimetus | 900_Tootja | 905_Mudel | 002_Tähis = Reference
THK-01 | Esimene korrus | Tõmbekapp | Medkoe | FC-1500 | THK-01
THK-04 | Teine korrus | Tõmbekapp | Medkoe | FC-1500 | THK-04
THK-01 | Teine korrus | Tõmbekapp FC-1500 | ootel | ootel | THK-01

# IfcFurnishingElement: Chair 10 26 (22)
In: Teine korrus
Classification: 1.11 IfcFurnitureType (mööbel) (BIM ÜBN + Archicad Classification)
AR_Mööbel - 001_Nimetus: Söögillaua toolid; 900_Tootja: Lepo; 905_Mudel: Mikki L-161; 002_Tähis: OM-11
Pset_QuantityTakeOff - Reference: OM-11
AR_ÜLD - 009_Märkus: OMA märkus
AC_Pset_RenovationAndPhasing - Renovation Status: New

# IfcFurnishingElement: Coffee Maker 26
In: Teine korrus
Classification: 1.11 IfcFurnitureType (mööbel) (BIM ÜBN + Archicad Classification)
AR_Mööbel - 001_Nimetus: Kohvimasin; 900_Tootja: ootel; 905_Mudel: -
AC_Pset_RenovationAndPhasing - Renovation Status: New
AR_ÜLD - 009_Märkus: OMA märkus

# IfcFurnishingElement: Cooktop Built-in 26, TH-11
In: Teine korrus
Classification: 1.11 IfcFurnitureType (mööbel) (BIM ÜBN + Archicad Classification)
AR_Mööbel - 001_Nimetus: Integreeritud elektripliit; 900_Tootja: Bosch; 905_Mudel: -; 002_Tähis: TH-11
AR_ÜLD - 009_Märkus: OMA märkus
Pset_QuantityTakeOff - Reference: TH-11
AC_Pset_RenovationAndPhasing - Renovation Status: New

# IfcFurnishingElement: Copier 26
In: Teine korrus
Classification: 1.11 IfcFurnitureType (mööbel) (BIM ÜBN + Archicad Classification)
AR_Uks - 355_Pindala: 0 m2
AR_Mööbel - 001_Nimetus: Multifunktsionaalne printer; 900_Tootja: Canon; 905_Mudel: -
AR_ÜLD - 009_Märkus: OMA märkus
AC_Pset_RenovationAndPhasing - Renovation Status: New

# IfcFurnishingElement: Copier Desktop 26 (3)
In: Teine korrus
Classification: 1.11 IfcFurnitureType (mööbel) (BIM ÜBN + Archicad Classification)
AR_Uks - 355_Pindala: 0 m2
AR_Mööbel - 001_Nimetus: Printer; 900_Tootja: ootel; 905_Mudel: ootel
AR_ÜLD - 009_Märkus: OMA märkus
AC_Pset_RenovationAndPhasing - Renovation Status: New

# IfcFurnishingElement: Cube 26 (189)
Classification: 1.11 IfcFurnitureType (mööbel) (BIM ÜBN + Archicad Classification)
AC_Pset_RenovationAndPhasing - Renovation Status: New
AR_ÜLD - 009_Märkus: OMA märkus
Name | In | 001_Nimetus | 900_Tootja | 905_Mudel | 002_Tähis = Reference
3 x LTH-08 | Esimene korrus | Põrandakaal väike | - | - | LTH-08
4 x LTH-05 | Esimene korrus | Kuivatuskapp | Saro | ootel | LTH-05
3 x LTH-05 | Esimene korrus | Kuivatuskapp | ootel | ootel | LTH-05
OL-01 | Esimene korrus | Segumasin | ootel | ootel | OL-01
LTH-26 | Esimene korrus | Sorteer I | ootel | ootel | LTH-26
OL-03 | Esimene korrus | Lõikeveski | ootel | ootel | OL-03
OL-02 | Esimene korrus | Hõõrel | ootel | ootel | OL-02
LTH-27 | Esimene korrus | Sorteer II | ootel | ootel | LTH-27
LTH-29 | Esimene korrus | Sorteer IV | ootel | ootel | LTH-29
2 x OL-05 | Esimene korrus | Triöör | ootel | ootel | OL-05
OL-06 | Esimene korrus | Tõusev tuul 1 | ootel | ootel | OL-06
LTH-28 | Esimene korrus | Sorteer III | ootel | ootel | LTH-28
OL-07 | Esimene korrus | Tõusev tuul 2 | ootel | ootel | OL-07
3 x LTH-07 | Esimene korrus | Põrandakaal | - | - | LTH-07
 | Esimene korrus | Esmaabikapp | ootel | ootel
LTH-19 | Esimene korrus | Loksuti | ootel | ootel | LTH-19
LTH-14 | Esimene korrus | EC seade | ootel | ootel | LTH-14
LTH-11 | Esimene korrus | Laborikaal lauakaal I | ootel | ootel | LTH-11
LTH-15 | Esimene korrus | Gaaside mõõtmise komplekt C | ootel | ootel | LTH-15
LTH-04 | Esimene korrus | Kuivatuskapp L | Saro | ootel | LTH-04
LTH-20 | Esimene korrus | Sõelte süsteem raputusseadmega | ootel | ootel | LTH-20
26 x  | Esimene korrus | El.karbik | ootel | ootel
2 x  | Esimene korrus | Tõstuk | ootel | ootel
LTH-16 | Esimene korrus | Gaaside mõõtmise komplekt N | ootel | ootel | LTH-16
OL-04 | Esimene korrus | Hõõrel LD | ootel | ootel | OL-04
LTH-30 | Esimene korrus | Separaator LA-K | ootel | ootel | LTH-30
LTH-31 | Esimene korrus | Seemne kalibreerija | ootel | ootel | LTH-31
LTH-07 | Esimene korrus | Põrandakaal | ootel | ootel | LTH-07
 | Esimene korrus | JK2.2 | ootel | ootel
AK-12 | Esimene korrus | Tööriista hoidik seinale 4ne | Bobrick | - | AK-12
2 x  | Esimene korrus | Helipidav siirdeõhurest | ootel | ootel
LTH-17 | Esimene korrus | Mullaveepotentsiaali mõõtmise seade | ootel | ootel | LTH-17
LTH-18 | Esimene korrus | HYPROP 2 komplekt | ootel | ootel | LTH-18
2 x THK-02 | Esimene korrus | Kasvukamber FITOCLIMA 12000 | Fitoklima | Fitoclima 12000 | THK-02
THK-03 | Esimene korrus | Kasvukamber Fitoclima 5000 | Fitoklima | Fitoclima 5000 | THK-03
2 x  | Esimene korrus | Kasvukamber | ootel | ootel
LTH-33 | Esimene korrus | Magnetsorteer | ootel | ootel | LTH-33
LTH-34 | Esimene korrus | Spiraalseparaator | ootel | ootel | LTH-34
AK-16 | Esimene korrus | Prügikast | Thulema | Ditch | AK-16
LTH-35 | Esimene korrus | Digitaalne mikroskoop | ootel | ootel | LTH-35
LTH-36 | Esimene korrus | Seemnete ja bakterkultuuride granuleerimise seade laboris | ootel | ootel | LTH-36
LTH-32 | Esimene korrus | Seemnepesumasin | ootel | ootel | LTH-32
LTH-22 | Esimene korrus | Silohekseldi | ootel | ootel | LTH-22
LTH-25 | Esimene korrus | Pelletipress | ootel | ootel | LTH-25
LTH-24 | Esimene korrus | Seemneluger | ootel | ootel | LTH-24
LTH-23 | Esimene korrus | Lõikeveski | ootel | ootel | LTH-23
11 x  | Teine korrus | El.karbik | ootel | ootel
OL-09 | Teine korrus | Plaaditsentrifuug | ootel | ootel | OL-09
2 x LTH-41 | Teine korrus | Autoklaav | ootel | ootel | LTH-41
4 x OL-11 | Teine korrus | Laminaarkapp | ootel | ootel | OL-11
THL-67 | Teine korrus | MQ veemasin | ootel | ootel | THL-67
2 x LTH-66 | Teine korrus | PCR box | ootel | ootel | LTH-66
LTH-73 | Teine korrus | Nanodrop | ootel | ootel | LTH-73
5 x THL-01 | Teine korrus | UV-C strerilisaator | Lightprogress | - | THL-01
2 x LTH-62 | Teine korrus | Lauatsentrifuug, külmutusega | ootel | ootel | LTH-62
LTH-53 | Teine korrus | Geelelektroforeesi vann | ootel | ootel | LTH-53
3 x LTH-55 | Teine korrus | DNA fragmentanalüsaator | ootel | ootel | LTH-55
LTH-54 | Teine korrus | Geeliilmuti | ootel | ootel | LTH-54
2 x LTH-70 | Teine korrus | Termostaadiga magnetsegaja | ootel | ootel | LTH-70
4 x LTH-71 | Teine korrus | Termoblokk-loksuti | ootel | ootel | LTH-71
7 x LTH-64 | Teine korrus | Vortex spinner | ootel | ootel | LTH-64
LTH-56 | Teine korrus | PCR | ootel | ootel | LTH-56
LTH-58 | Teine korrus | qPCR | ootel | ootel | LTH-58
2 x LTH-81 | Teine korrus | Kuivatuskapp M | Saro | ootel | LTH-81
2 x LTH-59 | Teine korrus | PCR | ootel | ootel | LTH-59
2 x  | Teine korrus | Tuletekk | ootel | ootel
 | Teine korrus | Esmaabikapp | ootel | ootel
LTH-76 | Teine korrus | Homogenisaator | ootel | ootel | LTH-76
LTH-77 | Teine korrus | lauatsentrifuug | ootel | ootel | LTH-77
2 x LTH-72 | Teine korrus | Termoblokk | ootel | ootel | LTH-72
2 x LTH-75 | Teine korrus | Termokapp/inkubaator | ootel | ootel | LTH-75
LTH-74 | Teine korrus | Vortex mikser | ootel | ootel | LTH-74
LTH-82 | Teine korrus | Jäämasin | ootel | ootel | LTH-82
LTH-68 | Teine korrus | lüofilisaator+pump | ootel | ootel | LTH-68
2 x LTH-43 | Teine korrus | magnetsegajad | ootel | ootel | LTH-43
LTH-44 | Teine korrus | pH-meeter | ootel | ootel | LTH-44
3 x LTH-40 | Teine korrus | Kasvukamber | ootel | ootel | LTH-40
LTH-78 | Teine korrus | Laminaarkapp | ootel | ootel | LTH-78
LTH-37 | Teine korrus | Voolutsütomeeter | ootel | ootel | LTH-37
LTH-49 | Teine korrus | Aurugeneraator | ootel | ootel | LTH-49
THL-43 | Teine korrus | Reaktor | ootel | ootel | THL-43
LTH-48 | Teine korrus | Tsentrifugaalsõel/hüdrotsüklon | ootel | ootel | LTH-48
LTH-46 | Teine korrus | Desintegraator veski | ootel | ootel | LTH-46
LTH-44 | Teine korrus | Platseparaator | ootel | ootel | LTH-44
LTH-45 | Teine korrus | Dekanter | ootel | ootel | LTH-45
LTH-47 | Teine korrus | Keevkiht kuivati | ootel | ootel | LTH-47
LTH-86 | Teine korrus | Plaadikleepsutaja | ootel | ootel | LTH-86
 | Teine korrus | Õli rafineerimise seadmestik | ootel | ootel
LTH-42 | Teine korrus | Rasvaeraldamise liin | ootel | ootel | LTH-42
4 x LTH-38 | Teine korrus | Mikropõleti | ootel | ootel | LTH-38
AK-12 | Teine korrus | Tööriista hoidik seinale 4ne | Bobrick | - | AK-12
LTH-12 | Teine korrus | Analüütiline kaal | ootel | ootel | LTH-12
2 x LTH-83 | Teine korrus | UV-C strerilisaator | Lightprogress | - | LTH-83
LTH-52 | Teine korrus | Geelelektroforeesi vooluplokk | ootel | ootel | LTH-52
LTH-39 | Teine korrus | Laminaarkapp | ootel | ootel | LTH-39
LTH-13 | Teine korrus | Lauakaal | ootel | ootel | LTH-13
LTH-10 | Teine korrus | Fuug | ootel | ootel | LTH-10
LTH-50 | Teine korrus | Kuivaine määraja | ootel | ootel | LTH-50
LTH-85 | Teine korrus | Kuulikestel põhinev DNA eraldusrobot | ootel | ootel | LTH-85
OL-08 | Teine korrus | Fluorestsents-plaadilugeja | ootel | ootel | OL-08
AK-15 | Teine korrus | Prügikast | Thulema | Ditch | AK-15
2 x AK-16 | Teine korrus | Prügikast | Thulema | Ditch | AK-16
LTH-79 | Teine korrus | pH meeter | ootel | ootel | LTH-79
LTH-61 | Teine korrus | Pipeteerimisrobot | ootel | ootel | LTH-61
OL-10 | Teine korrus | Loksuti | ootel | ootel | OL-10

# IfcFurnishingElement: Cupboard 26 (38)
Classification: 1.11 IfcFurnitureType (mööbel) (BIM ÜBN + Archicad Classification)
AC_Pset_RenovationAndPhasing - Renovation Status: New
AR_ÜLD - 009_Märkus: OMA märkus
Name | In | 001_Nimetus | 900_Tootja | 905_Mudel | 002_Tähis = Reference
4 x OML-05b | Esimene korrus | Riidekapp | Medkoe | WD-09 | OML-05b
8 x OML-05d | Esimene korrus | Hoiukapp | Medkoe | WD-09 | OML-05d
6 x OML-05c | Esimene korrus | Kor.kapp | Medkoe | WD-09 | OML-05c
OML-05b | Esimene korrus | Hoiukapp | Medkoe | WB-0,9 | OML-05b
OML-05c | Esimene korrus | Kor.kapp | Medkoe | WB-0,9 | OML-05c
4 x OML-24 | Teine korrus | Kapp | ootel | ootel | OML-24
8 x OML-05 | Teine korrus | Hoiukapp | ootel | ootel | OML-05
3 x OML-05d | Teine korrus | Ratastel hoiukapp | ootel | ootel | OML-05d
2 x OML-05e | Teine korrus | Klaasustega kapp | ootel | ootel | OML-05e
OML-26 | Teine korrus | Vent. kem. hoiukapp | ootel | ootel | OML-26

# IfcFurnishingElement: Curtain 26 (7)
In: Teine korrus
Classification: 1.11 IfcFurnitureType (mööbel) (BIM ÜBN + Archicad Classification)
AR_Mööbel - 900_Tootja: Texstudio; 905_Mudel: -
AR_ÜLD - 009_Märkus: OMA märkus
AC_Pset_RenovationAndPhasing - Renovation Status: New
Name | 001_Nimetus | 002_Tähis = Reference
2 x K-01 | Nõupidamiste ruumi vabalt langev kardin | K-01
K-05 | Puhkenurgas vabalt langev kardin | K-05
K-02 | Nõupidamiste ruumi vabalt langev kardin | K-02
K-04 | Puhkenurgas vabalt langev kardin | K-04
K-07 | Puhkenurgas vabalt langev kardin | K-07
K-06 | Puhkenurgas vabalt langev kardin | K-06

# IfcFurnishingElement: Cylinder 26 (12)
Classification: 1.11 IfcFurnitureType (mööbel) (BIM ÜBN + Archicad Classification)
AR_Mööbel - 900_Tootja: -; 905_Mudel: -
AR_ÜLD - 009_Märkus: OMA märkus
AC_Pset_RenovationAndPhasing - Renovation Status: New
Name | In | 001_Nimetus | 002_Tähis = Reference
11 x LTH-09 | Esimene korrus | Tolmuimeja | LTH-09
LTH-84 | Teine korrus | Kuulikestel põhinev DNA eraldusrobot | LTH-84

# IfcFurnishingElement: Dining Table Rectangle 26 (6)
In: Teine korrus
Classification: 1.11 IfcFurnitureType (mööbel) (BIM ÜBN + Archicad Classification)
AR_ÜLD - 009_Märkus: OMA märkus
AC_Pset_RenovationAndPhasing - Renovation Status: New
Name | 001_Nimetus | 900_Tootja | 905_Mudel | 002_Tähis = Reference
2 x OM-13 | Koosolekute laud | Narbutas | Nova | OM-13
4 x OM-15 | Söögilaud | Pederali | Arki | OM-15

# IfcFurnishingElement: Dishwasher Built-in 26 (7)
Classification: 1.11 IfcFurnitureType (mööbel) (BIM ÜBN + Archicad Classification)
AR_ÜLD - 009_Märkus: OMA märkus
AC_Pset_RenovationAndPhasing - Renovation Status: New
Name | In | 001_Nimetus | 900_Tootja | 905_Mudel | 002_Tähis = Reference
3 x LTH-10 | Esimene korrus | Nõudepesumasin | Electrolux | - | LTH-10
THL-06 | Esimene korrus | Labori nõudepesumasin | ootel | ootel | THL-06
THL-01 | Esimene korrus | Nõudepesumasin | Electrolux | ootel | THL-01
TH-06 | Teine korrus | Integreeritud nõudepesumasin | Electrolux | - | TH-06
THL-06 | Teine korrus | NPL | ootel | ootel | THL-06

# IfcFurnishingElement: ELLY - Chair with five star base and height adjustment (83)
Classification: 1.11 IfcFurnitureType (mööbel) (BIM ÜBN + Archicad Classification)
AC_Pset_RenovationAndPhasing - Renovation Status: New
AR_ÜLD - 009_Märkus: OMA märkus
AR_Mööbel - 001_Nimetus: Laboritool; 900_Tootja: Bimos; 905_Mudel: NEON 9576E
Name | In | Reference = 002_Tähis
49 x OLT-01 | Esimene korrus | OLT-01
6 x OLT-05 | Esimene korrus | OLT-05
17 x OLT-05 | Teine korrus | OLT-05
3 x OLT-03 | Teine korrus | OLT-03
OLT-04 | Teine korrus | OLT-04
7 x OLT-06 | Teine korrus | OLT-06

# IfcFurnishingElement: Europaleta (79)
In: Esimene korrus
Classification: 1.11 IfcFurnitureType (mööbel) (BIM ÜBN + Archicad Classification)
AR_Mööbel - 900_Tootja: ootel; 905_Mudel: ootel
AR_ÜLD - 009_Märkus: OMA märkus
AC_Pset_RenovationAndPhasing - Renovation Status: New
Name | 001_Nimetus
28 x  | Toodang
43 x  | Euroalus
8 x  | Tooraine

# IfcFurnishingElement: FACE - Table screen (26)
In: Teine korrus
Classification: 1.11 IfcFurnitureType (mööbel) (BIM ÜBN + Archicad Classification)
AR_Mööbel - 001_Nimetus: Lauasirm; 900_Tootja: Thulema; 905_Mudel: -
AC_Pset_RenovationAndPhasing - Renovation Status: New
AR_ÜLD - 009_Märkus: OMA märkus
Name | 002_Tähis = Reference
18 x OM-17a | OM-17a
8 x OM-17b | OM-17b

# IfcFurnishingElement: Flat Panel TV 26 (3)
In: Teine korrus
Classification: 1.11 IfcFurnitureType (mööbel) (BIM ÜBN + Archicad Classification)
AR_Mööbel - 001_Nimetus: Ekraan 75"; 900_Tootja: -; 905_Mudel: -
AR_ÜLD - 009_Märkus: OMA märkus
AC_Pset_RenovationAndPhasing - Renovation Status: New
Name | 002_Tähis = Reference
2 x TH-12 | TH-12
TH-13 | TH-13

# IfcFurnishingElement: Furniture_Chairs-Stools-Benches_Enea_Ema-chair (23)
In: Teine korrus
Classification: 1.11 IfcFurnitureType (mööbel) (BIM ÜBN + Archicad Classification)
AR_Mööbel - 001_Nimetus: Koosolekute tool; 900_Tootja: Enea; 905_Mudel: Ema
AR_ÜLD - 009_Märkus: OMA märkus
AC_Pset_RenovationAndPhasing - Renovation Status: New
Name | 002_Tähis = Reference
21 x OM-07 | OM-07
2 x OM-07b | OM-07b

# IfcFurnishingElement: Furniture_Sofas-Armchairs_Fritz-Hansen_Alphabet-SofaT-Series-PL300-3 (2)
In: Teine korrus
Classification: 1.11 IfcFurnitureType (mööbel) (BIM ÜBN + Archicad Classification)
AR_ÜLD - 009_Märkus: OMA märkus
AC_Pset_RenovationAndPhasing - Renovation Status: New
Name | 900_Tootja | 905_Mudel | 002_Tähis = Reference
OM-10 | Bellus | Infinity | OM-10 | AR_Mööbel - 001_Nimetus: Mooduldiivan
D1 | ootel | ootel | D1

# IfcFurnishingElement: Grab Bar 26, AK-08
In: Esimene korrus
Classification: 1.11 IfcFurnitureType (mööbel) (BIM ÜBN + Archicad Classification)
AR_Mööbel - 001_Nimetus: Inva käetugi seinale; 900_Tootja: Mediclinics; 905_Mudel: -; 002_Tähis: AK-1
Pset_QuantityTakeOff - Reference: AK-1
AC_Pset_RenovationAndPhasing - Renovation Status: New
AR_ÜLD - 009_Märkus: OMA märkus

# IfcFurnishingElement: Hood 26 (8)
Classification: 1.11 IfcFurnitureType (mööbel) (BIM ÜBN + Archicad Classification)
AR_ÜLD - 009_Märkus: OMA märkus
AC_Pset_RenovationAndPhasing - Renovation Status: New
Name | In | 001_Nimetus | 900_Tootja | 905_Mudel
7 x  | Esimene korrus | Kubu | ootel | ootel
TH-15 | Teine korrus | Lae-õhupuhastaja söefiltriga | SIRIUS | - | AR_Mööbel - 002_Tähis: TH-15; Pset_QuantityTakeOff - Reference: TH-15

# IfcFurnishingElement: Houseplant Model 26 (10)
In: Teine korrus
Classification: 1.11 IfcFurnitureType (mööbel) (BIM ÜBN + Archicad Classification)
AR_Uks - 355_Pindala: 0 m2
AR_Mööbel - 900_Tootja: ootel; 905_Mudel: ootel; 002_Tähis: SRD-08
Pset_QuantityTakeOff - Reference: SRD-08
AR_ÜLD - 009_Märkus: OMA märkus
AC_Pset_RenovationAndPhasing - Renovation Status: New

# IfcFurnishingElement: JUNG LS 990 4-gang (4)
In: Teine korrus
Classification: 1.11 IfcFurnitureType (mööbel) (BIM ÜBN + Archicad Classification)
AR_Mööbel - 900_Tootja: ootel; 905_Mudel: ootel; 002_Tähis: MÖÖBEL
AC_Pset_RenovationAndPhasing - Renovation Status: New
AR_ÜLD - 009_Märkus: OMA märkus
Pset_QuantityTakeOff - Reference: MÖÖBEL

# IfcFurnishingElement: JUNG LS 990 5-gang (18)
In: Teine korrus
Classification: 1.11 IfcFurnitureType (mööbel) (BIM ÜBN + Archicad Classification)
AR_Mööbel - 900_Tootja: ootel; 905_Mudel: ootel; 002_Tähis: MÖÖBEL
Pset_QuantityTakeOff - Reference: MÖÖBEL
AR_ÜLD - 009_Märkus: OMA märkus
AC_Pset_RenovationAndPhasing - Renovation Status: New

# IfcFurnishingElement: Keyboard (Apple) 26 (40)
Classification: 1.11 IfcFurnitureType (mööbel) (BIM ÜBN + Archicad Classification)
AR_Mööbel - 900_Tootja: ootel; 905_Mudel: ootel
AR_ÜLD - 009_Märkus: OMA märkus
AC_Pset_RenovationAndPhasing - Renovation Status: New
Name | In | 001_Nimetus | 355_Pindala (m2) | 002_Tähis = Reference
8 x  | Esimene korrus | Klaviatuur
26 x M-02 | Teine korrus | Klaviatuur | 0 | M-02
4 x  | Teine korrus | Klaviatuur
2 x SRD-13 | Teine korrus |  | 0 | SRD-13

# IfcFurnishingElement: Lab Nõudekuivatusrest 3 (33)
Classification: 1.11 IfcFurnitureType (mööbel) (BIM ÜBN + Archicad Classification); Material: 01 ÜLD: projekteeritav
AR_Mööbel - 001_Nimetus: Nõudekuivatusrest
AR_ÜLD - 009_Märkus: OMA märkus
AC_Pset_RenovationAndPhasing - Renovation Status: New
Name | In | 900_Tootja | 905_Mudel | 002_Tähis = Reference
8 x OML-10b | Esimene korrus | Medkoe | - | OML-10b
13 x OML-10a | Teine korrus | ootel | ootel | OML-10a
8 x OML-10b | Teine korrus | ootel | ootel | OML-10b
EML-01 | Teine korrus | ootel | ootel | EML-01
2 x OML-10c | Teine korrus | ootel | ootel | OML-10c
 | Teine korrus | ootel | ootel

# IfcFurnishingElement: Laboratory Workstation 26 (117)
Classification: 1.11 IfcFurnitureType (mööbel) (BIM ÜBN + Archicad Classification)
AC_Pset_RenovationAndPhasing - Renovation Status: New
AR_ÜLD - 009_Märkus: OMA märkus
Name | In | 001_Nimetus | 900_Tootja | 905_Mudel | 002_Tähis = Reference
OML-12 | Esimene korrus | Töölaud 15 | Medkoe | LB-1,5 | OML-12
3 x OML-18 | Esimene korrus | Valguslaud | Medkoe | - | OML-18
5 x OML-31 | Esimene korrus | Laborilaud 15 | Medkoe | LB-1,5 | OML-31
3 x OML-09* | Esimene korrus | Kesklaud | Medkoe | Athla-SM15 | OML-09*
OML-03 | Esimene korrus | Töölaud | ootel | ootel | OML-03
2 x THK-05 | Esimene korrus | Eriotstarbeline laud | Kemper | - | THK-05
3 x OML-03* | Esimene korrus | Laborilaud 18 | Medkoe | LB-1,8 | OML-03*
9 x OML-03 | Esimene korrus | Laborilaud 18 | Medkoe | LB-1,8 | OML-03
3 x OML-29* | Esimene korrus | Laborilaud 18 | Medkoe | LB-1,8 | OML-29*
13 x OML-08* | Esimene korrus | Kesklaud | Medkoe | Athla-SM15 | OML-08*
OML-28 | Esimene korrus | Laborilaud 18 | Medkoe | LB-1,8 | OML-28
2 x OML-02 | Esimene korrus | Laborilaud 12 | Medkoe | LB-1,2 | OML-02
OML-07 | Esimene korrus | Laborilaud 15 | Medkoe | LB-1,5 | OML-07
OML-07 | Esimene korrus | Laborilaud 12 | Medkoe | LB-1,2 | OML-07
2 x OML-09 | Esimene korrus | Kesklaud | Medkoe | Athla-SM15 | OML-09
OML-19 | Esimene korrus | Töölaud metall tööde jaoks | Medkoe | - | OML-19
OML-12 | Esimene korrus | Töölaud | Medkoe | ootel | OML-12
3 x OML-29 | Esimene korrus | Laborilaud 12 | Medkoe | LB-1,2 | OML-29
2 x OML-08 | Esimene korrus | Kesklaud | Medkoe | Athla-SM15 | OML-08
 | Esimene korrus | Laborilaud 15 | Medkoe | LB-1,5
OML-03* | Esimene korrus | Arvutilaud | Medkoe | LB-1,8 | OML-03*
10 x OML-09 | Teine korrus | Tööpind riiulitega | ootel | ootel | OML-09
5 x OML-007 | Teine korrus | Laminaarkapp | ootel | ootel | OML-007
8 x OML-20 | Teine korrus | Laborilaud sahtlitega | Medkoe | - | OML-20
2 x OML-29 | Teine korrus | Standup desk | ootel | ootel | OML-29
11 x OML-21 | Teine korrus | Töölaud | ootel | ootel | OML-21
3 x OML-28 | Teine korrus | Proovide laud | ootel | ootel | OML-28
OML-02 | Teine korrus | Laborilaud 12 | Medkoe | LB-1,2 | OML-02
2 x OML-02 | Teine korrus | Laborilaud 15 | Medkoe | LB-1,5 | OML-02
 | Teine korrus | Proovide laud | ootel | ootel
2 x OML-23 | Teine korrus | Teenindusmooduliga laborilaud | ootel | ootel | OML-23
OML-23 | Teine korrus | Töölaud | ootel | ootel | OML-23
2 x OML-23 | Teine korrus | Arvutilaud | ootel | ootel | OML-23
6 x OML-23 | Teine korrus | Laborilaud | Medkoe | - | OML-23
OML-21 | Teine korrus | Töölaud sahtlitega | ootel | ootel | OML-21
OML-27 | Teine korrus | Laud 800 | ootel | ootel | OML-27
2 x  | Teine korrus | Töölaud | ootel | ootel

# IfcFurnishingElement: Lockers 26 (21)
In: Esimene korrus
Classification: 1.11 IfcFurnitureType (mööbel) (BIM ÜBN + Archicad Classification)
AC_Pset_RenovationAndPhasing - Renovation Status: New
AR_ÜLD - 009_Märkus: OMA märkus
Name | 001_Nimetus | 900_Tootja | 905_Mudel | 002_Tähis = Reference
16 x OM-01 | Vahetusriiete kapp 2/400 | Kitman Thulema | - | OM-01
4 x TH-04 | Kuivatuskapp | Nimo | - | TH-04
EM-02 | Kapp |  |  | EM-02

# IfcFurnishingElement: Medical Cart 26 (2)
In: Esimene korrus
Classification: 1.11 IfcFurnitureType (mööbel) (BIM ÜBN + Archicad Classification)
AR_Mööbel - 900_Tootja: Medkoe
AC_Pset_RenovationAndPhasing - Renovation Status: New
AR_ÜLD - 009_Märkus: OMA märkus
Name | 001_Nimetus | 905_Mudel | 002_Tähis = Reference
OML-16 | Ratastel laud väike | RL-02 | OML-16
OML-17 | Ratastel laud suur | RL-01 | OML-17

# IfcFurnishingElement: Microwave Oven 26, LTH-51
In: Teine korrus
Classification: 1.11 IfcFurnitureType (mööbel) (BIM ÜBN + Archicad Classification)
AR_Uks - 355_Pindala: 0 m2
AR_Mööbel - 001_Nimetus: Mikro; 900_Tootja: Electrolux; 905_Mudel: ootel; 002_Tähis: LTH-51
Pset_QuantityTakeOff - Reference: LTH-51
AR_ÜLD - 009_Märkus: OMA märkus
AC_Pset_RenovationAndPhasing - Renovation Status: New

# IfcFurnishingElement: Mirror 26 (9)
Classification: 1.11 IfcFurnitureType (mööbel) (BIM ÜBN + Archicad Classification)
AR_Mööbel - 905_Mudel: -
AR_ÜLD - 009_Märkus: OMA märkus
Name | In | 001_Nimetus | 900_Tootja | 002_Tähis = Reference | Renovation Status
PL-05 | Esimene korrus | Peegel riietusruumis | Eritellimus | PL-05 | Existing
2 x PL-03 | Esimene korrus | Peegel | Eritellimus | PL-03 | Existing
PL-04 | Esimene korrus | Peegel riietusruumis | Eritellimus | PL-04 | Existing
2 x PL-03 | Teine korrus | Peegel WC´S | Eritellimus | PL-03 | Existing
2 x PL-02 | Teine korrus | Distantsiga peegel WC´s | - | PL-02 | Existing
PL-06 | Teine korrus | Peegel koridoris | Eritellimus | PL-06 | New

# IfcFurnishingElement: Mouse (Apple) 26 (12)
Classification: 1.11 IfcFurnitureType (mööbel) (BIM ÜBN + Archicad Classification)
AR_ÜLD - 009_Märkus: OMA märkus
AC_Pset_RenovationAndPhasing - Renovation Status: New
AR_Mööbel - 001_Nimetus: Hiir; 900_Tootja: ootel; 905_Mudel: ootel
Name | In
8 x  | Esimene korrus
4 x  | Teine korrus

# IfcFurnishingElement: Office Chair 04 26 (29)
In: Teine korrus
Classification: 1.11 IfcFurnitureType (mööbel) (BIM ÜBN + Archicad Classification)
AR_Mööbel - 001_Nimetus: Töötool; 900_Tootja: Thulema; 905_Mudel: Sense; 002_Tähis: OM-05
Pset_QuantityTakeOff - Reference: OM-05
AR_ÜLD - 009_Märkus: OMA märkus
AC_Pset_RenovationAndPhasing - Renovation Status: New

# IfcFurnishingElement: Office Table 26 (5)
In: Esimene korrus
Classification: 1.11 IfcFurnitureType (mööbel) (BIM ÜBN + Archicad Classification)
AR_Mööbel - 900_Tootja: Medkoe
AR_ÜLD - 009_Märkus: OMA märkus
AC_Pset_RenovationAndPhasing - Renovation Status: New
Name | 001_Nimetus | 905_Mudel | 002_Tähis = Reference
4 x OML-16 | Ratastel laud väike | RL-02 | OML-16
OML-17 | Ratastel laud suur | RL-01 | OML-17

# IfcFurnishingElement: Open stainless steel bin PP0279x (3)
In: Esimene korrus
Classification: 1.11 IfcFurnitureType (mööbel) (BIM ÜBN + Archicad Classification)
AR_Mööbel - 001_Nimetus: Seinakinnitusega suur prugikast; 900_Tootja: JNF; 905_Mudel: Industrial; 002_Tähis: AK-01.1
Pset_ManufacturerOccurrence - SerialNumber: PP0279C
Pset_ManufacturerTypeInformation - Manufacturer: Mediclinics
Pset_QuantityTakeOff - Reference: AK-01.1
AR_ÜLD - 009_Märkus: OMA märkus
AC_Pset_RenovationAndPhasing - Renovation Status: Existing

# IfcFurnishingElement: Oven Built-in 26 (2)
In: Teine korrus
Classification: 1.11 IfcFurnitureType (mööbel) (BIM ÜBN + Archicad Classification)
AR_Mööbel - 001_Nimetus: Integreeritud kombineeritud mikrolaineahi ja ahi; 900_Tootja: Electrolux; 905_Mudel: -; 002_Tähis: TH-07
Pset_QuantityTakeOff - Reference: TH-07
AR_ÜLD - 009_Märkus: OMA märkus
AC_Pset_RenovationAndPhasing - Renovation Status: New

# IfcFurnishingElement: Partition Panel 26 (5)
In: Esimene korrus
Classification: 1.11 IfcFurnitureType (mööbel) (BIM ÜBN + Archicad Classification)
AR_Mööbel - 001_Nimetus: Dušiklaas; 900_Tootja: Eritellimus; 905_Mudel: -; 002_Tähis: DS-01
Pset_QuantityTakeOff - Reference: DS-01
AR_ÜLD - 009_Märkus: OMA märkus
AC_Pset_RenovationAndPhasing - Renovation Status: Existing

# IfcFurnishingElement: Piano Stool 26 (15)
Classification: 1.11 IfcFurnitureType (mööbel) (BIM ÜBN + Archicad Classification)
AR_ÜLD - 009_Märkus: OMA märkus
AC_Pset_RenovationAndPhasing - Renovation Status: New
Name | In | 001_Nimetus | 900_Tootja | 905_Mudel | 002_Tähis = Reference
OLT-06 | Esimene korrus | Labori sadultool | Bimos | Stool 9473E | OLT-06
4 x OM-12 | Teine korrus | Söögisaare pukid | Enea | Stool coma | OM-12
4 x OLT-04 | Teine korrus | Labori sadultool | Bimos | Stool 9473E | OLT-04
6 x OLT-06 | Teine korrus | Labori sadultool | Bimos | Stool 9473E | OLT-06

# IfcFurnishingElement: Picture 26 (2)
Classification: 1.11 IfcFurnitureType (mööbel) (BIM ÜBN + Archicad Classification)
AR_ÜLD - 009_Märkus: OMA märkus
AC_Pset_RenovationAndPhasing - Renovation Status: New
Name | In | 900_Tootja | 905_Mudel
 | Esimene korrus | Paa baths | Flow 450 | AR_Mööbel - 001_Nimetus: Seinakinnitusega valamu
SRD-06 | Teine korrus | ootel | ootel | AR_Uks - 355_Pindala: 0 m2; AR_Mööbel - 002_Tähis: SRD-06; Pset_QuantityTakeOff - Reference: SRD-06

# IfcFurnishingElement: Portus easychair (2)
In: Teine korrus
Classification: 1.11 IfcFurnitureType (mööbel) (BIM ÜBN + Archicad Classification)
AR_Mööbel - 001_Nimetus: Tugitool; 900_Tootja: Pederali; 905_Mudel: Buddyhub; 002_Tähis: OM-16
Pset_ManufacturerTypeInformation - Manufacturer: Lammhults
Pset_QuantityTakeOff - Reference: OM-16
AR_ÜLD - 009_Märkus: OMA märkus
AC_Pset_RenovationAndPhasing - Renovation Status: New

# IfcFurnishingElement: Pressurized Extinguisher 26 (12)
Classification: 1.11 IfcFurnitureType (mööbel) (BIM ÜBN + Archicad Classification)
AR_Mööbel - 900_Tootja: ootel; 905_Mudel: ootel; 002_Tähis: Tulekustuti
Pset_QuantityTakeOff - Reference: Tulekustuti
AR_ÜLD - 009_Märkus: OMA märkus
AC_Pset_RenovationAndPhasing - Renovation Status: New
Name | In
6 x Tulekustuti | Esimene korrus
6 x Tulekustuti | Teine korrus

# IfcFurnishingElement: RH-01 (11)
In: Esimene korrus
Classification: 1.11 IfcFurnitureType (mööbel) (BIM ÜBN + Archicad Classification); Material: 40 Kiht: Teras, 44 Konst: Alumiinium
Pset_QuantityTakeOff - Reference: RH-01
AC_Pset_RenovationAndPhasing - Renovation Status: New
AR_Mööbel - 001_Nimetus: Rattahoidja; 900_Tootja: ootel; 905_Mudel: ootel; 002_Tähis: RH-01

# IfcFurnishingElement: Rectangular Table 01 26 (7)
Classification: 1.11 IfcFurnitureType (mööbel) (BIM ÜBN + Archicad Classification)
AR_ÜLD - 009_Märkus: OMA märkus
AC_Pset_RenovationAndPhasing - Renovation Status: New
Name | In | 001_Nimetus | 900_Tootja | 905_Mudel | 002_Tähis = Reference
2 x OML-06 | Esimene korrus | Kaalulaud | Medkoe | WB-0,9 | OML-06
OM-14 | Teine korrus | Abilaud | Pederali | Arki | OM-14
3 x OM-18 | Teine korrus | Koosolekute laud | Enea | Iron | OM-18
OML-06 | Teine korrus | Kaalulaud | ootel | ootel | OML-06

# IfcFurnishingElement: Refrigerator 26 (40)
Classification: 1.11 IfcFurnitureType (mööbel) (BIM ÜBN + Archicad Classification)
AC_Pset_RenovationAndPhasing - Renovation Status: New
AR_ÜLD - 009_Märkus: OMA märkus
Name | In | 001_Nimetus | 900_Tootja | 905_Mudel | 002_Tähis = Reference
LTH-01 | Esimene korrus | Labori külmik 4C | ootel | ootel | LTH-01
6 x LTH-02 | Esimene korrus | Laiem labori külmik 4C | Saro | - | LTH-02
9 x LTH-01 | Esimene korrus | Labori külmik 4C | Saro | - | LTH-01
2 x LTH-03 | Esimene korrus | Kuivatuskapp S | Saro | ootel | LTH-03
LTH-02 | Esimene korrus | Laiem labori külmik 4C | Saro | ootel | LTH-02
2 x LTH-06 | Esimene korrus | Labori külmik 4C | Saro | - | LTH-06
LTH-21 | Esimene korrus | Labori külmik 4C | Saro | - | LTH-21
5 x LTH-06 | Teine korrus | Labori külmik 4C | Saro | - | LTH-06
2 x THL-69 | Teine korrus | Labori külmik 4C | Saro | - | THL-69
2 x LTH-01 | Teine korrus | Labori külmik 4C | Saro | - | LTH-01
2 x TH-09 | Teine korrus | Integreeritav külmik | Electrolux | - | TH-09
6 x LTH-80 | Teine korrus | Labori külmik 4C | Saro | - | LTH-80
LTH-06 | Teine korrus | Labori külmik 4C | Saro | ootel | LTH-06

# IfcFurnishingElement: Riiul 16(2), EM-09-4
In: Teine korrus
Classification: 1.11 IfcFurnitureType (mööbel) (BIM ÜBN + Archicad Classification); Material: 01 ÜLD: projekteeritav, 80 Siseviimistlus dold
AR_Mööbel - 001_Nimetus: Riiul; 900_Tootja: ootel; 905_Mudel: ootel; 002_Tähis: EM-09-4
Pset_QuantityTakeOff - Reference: EM-09-4
AR_ÜLD - 009_Märkus: OMA märkus
AC_Pset_RenovationAndPhasing - Renovation Status: New

# IfcFurnishingElement: Riiul_K33, EM-09.2
In: Teine korrus
Classification: 1.11 IfcFurnitureType (mööbel) (BIM ÜBN + Archicad Classification); Material: 71 Kiht: MDF, 01 ÜLD: projekteeritav, 80 Siseviimistlus dold
AC_Pset_RenovationAndPhasing - Renovation Status: New
AR_ÜLD - 009_Märkus: OMA märkus
Pset_QuantityTakeOff - Reference: EM-09.2
AR_Mööbel - 001_Nimetus: Riiul; 900_Tootja: ootel; 905_Mudel: ootel; 002_Tähis: EM-09.2

# IfcFurnishingElement: Riiul_K38 (2)
In: Teine korrus
Classification: 1.11 IfcFurnitureType (mööbel) (BIM ÜBN + Archicad Classification); Material: 71 Kiht: MDF, 01 ÜLD: projekteeritav, 80 Siseviimistlus dold
AR_Mööbel - 001_Nimetus: Riiul; 900_Tootja: ootel; 905_Mudel: ootel; 002_Tähis: EM-09-3
Pset_QuantityTakeOff - Reference: EM-09-3
AR_ÜLD - 009_Märkus: OMA märkus
AC_Pset_RenovationAndPhasing - Renovation Status: New

# IfcFurnishingElement: Riiul_K4 (9)
In: Teine korrus
Classification: 1.11 IfcFurnitureType (mööbel) (BIM ÜBN + Archicad Classification); Material: 01 ÜLD: projekteeritav, 71 Kiht: MDF, 80 Siseviimistlus dold
AR_Mööbel - 001_Nimetus: Riiul; 900_Tootja: ootel; 905_Mudel: ootel; 002_Tähis: EM-09-1
AR_ÜLD - 009_Märkus: OMA märkus
Pset_QuantityTakeOff - Reference: EM-09-1
AC_Pset_RenovationAndPhasing - Renovation Status: New

# IfcFurnishingElement: Round Table 01 26 (11)
Classification: 1.11 IfcFurnitureType (mööbel) (BIM ÜBN + Archicad Classification)
AR_ÜLD - 009_Märkus: OMA märkus
AC_Pset_RenovationAndPhasing - Renovation Status: New
Name | In | 001_Nimetus | 900_Tootja | 905_Mudel | 002_Tähis = Reference
OM-03 | Esimene korrus | Kõrgusreguleeritav abilaud | Thulema | Nota | OM-03
OM-08a | Teine korrus | Diivani laud | Enea | Side Table Kua 3L | OM-08a
6 x OM-03 | Teine korrus | Kõrgusreguleeritav abilaud | Thulema | Nota | OM-03
2 x OM-06 | Teine korrus | Koosolekute laud | Enea | Iron | OM-06
OM-08b | Teine korrus | Diivani laud | Enea | Side Table Kua 3L | OM-08b

# IfcFurnishingElement: SAN dušikardinad, AK-10
In: Esimene korrus
Classification: 1.11 IfcFurnitureType (mööbel) (BIM ÜBN + Archicad Classification); Material: 01 ÜLD: projekteeritav
AR_Mööbel - 001_Nimetus: Nurk dušikardinapuu; 900_Tootja: Normbau; 905_Mudel: Inox Care; 002_Tähis: AK-10
Pset_QuantityTakeOff - Reference: AK-10
AR_ÜLD - 009_Märkus: OMA märkus
AC_Pset_RenovationAndPhasing - Renovation Status: New

# IfcFurnishingElement: Sanitary_Accessories_HEWI_Toilet-brush-unit (7)
Classification: 1.11 IfcFurnitureType (mööbel) (BIM ÜBN + Archicad Classification)
AR_Mööbel - 001_Nimetus: WC-hari; 900_Tootja: JNF; 905_Mudel: Industrial; 002_Tähis: AK-05
AR_ÜLD - 009_Märkus: OMA märkus
AC_Pset_RenovationAndPhasing - Renovation Status: Existing
Pset_QuantityTakeOff - Reference: AK-05
Name | In
3 x AK-05 | Esimene korrus
4 x AK-05 | Teine korrus

# IfcFurnishingElement: Sanitary_Accessories_Ideal-Standard_IOM-SP-DISP-800ML-POL-S-S-W-MTD (6)
Classification: 1.11 IfcFurnitureType (mööbel) (BIM ÜBN + Archicad Classification)
Pset_ProductRequirements - Category: Generic Models
Constraints - Elevation from Level: 0 mm; Moves With Nearby Elements: no; Offset from Host: 0 mm
Dimensions - Area: 36.1165 m2; Volume: 0.968197 m3
Other - Category: Generic Models; Family: BIM Motala Hissar: MasterType; Family and Type: BIM Motala Hissar: MasterType; Type: BIM Motala Hissar: MasterType; Type Id: BIM Motala Hissar: MasterType
Phasing - Phase Created: New Construction
AR_ÜLD - 009_Märkus: OMA märkus
AC_Pset_RenovationAndPhasing - Renovation Status: New
AR_Mööbel - 001_Nimetus: Seebidosaator
Name (BIM Motala Hissar:MasterType:...) | In | 900_Tootja | 905_Mudel | 002_Tähis | Pset_BuildingElementProxyCommon, Reference | Pset_BuildingElementProxyCommon, sets with these values
7813 | Esimene korrus | Mediclinics | - | AK-04.3 | Pset_QuantityTakeOff - Reference: MasterType; sets with these values: 2
2 x 7813 | Esimene korrus | Wagner Ewar | - | AK-04.1 | MasterType | 2
7813 | Teine korrus | Wagner Ewar | - | AK-04.1 | MasterType | 2
7813 | Teine korrus | Mediclinics |  | AKL-05 | MasterType | 2
7813 | Teine korrus | Wagner Ewar | - | AK-04.1 | Pset_QuantityTakeOff - Reference: MasterType; sets with these values: 2

# IfcFurnishingElement: Sanitary_Dispensers_Mediclinics_Behind-the-mirror-automatic-hand-sanitiz (2)
In: Teine korrus
Classification: 1.11 IfcFurnitureType (mööbel) (BIM ÜBN + Archicad Classification)
Pset_BuildingElementProxyCommon - Reference: MasterType; sets with these values: 2
Pset_ProductRequirements - Category: Generic Models
Dimensions - Area: 36.1165 m2; Volume: 0.968197 m3
Other - Category: Generic Models; Family: BIM Motala Hissar: MasterType; Family and Type: BIM Motala Hissar: MasterType; Type: BIM Motala Hissar: MasterType; Type Id: BIM Motala Hissar: MasterType
Phasing - Phase Created: New Construction
AR_Mööbel - 001_Nimetus: Seebidosaator; 900_Tootja: Wagner Ewar; 905_Mudel: -; 002_Tähis: AK-04.2
Constraints - Elevation from Level: 0 mm; Moves With Nearby Elements: no; Offset from Host: 0 mm
AC_Pset_RenovationAndPhasing - Renovation Status: New
AR_ÜLD - 009_Märkus: OMA märkus

# IfcFurnishingElement: Sanitary_Dispensers_Mediclinics_Behind-the-mirror-stainless-steel-towel (2)
In: Teine korrus
Classification: 1.11 IfcFurnitureType (mööbel) (BIM ÜBN + Archicad Classification)
Pset_BuildingElementProxyCommon - Reference: MasterType; sets with these values: 2
Pset_ProductRequirements - Category: Generic Models
Constraints - Elevation from Level: 0 mm; Moves With Nearby Elements: no; Offset from Host: 0 mm
Other - Category: Generic Models; Family: BIM Motala Hissar: MasterType; Family and Type: BIM Motala Hissar: MasterType; Type: BIM Motala Hissar: MasterType; Type Id: BIM Motala Hissar: MasterType
Phasing - Phase Created: New Construction
Dimensions - Area: 36.1165 m2; Volume: 0.968197 m3
AR_ÜLD - 009_Märkus: OMA märkus
AR_Mööbel - 001_Nimetus: Paberidosaator; 900_Tootja: Wagner Ewar; 905_Mudel: -; 002_Tähis: AK-03.2
AC_Pset_RenovationAndPhasing - Renovation Status: New

# IfcFurnishingElement: Sanitary_Other_Mediclinics_Horizontal-baby-changing-station-BabyMedi-stainless-steel, AK-14
In: Esimene korrus
Classification: 1.11 IfcFurnitureType (mööbel) (BIM ÜBN + Archicad Classification)
AR_Mööbel - 001_Nimetus: Mähkimislaud; 900_Tootja: Mediclinics; 905_Mudel: BabyMedi; 002_Tähis: AK-09
Pset_ManufacturerOccurrence - SerialNumber: CP0016HCS
Pset_QuantityTakeOff - Reference: AK-09
AR_ÜLD - 009_Märkus: OMA märkus
Pset_ManufacturerTypeInformation - Manufacturer: Mediclinics
AC_Pset_RenovationAndPhasing - Renovation Status: New

# IfcFurnishingElement: School Board 26, OMAK-03
In: Teine korrus
Classification: 1.11 IfcFurnitureType (mööbel) (BIM ÜBN + Archicad Classification)
AR_Mööbel - 900_Tootja: ootel; 905_Mudel: ootel; 002_Tähis: OMAK-03
Pset_QuantityTakeOff - Reference: OMAK-03
AR_ÜLD - 009_Märkus: OMA märkus
AC_Pset_RenovationAndPhasing - Renovation Status: New

# IfcFurnishingElement: Seinapaneel 13x12 b (2)
In: Teine korrus
Classification: 1.11 IfcFurnitureType (mööbel) (BIM ÜBN + Archicad Classification); Material: 71 Kiht: MDF, 80 Siseviimistlus dold
AR_ÜLD - 009_Märkus: OMA märkus
Pset_QuantityTakeOff - Reference: EM-05
AC_Pset_RenovationAndPhasing - Renovation Status: New
AR_Mööbel - 001_Nimetus: Sisseehitatud kapp II; 900_Tootja: ootel; 905_Mudel: ootel; 002_Tähis: EM-05

# IfcFurnishingElement: Shower Seat, AK-09
In: Esimene korrus
Classification: 1.11 IfcFurnitureType (mööbel) (BIM ÜBN + Archicad Classification)
AR_Mööbel - 001_Nimetus: Dušiiste; 900_Tootja: Mediclinics; 905_Mudel: -; 002_Tähis: AK-09
Pset_QuantityTakeOff - Reference: AK-09
AR_ÜLD - 009_Märkus: OMA märkus
AC_Pset_RenovationAndPhasing - Renovation Status: New

# IfcFurnishingElement: Shower Support Bar, AK-13
In: Esimene korrus
Classification: 1.11 IfcFurnitureType (mööbel) (BIM ÜBN + Archicad Classification)
AR_Mööbel - 001_Nimetus: Inva tugitoru dušiliftiga.; 900_Tootja: Normbau; 905_Mudel: CAVERE; 002_Tähis: AK-1
Pset_QuantityTakeOff - Reference: AK-1
AR_ÜLD - 009_Märkus: OMA märkus
AC_Pset_RenovationAndPhasing - Renovation Status: New

# IfcFurnishingElement: Sofa 04 26, OM-09
In: Teine korrus
Classification: 1.11 IfcFurnitureType (mööbel) (BIM ÜBN + Archicad Classification)
AR_Mööbel - 001_Nimetus: Väike diivan; 900_Tootja: Martela; 905_Mudel: Nora; 002_Tähis: OM-09
Pset_QuantityTakeOff - Reference: OM-09
AR_ÜLD - 009_Märkus: OMA märkus
AC_Pset_RenovationAndPhasing - Renovation Status: New

# IfcFurnishingElement: Sofa Chair 04 26 (5)
Classification: 1.11 IfcFurnitureType (mööbel) (BIM ÜBN + Archicad Classification)
AR_Mööbel - 001_Nimetus: Tugitool; 900_Tootja: Pederali; 905_Mudel: Lamorisse; 002_Tähis: OM-02
Pset_QuantityTakeOff - Reference: OM-02
AR_ÜLD - 009_Märkus: OMA märkus
AC_Pset_RenovationAndPhasing - Renovation Status: New
Name | In
2 x OM-02 | Esimene korrus
3 x OM-02 | Teine korrus

# IfcFurnishingElement: Stainless steel paper towel C_Z folds dispenser DT0106x (5)
Classification: 1.11 IfcFurnitureType (mööbel) (BIM ÜBN + Archicad Classification)
AR_Mööbel - 002_Tähis: AK-03; 900_Tootja: JNF; 905_Mudel: Industiral series; 001_Nimetus: Kätepaberihoidja
AC_Pset_RenovationAndPhasing - Renovation Status: Existing
AR_ÜLD - 009_Märkus: OMA märkus
Pset_ManufacturerTypeInformation - Manufacturer: JNF
Pset_ManufacturerOccurrence - SerialNumber: DT0106C
Name | In | Reference
2 x AK-03.3 | Esimene korrus | AK-03.3
AK-03.1 | Esimene korrus | AK-03.1
2 x AK-03.3 | Teine korrus | AK-03.3

# IfcFurnishingElement: Standing Cabinet Block 26 (2)
In: Teine korrus
Classification: 1.11 IfcFurnitureType (mööbel) (BIM ÜBN + Archicad Classification)
AR_Mööbel - 001_Nimetus: kulmik; 900_Tootja: ootel; 905_Mudel: ootel; 002_Tähis: EM-95
Pset_QuantityTakeOff - Reference: EM-95
AR_ÜLD - 009_Märkus: OMA märkus
AC_Pset_RenovationAndPhasing - Renovation Status: New

# IfcFurnishingElement: Toilet Paper Dispenser 26 (4)
Classification: 1.11 IfcFurnitureType (mööbel) (BIM ÜBN + Archicad Classification)
AR_Mööbel - 001_Nimetus: Tualettpaberihoidja; 900_Tootja: Wagner Ewar; 905_Mudel: -; 002_Tähis: AK-02.1
Pset_QuantityTakeOff - Reference: AK-02.1
AC_Pset_RenovationAndPhasing - Renovation Status: New
AR_ÜLD - 009_Märkus: OMA märkus
Name | In
2 x AK-02.1 | Esimene korrus
2 x AK-02.1 | Teine korrus

# IfcFurnishingElement: Towel Rack 26 (28)
Classification: 1.11 IfcFurnitureType (mööbel) (BIM ÜBN + Archicad Classification)
AR_ÜLD - 009_Märkus: OMA märkus
AC_Pset_RenovationAndPhasing - Renovation Status: Existing
Name | In | 001_Nimetus | 900_Tootja | 905_Mudel | 002_Tähis = Reference
18 x AK-06 | Esimene korrus | Seinakinnitusega nagi | Mediclinics | - | AK-06
AK-11 | Esimene korrus | Käterätihark pööratav | Haceka | Aspen | AK-11
8 x AK-06 | Teine korrus | Seinakinnitusega nagi | Mediclinics | - | AK-06
AK-11 | Teine korrus | Käterätihark pööratav | Haceka | Aspen | AK-11

# IfcFurnishingElement: Trash Can 02 26 (2)
In: Esimene korrus
Classification: 1.11 IfcFurnitureType (mööbel) (BIM ÜBN + Archicad Classification)
AR_Mööbel - 001_Nimetus: Bio; 900_Tootja: -; 905_Mudel: -; 002_Tähis: OML-01
AR_ÜLD - 009_Märkus: OMA märkus
Pset_QuantityTakeOff - Reference: OML-01
AC_Pset_RenovationAndPhasing - Renovation Status: New

# IfcFurnishingElement: Triangle table (16)
In: Teine korrus
Classification: 1.11 IfcFurnitureType (mööbel) (BIM ÜBN + Archicad Classification)
Pset_QuantityTakeOff - Reference: EM-10.1
AR_ÜLD - 009_Märkus: OMA märkus
AC_Pset_RenovationAndPhasing - Renovation Status: New
AR_Mööbel - 001_Nimetus: Töölaud; 900_Tootja: ootel; 905_Mudel: ootel; 002_Tähis: EM-10.1
Name | Material
14 x EM-10.1 | 71 Kiht: MDF
2 x EM-10.1 | 31 Konst: raudbetoon monoliitne

# IfcFurnishingElement: Triangle table 60 (1) (13)
In: Teine korrus
Classification: 1.11 IfcFurnitureType (mööbel) (BIM ÜBN + Archicad Classification); Material: 31 Konst: raudbetoon monoliitne
AR_ÜLD - 009_Märkus: OMA märkus
AC_Pset_RenovationAndPhasing - Renovation Status: New
AR_Mööbel - 001_Nimetus: Töölaud; 900_Tootja: ootel; 905_Mudel: ootel
Name | Reference = 002_Tähis
12 x EM-10.2 | EM-10.2
EM-10-2 | EM-10-2

# IfcFurnishingElement: Underdesk Drawer 26 (114)
Classification: 1.11 IfcFurnitureType (mööbel) (BIM ÜBN + Archicad Classification)
AC_Pset_RenovationAndPhasing - Renovation Status: New
AR_ÜLD - 009_Märkus: OMA märkus
Name | In | 001_Nimetus | 900_Tootja | 905_Mudel | 002_Tähis = Reference
46 x OML-04 | Esimene korrus | Ratastel sahtliboks | Medkoe | - | OML-04
2 x THK-01b | Esimene korrus | Keemiakapp | ootel | ootel | THK-01b
29 x OM-04 | Teine korrus | Sahtliboks | Thulema | Thor | OM-04
4 x THK-01b | Teine korrus | Keemiakapp | ootel | ootel | THK-01b
5 x  | Teine korrus | Ratastel sahtliboks | ootel | ootel
23 x OML-04c | Teine korrus | Ratastel sahtliboks | ootel | ootel | OML-04c
00 | Teine korrus | Ratastel sahtliboks | ootel | ootel | 00
4 x OML-04c | Teine korrus | Ratastel sahtliboks | Medkoe | - | OML-04c

# IfcFurnishingElement: Venetian Blind 26 (46)
Classification: 1.11 IfcFurnitureType (mööbel) (BIM ÜBN + Archicad Classification)
AR_Mööbel - 900_Tootja: Texstudio; 905_Mudel: -
AR_ÜLD - 009_Märkus: OMA märkus
AC_Pset_RenovationAndPhasing - Renovation Status: New
Name | In | 001_Nimetus | 002_Tähis = Reference
10 x KR-02 | Esimene korrus | Labroiruumide rulood | KR-02
3 x KR-03 | Esimene korrus | Labori rulood täispimendavad | KR-03
9 x KR-02 | Teine korrus | Labroiruumide rulood | KR-02
13 x KR-01 | Teine korrus | Kabineti rulood | KR-01
11 x KR-03 | Teine korrus | Labori rulood täispimendavad | KR-03

# IfcFurnishingElement: Vertical stainless steel swing grab bar BR0900x (2)
In: Esimene korrus
Classification: 1.11 IfcFurnitureType (mööbel) (BIM ÜBN + Archicad Classification)
AR_Mööbel - 001_Nimetus: Inva käetugi; 900_Tootja: Mediclinics; 905_Mudel: -; 002_Tähis: AK-07
Pset_ManufacturerOccurrence - SerialNumber: BR0900C
Pset_QuantityTakeOff - Reference: AK-07
Pset_ManufacturerTypeInformation - Manufacturer: Mediclinics
AR_ÜLD - 009_Märkus: OMA märkus
AC_Pset_RenovationAndPhasing - Renovation Status: New

# IfcFurnishingElement: WC 26 (2)
In: Teine korrus
Classification: 1.11 IfcFurnitureType (mööbel) (BIM ÜBN + Archicad Classification)
AR_Mööbel - 002_Tähis: ST-01a
Pset_QuantityTakeOff - Reference: ST-01a
AR_ÜLD - 009_Märkus: OMA märkus
AC_Pset_RenovationAndPhasing - Renovation Status: New

# IfcFurnishingElement: Wall Cabinet Block 26 (134)
Classification: 1.11 IfcFurnitureType (mööbel) (BIM ÜBN + Archicad Classification)
AR_ÜLD - 009_Märkus: OMA märkus
AC_Pset_RenovationAndPhasing - Renovation Status: New
Name | In | 001_Nimetus | 900_Tootja | 905_Mudel | 002_Tähis = Reference
67 x OMLS-01 | Esimene korrus | Seinakapp 60 | Medkoe | - | OMLS-01
3 x OMLS-03 | Esimene korrus | Seinakapp 50 | Medkoe | - | OMLS-03
4 x OMLS-01 | Esimene korrus | Seinakapp 75 | Medkoe | - | OMLS-01
58 x OMLS-02 | Teine korrus | Seinakapp | ootel | ootel | OMLS-02
EM-07 | Teine korrus |  | ootel | ootel | EM-07
EM-07 | Teine korrus | Printerikapp | ootel | ootel | EM-07

# IfcFurnishingElement: Wall Hanging Rack 26, OMAK-01
In: Teine korrus
Classification: 1.11 IfcFurnitureType (mööbel) (BIM ÜBN + Archicad Classification)
AR_Mööbel - 001_Nimetus: Kitlid; 900_Tootja: ootel; 905_Mudel: ootel; 002_Tähis: OMAK-01
AR_ÜLD - 009_Märkus: OMA märkus
AC_Pset_RenovationAndPhasing - Renovation Status: New
Pset_QuantityTakeOff - Reference: OMAK-01

# IfcFurnishingElement: Wardrobe 01 26 (16)
Classification: 1.11 IfcFurnitureType (mööbel) (BIM ÜBN + Archicad Classification)
AR_ÜLD - 009_Märkus: OMA märkus
AC_Pset_RenovationAndPhasing - Renovation Status: New
Name | In | 900_Tootja | 905_Mudel | 002_Tähis = Reference
EM-01 | Esimene korrus | ootel | ootel | EM-01 | AR_Mööbel - 001_Nimetus: Garderoobikapp
2 x EM-14 | Teine korrus | Eritellimus | - | EM-14
8 x EM-01 | Teine korrus | ootel | ootel | EM-01
EM-03.1 | Teine korrus | ootel | ootel | EM-03.1
2 x EM-09.1 | Teine korrus | ootel | ootel | EM-09.1
EM-03.3 | Teine korrus | ootel | ootel | EM-03.3
EM-03 | Teine korrus | ootel | ootel | EM-03

# IfcFurnishingElement: Washer 26 (6)
Classification: 1.11 IfcFurnitureType (mööbel) (BIM ÜBN + Archicad Classification)
AR_Mööbel - 900_Tootja: Electrolux; 905_Mudel: Perfect Care
AR_ÜLD - 009_Märkus: OMA märkus
AC_Pset_RenovationAndPhasing - Renovation Status: New
Name | In | 001_Nimetus | 002_Tähis = Reference
 | Esimene korrus | Pesumasin koristaja ruumis
TH-02 | Esimene korrus | Pesukuivati | TH-02
TH-01 | Esimene korrus | Pesumasin | TH-01
TH-02 | Teine korrus | Pesukuivati | TH-02
2 x TH-01 | Teine korrus | Pesumasin | TH-01

# IfcFurnishingElement: iMac 26 (40)
Classification: 1.11 IfcFurnitureType (mööbel) (BIM ÜBN + Archicad Classification)
AR_Mööbel - 900_Tootja: ootel; 905_Mudel: ootel
AR_ÜLD - 009_Märkus: OMA märkus
AC_Pset_RenovationAndPhasing - Renovation Status: New
Name | In | 001_Nimetus | 355_Pindala (m2) | 002_Tähis = Reference
8 x  | Esimene korrus | Arvuti
28 x M-01 | Teine korrus | Monitor | 0 | M-01
4 x  | Teine korrus | Arvuti
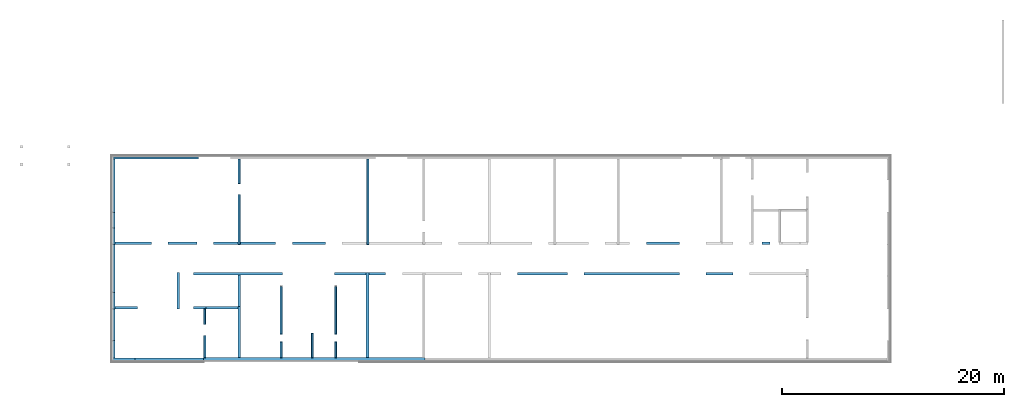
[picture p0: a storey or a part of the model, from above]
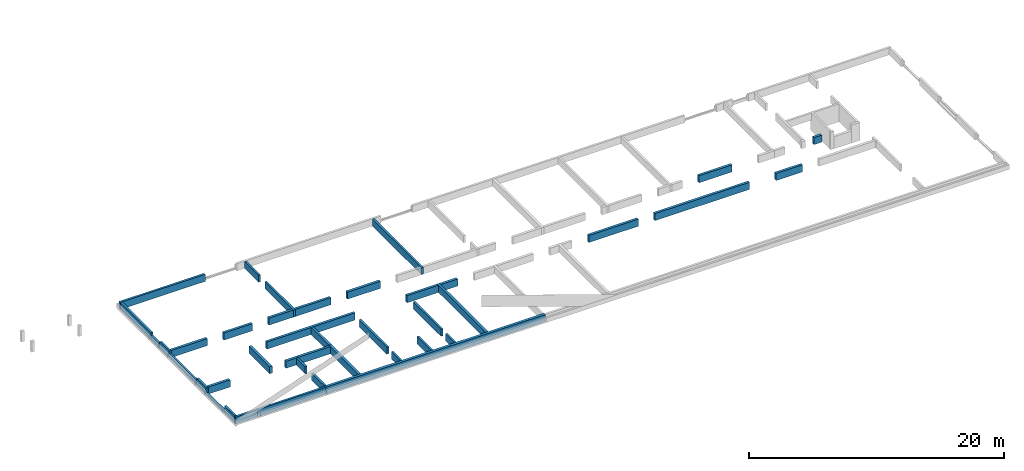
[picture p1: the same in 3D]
Properties of the parts of a building model (IFC2X3), part 7 of 8

# IfcFurnishingElement: inva mirror, PL-01
In: Esimene korrus
Classification: 1.11 IfcFurnitureType (mööbel) (BIM ÜBN + Archicad Classification); Material: 37 Konst: CLT ver, 33 Konst: Columbia õõnesplokk
AR_Mööbel - 001_Nimetus: Inva peegel inva WC´s; 900_Tootja: Delabie; 905_Mudel: tk: 510202C; 002_Tähis: PL-01
AC_Pset_RenovationAndPhasing - Renovation Status: New
AR_ÜLD - 009_Märkus: OMA märkus
Pset_QuantityTakeOff - Reference: PL-01

# IfcFurnishingElement: vaheriiul_2, EM-11
In: Teine korrus
Classification: 1.11 IfcFurnitureType (mööbel) (BIM ÜBN + Archicad Classification); Material: 01 ÜLD: projekteeritav, 80 must mööbliplaat, 80 Siseviimistlus dold
Pset_QuantityTakeOff - Reference: EM-11
AR_Mööbel - 001_Nimetus: Vaheriiul; 900_Tootja: ootel; 905_Mudel: ootel; 002_Tähis: EM-11
AR_ÜLD - 009_Märkus: OMA märkus
AC_Pset_RenovationAndPhasing - Renovation Status: New

# IfcMember: IfcMember (6)
In: Esimene korrus
Type - ElementType: Stair Structure; PredefinedType: USERDEFINED
Classification: Stair Structure (BIM ÜBN + Archicad Classification); Material: 30 Konst: Raudbetoon monteeritav
AR_ÜLD - 009_Märkus: OMA märkus
AC_Pset_RenovationAndPhasing - Renovation Status: New
Name
2 x TT KONSTRUKTSIOON - 009
TM KONSTRUKTSIOON - 005
TM KONSTRUKTSIOON - 004
TT KONSTRUKTSIOON - 007
TT KONSTRUKTSIOON - 008

# IfcOpeningElement: OPENING (3)
Classification: 1.14 IfcOpeningElement (avaelement) (BIM ÜBN + Archicad Classification)
AR_ÜLD - 009_Märkus: OMA märkus
AC_Pset_RenovationAndPhasing - Renovation Status: New
Name | In
2 x AVA | Esimene korrus
AVA | Teine korrus

# IfcPlate: 30 Konst: Raudbetoon monoliitne 100 (3)
In: Esimene korrus
Classification: 1.15 IfcPlateType (plaat) (BIM ÜBN + Archicad Classification); Material: 30 Konst: Raudbetoon monoliitne
AR_ÜLD - 001_Nimetus: Jalapuhastusresti vann; 009_Märkus: vt. AR-7 sõlmlahendusi ja VK-osa
Pset_PlateCommon - IsExternal: yes; LoadBearing: yes
AC_Pset_RenovationAndPhasing - Renovation Status: New
Name
JPR-01
JPR-02
JPR-03

# IfcPlate: 30 Konst: Raudbetoon monoliitne 150 (13)
In: Esimene korrus
Classification: 1.15 IfcPlateType (plaat) (BIM ÜBN + Archicad Classification); Material: 30 Konst: Raudbetoon monoliitne
AC_Pset_RenovationAndPhasing - Renovation Status: New
Pset_PlateCommon - IsExternal: yes; LoadBearing: yes
Name | 001_Nimetus | 009_Märkus
10 x BP-01 | Betoonplaat | vt. AR-7 sõlmlahendusi, tagada libisemiskindlus
JPR-01 | Jalapuhastusresti vann | vt. AR-7 sõlmlahendusi ja VK-osa
JPR-02 | Jalapuhastusresti vann | vt. AR-7 sõlmlahendusi ja VK-osa
JPR-03 | Jalapuhastusresti vann | vt. AR-7 sõlmlahendusi ja VK-osa

# IfcPlate: 30 Konst: Raudbetoon monoliitne 250, BP-01
In: Esimene korrus
Classification: 1.15 IfcPlateType (plaat) (BIM ÜBN + Archicad Classification); Material: 30 Konst: Raudbetoon monoliitne
AR_ÜLD - 001_Nimetus: Šahti põhi; 009_Märkus: vt. EK-osa
AC_Pset_RenovationAndPhasing - Renovation Status: New
Pset_PlateCommon - IsExternal: no; LoadBearing: yes

# IfcPlate: 71 Kiht: jalapuhastusrest 11 (7)
In: Esimene korrus
Classification: 1.15 IfcPlateType (plaat) (BIM ÜBN + Archicad Classification); Material: 71 Kiht: jalapuhastusrest
AR_ÜLD - 001_Nimetus: Jalapuhastusrest; 009_Märkus: vt. AR-8 spetsifikatsioone
Pset_PlateCommon - IsExternal: yes; LoadBearing: yes
AC_Pset_RenovationAndPhasing - Renovation Status: New
Name
2 x JPR-01
JPR-02
4 x JPR-03

# IfcPlate: Grid 26 (19)
In: Teine korrus
Classification: 1.15 IfcPlateType (plaat) (BIM ÜBN + Archicad Classification)
AR_ÜLD - 001_Nimetus: Jalapuhastusrest; 009_Märkus: vt. AR-8 spetsifikatsioone
AC_Pset_RenovationAndPhasing - Renovation Status: New
Pset_PlateCommon - IsExternal: yes; LoadBearing: yes
Name
5 x JPR-06
7 x JPR-05
5 x JPR-04
JPR-04a
JPR-06a

# IfcPlate: SS-04a 91 (4)
Classification: 1.15 IfcPlateType (plaat) (BIM ÜBN + Archicad Classification)
AR_ÜLD - 001_Nimetus: Loputuskasti pealne; 009_Märkus: vt. SA-osa
Pset_PlateCommon - IsExternal: no; LoadBearing: no
AC_Pset_RenovationAndPhasing - Renovation Status: New
Name | In
2 x SS-04a | Esimene korrus
2 x SS-04a | Teine korrus

# IfcRailing: 02 Üldine: olemasolev 10, RP-01
In: Teine korrus
Classification: 1.16 IfcRailingType (piire) (BIM ÜBN + Archicad Classification); Material: 02 Üldine: olemasolev
AR_Piire - 001_Nimetus: Sisetrepi piire; 250_Kõrgus: 1308.17 mm; 255_Kogupikkus: 40 mm; 900_Tootja: ootel; 905_Mudel: ootel; 910_Tooteinfo: ootel; 915_Kasutus-ja-hooldusjuhend: ootel; 205_Tähis: RP-01
AR_ÜLD - 009_Märkus: OMA märkus
Pset_RailingCommon - IsExternal: no
AC_Pset_RenovationAndPhasing - Renovation Status: New

# IfcRailing: 40 Kiht: Teras 50 x 10 (2)
In: Teine korrus
Classification: 1.16 IfcRailingType (piire) (BIM ÜBN + Archicad Classification); Material: 40 Kiht: Teras
AR_Piire - 250_Kõrgus: 10 mm; 900_Tootja: ootel; 905_Mudel: ootel; 910_Tooteinfo: ootel; 915_Kasutus-ja-hooldusjuhend: ootel
Pset_RailingCommon - IsExternal: no
AC_Pset_RenovationAndPhasing - Renovation Status: New
AR_ÜLD - 009_Märkus: OMA märkus
Name | 255_Kogupikkus (mm)
 | 1345
RP-01 | 1465 | AR_Piire - 001_Nimetus: Sisetrepi piire; 205_Tähis: RP-01

# IfcRailing: 60 Plaat: Puitkiudplaat 20
In: Esimene korrus
Classification: 1.16 IfcRailingType (piire) (BIM ÜBN + Archicad Classification); Material: 60 Plaat: Puitkiudplaat
AR_Piire - 250_Kõrgus: 150 mm; 255_Kogupikkus: 1460 mm; 900_Tootja: ootel; 905_Mudel: ootel; 910_Tooteinfo: ootel; 915_Kasutus-ja-hooldusjuhend: ootel
AR_ÜLD - 009_Märkus: OMA märkus
Pset_RailingCommon - IsExternal: no
AC_Pset_RenovationAndPhasing - Renovation Status: New

# IfcRailing: 91 Viim: Klaas 10 (13)
Classification: 1.16 IfcRailingType (piire) (BIM ÜBN + Archicad Classification); Material: 91 Viim: Klaas
AR_ÜLD - 009_Märkus: OMA märkus
AR_Piire - 900_Tootja: ootel; 905_Mudel: ootel; 910_Tooteinfo: ootel; 915_Kasutus-ja-hooldusjuhend: ootel
AC_Pset_RenovationAndPhasing - Renovation Status: New
Pset_RailingCommon - IsExternal: no
Name | In | 250_Kõrgus (mm) | 255_Kogupikkus (mm) | 001_Nimetus | 205_Tähis
 | Esimene korrus | 1170 | 40
RP-02 | Esimene korrus | 1127.96 | 50 | Sisetrepi piire | RP-02
RP-01 | Esimene korrus | 1328 | 50 | Sisetrepi piire | RP-01
RP-01 | Esimene korrus | 1053 | 50 | Sisetrepi piire | RP-01
 | Esimene korrus | 1158.7 | 50
 | Esimene korrus | 1053 | 40
 | Esimene korrus | 1291.37 | 50
RP-02 | Esimene korrus | 1328.19 | 50 | Sisetrepi piire | RP-02
RP-02 | Teine korrus | 1000 | 1250 | Sisetrepi piire | RP-02
RP-02 | Teine korrus | 2315 | 1345 | Sisetrepi piire | RP-02
RP-01 | Teine korrus | 1398 | 1465 | Sisetrepi piire | RP-01
 | Teine korrus | 108 | 1429.08
RP-02 | Teine korrus | 1325.12 | 39.9414 | Sisetrepi piire | RP-02

# IfcRailing: Käsipuu 1.1, KP-04
In: Esimene korrus
Classification: 1.16 IfcRailingType (piire) (BIM ÜBN + Archicad Classification)
AR_Piire - 001_Nimetus: Käsipuu; 250_Kõrgus: 2756.91 mm; 900_Tootja: ootel; 905_Mudel: ootel; 910_Tooteinfo: ootel; 915_Kasutus-ja-hooldusjuhend: ootel; 205_Tähis: KP-04
AR_ÜLD - 009_Märkus: OMA märkus
AC_Pset_RenovationAndPhasing - Renovation Status: New
Pset_RailingCommon - IsExternal: no

# IfcRailing: Käsipuu 1.2
In: Teine korrus
Classification: 1.16 IfcRailingType (piire) (BIM ÜBN + Archicad Classification)
AR_Piire - 001_Nimetus: Käsipuu; 250_Kõrgus: 2130.91 mm; 900_Tootja: ootel; 905_Mudel: ootel; 910_Tooteinfo: ootel; 915_Kasutus-ja-hooldusjuhend: ootel
AR_ÜLD - 009_Märkus: OMA märkus
Pset_RailingCommon - IsExternal: no
AC_Pset_RenovationAndPhasing - Renovation Status: New

# IfcRailing: Käsipuu 2.1, KP-02
In: Teine korrus
Classification: 1.16 IfcRailingType (piire) (BIM ÜBN + Archicad Classification)
AR_Piire - 001_Nimetus: Käsipuu; 250_Kõrgus: 1813.94 mm; 900_Tootja: ootel; 905_Mudel: ootel; 910_Tooteinfo: ootel; 915_Kasutus-ja-hooldusjuhend: ootel; 205_Tähis: KP-02
AC_Pset_RenovationAndPhasing - Renovation Status: New
AR_ÜLD - 009_Märkus: OMA märkus
Pset_RailingCommon - IsExternal: no

# IfcRailing: Käsipuu 2.2
In: Teine korrus
Classification: 1.16 IfcRailingType (piire) (BIM ÜBN + Archicad Classification)
AR_Piire - 250_Kõrgus: 1656.91 mm; 900_Tootja: ootel; 905_Mudel: ootel; 910_Tooteinfo: ootel; 915_Kasutus-ja-hooldusjuhend: ootel
AR_ÜLD - 009_Märkus: OMA märkus
Pset_RailingCommon - IsExternal: no
AC_Pset_RenovationAndPhasing - Renovation Status: New

# IfcRailing: Käsipuu 2.3, KP-01
In: Esimene korrus
Classification: 1.16 IfcRailingType (piire) (BIM ÜBN + Archicad Classification)
AR_Piire - 001_Nimetus: Käsipuu; 250_Kõrgus: 1650.82 mm; 900_Tootja: ootel; 905_Mudel: ootel; 910_Tooteinfo: ootel; 915_Kasutus-ja-hooldusjuhend: ootel; 205_Tähis: KP-01
AR_ÜLD - 009_Märkus: OMA märkus
AC_Pset_RenovationAndPhasing - Renovation Status: New
Pset_RailingCommon - IsExternal: no

# IfcRailing: Piire VP-01-03 (2)
In: Esimene korrus
Classification: 1.16 IfcRailingType (piire) (BIM ÜBN + Archicad Classification)
AR_ÜLD - 009_Märkus: vt. AR-8 kujujooniseid
AR_Piire - 001_Nimetus: Trepipiire; 250_Kõrgus: 3580.55 mm; 900_Tootja: ootel; 905_Mudel: ootel; 910_Tooteinfo: ootel; 915_Kasutus-ja-hooldusjuhend: ootel
Pset_RailingCommon - IsExternal: yes
AC_Pset_RenovationAndPhasing - Renovation Status: New
Name | 205_Tähis
VP-03 | VP-03
VP-01 | VP-01

# IfcRailing: Piire VP-02-04 (2)
In: Esimene korrus
Classification: 1.16 IfcRailingType (piire) (BIM ÜBN + Archicad Classification)
AR_Piire - 001_Nimetus: Trepipiire; 250_Kõrgus: 3166.97 mm; 900_Tootja: ootel; 905_Mudel: ootel; 910_Tooteinfo: ootel; 915_Kasutus-ja-hooldusjuhend: ootel
AR_ÜLD - 009_Märkus: vt. AR-8 kujujooniseid
AC_Pset_RenovationAndPhasing - Renovation Status: New
Pset_RailingCommon - IsExternal: yes
Name | 205_Tähis
VP-04 | VP-04
VP-02 | VP-02

# IfcRailing: Steel railing 01 50 x 1129
In: Esimene korrus
Classification: 1.16 IfcRailingType (piire) (BIM ÜBN + Archicad Classification); Material: 01 Üldine: projekteeritud
AR_ÜLD - 009_Märkus: OMA märkus
AR_Piire - 250_Kõrgus: 1129.33 mm; 255_Kogupikkus: 3641.71 mm; 900_Tootja: ootel; 905_Mudel: ootel; 910_Tooteinfo: ootel; 915_Kasutus-ja-hooldusjuhend: ootel
Pset_RailingCommon - IsExternal: no
AC_Pset_RenovationAndPhasing - Renovation Status: New

# IfcRailing: Steel railing 01 50 x 1211 (2)
Classification: 1.16 IfcRailingType (piire) (BIM ÜBN + Archicad Classification); Material: 01 Üldine: projekteeritud
AC_Pset_RenovationAndPhasing - Renovation Status: New
AR_ÜLD - 009_Märkus: OMA märkus
AR_Piire - 001_Nimetus: Sisetrepi piire; 250_Kõrgus: 1211.5 mm; 900_Tootja: ootel; 905_Mudel: ootel; 910_Tooteinfo: ootel; 915_Kasutus-ja-hooldusjuhend: ootel; 205_Tähis: RP-01
Pset_RailingCommon - IsExternal: no
Name | In | 255_Kogupikkus (mm)
RP-01 | Esimene korrus | 3197.97
RP-01 | Teine korrus | 3270.15

# IfcRailing: Steel railing 01 50 x 1248
In: Teine korrus
Classification: 1.16 IfcRailingType (piire) (BIM ÜBN + Archicad Classification); Material: 01 Üldine: projekteeritud
AC_Pset_RenovationAndPhasing - Renovation Status: New
AR_ÜLD - 009_Märkus: OMA märkus
Pset_RailingCommon - IsExternal: no
AR_Piire - 250_Kõrgus: 1248.05 mm; 255_Kogupikkus: 4292.01 mm; 900_Tootja: ootel; 905_Mudel: ootel; 910_Tooteinfo: ootel; 915_Kasutus-ja-hooldusjuhend: ootel

# IfcRailing: Steel railing 01-1 50 x 1210
In: Esimene korrus
Classification: 1.16 IfcRailingType (piire) (BIM ÜBN + Archicad Classification); Material: 01 Üldine: projekteeritud
AR_Piire - 250_Kõrgus: 1210 mm; 255_Kogupikkus: 5727.1 mm; 900_Tootja: ootel; 905_Mudel: ootel; 910_Tooteinfo: ootel; 915_Kasutus-ja-hooldusjuhend: ootel
AR_ÜLD - 009_Märkus: OMA märkus
AC_Pset_RenovationAndPhasing - Renovation Status: New
Pset_RailingCommon - IsExternal: no

# IfcSlab: 50 Soojustus: EPS 160 (2)
In: Katus
Type - PredefinedType: ROOF
Classification: 1.19 IfcSlabType.ROOF (katus) (BIM ÜBN + Archicad Classification); Material: 50 Soojustus: EPS 160 mm
Pset_SlabCommon - Reference: Abipind; IsExternal: yes; LoadBearing: yes
AR_ÜLD - 009_Märkus: vt. AR-7 sõlmlahendusi
AC_Pset_RenovationAndPhasing - Renovation Status: New
AR_Plaat - 001_Nimetus: Soojustus; 325_Helipidavus: nõudeid ei esitata; 330_Tulepüsivus: EI30; 340_Soojusläbivus: 0; 505_Paksus: 160 mm; 500_Kandev: yes; 205_Tähis: Abipind; 335_Välispiire: yes
Name | 515_Neto-pindala (m2)
Abipind | 0.4096
Abipind | 0.40968

# IfcSlab: 60 Plaat: liimpuitplaat 22, KL-04a
In: Teine korrus
Type - PredefinedType: ROOF
Classification: 1.19 IfcSlabType.ROOF (katus) (BIM ÜBN + Archicad Classification); Material: 60 Plaat: liimpuitplaat 22 mm
AR_Plaat - 001_Nimetus: Sisehoovi katuslagi; 325_Helipidavus: nõudeid ei esitata; 330_Tulepüsivus: nõudeid ei esitata; 340_Soojusläbivus: 0; 505_Paksus: 22 mm; 515_Neto-pindala: 24.3473 m2; 500_Kandev: yes; 205_Tähis: KL-04a; 335_Välispiire: yes
AR_ÜLD - 009_Märkus: vt. AR-7 sõlmlahendusi
AC_Pset_RenovationAndPhasing - Renovation Status: New
Pset_SlabCommon - Reference: KL-04a; IsExternal: yes; LoadBearing: yes

# IfcSlab: KL-01 265, KL-01
In: Katus
Type - PredefinedType: ROOF
Classification: 1.19 IfcSlabType.ROOF (katus) (BIM ÜBN + Archicad Classification); Material: 30 Konst: Raudbetoon monteeritav 265 mm
AR_Plaat - 001_Nimetus: Katuslagi; 325_Helipidavus: R’w ≥ 55 dB; 330_Tulepüsivus: nõudeid ei esitata; 340_Soojusläbivus: 0; 505_Paksus: 265 mm; 515_Neto-pindala: 1149.63 m2; 500_Kandev: yes; 205_Tähis: KL-01; 335_Välispiire: yes
AR_ÜLD - 009_Märkus: vt. EK-osa. Mudelis jaotatud osadeks
Pset_SlabCommon - Reference: KL-01; IsExternal: yes; LoadBearing: yes
AC_Pset_RenovationAndPhasing - Renovation Status: New

# IfcSlab: KL-01a 460 (2)
In: Katus
Type - PredefinedType: ROOF
Classification: 1.19 IfcSlabType.ROOF (katus) (BIM ÜBN + Archicad Classification)
Pset_SlabCommon - Reference: KL-01; IsExternal: yes; LoadBearing: yes
AR_Plaat - 001_Nimetus: Katuslae soojustuse osa; 325_Helipidavus: R’w ≥ 55 dB; 330_Tulepüsivus: nõudeid ei esitata; 340_Soojusläbivus: 0; 505_Paksus: 460 mm; 500_Kandev: yes; 205_Tähis: KL-01; 335_Välispiire: yes
AR_ÜLD - 009_Märkus: vt. EK-osa, mudelis jaotatud osadeks
AC_Pset_RenovationAndPhasing - Renovation Status: New
Name | 515_Neto-pindala (m2)
KL-01 | 529.753
KL-01 | 490.923

# IfcSlab: KL-01b 410 (30)
In: Katus
Type - PredefinedType: ROOF
Classification: 1.19 IfcSlabType.ROOF (katus) (BIM ÜBN + Archicad Classification)
AR_Plaat - 001_Nimetus: Katuslae soojustuse osa; 325_Helipidavus: R’w ≥ 55 dB; 330_Tulepüsivus: nõudeid ei esitata; 340_Soojusläbivus: 0; 505_Paksus: 410 mm; 500_Kandev: yes; 205_Tähis: KL-01; 335_Välispiire: yes
AR_ÜLD - 009_Märkus: vt. EK-osa. Mudelis jaotatud osadeks
AC_Pset_RenovationAndPhasing - Renovation Status: New
Pset_SlabCommon - Reference: KL-01; IsExternal: yes; LoadBearing: yes
Name | 515_Neto-pindala (m2)
KL-01 | 13.6318
2 x KL-01 | 3.66005
KL-01 | 0.970642
KL-01 | 0.972922
KL-01 | 2.22307
KL-01 | 5.03139
KL-01 | 2.21786
KL-01 | 5.03615
KL-01 | 7.10435
4 x KL-01 | 2.22073
KL-01 | 4.68422
4 x KL-01 | 6.22156
2 x KL-01 | 3.9711
KL-01 | 3.70748
2 x KL-01 | 0.0428161
2 x KL-01 | 0.0428054
KL-01 | 3.86391
KL-01 | 3.8743
KL-01 | 0.0189627
KL-01 | 0.0809555

# IfcSlab: KL-02 265, KL-02
In: Teine korrus
Type - PredefinedType: ROOF
Classification: 1.19 IfcSlabType.ROOF (katus) (BIM ÜBN + Archicad Classification); Material: 30 Konst: Raudbetoon monteeritav
Pset_SlabCommon - Reference: KL-02; IsExternal: yes; LoadBearing: yes
AR_Plaat - 001_Nimetus: Katuslagi; 325_Helipidavus: R’w ≥ 55 dB; 330_Tulepüsivus: REI30; 340_Soojusläbivus: 0; 505_Paksus: 265 mm; 515_Neto-pindala: 89.349 m2; 500_Kandev: yes; 205_Tähis: KL-02; 335_Välispiire: yes
AR_ÜLD - 009_Märkus: vt. EK-osa
AC_Pset_RenovationAndPhasing - Renovation Status: New

# IfcSlab: KL-02a_UUS 640 (3)
In: Teine korrus
Type - PredefinedType: ROOF
Classification: 1.19 IfcSlabType.ROOF (katus) (BIM ÜBN + Archicad Classification)
AR_Plaat - 001_Nimetus: Katuslagi; 325_Helipidavus: R’w ≥ 55 dB; 330_Tulepüsivus: EI30; 340_Soojusläbivus: 0; 505_Paksus: 640 mm; 500_Kandev: yes; 205_Tähis: KL-02; 335_Välispiire: yes
AR_ÜLD - 009_Märkus: vt. EK-osa. Mudelis jaotatud osadeks
Pset_SlabCommon - Reference: KL-02; IsExternal: yes; LoadBearing: yes
AC_Pset_RenovationAndPhasing - Renovation Status: New
Name | 515_Neto-pindala (m2)
KL-02 | 55.9954
KL-02 | 28.0608
KL-02 | 28.0639

# IfcSlab: KL-03 160, KL-03
In: Teine korrus
Type - PredefinedType: ROOF
Classification: 1.19 IfcSlabType.ROOF (katus) (BIM ÜBN + Archicad Classification)
Pset_SlabCommon - Reference: KL-03; IsExternal: yes; LoadBearing: no
AR_Plaat - 001_Nimetus: Ventkambri lagi; 325_Helipidavus: nõudeid ei esitata; 330_Tulepüsivus: nõudeid ei esitata; 340_Soojusläbivus: 0; 505_Paksus: 160 mm; 515_Neto-pindala: 13.5581 m2; 500_Kandev: no; 205_Tähis: KL-03; 335_Välispiire: yes
AR_ÜLD - 009_Märkus: vt. AR-7 sõlmlahendusi. KL-01 lisaks
AC_Pset_RenovationAndPhasing - Renovation Status: New

# IfcSlab: KL-04 78 (3)
In: Katus
Type - PredefinedType: ROOF
Classification: 1.19 IfcSlabType.ROOF (katus) (BIM ÜBN + Archicad Classification)
Pset_SlabCommon - Reference: KL-04; IsExternal: yes; LoadBearing: yes
AR_Plaat - 001_Nimetus: Sisehoovi katuslagi; 325_Helipidavus: nõudeid ei esitata; 330_Tulepüsivus: nõudeid ei esitata; 340_Soojusläbivus: 0; 505_Paksus: 78 mm; 500_Kandev: yes; 205_Tähis: KL-04; 335_Välispiire: yes
AR_ÜLD - 009_Märkus: vt. AR-7 sõlmlahendusi
AC_Pset_RenovationAndPhasing - Renovation Status: New
Name | 515_Neto-pindala (m2)
KL-04 | 3.95717
KL-04 | 3.95676
KL-04 | 48.5348

# IfcSlab: KL-04a 89, KL-04
In: Teine korrus
Type - PredefinedType: ROOF
Classification: 1.19 IfcSlabType.ROOF (katus) (BIM ÜBN + Archicad Classification)
AR_Plaat - 001_Nimetus: Sisehoovi katuslagi; 325_Helipidavus: nõudeid ei esitata; 330_Tulepüsivus: nõudeid ei esitata; 340_Soojusläbivus: 0; 505_Paksus: 89 mm; 515_Neto-pindala: 21.5238 m2; 500_Kandev: yes; 205_Tähis: KL-04; 335_Välispiire: yes
AC_Pset_RenovationAndPhasing - Renovation Status: New
AR_ÜLD - 009_Märkus: vt. AR-7 sõlmlahendusi
Pset_SlabCommon - Reference: KL-04; IsExternal: yes; LoadBearing: yes

# IfcSlab: KL-04a_2 172, KL-04
In: Teine korrus
Type - PredefinedType: ROOF
Classification: 1.19 IfcSlabType.ROOF (katus) (BIM ÜBN + Archicad Classification)
AR_ÜLD - 009_Märkus: vt. AR-7 sõlmlahendusi
AR_Plaat - 001_Nimetus: Sisehoovi katuslagi; 325_Helipidavus: nõudeid ei esitata; 330_Tulepüsivus: nõudeid ei esitata; 340_Soojusläbivus: 0; 505_Paksus: 172 mm; 515_Neto-pindala: 62.5298 m2; 500_Kandev: yes; 205_Tähis: KL-04; 335_Välispiire: yes
AC_Pset_RenovationAndPhasing - Renovation Status: New
Pset_SlabCommon - Reference: KL-04; IsExternal: yes; LoadBearing: yes

# IfcSlab: KL-04b 50, KL-04
In: Katus
Type - PredefinedType: ROOF
Classification: 1.19 IfcSlabType.ROOF (katus) (BIM ÜBN + Archicad Classification)
Pset_SlabCommon - Reference: KL-04; IsExternal: yes; LoadBearing: yes
AR_Plaat - 001_Nimetus: Sisehoovi katuslagi; 325_Helipidavus: nõudeid ei esitata; 330_Tulepüsivus: nõudeid ei esitata; 340_Soojusläbivus: 0; 505_Paksus: 50 mm; 515_Neto-pindala: 6.98177 m2; 500_Kandev: yes; 205_Tähis: KL-04; 335_Välispiire: yes
AC_Pset_RenovationAndPhasing - Renovation Status: New
AR_ÜLD - 009_Märkus: vt. AR-7 sõlmlahendusi

# IfcSlab: KL-05a 130 (3)
Type - PredefinedType: ROOF
Classification: 1.19 IfcSlabType.ROOF (katus) (BIM ÜBN + Archicad Classification)
Pset_SlabCommon - Reference: KL-05; IsExternal: yes; LoadBearing: yes
AR_Plaat - 001_Nimetus: Rajatise katus; 325_Helipidavus: nõudeid ei esitata; 330_Tulepüsivus: nõudeid ei esitata; 340_Soojusläbivus: 0; 505_Paksus: 130 mm; 500_Kandev: yes; 205_Tähis: KL-05; 335_Välispiire: yes
AR_ÜLD - 009_Märkus: vt. EK-osa. 130mm kandevprofiilplekk. Mudelis jaotatud osadeks.
AC_Pset_RenovationAndPhasing - Renovation Status: New
Name | In | Material | 515_Neto-pindala (m2)
KL-05 | Esimene korrus | 90 Viim: Katuseplekk 130 mm | 16.8253
KL-05 | Esimene korrus | 90 Viim: Katuseplekk 130 mm | 16.8051
KL-05 | Teine korrus | 90 Viim: Katuseplekk | 89.6639

# IfcSlab: KL-05b 130 (12)
Type - PredefinedType: ROOF
Classification: 1.19 IfcSlabType.ROOF (katus) (BIM ÜBN + Archicad Classification)
Pset_SlabCommon - Reference: KL-05; IsExternal: yes; LoadBearing: yes
AR_Plaat - 001_Nimetus: Rohekatus; 325_Helipidavus: nõudeid ei esitata; 340_Soojusläbivus: 0; 505_Paksus: 130 mm; 500_Kandev: yes; 205_Tähis: KL-05; 335_Välispiire: yes
AR_ÜLD - 009_Märkus: vt. EK-osa. Mudelis jaotatud osadeks
AC_Pset_RenovationAndPhasing - Renovation Status: New
Name | In | 330_Tulepüsivus | 515_Neto-pindala (m2)
KL-05 | Esimene korrus | ootel | 15.8044
KL-05 | Esimene korrus | ootel | 16.7268
KL-05 | Teine korrus | ootel | 78.5413
4 x KL-05 | Teine korrus | nõudeid ei esitata | 0.172691
4 x KL-05 | Teine korrus | nõudeid ei esitata | 0.0761151
KL-05 | Teine korrus | nõudeid ei esitata | 10.701

# IfcSlab: KL-05c 49, KL-05
In: Esimene korrus
Type - PredefinedType: ROOF
Classification: 1.19 IfcSlabType.ROOF (katus) (BIM ÜBN + Archicad Classification)
Pset_SlabCommon - Reference: KL-05; IsExternal: yes; LoadBearing: yes
AC_Pset_RenovationAndPhasing - Renovation Status: New
AR_Plaat - 001_Nimetus: Katuslagi; 325_Helipidavus: ootel; 330_Tulepüsivus: ootel; 340_Soojusläbivus: 0; 505_Paksus: 49 mm; 515_Neto-pindala: 33.9997 m2; 500_Kandev: yes; 205_Tähis: KL-05; 335_Välispiire: yes

# IfcSlab: PP-01 500 (14)
In: Esimene korrus
Classification: 1.20 IfcSlabType (vahelagi) (BIM ÜBN + Archicad Classification)
AR_Plaat - 001_Nimetus: Põrand pinnasel; 325_Helipidavus: L'n,w ≥ 68 dB; 330_Tulepüsivus: nõudeid ei esitata; 340_Soojusläbivus: 0; 505_Paksus: 500 mm; 500_Kandev: yes; 205_Tähis: PP-01; 335_Välispiire: no
AR_ÜLD - 009_Märkus: vt. EK-osa konstruktsioone
Pset_SlabCommon - Reference: PP-01; IsExternal: no; LoadBearing: yes
AC_Pset_RenovationAndPhasing - Renovation Status: New
Name | 515_Neto-pindala (m2)
PP-01 | 84.916
PP-01 | 6.81391
PP-01 | 83.6517
PP-01 | 19.9139
PP-01 | 15.3331
PP-01 | 85.3271
PP-01 | 16.7217
PP-01 | 29.3203
PP-01 | 26.6707
PP-01 | 85.3645
PP-01 | 42.6006
PP-01 | 22.2002
PP-01 | 12.9695
PP-01 | 3.18

# IfcSlab: PP-01a 480 (2)
In: Esimene korrus
Classification: 1.20 IfcSlabType (vahelagi) (BIM ÜBN + Archicad Classification)
Pset_SlabCommon - IsExternal: no; LoadBearing: yes
AR_ÜLD - 009_Märkus: NB! jälgida SA-osa porivaipa! Betoonplaadi paksus 80mm
AC_Pset_RenovationAndPhasing - Renovation Status: New
AR_Plaat - 001_Nimetus: Põrand pinnasel; 325_Helipidavus: L'n,w ≥ 68 dB; 330_Tulepüsivus: nõudeid ei esitata; 340_Soojusläbivus: 0; 505_Paksus: 480 mm; 500_Kandev: yes; 335_Välispiire: no
Name | Reference = 205_Tähis | 515_Neto-pindala (m2)
PP-01 | PP-01 | 32.8558
PP-01a | PP-01a | 3.3999

# IfcSlab: PP-02 500 (8)
In: Esimene korrus
Classification: 1.20 IfcSlabType (vahelagi) (BIM ÜBN + Archicad Classification)
Pset_SlabCommon - Reference: PP-02; IsExternal: no; LoadBearing: yes
AR_Plaat - 001_Nimetus: Põrand pinnasel; 325_Helipidavus: nõudeid ei esitata; 330_Tulepüsivus: nõudeid ei esitata; 340_Soojusläbivus: 0; 505_Paksus: 500 mm; 500_Kandev: yes; 205_Tähis: PP-02; 335_Välispiire: no
AR_ÜLD - 009_Märkus: Põrand paksendatud betoonplaadiga, vt. EK-osa
AC_Pset_RenovationAndPhasing - Renovation Status: New
Name | 515_Neto-pindala (m2)
PP-02 | 128.405
PP-02 | 68.172
PP-02 | 82.7856
PP-02 | 36.1597
PP-02 | 36.3416
PP-02 | 104.297
PP-02 | 42.4206
PP-02 | 127.86

# IfcSlab: PP-03a 200, PP-03a
In: Esimene korrus
Classification: 1.20 IfcSlabType (vahelagi) (BIM ÜBN + Archicad Classification); Material: 30 Konst: Raudbetoon monoliitne
AC_Pset_RenovationAndPhasing - Renovation Status: New
AR_Plaat - 001_Nimetus: Põrand pinnasel; 325_Helipidavus: nõudeid ei esitata; 330_Tulepüsivus: nõudeid ei esitata; 340_Soojusläbivus: 0; 505_Paksus: 200 mm; 515_Neto-pindala: 89.4917 m2; 500_Kandev: yes; 205_Tähis: PP-03a; 335_Välispiire: yes
Pset_SlabCommon - Reference: PP-03a; IsExternal: yes; LoadBearing: yes
AR_ÜLD - 009_Märkus: vt. EK-osa

# IfcSlab: PP-03b 520, PP-03b
In: Esimene korrus
Classification: 1.20 IfcSlabType (vahelagi) (BIM ÜBN + Archicad Classification)
AR_Plaat - 001_Nimetus: Põrand pinnasel; 325_Helipidavus: nõudeid ei esitata; 330_Tulepüsivus: nõudeid ei esitata; 340_Soojusläbivus: 0; 505_Paksus: 520 mm; 515_Neto-pindala: 30.6635 m2; 500_Kandev: yes; 205_Tähis: PP-03b; 335_Välispiire: yes
AR_ÜLD - 009_Märkus: vt. EK-osa
AC_Pset_RenovationAndPhasing - Renovation Status: New
Pset_SlabCommon - Reference: PP-03b; IsExternal: yes; LoadBearing: yes

# IfcSlab: VL-01 395 (6)
In: Teine korrus
Classification: 1.20 IfcSlabType (vahelagi) (BIM ÜBN + Archicad Classification)
AR_Plaat - 001_Nimetus: Vahelagi; 325_Helipidavus: R'w / L'n 60dB / 53dB; 330_Tulepüsivus: REI30; 340_Soojusläbivus: 0; 505_Paksus: 395 mm; 500_Kandev: yes; 205_Tähis: VL-01; 335_Välispiire: no
AR_ÜLD - 009_Märkus: vt. EK-osa
Pset_SlabCommon - Reference: VL-01; IsExternal: no; LoadBearing: yes
AC_Pset_RenovationAndPhasing - Renovation Status: New
Name | 515_Neto-pindala (m2)
VL-01 | 12.8088
VL-01 | 77.688
VL-01 | 378.59
VL-01 | 103.904
VL-01 | 14.4676
VL-01 | 338.502

# IfcSlab: VL-01c 415 (3)
In: Teine korrus
Classification: 1.20 IfcSlabType (vahelagi) (BIM ÜBN + Archicad Classification)
Pset_SlabCommon - Reference: VL-01; IsExternal: no; LoadBearing: yes
AR_Plaat - 001_Nimetus: Vahelagi; 325_Helipidavus: R'w / L'n 60dB / 53dB; 330_Tulepüsivus: REI30; 340_Soojusläbivus: 0; 505_Paksus: 415 mm; 500_Kandev: yes; 205_Tähis: VL-01; 335_Välispiire: no
AR_ÜLD - 009_Märkus: vt. EK-osa
AC_Pset_RenovationAndPhasing - Renovation Status: New
Name | 515_Neto-pindala (m2)
VL-01 | 7.30585
VL-01 | 4.9482
VL-01 | 0

# IfcSlab: VL-02a 265, VL-02
In: Teine korrus
Classification: 1.20 IfcSlabType (vahelagi) (BIM ÜBN + Archicad Classification); Material: 30 Konst: Raudbetoon monteeritav
Pset_SlabCommon - Reference: VL-02; IsExternal: no; LoadBearing: yes
AR_Plaat - 001_Nimetus: Vahelagi õhuvõtukambris; 325_Helipidavus: R'w / L'n 60dB / 53dB; 330_Tulepüsivus: REI30; 340_Soojusläbivus: 0; 505_Paksus: 265 mm; 515_Neto-pindala: 16.2345 m2; 500_Kandev: yes; 205_Tähis: VL-02; 335_Välispiire: no
AR_ÜLD - 009_Märkus: vt. EK-osa ja AR-7 sõlmlahendusi
AC_Pset_RenovationAndPhasing - Renovation Status: New

# IfcSlab: VL-02b 410 (4)
In: Teine korrus
Classification: 1.20 IfcSlabType (vahelagi) (BIM ÜBN + Archicad Classification)
Pset_SlabCommon - Reference: VL-02; IsExternal: yes; LoadBearing: yes
AR_Plaat - 001_Nimetus: Vahelagi õhuvõtukambris; 325_Helipidavus: R'w / L'n 60dB / 53dB; 330_Tulepüsivus: nõudeid ei esitata; 340_Soojusläbivus: 0; 505_Paksus: 410 mm; 500_Kandev: yes; 205_Tähis: VL-02; 335_Välispiire: yes
AC_Pset_RenovationAndPhasing - Renovation Status: New
AR_ÜLD - 009_Märkus: vt. EK-osa ja AR-7 sõlmlahendusi
Name | 515_Neto-pindala (m2)
2 x VL-02 | 0.57778
VL-02 | 3.74797
VL-02 | 5.97547

# IfcStair (10)
Classification: 1.22 IfcStair (trepp) (BIM ÜBN + Archicad Classification)
AC_Pset_RenovationAndPhasing - Renovation Status: New
Name | In | 001_Nimetus | 009_Märkus | IsExternal | NumberOfRiser | NumberOfTreads | RiserHeight (mm) | RequiredHeadroom (mm)
TREPP | Esimene korrus | Trepimade | vt. EK- ja SA-osa | no | Material: 30 Konst: Raudbetoon monteeritav
2 x TREPP | Teine korrus | Trepimade | vt. EK- ja SA-osa | no | Material: 30 Konst: Raudbetoon monteeritav
TREPP | Esimene korrus | Sisetrepp | vt. EK- ja SA-osa | no | 16 | 16 | 158 | 2200
TREPP | Esimene korrus | Sisetrepp | vt. EK- ja SA-osa | no | 10 | 11 | 158 | 2200
TREPP | Esimene korrus | Sisetrepp | vt. EK- ja SA-osa | no | 9 | 9 | 158 | 2200
2 x TREPP | Esimene korrus | Välitrepp | vt. EK-osa | yes | 34 | 34 | 137.794 | 2200
TREPP | Teine korrus | Sisetrepp | vt. EK- ja SA-osa | no | 12 | 13 | 158.083 | 2200
TREPP | Teine korrus | Sisetrepp | vt. EK- ja SA-osa | no | 9 | 9 | 158.111 | 2200

# IfcTransportElement: Elevator 26 (2)
Classification: 1.23 IfcTransportElementType (lift) (BIM ÜBN + Archicad Classification)
AR_ÜLD - 009_Märkus: OMA märkus
AC_Pset_RenovationAndPhasing - Renovation Status: New
Name | In
Lift | Esimene korrus
Lift | Teine korrus

# IfcWall: 01 ÜLD: projekteeritav 5, VS-03a
In: Esimene korrus
Classification: 1.24 IfcWallType (sein) (BIM ÜBN + Archicad Classification); Material: 01 ÜLD: projekteeritav
AR_Sein - 001_Nimetus: Välissein; 325_Helipidavus: nõudeid ei esitata; 330_Tulepüsivus: nõudeid ei esitata; 335_Välispiire: yes; 340_Soojusläbivus: 0; 605_Neto-pindala: 5.15953 m2; 600_Bruto-pindala: 24.0537 m2; 500_Kandev: yes; 505_Paksus: 5 mm; 205_Tähis: VS-03a; 376_Viimistlus-väljast: Horisontaalne värvitud laudis, vt. AR-6 vaatejooniseid
AR_ÜLD - 009_Märkus: vt. VS-04 laudis
AC_Pset_RenovationAndPhasing - Renovation Status: New
Pset_WallCommon - Reference: VS-03a; IsExternal: yes; LoadBearing: yes

# IfcWall: 50 Soojustus: PIR 160 (2)
In: Teine korrus
Classification: 1.24 IfcWallType (sein) (BIM ÜBN + Archicad Classification); Material: 50 Soojustus: PIR
Pset_WallCommon - Reference: VS-08; IsExternal: yes; LoadBearing: yes
AR_Sein - 001_Nimetus: Välissein; 325_Helipidavus: nõudeid ei esitata; 330_Tulepüsivus: nõudeid ei esitata; 335_Välispiire: yes; 340_Soojusläbivus: 0; 600_Bruto-pindala: 4.00775 m2; 500_Kandev: yes; 505_Paksus: 160 mm; 205_Tähis: VS-08; 376_Viimistlus-väljast: KF süsteem, vt. AR-8
AR_ÜLD - 009_Märkus: VS-08 osa. vt. AR-7 sõlmlahendused
AC_Pset_RenovationAndPhasing - Renovation Status: New
Name | 605_Neto-pindala (m2)
VS-08 | 0.02415
VS-08 | 0.4255

# IfcWall: 72 Kiht: SW plekk 5, VS-03a
In: Esimene korrus
Classification: 1.24 IfcWallType (sein) (BIM ÜBN + Archicad Classification); Material: 72 Kiht: SW plekk
Pset_WallCommon - Reference: VS-03a; IsExternal: yes; LoadBearing: yes
AR_Sein - 001_Nimetus: Välissein; 325_Helipidavus: nõudeid ei esitata; 330_Tulepüsivus: nõudeid ei esitata; 335_Välispiire: yes; 340_Soojusläbivus: 0; 605_Neto-pindala: 4.31833 m2; 600_Bruto-pindala: 15.7712 m2; 500_Kandev: yes; 505_Paksus: 5 mm; 205_Tähis: VS-03a; 376_Viimistlus-väljast: Horisontaalne värvitud laudis, vt. AR-6 vaatejooniseid
AR_ÜLD - 009_Märkus: vt. VS-04 laudis
AC_Pset_RenovationAndPhasing - Renovation Status: New

# IfcWall: SL-02 100 (11)
In: Esimene korrus
Classification: 1.24 IfcWallType (sein) (BIM ÜBN + Archicad Classification)
AR_Sein - 335_Välispiire: no; 340_Soojusläbivus: 0; 500_Kandev: no; 505_Paksus: 100 mm
Pset_WallCommon - IsExternal: no; LoadBearing: no
AC_Pset_RenovationAndPhasing - Renovation Status: New
Name | 001_Nimetus | 330_Tulepüsivus | 605_Neto-pindala (m2) | 600_Bruto-pindala (m2) | 205_Tähis = Reference
SL-02 | SW-paneel lisavooder | EI30 | 18.2602 | 18.7317 | SL-02
SL-02 | SW-paneel lisavooder | EI30 | 0.8 | 0.8 | SL-02
SL-02 | SW-paneel lisavooder | EI30 | 2.4005 | 2.7 | SL-02
SL-02 | SW-paneel lisavooder | EI30 | 2.4 | 2.4 | SL-02
SL-02 | SW-paneel lisavooder | EI30 | 14.58 | 14.8795 | SL-02
SL-02 | SW-paneel lisavooder | EI30 | 0.8866 | 0.8866 | SL-02
SL-02 | SW-paneel lisavooder | EI30 | 2.7756 | 2.77563 | SL-02
SL-02 | SW-paneel lisavooder | EI30 | 5.82587 | 5.82587 | SL-02
SS-03a | Ripplae karniis | nõudeid ei esitata | 4.4226 | 4.4226 | SS-03a | AR_Sein - 325_Helipidavus: R’w ≥ 31 dB; 376_Viimistlus-väljast: vt. SA-osa; AR_ÜLD - 009_Märkus: vt. AR-8 konstruktsioonitüüpe
SL-02 | SW-paneel lisavooder | EI30 | 8.39947 | 8.3995 | SL-02
SL-02 | SW-paneel lisavooder | EI30 | 18.2597 | 18.7307 | SL-02

# IfcWall: SS-01 190 (44)
Classification: 1.24 IfcWallType (sein) (BIM ÜBN + Archicad Classification); Material: 30 Konst: Columbia õõnesplokk
Pset_WallCommon - IsExternal: no
AR_Sein - 335_Välispiire: no; 340_Soojusläbivus: 0; 505_Paksus: 190 mm; 376_Viimistlus-väljast: vt. SA-osa
AC_Pset_RenovationAndPhasing - Renovation Status: New
Name | In | Reference = 205_Tähis | LoadBearing = 500_Kandev | 001_Nimetus | 325_Helipidavus | 330_Tulepüsivus | 605_Neto-pindala (m2) | 600_Bruto-pindala (m2)
SS-01 | Esimene korrus | SS-01 | no | Sisesein | R’w ≥ 55 dB | nõudeid ei esitata | 12.6392 | 17.7435
SS-01 | Esimene korrus | SS-01 | no | Sisesein | R’w ≥ 55 dB | nõudeid ei esitata | 9.223 | 10.6408
SS-01b | Esimene korrus | SS-01b | yes | Sisesein lisavooderdusega | R’tr,s,w ≥ 55 dB | EI30 | 24.2531 | 29.0605 | AR_ÜLD - 009_Märkus: SS-01 seinatüüp SL-01 lisavoodriga
SS-01 | Esimene korrus | SS-01 | yes | Sisesein | R’w ≥ 55 dB | EI30 | 15.0719 | 17.4623
SS-01 | Esimene korrus | SS-01 | no | Sisesein | R’w ≥ 55 dB | nõudeid ei esitata | 10.9216 | 14.3829
SS-01 | Esimene korrus | SS-01 | yes | Sisesein | R’w ≥ 55 dB | nõudeid ei esitata | 7.12625 | 8.98805
3 x SS-01 | Esimene korrus | SS-01 | yes | Sisesein | R’w ≥ 55 dB | nõudeid ei esitata | 27.8331 | 29.0605
SS-01 | Esimene korrus | SS-01 | yes | Sisesein | R’w ≥ 55 dB | EI30 | 25.1481 | 29.0605
SS-01 | Esimene korrus | SS-01 | yes | Sisesein | R’w ≥ 55 dB | EI30 | 27.8331 | 29.0605
SS-01 | Esimene korrus | SS-01 | no | Sisesein | R’w ≥ 55 dB | EI30 | 25.1767 | 29.4215
SS-01 | Esimene korrus | SS-01 | yes | Sisesein | R’w ≥ 55 dB | nõudeid ei esitata | 26.0331 | 29.0605
SS-01 | Esimene korrus | SS-01 | no | Sisesein | R’w ≥ 55 dB | nõudeid ei esitata | 28.6211 | 32.2812
SS-01 | Esimene korrus | SS-01 | no | Sisesein | R’w ≥ 55 dB | nõudeid ei esitata | 29.9547 | 32.2812
2 x SS-01 | Esimene korrus | SS-01 | no | Sisesein | R’w ≥ 55 dB | nõudeid ei esitata | 30.8211 | 32.2812
SS-01 | Esimene korrus | SS-01 | no | Sisesein | R’w ≥ 55 dB | nõudeid ei esitata | 8.4678 | 20.0703
SS-01 | Esimene korrus | SS-01 | yes | Sisesein | R’w ≥ 55 dB | nõudeid ei esitata | 10.9022 | 11.5881
SS-01 | Esimene korrus | SS-01 | yes | Sisesein | R’w ≥ 55 dB | EI30 | 14.0479 | 18.1222
SS-01 | Esimene korrus | SS-01 | yes | Sisesein | R’w ≥ 55 dB | EI30 | 14.462 | 17.4623
SS-01 | Esimene korrus | SS-01 | yes | Sisesein | R’w ≥ 55 dB | nõudeid ei esitata | 5.93625 | 9.30905
SS-01 | Esimene korrus | SS-01 | yes | Sisesein | R’w ≥ 55 dB | nõudeid ei esitata | 5.93625 | 8.37815
SS-01 | Esimene korrus | SS-01 | no | Sisesein | R’w ≥ 55 dB | nõudeid ei esitata | 7.942 | 9.6748
SS-01 | Esimene korrus | SS-01 | no | Sisesein | R’w ≥ 55 dB | EI30 | 5.6289 | 12.2705
SS-01 | Esimene korrus | SS-01 | no | Sisesein | R’w ≥ 55 dB | nõudeid ei esitata | 5.2781 | 9.3707
SS-01b | Esimene korrus | SS-01b | yes | Sisesein lisavooderdusega | R’tr,s,w ≥ 55 dB | EI30 | 5.1372 | 9.0972 | AR_ÜLD - 009_Märkus: SS-01 seinatüüp SL-01 lisavoodriga
SS-01b | Esimene korrus | SS-01b | yes | Sisesein lisavooderdusega | R’tr,s,w ≥ 55 dB | EI30 | 23.8951 | 29.0605 | AR_ÜLD - 009_Märkus: SS-01 seinatüüp SL-01 lisavoodriga
SS-01 | Esimene korrus | SS-01 | yes | Sisesein | R’w ≥ 55 dB | nõudeid ei esitata | 9.2777 | 9.9636
SS-01 | Esimene korrus | SS-01 | no | Sisesein | R’w ≥ 55 dB | nõudeid ei esitata | 11.8865 | 15.2459
SS-01 | Esimene korrus | SS-01 | no | Sisesein | R’w ≥ 55 dB | nõudeid ei esitata | 9.07494 | 10.3745
SS-01 | Esimene korrus | SS-01 | no | Sisesein | R’w ≥ 55 dB | nõudeid ei esitata | 7.8595 | 11.1603
SS-01 | Esimene korrus | SS-01 | no | Sisesein | R’w ≥ 55 dB | EI30 | 18.1443 | 19.0752
SS-01 | Teine korrus | SS-01 | yes | Sisesein | R’w ≥ 55 dB | EI30 | 31.5234 | 33.971
SS-01 | Teine korrus | SS-01 | yes | Sisesein | R’w ≥ 55 dB | EI30 | 31.5234 | 34.0074
SS-01 | Teine korrus | SS-01 | no | Sisesein | R’w ≥ 55 dB | nõudeid ei esitata | 9.284 | 11.3096
SS-01 | Teine korrus | SS-01 | no | Sisesein | R’w ≥ 55 dB | EI30 | 31.5234 | 34.0074
SS-01 | Teine korrus | SS-01 | yes | Sisesein | R’w ≥ 55 dB | nõudeid ei esitata | 11.7318 | 13.5828
SS-01 | Teine korrus | SS-01 | yes | Sisesein | R’w ≥ 55 dB | nõudeid ei esitata | 42.1564 | 52.1592
SS-01 | Teine korrus | SS-01 | no | Sisesein | R’w ≥ 55 dB | nõudeid ei esitata | 9.706 | 11.3096
SS-01 | Teine korrus | SS-01 | yes | Sisesein | R’w ≥ 55 dB | nõudeid ei esitata | 19.6642 | 26.4172
SS-01 | Teine korrus | SS-01 | no | Sisesein | R’w ≥ 55 dB | EI30 | 29.4234 | 33.971
SS-01 | Teine korrus | SS-01 | yes | Sisesein | R’w ≥ 55 dB | nõudeid ei esitata | 10.8454 | 11.6472
SS-01 | Katus | SS-01 | yes | Sisesein | R’w ≥ 55 dB | EI30 | 3.18686 | 4.499 | AR_ÜLD - 009_Märkus: vt. AR-7 sõlmlahendusi

# IfcWall: SS-01_2 190 (2)
In: Teine korrus
Classification: 1.24 IfcWallType (sein) (BIM ÜBN + Archicad Classification); Material: 30 Konst: Columbia õõnesplokk 2
AR_Sein - 001_Nimetus: Sisesein; 325_Helipidavus: R’w ≥ 55 dB; 330_Tulepüsivus: nõudeid ei esitata; 335_Välispiire: no; 340_Soojusläbivus: 0; 605_Neto-pindala: 19.4322 m2; 600_Bruto-pindala: 21.5908 m2; 500_Kandev: yes; 505_Paksus: 190 mm; 205_Tähis: SS-01; 376_Viimistlus-väljast: vt. SA-osa
AC_Pset_RenovationAndPhasing - Renovation Status: New
Pset_WallCommon - Reference: SS-01; IsExternal: no; LoadBearing: yes

# IfcWall: SS-01a 140 (2)
In: Esimene korrus
Classification: 1.24 IfcWallType (sein) (BIM ÜBN + Archicad Classification); Material: 30 Konst: Columbia õõnesplokk
Pset_WallCommon - Reference: SS-01a; IsExternal: no; LoadBearing: no
AR_Sein - 001_Nimetus: Sisesein; 325_Helipidavus: nõudeid ei esitata; 330_Tulepüsivus: nõudeid ei esitata; 335_Välispiire: no; 340_Soojusläbivus: 0; 500_Kandev: no; 505_Paksus: 140 mm; 205_Tähis: SS-01a
AR_ÜLD - 009_Märkus: 140mm õõnesbetoonplokk
AC_Pset_RenovationAndPhasing - Renovation Status: New
Name | 605_Neto-pindala (m2) | 600_Bruto-pindala (m2)
SS-01a | 6.927 | 9.7324
SS-01a | 14.9974 | 15.9386

# IfcWall: SS-01b 50 (4)
In: Esimene korrus
Classification: 1.24 IfcWallType (sein) (BIM ÜBN + Archicad Classification)
Pset_WallCommon - Reference: SS-01b; IsExternal: no; LoadBearing: yes
AR_ÜLD - 009_Märkus: SS-01 seinatüüp SL-01 lisavoodriga
AR_Sein - 325_Helipidavus: R’tr,s,w ≥ 55 dB; 330_Tulepüsivus: EI30; 335_Välispiire: no; 340_Soojusläbivus: 0; 500_Kandev: yes; 505_Paksus: 50 mm; 205_Tähis: SS-01b; 376_Viimistlus-väljast: vt. SA-osa
AC_Pset_RenovationAndPhasing - Renovation Status: New
Name | 001_Nimetus | 605_Neto-pindala (m2) | 600_Bruto-pindala (m2)
SS-01b | Sisesein lisavooderdusega | 26.5097 | 29.4215
SS-01b | Siseseina lisavooderdus | 5.1392 | 10.1052
SS-01b | Siseseina lisavooderdus | 26.1516 | 32.2278
SS-01b | Siseseina lisavooderdus | 25.7136 | 32.2278

# IfcWall: SS-02 240 (32)
Classification: 1.24 IfcWallType (sein) (BIM ÜBN + Archicad Classification); Material: 30 Konst: Columbia õõnesplokk
AR_Sein - 001_Nimetus: Sisesein; 335_Välispiire: no; 340_Soojusläbivus: 0; 505_Paksus: 240 mm; 376_Viimistlus-väljast: vt. SA-osa
AC_Pset_RenovationAndPhasing - Renovation Status: New
Name | In | Reference = 205_Tähis | IsExternal | LoadBearing = 500_Kandev | 325_Helipidavus | 330_Tulepüsivus | 605_Neto-pindala (m2) | 600_Bruto-pindala (m2)
SS-02 | Esimene korrus | SS-02 | no | yes | R’w ≥ 56 dB | nõudeid ei esitata | 162.593 | 196.059
SS-02 | Esimene korrus | SS-02 | no | yes | R’w ≥ 56 dB | EI30 | 30.5087 | 34.2589
SS-02 | Esimene korrus | SS-02 | no | yes | R’w ≥ 56 dB | nõudeid ei esitata | 27.8331 | 29.0605
SS-02 | Esimene korrus | SS-02 |  | no | R’w ≥ 56 dB | nõudeid ei esitata | 29.9547 | 32.2812
SS-02 | Esimene korrus | SS-02 | no | yes | R’w ≥ 56 dB | nõudeid ei esitata | 26.9667 | 29.0605
SS-02 | Esimene korrus | SS-02 | no | yes | R’w ≥ 56 dB | EI30 | 17.6048 | 19.855
SS-02 | Esimene korrus | SS-02 | no | yes | R’w ≥ 56 dB | nõudeid ei esitata | 10.0719 | 11.8047
SS-02 | Esimene korrus | SS-02 | no | yes | R’w ≥ 56 dB | nõudeid ei esitata | 6.5341 | 8.4474
SS-02 | Esimene korrus | SS-02 | no | yes | R’w ≥ 56 dB | EI30 | 26.7862 | 29.0605
SS-02 | Esimene korrus | SS-02 | no | no | R’w ≥ 56 dB | nõudeid ei esitata | 1.444 | 2.6714
SS-02 | Esimene korrus | SS-02 | no | yes | R’w ≥ 56 dB | nõudeid ei esitata | 6.6552 | 8.5432
SS-02 | Esimene korrus | SS-02 | no | yes | R’w ≥ 56 dB | EI30 | 9.9828 | 11.1188
SS-02 | Esimene korrus | SS-02 | no | yes | R’w ≥ 56 dB | nõudeid ei esitata | 108.92 | 124.726
SS-02 | Esimene korrus | SS-02 | no | yes | R’w ≥ 56 dB | EI30 | 6.686 | 10.4329
SS-02 | Esimene korrus | SS-02 | no | yes | R’w ≥ 56 dB | nõudeid ei esitata | 10.9338 | 18.5915
SS-02 | Teine korrus | SS-02 | no | no | R’w ≥ 56 dB | nõudeid ei esitata | 5.262 | 13.7994
SS-02 | Teine korrus | SS-02 | no | yes | R’w ≥ 56 dB | nõudeid ei esitata | 18.3722 | 24.8558
SS-02 | Teine korrus | SS-02 | no | yes | R’w ≥ 56 dB | EI30 | 37.9568 | 46.7154
SS-02 | Teine korrus | SS-02 | no | yes | R’w ≥ 56 dB | nõudeid ei esitata | 3.47561 | 3.47561
SS-01 | Teine korrus | SS-01 | no | yes | R’w ≥ 55 dB | EI30 | 32.6628 | 32.6628
SS-02 | Teine korrus | SS-02 | no | yes | R’w ≥ 56 dB | nõudeid ei esitata | 29.7872 | 34.2242
SS-02 | Teine korrus | SS-02 | no | yes | R’w ≥ 56 dB | nõudeid ei esitata | 19.4582 | 24.9402
SS-02 | Teine korrus | SS-02 | no | yes | R’w ≥ 56 dB | EI30 | 7.1838 | 11.7738
SS-02 | Teine korrus | SS-02 | no | yes | R’w ≥ 56 dB | nõudeid ei esitata | 17.7903 | 18.8813
SS-02 | Teine korrus | SS-02 | no | no | R’w ≥ 56 dB | nõudeid ei esitata | 2.8662 | 12.7742
SS-02 | Teine korrus | SS-02 | no | no | R’w ≥ 56 dB | nõudeid ei esitata | 2.86781 | 13.715
SS-02 | Teine korrus | SS-02 | no | yes | R’w ≥ 56 dB | nõudeid ei esitata | 12.5152 | 21.733
SS-02 | Teine korrus | SS-02 | no | yes | R’w ≥ 56 dB | EI30 | 45.6452 | 46.1668
SS-02 | Teine korrus | SS-02 | no | yes | R’w ≥ 56 dB | nõudeid ei esitata | 18.3722 | 24.3743
SS-02 | Teine korrus | SS-02 | no | yes | R’w ≥ 56 dB | nõudeid ei esitata | 3.4124 | 3.4124
2 x SS-02 | Teine korrus | SS-02 | no | yes | R’w ≥ 56 dB | nõudeid ei esitata | 3.376 | 3.376

# IfcWall: SS-02b 290 (2)
In: Esimene korrus
Classification: 1.24 IfcWallType (sein) (BIM ÜBN + Archicad Classification)
Pset_WallCommon - Reference: SS-02b; IsExternal: no; LoadBearing: yes
AC_Pset_RenovationAndPhasing - Renovation Status: New
AR_ÜLD - 009_Märkus: SS-02 seinatüüp SL-01 lisavoodriga
AR_Sein - 001_Nimetus: Sisesein; 325_Helipidavus: R’w ≥ 56 dB; 335_Välispiire: no; 340_Soojusläbivus: 0; 500_Kandev: yes; 505_Paksus: 290 mm; 205_Tähis: SS-02b; 376_Viimistlus-väljast: vt. SA-osa
Name | 330_Tulepüsivus | 605_Neto-pindala (m2) | 600_Bruto-pindala (m2)
SS-02b | EI30 | 24.9086 | 29.0605
SS-02b | nõudeid ei esitata | 10.826 | 18.2305

# IfcWall: SS-03 145 (45)
Classification: 1.24 IfcWallType (sein) (BIM ÜBN + Archicad Classification)
Pset_WallCommon - IsExternal: no; LoadBearing: no
AR_Sein - 001_Nimetus: Sisesein; 335_Välispiire: no; 340_Soojusläbivus: 0; 500_Kandev: no; 505_Paksus: 145 mm; 376_Viimistlus-väljast: vt. SA-osa
AC_Pset_RenovationAndPhasing - Renovation Status: New
Name | In | Reference = 205_Tähis | 325_Helipidavus | 330_Tulepüsivus | 605_Neto-pindala (m2) | 600_Bruto-pindala (m2) | 009_Märkus
SS-03 | Esimene korrus | SS-03 | R’w ≥ 48 dB | nõudeid ei esitata | 6.69747 | 8.44256 | kergsein
SS-03 | Teine korrus | SS-03 | R’w ≥ 48 dB | nõudeid ei esitata | 19.4726 | 36.2579 | kergsein
SS-03 | Teine korrus | SS-03 | R’w ≥ 48 dB | nõudeid ei esitata | 13.796 | 18.9689 | kergsein
SS-03 | Teine korrus | SS-03 | R’w ≥ 48 dB | nõudeid ei esitata | 77.9404 | 140.348 | kergsein
7 x SS-03 | Teine korrus | SS-03 | R’w ≥ 48 dB | nõudeid ei esitata | 18.9571 | 20.9408 | kergsein
SS-03 | Teine korrus | SS-03 | R’w ≥ 48 dB | nõudeid ei esitata | 16.3191 | 18.3028 | kergsein
SS-03 | Teine korrus | SS-03 | R’w ≥ 48 dB | nõudeid ei esitata | 1.44517 | 5.908 | kergsein
SS-03 | Teine korrus | SS-03 | R’w ≥ 48 dB | nõudeid ei esitata | 23.6198 | 25.6398 | kergsein
SS-03 | Teine korrus | SS-03 | R’w ≥ 48 dB | nõudeid ei esitata | 6.83175 | 8.70737 | kergsein
SS-03 | Teine korrus | SS-03 | R’w ≥ 48 dB | EI30 | 15.8554 | 17.3482 | kergsein
SS-03 | Teine korrus | SS-03 | R’w ≥ 48 dB | nõudeid ei esitata | 3.60983 | 12.2591 | kergsein
SS-03 | Teine korrus | SS-03 | R’w ≥ 48 dB | nõudeid ei esitata | 3.60865 | 12.2591 | kergsein
SS-03 | Teine korrus | SS-03 | R’w ≥ 48 dB | nõudeid ei esitata | 10.6425 | 12.66 | kergsein
SS-03 | Teine korrus | SS-03 | R’w ≥ 48 dB | nõudeid ei esitata | 12.8092 | 13.0398 | kergsein
SS-03 | Teine korrus | SS-03 | R’w ≥ 48 dB | nõudeid ei esitata | 5.67488 | 6.7076 | kergsein
SS-03 | Teine korrus | SS-03 | R’w ≥ 48 dB | nõudeid ei esitata | 1.56125 | 6.9508 | kergsein
2 x SS-04 | Teine korrus | SS-04 | R’w ≥ 45 dB | nõudeid ei esitata | 5.4945 | 6.7112
SS-03 | Teine korrus | SS-03 | R’w ≥ 48 dB | nõudeid ei esitata | 5.25156 | 6.7076 | kergsein
SS-03 | Teine korrus | SS-03 | R’w ≥ 48 dB | EI30 | 11.2373 | 11.2884 | kergsein
SS-03 | Teine korrus | SS-03 | R’w ≥ 48 dB | EI30 | 13.0619 | 13.1132 | kergsein
SS-03 | Teine korrus | SS-03 | R’w ≥ 48 dB | nõudeid ei esitata | 13.8969 | 19.0321 | kergsein
SS-03 | Teine korrus | SS-03 | R’w ≥ 48 dB | nõudeid ei esitata | 16.0018 | 17.9854 | kergsein
SS-03 | Teine korrus | SS-03 | R’w ≥ 48 dB | nõudeid ei esitata | 5.10785 | 6.7112 | kergsein
SS-03 | Teine korrus | SS-03 | R’w ≥ 48 dB | EI30 | 8.1976 | 12.27 | kergsein
SS-03 | Teine korrus | SS-03 | R’w ≥ 48 dB | nõudeid ei esitata | 18.6669 | 24.3718 | kergsein
SS-03 | Teine korrus | SS-03 | R’w ≥ 48 dB | nõudeid ei esitata | 28.9572 | 31.1249 | kergsein
SS-03 | Teine korrus | SS-03 | R’w ≥ 48 dB | nõudeid ei esitata | 8.12615 | 12.5768 | kergsein
SS-03 | Teine korrus | SS-03 | R’w ≥ 48 dB | nõudeid ei esitata | 6.80985 | 6.80985 | kergsein
SS-03 | Teine korrus | SS-03 | R’w ≥ 48 dB | nõudeid ei esitata | 5.25156 | 5.9305 | kergsein
SS-03 | Teine korrus | SS-03 | R’w ≥ 48 dB | nõudeid ei esitata | 2.62783 | 3.11863 | kergsein
2 x SS-03 | Teine korrus | SS-03 | R’w ≥ 48 dB | nõudeid ei esitata | 8.61615 | 12.2169 | kergsein
SS-03 | Teine korrus | SS-03 | R’w ≥ 48 dB | nõudeid ei esitata | 2.3976 | 2.7108 | kergsein
SS-03 | Teine korrus | SS-03 | R’w ≥ 48 dB | nõudeid ei esitata | 7.4328 | 12.679 | kergsein
SS-03 | Teine korrus | SS-03 | R’w ≥ 48 dB | nõudeid ei esitata | 5.10785 | 5.7344 | kergsein
SS-03 | Teine korrus | SS-03 | R’w ≥ 48 dB | EI30 | 12.4336 | 13.063 | kergsein
SS-03 | Teine korrus | SS-03 | R’w ≥ 48 dB | EI30 | 12.7954 | 15.8554 | kergsein
SS-03 | Teine korrus | SS-03 | R’w ≥ 48 dB | nõudeid ei esitata | 63.091 | 77.9489 | kergsein

# IfcWall: SS-03a 110 (22)
In: Esimene korrus
Classification: 1.24 IfcWallType (sein) (BIM ÜBN + Archicad Classification)
Pset_WallCommon - Reference: SS-03a; IsExternal: no; LoadBearing: no
AR_Sein - 001_Nimetus: Ripplae karniis; 325_Helipidavus: R’w ≥ 31 dB; 330_Tulepüsivus: nõudeid ei esitata; 335_Välispiire: no; 340_Soojusläbivus: 0; 500_Kandev: no; 505_Paksus: 110 mm; 205_Tähis: SS-03a; 376_Viimistlus-väljast: vt. SA-osa
AC_Pset_RenovationAndPhasing - Renovation Status: New
Name | 605_Neto-pindala (m2) | 600_Bruto-pindala (m2) | 009_Märkus
SS-03a | 4.48056 | 4.48056 | vt. SA-osa
SS-03a | 5.63667 | 5.91355 | vt. AR-8 konstruktsioonitüüpe
SS-03a | 5.5919 | 5.8681 | vt. AR-8 konstruktsioonitüüpe
SS-03a | 5.2337 | 5.5045 | vt. AR-8 konstruktsioonitüüpe
SS-03a | 2.67157 | 2.9694 | vt. AR-8 konstruktsioonitüüpe
SS-03a | 5.572 | 6.0398 | vt. AR-8 konstruktsioonitüüpe
SS-03a | 5.67648 | 6.00445 | vt. AR-8 konstruktsioonitüüpe
SS-03a | 5.48245 | 6.0499 | vt. AR-8 konstruktsioonitüüpe
SS-03a | 3.39295 | 3.636 | vt. AR-8 konstruktsioonitüüpe
SS-03a | 4.0397 | 4.1006 | vt. AR-8 konstruktsioonitüüpe
SS-03a | 5.48245 | 5.757 | vt. AR-8 konstruktsioonitüüpe
SS-03a | 16.7757 | 17.5639 | vt. AR-8 konstruktsioonitüüpe
SS-03a | 5.4327 | 6.0499 | vt. AR-8 konstruktsioonitüüpe
SS-03a | 5.6715 | 5.9489 | vt. AR-8 konstruktsioonitüüpe
SS-03a | 5.6317 | 5.7671 | vt. AR-8 konstruktsioonitüüpe
SS-03a | 4.8357 | 4.9086 | vt. AR-8 konstruktsioonitüüpe
2 x SS-03a | 0.95256 | 0.95256 | vt. SA-osa
SS-03a | 4.45032 | 4.48056 | vt. SA-osa
SS-03a | 0.95256 | 1.00557 | vt. SA-osa
SS-03a | 0.952875 | 1.00553 | vt. SA-osa
SS-03a | 0.95256 | 0.952875 | vt. SA-osa

# IfcWall: SS-03b 120 (5)
Classification: 1.24 IfcWallType (sein) (BIM ÜBN + Archicad Classification)
Pset_WallCommon - Reference: SS-03b; IsExternal: no; LoadBearing: no
AR_Sein - 001_Nimetus: Sisesein; 325_Helipidavus: R’w ≥ 31 dB; 330_Tulepüsivus: EI30; 335_Välispiire: no; 340_Soojusläbivus: 0; 500_Kandev: no; 505_Paksus: 120 mm; 205_Tähis: SS-03b; 376_Viimistlus-väljast: vt. SA-osa
AC_Pset_RenovationAndPhasing - Renovation Status: New
AR_ÜLD - 009_Märkus: Šahtisein
Name | In | 605_Neto-pindala (m2) | 600_Bruto-pindala (m2)
SS-03b | Esimene korrus | 3.15788 | 3.85953
SS-03b | Esimene korrus | 2.10501 | 3.47659
SS-03b | Teine korrus | 2.62373 | 3.60533
SS-03b | Teine korrus | 2.42045 | 3.60533
SS-03b | Teine korrus | 2.6585 | 3.25155

# IfcWall: SS-03c 120 (13)
Classification: 1.24 IfcWallType (sein) (BIM ÜBN + Archicad Classification)
Pset_WallCommon - Reference: SS-03c; IsExternal: no; LoadBearing: no
AR_Sein - 001_Nimetus: Ripplae sirm; 325_Helipidavus: nõudeid ei esitata; 330_Tulepüsivus: nõudeid ei esitata; 335_Välispiire: no; 340_Soojusläbivus: 0; 500_Kandev: no; 505_Paksus: 120 mm; 205_Tähis: SS-03c; 376_Viimistlus-väljast: vt. SA-osa
AR_ÜLD - 009_Märkus: Akustiline paneel
AC_Pset_RenovationAndPhasing - Renovation Status: New
Name | In | 605_Neto-pindala (m2) | 600_Bruto-pindala (m2)
SS-03c | Esimene korrus | 2.574 | 2.7621
SS-03c | Esimene korrus | 2.2113 | 2.4297
2 x SS-03c | Esimene korrus | 1.15798 | 1.4742
SS-03c | Esimene korrus | 3.45398 | 3.45398
2 x SS-03c | Esimene korrus | 2.57075 | 2.7664
2 x SS-03c | Esimene korrus | 1.1466 | 1.365
SS-03c | Esimene korrus | 3.4433 | 3.4433
2 x SS-03c | Teine korrus | 0.594 | 0.66
SS-03c | Teine korrus | 0.7964 | 0.7964

# IfcWall: SS-04 116 (6)
In: Teine korrus
Classification: 1.24 IfcWallType (sein) (BIM ÜBN + Archicad Classification)
Pset_WallCommon - IsExternal: no; LoadBearing: no
AR_Sein - 001_Nimetus: Sisesein; 325_Helipidavus: R’w ≥ 45 dB; 330_Tulepüsivus: nõudeid ei esitata; 335_Välispiire: no; 340_Soojusläbivus: 0; 500_Kandev: no; 505_Paksus: 116 mm; 376_Viimistlus-väljast: vt. SA-osa
AC_Pset_RenovationAndPhasing - Renovation Status: New
Name | Reference = 205_Tähis | 605_Neto-pindala (m2) | 600_Bruto-pindala (m2)
2 x SS-04 | SS-04 | 5.10785 | 6.7112
SS-04 | SS-04 | 5.726 | 7.1166
SS-04 | SS-04 | 20.6199 | 31.6566
SS-05 | SS-05 | 6.57877 | 7.40699
SS-04 | SS-04 | 3.17136 | 6.55627

# IfcWall: SS-04a 91 (6)
Classification: 1.24 IfcWallType (sein) (BIM ÜBN + Archicad Classification)
AR_ÜLD - 009_Märkus: Loputuskasti tagune
AR_Sein - 001_Nimetus: Sisesein; 325_Helipidavus: nõudeid ei esitata; 330_Tulepüsivus: nõudeid ei esitata; 335_Välispiire: no; 340_Soojusläbivus: 0; 500_Kandev: no; 505_Paksus: 91 mm; 205_Tähis: SS-04a; 376_Viimistlus-väljast: vt. SA-osa
Pset_WallCommon - Reference: SS-04a; IsExternal: no; LoadBearing: no
AC_Pset_RenovationAndPhasing - Renovation Status: New
Name | In | 605_Neto-pindala (m2) | 600_Bruto-pindala (m2)
SS-04a | Esimene korrus | 2.588 | 2.9641
SS-04a | Esimene korrus | 8.349 | 9.7284
2 x SS-04a | Teine korrus | 5.25156 | 6.7076
SS-04a | Teine korrus | 2.60216 | 3.0378
SS-04a | Teine korrus | 3.78532 | 4.5122

# IfcWall: SS-05 240 (2)
In: Teine korrus
Classification: 1.24 IfcWallType (sein) (BIM ÜBN + Archicad Classification)
Pset_WallCommon - Reference: SS-05; IsExternal: no; LoadBearing: no
AC_Pset_RenovationAndPhasing - Renovation Status: New
AR_Sein - 001_Nimetus: Sisesein; 325_Helipidavus: R’w ≥ 45 dB; 330_Tulepüsivus: nõudeid ei esitata; 335_Välispiire: no; 340_Soojusläbivus: 0; 500_Kandev: no; 505_Paksus: 240 mm; 205_Tähis: SS-05; 376_Viimistlus-väljast: vt. SA-osa
Name | 605_Neto-pindala (m2) | 600_Bruto-pindala (m2)
SS-05 | 7.6206 | 25.0188
SS-05 | 5.628 | 11.816

# IfcWall: SS-06 220 (4)
In: Teine korrus
Classification: 1.24 IfcWallType (sein) (BIM ÜBN + Archicad Classification)
Pset_WallCommon - Reference: SS-03; IsExternal: no; LoadBearing: no
AR_Sein - 001_Nimetus: Sisesein; 325_Helipidavus: R’w ≥ 48 dB; 330_Tulepüsivus: nõudeid ei esitata; 335_Välispiire: no; 340_Soojusläbivus: 0; 500_Kandev: no; 505_Paksus: 220 mm; 205_Tähis: SS-03; 376_Viimistlus-väljast: vt. SA-osa
AR_ÜLD - 009_Märkus: kergsein
AC_Pset_RenovationAndPhasing - Renovation Status: New
Name | 605_Neto-pindala (m2) | 600_Bruto-pindala (m2)
SS-03 | 29.5236 | 32.1142
SS-03 | 11.405 | 12.9765
SS-03 | 21.0334 | 26.4536
SS-03 | 12.1976 | 13.4771

# IfcWall: VS-01_KURMIK 150, VS-01
In: Vundament
Classification: 1.24 IfcWallType (sein) (BIM ÜBN + Archicad Classification); Material: 50 Soojustus: XPS
Pset_WallCommon - Reference: VS-01; IsExternal: yes; LoadBearing: yes
AC_Pset_RenovationAndPhasing - Renovation Status: New
AR_Sein - 001_Nimetus: Välissein soklis; 325_Helipidavus: nõudeid ei esitata; 330_Tulepüsivus: nõudeid ei esitata; 335_Välispiire: yes; 340_Soojusläbivus: 0; 605_Neto-pindala: 9.66605 m2; 600_Bruto-pindala: 9.66605 m2; 500_Kandev: yes; 505_Paksus: 150 mm; 205_Tähis: VS-01; 376_Viimistlus-väljast: Krohvisüsteem, vt. AR-6 vaatejooniseid

# IfcWall: VS-01b 10 (2)
In: Vundament
Classification: 1.24 IfcWallType (sein) (BIM ÜBN + Archicad Classification); Material: 92 Viim: betoonlasuur
Pset_WallCommon - Reference: VS-01b; IsExternal: yes; LoadBearing: yes
AR_Sein - 001_Nimetus: Välissein soklis; 325_Helipidavus: nõudeid ei esitata; 330_Tulepüsivus: nõudeid ei esitata; 335_Välispiire: yes; 340_Soojusläbivus: 0; 500_Kandev: yes; 505_Paksus: 10 mm; 205_Tähis: VS-01b; 376_Viimistlus-väljast: Krohvisüsteem, vt. AR-6 vaatejooniseid
AR_ÜLD - 009_Märkus: Krohvikiht, vt. VS-01
AC_Pset_RenovationAndPhasing - Renovation Status: New
Name | 605_Neto-pindala (m2) | 600_Bruto-pindala (m2)
VS-01b | 12.0765 | 74.6366
VS-01b | 7.30662 | 73.5063

# IfcWall: VS-02_KURMIK 160 (26)
In: Vundament
Classification: 1.24 IfcWallType (sein) (BIM ÜBN + Archicad Classification)
Pset_WallCommon - Reference: VS-02; IsExternal: yes; LoadBearing: yes
AR_Sein - 001_Nimetus: Välissein soklis; 325_Helipidavus: nõudeid ei esitata; 330_Tulepüsivus: nõudeid ei esitata; 335_Välispiire: yes; 340_Soojusläbivus: 0; 500_Kandev: yes; 505_Paksus: 160 mm; 205_Tähis: VS-02; 376_Viimistlus-väljast: Krohvisüsteem, vt. AR-6 vaatejooniseid
AC_Pset_RenovationAndPhasing - Renovation Status: New
Name | 605_Neto-pindala (m2) | 600_Bruto-pindala (m2)
2 x VS-02 | 0.8008 | 0.8008
VS-02 | 1.87485 | 1.87485
VS-02 | 0.839551 | 0.843901
VS-02 | 5.70286 | 5.70286
VS-02 | 18.257 | 18.2613
VS-02 | 0.371801 | 0.371801
VS-02 | 2.23155 | 2.2359
2 x VS-02 | 1.2789 | 1.2789
VS-02 | 2.61435 | 2.61435
VS-02 | 0.648211 | 0.648211
4 x VS-02 | 0.3718 | 0.3718
VS-02 | 5.69416 | 5.69416
VS-02 | 10.7402 | 10.7402
VS-02 | 0.648151 | 0.648151
VS-02 | 0.648148 | 0.648148
VS-02 | 0.970051 | 0.974401
VS-02 | 1.0092 | 1.0092
VS-02 | 0.3948 | 0.3948
VS-02 | 3.42345 | 3.42345
VS-02 | 0.843901 | 0.843901
VS-02 | 0.61329 | 0.61329

# IfcWall: VS-03 390, VS-03
In: Esimene korrus
Classification: 1.24 IfcWallType (sein) (BIM ÜBN + Archicad Classification)
Pset_WallCommon - Reference: VS-03; IsExternal: yes; LoadBearing: yes
AR_Sein - 001_Nimetus: Välissein; 325_Helipidavus: nõudeid ei esitata; 330_Tulepüsivus: nõudeid ei esitata; 335_Välispiire: yes; 340_Soojusläbivus: 0; 605_Neto-pindala: 67.5709 m2; 600_Bruto-pindala: 81.1151 m2; 500_Kandev: yes; 505_Paksus: 390 mm; 205_Tähis: VS-03; 376_Viimistlus-väljast: Drenaažimatt-pinnas
AR_ÜLD - 009_Märkus: pinnase vastas
AC_Pset_RenovationAndPhasing - Renovation Status: New

# IfcWall: VS-04 (1) 340 (13)
Classification: 1.24 IfcWallType (sein) (BIM ÜBN + Archicad Classification)
Pset_WallCommon - Reference: VS-04; IsExternal: yes; LoadBearing: yes
AR_Sein - 001_Nimetus: Välissein; 325_Helipidavus: R’tr,s,w ≥ 55 dB; 330_Tulepüsivus: nõudeid ei esitata; 335_Välispiire: yes; 340_Soojusläbivus: 0; 500_Kandev: yes; 505_Paksus: 340 mm; 205_Tähis: VS-04; 376_Viimistlus-väljast: Horisontaalne värvitud laudis, vt. AR-6 vaatejooniseid
AC_Pset_RenovationAndPhasing - Renovation Status: New
Name | In | 605_Neto-pindala (m2) | 600_Bruto-pindala (m2)
VS-04 | Esimene korrus | 26.3446 | 34.2784
VS-04 | Esimene korrus | 27.2996 | 32.1772
VS-04 | Esimene korrus | 51.1317 | 76.7144
VS-04 | Esimene korrus | 203.931 | 289.306
VS-04 | Esimene korrus | 96.8793 | 125.124
VS-04 | Esimene korrus | 33.4884 | 47.792
VS-04 | Esimene korrus | 23.8199 | 44.5372
VS-04 | Teine korrus | 76.5895 | 83.5107
VS-04 | Teine korrus | 66.308 | 83.5107
VS-04 | Teine korrus | 124.057 | 154.329
VS-04 | Teine korrus | 48.1489 | 52.923
VS-04 | Teine korrus | 167.215 | 212.634
VS-04 | Teine korrus | 115.809 | 154.219

# IfcWall: VS-04a 155 (5)
In: Katus
Classification: 1.24 IfcWallType (sein) (BIM ÜBN + Archicad Classification)
AC_Pset_RenovationAndPhasing - Renovation Status: New
AR_Sein - 001_Nimetus: Parapeti sein; 325_Helipidavus: nõudeid ei esitata; 330_Tulepüsivus: nõudeid ei esitata; 335_Välispiire: yes; 340_Soojusläbivus: 0; 500_Kandev: yes; 505_Paksus: 155 mm; 205_Tähis: VS-04a; 376_Viimistlus-väljast: Horisontaalne värvitud laudis, vt. AR-6 vaatejooniseid
Pset_WallCommon - Reference: VS-04a; IsExternal: yes; LoadBearing: yes
Name | 605_Neto-pindala (m2) | 600_Bruto-pindala (m2)
VS-04a | 20.2958 | 20.2958
VS-04a | 76.4782 | 76.5398
VS-04a | 51.1995 | 51.2518
VS-04a | 20.2904 | 20.2958
VS-04a | 12.4221 | 12.4369

# IfcWall: VS-04b 397, VS-04b
In: Katus
Classification: 1.24 IfcWallType (sein) (BIM ÜBN + Archicad Classification)
Pset_WallCommon - Reference: VS-04b; IsExternal: yes; LoadBearing: yes
AR_Sein - 001_Nimetus: Välissein; 325_Helipidavus: nõudeid ei esitata; 330_Tulepüsivus: nõudeid ei esitata; 335_Välispiire: yes; 340_Soojusläbivus: 0; 605_Neto-pindala: 11.4799 m2; 600_Bruto-pindala: 12.8511 m2; 500_Kandev: yes; 505_Paksus: 397 mm; 205_Tähis: VS-04b; 376_Viimistlus-väljast: Horisontaalne värvitud laudis, vt. AR-6 vaatejooniseid
AC_Pset_RenovationAndPhasing - Renovation Status: New
AR_ÜLD - 009_Märkus: vt. AR-7 sõlmlahendusi

# IfcWall: VS-06 270 (28)
In: Katus
Classification: 1.24 IfcWallType (sein) (BIM ÜBN + Archicad Classification)
Pset_WallCommon - Reference: VS-06; IsExternal: yes; LoadBearing: yes
AR_Sein - 001_Nimetus: Katuseakende parapet; 325_Helipidavus: R’tr,s,w ≥ 48 dB; 330_Tulepüsivus: nõudeid ei esitata; 335_Välispiire: yes; 340_Soojusläbivus: 0; 500_Kandev: yes; 505_Paksus: 270 mm; 205_Tähis: VS-06; 376_Viimistlus-väljast: Katusekate valge SRI81, vt. KL-01
AR_ÜLD - 009_Märkus: vt. AR-7 sõlmlahendusi
AC_Pset_RenovationAndPhasing - Renovation Status: New
Name | 605_Neto-pindala (m2) | 600_Bruto-pindala (m2)
4 x VS-06 | 2.26147 | 2.4885
2 x VS-06 | 4.75271 | 4.75271
7 x VS-06 | 2.25041 | 2.4885
VS-06 | 16.8479 | 16.8622
3 x VS-06 | 2.26463 | 2.4885
VS-06 | 13.1011 | 13.6653
VS-06 | 6.19702 | 6.21125
VS-06 | 11.2841 | 11.2984
VS-06 | 4.82585 | 5.03366
2 x VS-06 | 3.68158 | 3.85164
VS-06 | 8.7783 | 9.1563
VS-06 | 4.46812 | 4.46812
VS-06 | 4.22621 | 4.22621
VS-06 | 3.46046 | 3.62101
VS-06 | 3.27251 | 3.42497

# IfcWall: VS-07 500, VS-07
In: Teine korrus
Classification: 1.24 IfcWallType (sein) (BIM ÜBN + Archicad Classification)
Pset_WallCommon - Reference: VS-07; IsExternal: yes; LoadBearing: yes
AR_Sein - 001_Nimetus: Välissein ventkambris; 325_Helipidavus: R’tr,s,w ≥ 55 dB; 330_Tulepüsivus: nõudeid ei esitata; 335_Välispiire: yes; 340_Soojusläbivus: 0; 605_Neto-pindala: 5.12508 m2; 600_Bruto-pindala: 8.49908 m2; 500_Kandev: yes; 505_Paksus: 500 mm; 205_Tähis: VS-07; 376_Viimistlus-väljast: Horisontaalne värvitud laudis, vt. AR-6 vaatejooniseid
AR_ÜLD - 009_Märkus: vt. AR-7 sõlmlahendusi
AC_Pset_RenovationAndPhasing - Renovation Status: New

# IfcWall: VS-07a 400 (2)
In: Teine korrus
Classification: 1.24 IfcWallType (sein) (BIM ÜBN + Archicad Classification)
Pset_WallCommon - Reference: VS-07a; IsExternal: yes; LoadBearing: yes
AR_Sein - 001_Nimetus: Välissein ventkambris; 325_Helipidavus: R’w ≥ 60 dB; 330_Tulepüsivus: EI30; 335_Välispiire: yes; 340_Soojusläbivus: 0; 500_Kandev: yes; 505_Paksus: 400 mm; 205_Tähis: VS-07a; 376_Viimistlus-väljast: Matt antrasiit RAL7016 SW-paneel, vt. AR-7 sõlmlahendusi
AR_ÜLD - 009_Märkus: vt. AR-7 sõlmlahendusi
AC_Pset_RenovationAndPhasing - Renovation Status: New
Name | 605_Neto-pindala (m2) | 600_Bruto-pindala (m2)
VS-07a | 7.9969 | 7.9969
VS-07a | 30.2252 | 33.971

# IfcWall: VS-07b 160, VS-07b
In: Teine korrus
Classification: 1.24 IfcWallType (sein) (BIM ÜBN + Archicad Classification)
Pset_WallCommon - Reference: VS-07b; IsExternal: no; LoadBearing: no
AC_Pset_RenovationAndPhasing - Renovation Status: New
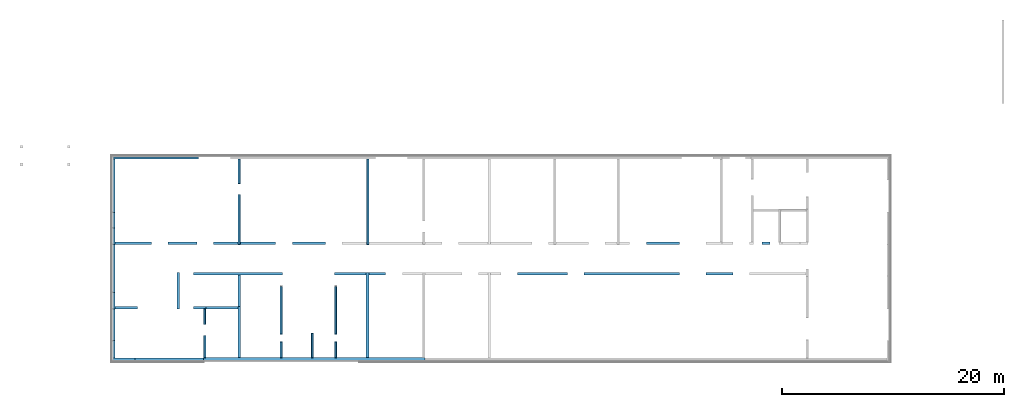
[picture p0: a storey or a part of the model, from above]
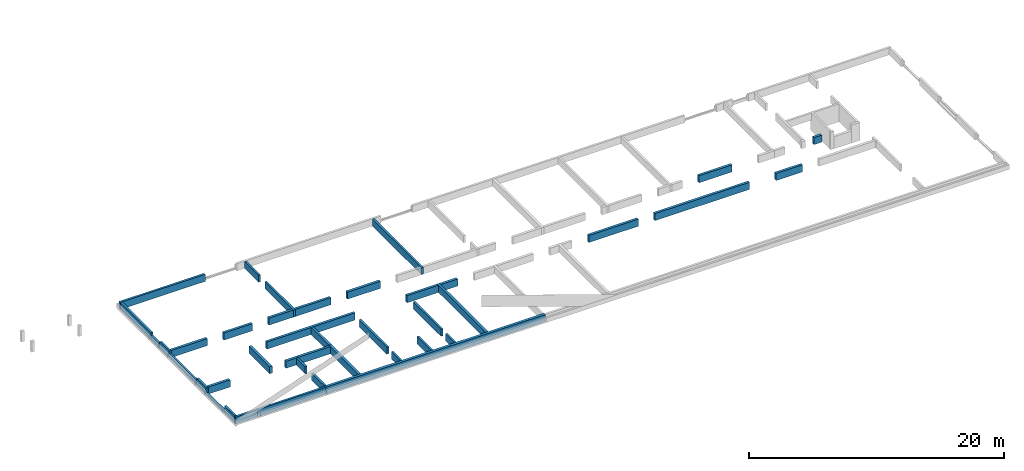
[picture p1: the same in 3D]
Properties of the parts of a building model (IFC2X3), part 8 of 8

# IfcWall: VS-07b 160, VS-07b
AR_Sein - 001_Nimetus: Sisesein; 330_Tulepüsivus: EI30; 335_Välispiire: no; 340_Soojusläbivus: 0; 605_Neto-pindala: 23.654 m2; 600_Bruto-pindala: 26.243 m2; 500_Kandev: no; 505_Paksus: 160 mm; 205_Tähis: VS-07b

# IfcWall: VS-08 390 (7)
In: Teine korrus
Classification: 1.24 IfcWallType (sein) (BIM ÜBN + Archicad Classification)
Pset_WallCommon - Reference: VS-08; IsExternal: yes; LoadBearing: yes
AC_Pset_RenovationAndPhasing - Renovation Status: New
AR_Sein - 001_Nimetus: Välissein; 325_Helipidavus: R’tr,s,w ≥ 55 dB; 330_Tulepüsivus: nõudeid ei esitata; 335_Välispiire: yes; 340_Soojusläbivus: 0; 500_Kandev: yes; 505_Paksus: 390 mm; 205_Tähis: VS-08; 376_Viimistlus-väljast: Horisontaalne värvitud laudis, vt. AR-6 vaatejooniseid
Name | 605_Neto-pindala (m2) | 600_Bruto-pindala (m2)
VS-08 | 7.885 | 19.4352
VS-08 | 7.9451 | 19.4792
VS-08 | 14.1622 | 57.6305
VS-08 | 3.93387 | 13.3
VS-08 | 4.29014 | 13.3
2 x VS-08 | 1.37112 | 1.46625

# IfcWall: VS-08_SW 150 (2)
In: Teine korrus
Classification: 1.24 IfcWallType (sein) (BIM ÜBN + Archicad Classification)
Pset_WallCommon - Reference: VS-08a; IsExternal: yes; LoadBearing: yes
AR_ÜLD - 009_Märkus: vt. VS-08
AC_Pset_RenovationAndPhasing - Renovation Status: New
AR_Sein - 001_Nimetus: Välissein; 325_Helipidavus: nõudeid ei esitata; 330_Tulepüsivus: nõudeid ei esitata; 335_Välispiire: yes; 340_Soojusläbivus: 0; 500_Kandev: yes; 505_Paksus: 150 mm; 205_Tähis: VS-08a; 376_Viimistlus-väljast: Horisontaalne värvitud laudis, vt. AR-6 vaatejooniseid
Name | 605_Neto-pindala (m2) | 600_Bruto-pindala (m2)
VS-08a | 3.72861 | 3.95317
VS-08a | 3.41006 | 3.58579

# IfcWall: VS-08_karkass 72 (5)
In: Teine korrus
Classification: 1.24 IfcWallType (sein) (BIM ÜBN + Archicad Classification)
AR_Sein - 001_Nimetus: Välissein; 325_Helipidavus: nõudeid ei esitata; 330_Tulepüsivus: nõudeid ei esitata; 335_Välispiire: yes; 340_Soojusläbivus: 0; 500_Kandev: yes; 505_Paksus: 72 mm; 205_Tähis: VS-08a; 376_Viimistlus-väljast: Horisontaalne värvitud laudis, vt. AR-6 vaatejooniseid
AR_ÜLD - 009_Märkus: vt. VS-08
AC_Pset_RenovationAndPhasing - Renovation Status: New
Pset_WallCommon - Reference: VS-08a; IsExternal: yes; LoadBearing: yes
Name | 605_Neto-pindala (m2) | 600_Bruto-pindala (m2)
VS-08a | 6.95373 | 17.6945
VS-08a | 6.95344 | 17.6942
VS-08a | 2.08201 | 2.08201
VS-08a | 24.4615 | 24.8085
VS-08a | 2.07216 | 2.08529

# IfcWall: VS-08_kivi 240 (2)
In: Teine korrus
Classification: 1.24 IfcWallType (sein) (BIM ÜBN + Archicad Classification); Material: 30 Konst: Columbia õõnesplokk
Pset_WallCommon - Reference: VS-08b; IsExternal: yes; LoadBearing: yes
AR_Sein - 001_Nimetus: Välissein; 325_Helipidavus: R’tr,s,w ≥ 55 dB; 330_Tulepüsivus: nõudeid ei esitata; 335_Välispiire: yes; 340_Soojusläbivus: 0; 605_Neto-pindala: 3.66275 m2; 600_Bruto-pindala: 4.00775 m2; 500_Kandev: yes; 505_Paksus: 240 mm; 205_Tähis: VS-08b; 376_Viimistlus-väljast: KF süsteem, vt. AR-8
AC_Pset_RenovationAndPhasing - Renovation Status: New
AR_ÜLD - 009_Märkus: vt. VS-08

# IfcWall: VS-08a 400 (3)
In: Katus
Classification: 1.24 IfcWallType (sein) (BIM ÜBN + Archicad Classification)
Pset_WallCommon - Reference: VS-08a; IsExternal: yes; LoadBearing: yes
AR_Sein - 001_Nimetus: Parapeti sein; 330_Tulepüsivus: nõudeid ei esitata; 335_Välispiire: yes; 500_Kandev: yes; 505_Paksus: 400 mm; 205_Tähis: VS-08a
AC_Pset_RenovationAndPhasing - Renovation Status: New
Name | 605_Neto-pindala (m2) | 600_Bruto-pindala (m2)
VS-08a | 2.16519 | 2.8325
VS-08a | 2.17026 | 2.8325
VS-08a | 12.3581 | 14.8232

# IfcWall: VS-10 190 (3)
Classification: 1.24 IfcWallType (sein) (BIM ÜBN + Archicad Classification); Material: 30 Konst: Raudbetoon monoliitne
Pset_WallCommon - Reference: VS-10; IsExternal: yes; LoadBearing: yes
AR_Sein - 001_Nimetus: Sokli sein; 325_Helipidavus: nõudeid ei esitata; 330_Tulepüsivus: nõudeid ei esitata; 335_Välispiire: yes; 340_Soojusläbivus: 0; 500_Kandev: yes; 505_Paksus: 190 mm; 205_Tähis: VS-10; 376_Viimistlus-väljast: Monoliitne betoonpind, toon: betoonhall
AR_ÜLD - 009_Märkus: monoliitne betoon. vt. AR-9 ja EK-osa
AC_Pset_RenovationAndPhasing - Renovation Status: New
Name | In | 605_Neto-pindala (m2) | 600_Bruto-pindala (m2)
VS-10 | Vundament | 7.535 | 7.725
VS-10 | Esimene korrus | 11.352 | 11.808
VS-10 | Esimene korrus | 11.58 | 11.808

# IfcWall: VS-11 190, VS-11
In: Esimene korrus
Classification: 1.24 IfcWallType (sein) (BIM ÜBN + Archicad Classification); Material: 30 Konst: Columbia õõnesplokk
Pset_WallCommon - Reference: VS-11; IsExternal: yes; LoadBearing: yes
AR_Sein - 001_Nimetus: Soojustamata välissein; 325_Helipidavus: nõudeid ei esitata; 330_Tulepüsivus: nõudeid ei esitata; 335_Välispiire: yes; 340_Soojusläbivus: 0; 605_Neto-pindala: 22.6045 m2; 600_Bruto-pindala: 23.175 m2; 500_Kandev: yes; 505_Paksus: 190 mm; 205_Tähis: VS-11; 376_Viimistlus-väljast: Värvitud õõnesbetoonplokk, matt antrasiit RAL7016
AC_Pset_RenovationAndPhasing - Renovation Status: New
AR_ÜLD - 009_Märkus: õõnesplokk 190mm. vt. AR-9 ja EK-osa

# IfcWall: VS-20 31 (2)
In: Teine korrus
Classification: 1.24 IfcWallType (sein) (BIM ÜBN + Archicad Classification)
Pset_WallCommon - Reference: VS-20; IsExternal: yes; LoadBearing: yes
AR_Sein - 001_Nimetus: Rajatise parapet; 325_Helipidavus: nõudeid ei esitata; 330_Tulepüsivus: nõudeid ei esitata; 335_Välispiire: yes; 340_Soojusläbivus: 0; 600_Bruto-pindala: 6.13395 m2; 500_Kandev: yes; 505_Paksus: 31 mm; 205_Tähis: VS-20
AC_Pset_RenovationAndPhasing - Renovation Status: New
AR_ÜLD - 009_Märkus: vt. AR-7 sõlmlahendusi
Name | 605_Neto-pindala (m2)
VS-20 | 4.76464
VS-20 | 3.80757

# IfcWallStandardCase: 30 Konst: Raudbetoon monoliitne 250 (4)
In: Vundament
Classification: 1.24 IfcWallType (sein) (BIM ÜBN + Archicad Classification); Material: 30 Konst: Raudbetoon monoliitne 250 mm
Pset_WallCommon - IsExternal: yes; LoadBearing: yes
AC_Pset_RenovationAndPhasing - Renovation Status: New
AR_Sein - 001_Nimetus: Rajatise vundament; 325_Helipidavus: nõudeid ei esitata; 330_Tulepüsivus: nõudeid ei esitata; 335_Välispiire: yes; 340_Soojusläbivus: 0; 605_Neto-pindala: 0.25 m2; 600_Bruto-pindala: 0.25 m2; 500_Kandev: yes; 505_Paksus: 250 mm; 376_Viimistlus-väljast: -

# IfcWindow: Double Sash Window 26, A-2d
In: Teine korrus
Type - OperationType: DOUBLE_PANEL_VERTICAL; ParameterTakesPrecedence: no; Sizeable: no
Type - Window Lining Properties - LiningDepth: 92 mm; LiningThickness: 90 mm; MullionThickness: 90 mm; FirstMullionOffset: 0.5
Type - Window Panel Properties - Panel 1 - OperationType: SIDEHUNGLEFTHAND; PanelPosition: RIGHT; FrameDepth: 112 mm; FrameThickness: 84 mm
Type - Window Panel Properties - Panel 2 - OperationType: SIDEHUNGRIGHTHAND; PanelPosition: LEFT; FrameDepth: 112 mm; FrameThickness: 84 mm
OverallHeight: 2410 mm; OverallWidth: 2860 mm; Classification: 1.25 IfcWindowStyle (aken) (BIM ÜBN + Archicad Classification)
Pset_WindowCommon - Reference: A-2d; ThermalTransmittance: 0; GlazingAreaFraction: 4.41942; IsExternal: yes
AR_Aken - 001_Nimetus: Välisaken; 300_Tähis: A-2d; 310_Materjal: MUDELIS: väljast Avatäide: raam värv antrasiit RAL7016; Avatäide: raam värv antrasiit RAL7016; seest Avatäide: raam värv antrasiit RAL7016; Avatäide: raam värv antrasiit RAL7016; MÄRKUS: Puitalumiinium; 315_Avanemine: Pöördavatav kahes osas impostita, avada ainult kauba transportimisel, vajadusel toestadaParem ; ARCHICAD tüüp: Side Hung; 320_Klaas: Kolmekordne klaaspakett, argoongaasiga, välimine: selektiivklaas, LT=72%, lamineeritud klaas, klaasitoon: kirgas, keskmine: klaasitoon: kirgas, sisemine: lamineeritud floatklaas, klaasitoon: kirgas. Vaheliistud mustad; 325_Helipidavus: R’tr,s,w = 30 dB; 330_Tulepüsivus: nõudeid ei esitata; 335_Välispiire: yes; 340_Soojusläbivus: 0; 350_Klaaspakett: Kolmekordne klaaspakett, vaheliistude toon: must, 44.2 lamineering, täpsustada TP-staadiumis; 355_Pindala: 6.8926 m2; 375_Viimistlus-seest: MUDELIS: Avatäide: raam värv antrasiit RAL7016; Avatäide: raam värv antrasiit RAL7016; MÄRKUS: Matt antrasiit RAL7016, toonitud puit; 376_Viimistlus-väljast: MUDELIS: Avatäide: raam värv antrasiit RAL7016; Avatäide: raam värv antrasiit RAL7016; MÄRKUS: Matt antrasiit RAL7016; 900_Tootja: ootel; 905_Mudel: ootel; 910_Tooteinfo: ootel; 915_Kasutus-ja-hooldusjuhend: ootel; 306_Ava-laius: 2860 mm; 307_Ava-kõrgus: 2410 mm; 379_Käepide: ilma rosetita Hoppe Toulon, viimistlus: F9714M matt must; 395_Veeplekk: Valtsitud terasplekist veeplekk, min t=0,7 mm, viimistlus: pulbervärvitud antratsiit RAL7016, vt. AR-osa sõlmlahendusi; 396_Aknalaud: Harjatud kuuse ristkihtpuitplaat (Dold) 19mm, viimistletud Osmo 3111 + Osmo 3065. Paled samuti. vt. SA-osa sk ja AR-osa sõlmlahendusi; 345_Päikesekiirgus-tegur: 0
AC_Pset_RenovationAndPhasing - Renovation Status: New

# IfcWindow: Double Window 26 (66)
Type - OperationType: USERDEFINED; ParameterTakesPrecedence: no; Sizeable: no
Classification: 1.25 IfcWindowStyle (aken) (BIM ÜBN + Archicad Classification)
Pset_WindowCommon - ThermalTransmittance: 0; IsExternal: yes
AR_Aken - 001_Nimetus: Välisaken; 310_Materjal: MUDELIS: väljast Avatäide: raam värv antrasiit RAL7016; Avatäide: raam värv antrasiit RAL7016; seest Avatäide: raam värv antrasiit RAL7016; Avatäide: raam värv antrasiit RAL7016; MÄRKUS: Puitalumiinium; 320_Klaas: Kolmekordne klaaspakett, argoongaasiga, välimine: selektiivklaas, LT=72%, lamineeritud klaas, klaasitoon: kirgas, keskmine: klaasitoon: kirgas, sisemine: lamineeritud floatklaas, klaasitoon: kirgas. Vaheliistud mustad; 330_Tulepüsivus: nõudeid ei esitata; 335_Välispiire: yes; 340_Soojusläbivus: 0; 350_Klaaspakett: Kolmekordne klaaspakett, vaheliistude toon: must, 44.2 lamineering, täpsustada TP-staadiumis; 375_Viimistlus-seest: MUDELIS: Avatäide: raam värv antrasiit RAL7016; Avatäide: raam värv antrasiit RAL7016; MÄRKUS: Matt antrasiit RAL7016, toonitud puit; 376_Viimistlus-väljast: MUDELIS: Avatäide: raam värv antrasiit RAL7016; Avatäide: raam värv antrasiit RAL7016; MÄRKUS: Matt antrasiit RAL7016; 900_Tootja: ootel; 905_Mudel: ootel; 910_Tooteinfo: ootel; 915_Kasutus-ja-hooldusjuhend: ootel; 379_Käepide: ilma rosetita Hoppe Toulon, viimistlus: F9714M matt must; 395_Veeplekk: Valtsitud terasplekist veeplekk, min t=0,7 mm, viimistlus: pulbervärvitud antratsiit RAL7016, vt. AR-osa sõlmlahendusi; 396_Aknalaud: Harjatud kuuse ristkihtpuitplaat (Dold) 19mm, viimistletud Osmo 3111 + Osmo 3065. Paled samuti. vt. SA-osa sk ja AR-osa sõlmlahendusi; 345_Päikesekiirgus-tegur: 0
AC_Pset_RenovationAndPhasing - Renovation Status: New
Name | In | OverallHeight (mm) = 307_Ava-kõrgus (mm) | OverallWidth (mm) = 306_Ava-laius (mm) | Reference = 300_Tähis | GlazingAreaFraction | 315_Avanemine | 325_Helipidavus | 355_Pindala (m2)
9 x A-1b | Esimene korrus | 2810 | 1250 | A-1b | 2.07983 | Kald- ja pöördavatav, ülemine osa suitsueemalduseksVasak ; ARCHICAD tüüp: Side Hung Mirrored | R’tr,s,w = 30 dB | 3.5125
14 x A-1a | Esimene korrus | 2810 | 1250 | A-1a | 2.07983 | Kald- ja pöördavatav, ülemine osa suitsueemalduseksParem ; ARCHICAD tüüp: Side Hung Mirrored | R’tr,s,w = 30 dB | 3.5125
22 x A-2a | Teine korrus | 2410 | 1250 | A-2a | 1.73663 | Kald- ja pöördavatav, ülemine osa suitsueemalduseksParem ; ARCHICAD tüüp: Side Hung Mirrored | R’tr,s,w = 30 dB | 3.0125
3 x A-2 | Teine korrus | 2410 | 1410 | A-2 | 2.05951 | Kald- ja pöördavatav, ülemine osa suitsueemalduseksVasak ; ARCHICAD tüüp: Side Hung Mirrored | R’tr,s,w = 35 dB | 3.3981
2 x A-2c | Teine korrus | 2410 | 1430 | A-2c | 2.09987 | Kald- ja pöördavatavVasak ; ARCHICAD tüüp: Side Hung Mirrored | R’tr,s,w = 35 dB | 3.4463
A-2e | Teine korrus | 2410 | 1250 | A-2e | 1.73663 | Kald- ja pöördavatav, ülemine osa suitsueemalduseksVasak ; ARCHICAD tüüp: Side Hung Mirrored | R’tr,s,w = 35 dB | 3.0125
15 x A-2b | Teine korrus | 2410 | 1250 | A-2b | 1.73663 | Kald- ja pöördavatav, ülemine osa suitsueemalduseksVasak ; ARCHICAD tüüp: Side Hung Mirrored | R’tr,s,w = 30 dB | 3.0125

# IfcWindow: Lamilux FE (2)
In: Katus
Type - ParameterTakesPrecedence: no; Sizeable: no
OverallHeight: 1200 mm; OverallWidth: 1200 mm; Classification: 1.25 IfcWindowStyle (aken) (BIM ÜBN + Archicad Classification)
Pset_WindowCommon - Reference: KA-20; ThermalTransmittance: 0; IsExternal: yes
AR_Aken - 001_Nimetus: Suitsueemaldus aken / Suitsuluuk; 300_Tähis: KA-20; 310_Materjal: MUDELIS: ; MÄRKUS: Soojustatud alumiinium raam; 315_Avanemine: Ajamiga avanev, tarnida koos avatäitega; 320_Klaas: Kolmekordne klaaspakett, tootja standard; 325_Helipidavus: R’tr,s,w = 30 dB; 330_Tulepüsivus: nõudeid ei esitata; 335_Välispiire: yes; 340_Soojusläbivus: 0; 350_Klaaspakett: Kolmekordne klaaspakett, tootja standard; 355_Pindala: 1.44 m2; 375_Viimistlus-seest: MUDELIS: ; MÄRKUS: Tootja värvitud, toon: antratsiithall RAL7016; 376_Viimistlus-väljast: MUDELIS: ; MÄRKUS: Valge, tootja standard; 900_Tootja: ootel; 905_Mudel: ootel; 910_Tooteinfo: ootel; 915_Kasutus-ja-hooldusjuhend: ootel; 306_Ava-laius: 1200 mm; 307_Ava-kõrgus: 1200 mm; 379_Käepide: ootel; 395_Veeplekk: Katusekatte ülespööre toote veepleki alla, vt. AR-osa sõlmlahendusi; 396_Aknalaud: ootel; 345_Päikesekiirgus-tegur: 0
AC_Pset_RenovationAndPhasing - Renovation Status: New
Pset_ManufacturerTypeInformation - Manufacturer: LAMILUX
AR_ÜLD - 009_Märkus: OMA märkus

# IfcWindow: Skylight Flat Panel 26 (8)
In: Katus
Type - ParameterTakesPrecedence: no; Sizeable: no
Type - Window Lining Properties - LiningDepth: 50 mm; LiningThickness: 50 mm
OverallHeight: 1190 mm; Classification: 1.25 IfcWindowStyle (aken) (BIM ÜBN + Archicad Classification)
AR_Aken - 001_Nimetus: Automaatikaga suitsueemaldusaken; 310_Materjal: MUDELIS: ; MÄRKUS: Alumiinium; 315_Avanemine: Ajamiga kaldavanev, ca 54°; 320_Klaas: Kolmekordne klaaspakett, argoongaasiga, vaheliistud mustad, välimine: päikesekaitseklaas Cool-Lite SKN 183 II, LT=66%, karastatud klaas, klaasitoon: kirgas, keskmine: Planiclear 6mm, karastatud floatklaas, klaasitoon: kirgas, sisemine: Planitherm XN II, lamineeritud karastatud floatklaas, klaasitoon: kirgas; 325_Helipidavus: R’tr,s,w = 30 dB; 330_Tulepüsivus: nõudeid ei esitata; 335_Välispiire: yes; 340_Soojusläbivus: 0; 350_Klaaspakett: 3k6SecSKN183(II)+6Sec+44.2PlanidurPlthXN(II)-16Ar/16Ar (vaheliistude toon: must), Ug=0,8 W/(m2K); 375_Viimistlus-seest: MUDELIS: Klaas - kirgas; Krundiinventar: metall värv antrasiit RAL7016; MÄRKUS: Matt antrasiit RAL7016; 376_Viimistlus-väljast: MUDELIS: Klaas - kirgas; Krundiinventar: metall värv antrasiit RAL7016; MÄRKUS: Matt antrasiit RAL7016; 900_Tootja: ootel; 905_Mudel: ootel; 910_Tooteinfo: ootel; 915_Kasutus-ja-hooldusjuhend: ootel; 307_Ava-kõrgus: 1190 mm; 379_Käepide: ootel; 395_Veeplekk: Valtsitud terasplekist veeplekk, min t=0,7 mm, viimistlus: pulbervärvitud antratsiit RAL7016, vt. AR-osa sõlmlahendusi; 396_Aknalaud: ootel; 345_Päikesekiirgus-tegur: 0
AR_ÜLD - 009_Märkus: OMA märkus
AC_Pset_RenovationAndPhasing - Renovation Status: New
Pset_WindowCommon - ThermalTransmittance: 0; IsExternal: yes
Name | OverallWidth (mm) = 306_Ava-laius (mm) | 300_Tähis = Reference | 355_Pindala (m2)
2 x KA-03 | 1230 | KA-03 | 1.4637
KA-04 | 1150 | KA-04 | 1.3685
3 x KA-01 | 1330 | KA-01 | 1.5827
2 x KA-02 | 1390 | KA-02 | 1.6541

# IfcWindow: Triple Window 26, A-4
In: Esimene korrus
Type - OperationType: USERDEFINED; ParameterTakesPrecedence: no; Sizeable: no
OverallHeight: 3445 mm; OverallWidth: 4310 mm; Classification: 1.25 IfcWindowStyle (aken) (BIM ÜBN + Archicad Classification)
Pset_WindowCommon - Reference: A-4; ThermalTransmittance: 0; GlazingAreaFraction: 12.1638; IsExternal: yes
AR_Aken - 001_Nimetus: Välisaken; 300_Tähis: A-4; 310_Materjal: MUDELIS: väljast Avatäide: raam värv antrasiit RAL7016; Avatäide: raam värv antrasiit RAL7016; seest Avatäide: raam värv antrasiit RAL7016; Avatäide: raam värv antrasiit RAL7016; MÄRKUS: Puitalumiinium; 315_Avanemine: - ; ARCHICAD tüüp: Fixed Glass; 320_Klaas: Kolmekordne klaaspakett, argoongaasiga, välimine: selektiivklaas, LT=72%, lamineeritud klaas, klaasitoon: kirgas, keskmine: klaasitoon: kirgas, sisemine: lamineeritud floatklaas, klaasitoon: kirgas. Vaheliistud mustad; 325_Helipidavus: R’tr,s,w = 30 dB; 330_Tulepüsivus: nõudeid ei esitata; 335_Välispiire: yes; 340_Soojusläbivus: 0; 350_Klaaspakett: Kolmekordne klaaspakett, vaheliistude toon: must, 44.2 lamineering, täpsustada TP-staadiumis; 355_Pindala: 14.8479 m2; 375_Viimistlus-seest: MUDELIS: Avatäide: raam värv antrasiit RAL7016; Avatäide: raam värv antrasiit RAL7016; MÄRKUS: Matt antrasiit RAL7016, toonitud puit; 376_Viimistlus-väljast: MUDELIS: Avatäide: raam värv antrasiit RAL7016; Avatäide: raam värv antrasiit RAL7016; MÄRKUS: Matt antrasiit RAL7016; 900_Tootja: ootel; 905_Mudel: ootel; 910_Tooteinfo: ootel; 915_Kasutus-ja-hooldusjuhend: ootel; 306_Ava-laius: 4310 mm; 307_Ava-kõrgus: 3445 mm; 379_Käepide: ilma rosetita Hoppe Toulon, viimistlus: F9714M matt must; 395_Veeplekk: Valtsitud terasplekist veeplekk, min t=0,7 mm, viimistlus: pulbervärvitud antratsiit RAL7016, vt. AR-osa sõlmlahendusi; 396_Aknalaud: Põrandakate viia avatäite lengini, vt. SA-osa; 345_Päikesekiirgus-tegur: 0
AC_Pset_RenovationAndPhasing - Renovation Status: New

# IfcWindow: Vent Window, VR-01
In: Teine korrus
Type - OperationType: USERDEFINED; ParameterTakesPrecedence: no; Sizeable: no
OverallHeight: 2410 mm; OverallWidth: 1400 mm; Classification: 1.25 IfcWindowStyle (aken) (BIM ÜBN + Archicad Classification)
Pset_WindowCommon - Reference: VR-01; ThermalTransmittance: 0; IsExternal: yes
AR_Aken - 001_Nimetus: Välisaken; 300_Tähis: VR-01; 310_Materjal: MUDELIS: ; MÄRKUS: Alumiinium; 315_Avanemine: -; 320_Klaas: puudub; 325_Helipidavus: nõudeid ei esitata; 330_Tulepüsivus: nõudeid ei esitata; 335_Välispiire: yes; 340_Soojusläbivus: 0; 350_Klaaspakett: -; 355_Pindala: 3.374 m2; 375_Viimistlus-seest: Matt antrasiit RAL7016; 376_Viimistlus-väljast: MUDELIS: Avatäide: raam värv antrasiit RAL7016; Avatäide: raam värv antrasiit RAL7016; MÄRKUS: Matt antrasiit RAL7016; 900_Tootja: ootel; 905_Mudel: ootel; 910_Tooteinfo: ootel; 915_Kasutus-ja-hooldusjuhend: ootel; 306_Ava-laius: 1400 mm; 307_Ava-kõrgus: 2410 mm; 379_Käepide: ootel; 395_Veeplekk: ootel; 396_Aknalaud: ootel; 345_Päikesekiirgus-tegur: 0
AC_Pset_RenovationAndPhasing - Renovation Status: New

# IfcWindow: Window 26, A-5
In: Esimene korrus
Type - OperationType: DOUBLE_PANEL_HORIZONTAL; ParameterTakesPrecedence: no; Sizeable: no
Type - Window Lining Properties - LiningDepth: 92 mm; LiningThickness: 90 mm; TransomThickness: 90 mm; FirstTransomOffset: 0.597365
Type - Window Panel Properties - Panel 1 - OperationType: FIXEDCASEMENT; PanelPosition: TOP
Type - Window Panel Properties - Panel 2 - OperationType: FIXEDCASEMENT; PanelPosition: BOTTOM
OverallHeight: 3445 mm; OverallWidth: 1409.86 mm; Classification: 1.25 IfcWindowStyle (aken) (BIM ÜBN + Archicad Classification)
Pset_WindowCommon - Reference: A-5; ThermalTransmittance: 0; GlazingAreaFraction: 3.76156; IsExternal: yes
AR_Aken - 001_Nimetus: Välisaken; 300_Tähis: A-5; 310_Materjal: MUDELIS: väljast Avatäide: raam värv antrasiit RAL7016; Avatäide: raam värv antrasiit RAL7016; seest Avatäide: raam värv antrasiit RAL7016; Avatäide: raam värv antrasiit RAL7016; MÄRKUS: Puitalumiinium; 315_Avanemine: - ; ARCHICAD tüüp: Fixed Glass; 320_Klaas: Kolmekordne klaaspakett, argoongaasiga, välimine: selektiivklaas, LT=72%, lamineeritud klaas, klaasitoon: kirgas, keskmine: klaasitoon: kirgas, sisemine: lamineeritud floatklaas, klaasitoon: kirgas. Vaheliistud mustad; 325_Helipidavus: R’tr,s,w = 30 dB; 330_Tulepüsivus: nõudeid ei esitata; 335_Välispiire: yes; 340_Soojusläbivus: 0; 350_Klaaspakett: Kolmekordne klaaspakett, vaheliistude toon: must, 44.2 lamineering, täpsustada TP-staadiumis; 355_Pindala: 4.85697 m2; 375_Viimistlus-seest: MUDELIS: Avatäide: raam värv antrasiit RAL7016; Avatäide: raam värv antrasiit RAL7016; MÄRKUS: Matt antrasiit RAL7016, toonitud puit; 376_Viimistlus-väljast: MUDELIS: Avatäide: raam värv antrasiit RAL7016; Avatäide: raam värv antrasiit RAL7016; MÄRKUS: Matt antrasiit RAL7016; 900_Tootja: ootel; 905_Mudel: ootel; 910_Tooteinfo: ootel; 915_Kasutus-ja-hooldusjuhend: ootel; 306_Ava-laius: 1409.86 mm; 307_Ava-kõrgus: 3445 mm; 379_Käepide: ilma rosetita Hoppe Toulon, viimistlus: F9714M matt must; 395_Veeplekk: Valtsitud terasplekist veeplekk, min t=0,7 mm, viimistlus: pulbervärvitud antratsiit RAL7016, vt. AR-osa sõlmlahendusi; 396_Aknalaud: Põrandakate viia avatäite lengini, vt. SA-osa; 345_Päikesekiirgus-tegur: 0
AC_Pset_RenovationAndPhasing - Renovation Status: New

# IfcWindow: Window 26 (6)
In: Teine korrus
Type - OperationType: SINGLE_PANEL; ParameterTakesPrecedence: no; Sizeable: no
Type - Window Lining Properties - LiningDepth: 100 mm; LiningThickness: 30 mm
Type - Window Panel Properties - Panel 1 - OperationType: FIXEDCASEMENT; PanelPosition: MIDDLE
Classification: 1.25 IfcWindowStyle (aken) (BIM ÜBN + Archicad Classification)
AR_Aken - 001_Nimetus: Siseaken; 315_Avanemine: - ; ARCHICAD tüüp: Fixed Glass; 320_Klaas: 10 mm (55.2 helipidavama lamineeritud klaasiga).; 330_Tulepüsivus: nõudeid ei esitata; 335_Välispiire: no; 340_Soojusläbivus: 0; 350_Klaaspakett: Kahekordne klaaspakett, vaheliistude toon: must, lamineering; 375_Viimistlus-seest: MUDELIS: Avatäide: raam värv antrasiit RAL7016; Avatäide: raam värv antrasiit RAL7016; MÄRKUS: Matt must RAL9005; 376_Viimistlus-väljast: MUDELIS: Avatäide: raam värv antrasiit RAL7016; Avatäide: raam värv antrasiit RAL7016; MÄRKUS: Matt must RAL9005; 900_Tootja: Structo; 905_Mudel: Glassline 30; 910_Tooteinfo: ootel; 915_Kasutus-ja-hooldusjuhend: ootel; 379_Käepide: Puudub; 395_Veeplekk: ootel; 396_Aknalaud: Harjatud kuuse ristkihtpuitplaat (Dold) 19mm, viimistletud Osmo 3111 + Osmo 3065. Paled samuti. vt. SA-osa sk ja AR-osa sõlmlahendusi; 345_Päikesekiirgus-tegur: 0
AR_ÜLD - 009_Märkus: OMA märkus
Pset_WindowCommon - ThermalTransmittance: 0; IsExternal: no
AC_Pset_RenovationAndPhasing - Renovation Status: New
Name | OverallHeight (mm) | OverallWidth (mm) = 306_Ava-laius (mm) | 300_Tähis = Reference | 310_Materjal | 325_Helipidavus | 355_Pindala (m2) | 307_Ava-kõrgus (mm) | GlazingAreaFraction
SKF-05 | 3060 | 2790 | SKF-05 | MUDELIS: väljast Avatäide: raam värv antrasiit RAL7016; Avatäide: raam värv antrasiit RAL7016; seest Avatäide: raam värv antrasiit RAL7016; Avatäide: raam värv antrasiit RAL7016; MÄRKUS: Alumiiniumprofiil | R’w ≥ 30 dB | 8.5374 | 3060 | 8.19
SKF-02 | 3060 | 2625 | SKF-02 | MUDELIS: väljast Avatäide: raam värv antrasiit RAL7016; Avatäide: raam värv antrasiit RAL7016; seest Avatäide: raam värv antrasiit RAL7016; Avatäide: raam värv antrasiit RAL7016; MÄRKUS: Alumiiniumprofiil | R’w ≥ 30 dB | 8.0325 | 3060 | 7.695
SKF-03 | 3060 | 2435 | SKF-03 | MUDELIS: väljast Avatäide: raam värv antrasiit RAL7016; Avatäide: raam värv antrasiit RAL7016; seest Avatäide: raam värv antrasiit RAL7016; Avatäide: raam värv antrasiit RAL7016; MÄRKUS: Alumiiniumprofiil | R’w ≥ 30 dB | 7.4511 | 3060 | 7.125
SKF-01 | 3080 | 2420 | SKF-01 | MUDELIS: väljast Avatäide: raam värv antrasiit RAL7016; Avatäide: raam värv antrasiit RAL7016; seest Avatäide: raam värv antrasiit RAL7016; Avatäide: raam värv antrasiit RAL7016; MÄRKUS: Alumiiniumprofiil | R’w ≥ 30dB | 7.4052 | 3060 | 7.08
SKF-01 | 3080 | 2419.5 | SKF-01 | MUDELIS: väljast Avatäide: raam värv antrasiit RAL7016; Avatäide: raam värv antrasiit RAL7016; seest Avatäide: raam värv antrasiit RAL7016; Avatäide: raam värv antrasiit RAL7016; MÄRKUS: Alumiiniumprofiil | R’w ≥ 30dB | 7.40367 | 3060 | 7.0785
SKF-06 | 2160 | 2800 | SKF-06 | MUDELIS: väljast Avatäide: raam värv antrasiit RAL7016; Avatäide: raam värv antrasiit RAL7016; seest Avatäide: raam värv antrasiit RAL7016; Avatäide: raam värv antrasiit RAL7016; MÄRKUS: ootel | R’w ≥ 30 dB | 6.048 | 2160 | 5.754

# IfcWindow: Window 26, SKF-02
In: Teine korrus
Type - OperationType: SINGLE_PANEL; ParameterTakesPrecedence: no; Sizeable: no
Type - Window Lining Properties - LiningDepth: 100 mm; LiningThickness: 50 mm
Type - Window Panel Properties - Panel 1 - OperationType: FIXEDCASEMENT; PanelPosition: MIDDLE
OverallHeight: 3060 mm; OverallWidth: 2625 mm; Classification: 1.25 IfcWindowStyle (aken) (BIM ÜBN + Archicad Classification)
Pset_WindowCommon - Reference: SKF-02; ThermalTransmittance: 0; GlazingAreaFraction: 7.474; IsExternal: no
AR_Aken - 001_Nimetus: Siseaken; 300_Tähis: SKF-02; 310_Materjal: MUDELIS: väljast Avatäide: raam värv antrasiit RAL7016; Avatäide: raam värv antrasiit RAL7016; seest Avatäide: raam värv antrasiit RAL7016; Avatäide: raam värv antrasiit RAL7016; MÄRKUS: Alumiiniumprofiil; 315_Avanemine: - ; ARCHICAD tüüp: Fixed Glass; 320_Klaas: 10 mm (55.2 helipidavama lamineeritud klaasiga).; 325_Helipidavus: R’w ≥ 30 dB; 330_Tulepüsivus: nõudeid ei esitata; 335_Välispiire: no; 340_Soojusläbivus: 0; 350_Klaaspakett: Kahekordne klaaspakett, vaheliistude toon: must, lamineering; 355_Pindala: 8.0325 m2; 375_Viimistlus-seest: MUDELIS: Avatäide: raam värv antrasiit RAL7016; Avatäide: raam värv antrasiit RAL7016; MÄRKUS: Matt must RAL9005; 376_Viimistlus-väljast: MUDELIS: Avatäide: raam värv antrasiit RAL7016; Avatäide: raam värv antrasiit RAL7016; MÄRKUS: Matt must RAL9005; 900_Tootja: Structo; 905_Mudel: Glassline 30; 910_Tooteinfo: ootel; 915_Kasutus-ja-hooldusjuhend: ootel; 306_Ava-laius: 2625 mm; 307_Ava-kõrgus: 3060 mm; 379_Käepide: Puudub; 395_Veeplekk: ootel; 396_Aknalaud: Harjatud kuuse ristkihtpuitplaat (Dold) 19mm, viimistletud Osmo 3111 + Osmo 3065. Paled samuti. vt. SA-osa sk ja AR-osa sõlmlahendusi; 345_Päikesekiirgus-tegur: 0
AR_ÜLD - 009_Märkus: OMA märkus
AC_Pset_RenovationAndPhasing - Renovation Status: New

# IfcWindow: Window 26 (7)
In: Teine korrus
Type - OperationType: SINGLE_PANEL; ParameterTakesPrecedence: no; Sizeable: no
Type - Window Lining Properties - LiningDepth: 150 mm; LiningThickness: 25 mm
Type - Window Panel Properties - Panel 1 - OperationType: FIXEDCASEMENT; PanelPosition: MIDDLE
OverallHeight: 3080 mm; Classification: 1.25 IfcWindowStyle (aken) (BIM ÜBN + Archicad Classification)
AR_Aken - 001_Nimetus: Klaasfassaadisüsteem; 300_Tähis: KF-3; 310_Materjal: MUDELIS: väljast Avatäide: raam värv antrasiit RAL7016; Avatäide: raam värv antrasiit RAL7016; seest Avatäide: raam värv antrasiit RAL7016; Avatäide: raam värv antrasiit RAL7016; MÄRKUS: Puitalumiinium; 315_Avanemine: - ; ARCHICAD tüüp: Fixed Glass; 325_Helipidavus: ootel; 330_Tulepüsivus: nõudeid ei esitata; 335_Välispiire: yes; 340_Soojusläbivus: 0; 350_Klaaspakett: ootel; 375_Viimistlus-seest: MUDELIS: Avatäide: raam värv antrasiit RAL7016; Avatäide: raam värv antrasiit RAL7016; MÄRKUS: RAL7016; 376_Viimistlus-väljast: MUDELIS: Avatäide: raam värv antrasiit RAL7016; Avatäide: raam värv antrasiit RAL7016; MÄRKUS:; 900_Tootja: ootel; 905_Mudel: ootel; 910_Tooteinfo: ootel; 915_Kasutus-ja-hooldusjuhend: ootel; 307_Ava-kõrgus: 3080 mm; 379_Käepide: ootel; 395_Veeplekk: ootel; 396_Aknalaud: ootel; 345_Päikesekiirgus-tegur: 0
Pset_WindowCommon - Reference: KF-3; ThermalTransmittance: 0; IsExternal: yes
AC_Pset_RenovationAndPhasing - Renovation Status: New
Name | OverallWidth (mm) = 306_Ava-laius (mm) | 355_Pindala (m2) | GlazingAreaFraction
KF-3 | 1730 | 5.3284 | 5.0904
5 x KF-3 | 1450 | 4.466 | 4.242
KF-3 | 1810 | 5.5748 | 5.3328

# IfcWindow: Window 26 (10)
In: Teine korrus
Type - OperationType: SINGLE_PANEL; ParameterTakesPrecedence: no; Sizeable: no
Type - Window Lining Properties - LiningDepth: 180 mm; LiningThickness: 25 mm
Type - Window Panel Properties - Panel 1 - OperationType: FIXEDCASEMENT; PanelPosition: MIDDLE
Classification: 1.25 IfcWindowStyle (aken) (BIM ÜBN + Archicad Classification)
Pset_WindowCommon - ThermalTransmittance: 0; IsExternal: yes
AR_Aken - 310_Materjal: MUDELIS: väljast Avatäide: raam värv antrasiit RAL7016; Avatäide: raam värv antrasiit RAL7016; seest Avatäide: raam värv antrasiit RAL7016; Avatäide: raam värv antrasiit RAL7016; MÄRKUS: Puitalumiinium; 315_Avanemine: - ; ARCHICAD tüüp: Fixed Glass; 325_Helipidavus: ootel; 330_Tulepüsivus: nõudeid ei esitata; 335_Välispiire: yes; 340_Soojusläbivus: 0; 350_Klaaspakett: ootel; 375_Viimistlus-seest: MUDELIS: Avatäide: raam värv antrasiit RAL7016; Avatäide: raam värv antrasiit RAL7016; MÄRKUS: RAL7016; 376_Viimistlus-väljast: MUDELIS: Avatäide: raam värv antrasiit RAL7016; Avatäide: raam värv antrasiit RAL7016; MÄRKUS:; 900_Tootja: ootel; 905_Mudel: ootel; 910_Tooteinfo: ootel; 915_Kasutus-ja-hooldusjuhend: ootel; 379_Käepide: ootel; 395_Veeplekk: ootel; 396_Aknalaud: ootel; 345_Päikesekiirgus-tegur: 0
AC_Pset_RenovationAndPhasing - Renovation Status: New
Name | OverallHeight (mm) = 307_Ava-kõrgus (mm) | OverallWidth (mm) = 306_Ava-laius (mm) | Reference = 300_Tähis | GlazingAreaFraction | 001_Nimetus | 355_Pindala (m2)
2 x KF-2 | 3080 | 1150 | KF-2 | 3.333 | Klaasfassaadisüsteem | 3.542
KF-2 | 625.091 | 2300 | KF-2 | 1.23771 | Klaasfassaadisüsteem | 1.43771
2 x KF-1 | 3080 | 1150 | KF-1 | 3.333 | Klaasfassaadisüsteem | 3.542
KF-1 | 625.091 | 2300 | KF-1 | 1.23771 | Klaasfassaadisüsteem | 1.43771
KF-1 | 625.091 | 1150 | KF-1 | 0.605101 | Klaasfassaadisüsteem | 0.718855
KF-1 | 3080 | 1150 | KF-1 |  | Välisaken | 3.542
KF-2 | 625.091 | 1150 | KF-2 | 0.605101 | Klaasfassaadisüsteem | 0.718855
KF-2 | 3080 | 1150 | KF-2 |  | Välisaken | 3.542

# IfcWindow: Window 26 (4)
In: Teine korrus
Type - OperationType: SINGLE_PANEL; ParameterTakesPrecedence: no; Sizeable: no
Type - Window Lining Properties - LiningDepth: 30 mm; LiningThickness: 30 mm
Type - Window Panel Properties - Panel 1 - OperationType: FIXEDCASEMENT; PanelPosition: MIDDLE
OverallHeight: 2160 mm; OverallWidth: 800 mm; Classification: 1.25 IfcWindowStyle (aken) (BIM ÜBN + Archicad Classification)
Pset_WindowCommon - ThermalTransmittance: 0; GlazingAreaFraction: 1.554; IsExternal: no
AR_Aken - 315_Avanemine: - ; ARCHICAD tüüp: Fixed Glass; 335_Välispiire: no; 340_Soojusläbivus: 0; 355_Pindala: 1.728 m2; 910_Tooteinfo: ootel; 915_Kasutus-ja-hooldusjuhend: ootel; 306_Ava-laius: 800 mm; 307_Ava-kõrgus: 2160 mm; 395_Veeplekk: ootel; 345_Päikesekiirgus-tegur: 0
AR_ÜLD - 009_Märkus: OMA märkus
AC_Pset_RenovationAndPhasing - Renovation Status: New
Name | Reference = 300_Tähis | 310_Materjal | 320_Klaas | 325_Helipidavus | 330_Tulepüsivus | 350_Klaaspakett | 375_Viimistlus-seest | 376_Viimistlus-väljast | 900_Tootja | 905_Mudel | 379_Käepide | 396_Aknalaud
2 x SLKF-04 | SLKF-04 | MUDELIS: väljast Avatäide: raam värv antrasiit RAL7016; Avatäide: raam värv antrasiit RAL7016; seest Avatäide: raam värv antrasiit RAL7016; Avatäide: raam värv antrasiit RAL7016; MÄRKUS: ootel | ootel | ootel | ootel | ootel | MUDELIS: Avatäide: raam värv antrasiit RAL7016; Avatäide: raam värv antrasiit RAL7016; MÄRKUS: RAL7016 | MUDELIS: Avatäide: raam värv antrasiit RAL7016; Avatäide: raam värv antrasiit RAL7016; MÄRKUS: | ootel | ootel | ootel | ootel
2 x SKF-04 | SKF-04 | MUDELIS: väljast Avatäide: raam värv antrasiit RAL7016; Avatäide: raam värv antrasiit RAL7016; seest Avatäide: raam värv antrasiit RAL7016; Avatäide: raam värv antrasiit RAL7016; MÄRKUS: Alumiiniumprofiil | 10 mm (55.2 helipidavama lamineeritud klaasiga). | R’w ≥ 35 dB | nõudeid ei esitata | Kahekordne klaaspakett, vaheliistude toon: must, lamineering | MUDELIS: Avatäide: raam värv antrasiit RAL7016; Avatäide: raam värv antrasiit RAL7016; MÄRKUS: Matt must RAL9005 | MUDELIS: Avatäide: raam värv antrasiit RAL7016; Avatäide: raam värv antrasiit RAL7016; MÄRKUS: Matt must RAL9005 | Structo | Glassline 30 | Puudub | Harjatud kuuse ristkihtpuitplaat (Dold) 19mm, viimistletud Osmo 3111 + Osmo 3065. Paled samuti. vt. SA-osa sk ja AR-osa sõlmlahendusi | AR_Aken - 001_Nimetus: Siseaken

# IfcWindow: Window 26, SKF-03
In: Teine korrus
Type - OperationType: SINGLE_PANEL; ParameterTakesPrecedence: no; Sizeable: no
Type - Window Lining Properties - LiningDepth: 50 mm; LiningThickness: 30 mm
Type - Window Panel Properties - Panel 1 - OperationType: FIXEDCASEMENT; PanelPosition: MIDDLE
OverallHeight: 3060 mm; OverallWidth: 2435 mm; Classification: 1.25 IfcWindowStyle (aken) (BIM ÜBN + Archicad Classification)
Pset_WindowCommon - Reference: SKF-03; ThermalTransmittance: 0; GlazingAreaFraction: 7.125; IsExternal: no
AR_Aken - 001_Nimetus: Siseaken; 300_Tähis: SKF-03; 310_Materjal: MUDELIS: väljast Avatäide: raam värv antrasiit RAL7016; Avatäide: raam värv antrasiit RAL7016; seest Avatäide: raam värv antrasiit RAL7016; Avatäide: raam värv antrasiit RAL7016; MÄRKUS: Alumiiniumprofiil; 315_Avanemine: - ; ARCHICAD tüüp: Fixed Glass; 320_Klaas: 10 mm (55.2 helipidavama lamineeritud klaasiga).; 325_Helipidavus: R’w ≥ 30 dB; 330_Tulepüsivus: nõudeid ei esitata; 335_Välispiire: no; 340_Soojusläbivus: 0; 350_Klaaspakett: Kahekordne klaaspakett, vaheliistude toon: must, lamineering; 355_Pindala: 7.4511 m2; 375_Viimistlus-seest: MUDELIS: Avatäide: raam värv antrasiit RAL7016; Avatäide: raam värv antrasiit RAL7016; MÄRKUS: Matt must RAL9005; 376_Viimistlus-väljast: MUDELIS: Avatäide: raam värv antrasiit RAL7016; Avatäide: raam värv antrasiit RAL7016; MÄRKUS: Matt must RAL9005; 900_Tootja: Structo; 905_Mudel: Glassline 30; 910_Tooteinfo: ootel; 915_Kasutus-ja-hooldusjuhend: ootel; 306_Ava-laius: 2435 mm; 307_Ava-kõrgus: 3060 mm; 379_Käepide: Puudub; 395_Veeplekk: ootel; 396_Aknalaud: Harjatud kuuse ristkihtpuitplaat (Dold) 19mm, viimistletud Osmo 3111 + Osmo 3065. Paled samuti. vt. SA-osa sk ja AR-osa sõlmlahendusi; 345_Päikesekiirgus-tegur: 0
AR_ÜLD - 009_Märkus: OMA märkus
AC_Pset_RenovationAndPhasing - Renovation Status: New

# IfcWindow: Window 26 (4)
In: Esimene korrus
Type - OperationType: SINGLE_PANEL; ParameterTakesPrecedence: no; Sizeable: no
Type - Window Lining Properties - LiningDepth: 92 mm; LiningThickness: 90 mm
Type - Window Panel Properties - Panel 1 - OperationType: BOTTOMHUNG; PanelPosition: MIDDLE; FrameDepth: 112 mm; FrameThickness: 84 mm
OverallHeight: 1410 mm; OverallWidth: 1250 mm; Classification: 1.25 IfcWindowStyle (aken) (BIM ÜBN + Archicad Classification)
Pset_WindowCommon - Reference: A-6; ThermalTransmittance: 0; GlazingAreaFraction: 1.0919; IsExternal: yes
AR_Aken - 001_Nimetus: Välisaken; 300_Tähis: A-6; 310_Materjal: MUDELIS: väljast Avatäide: raam värv antrasiit RAL7016; Avatäide: raam värv antrasiit RAL7016; seest Avatäide: raam värv antrasiit RAL7016; Avatäide: raam värv antrasiit RAL7016; MÄRKUS: Puitalumiinium; 315_Avanemine: Kaldavatav ; ARCHICAD tüüp: Bottom Hung; 320_Klaas: Kolmekordne klaaspakett, argoongaasiga, välimine: selektiivklaas, LT=72%, lamineeritud klaas, klaasitoon: kirgas, keskmine: klaasitoon: kirgas, sisemine: lamineeritud floatklaas, klaasitoon: kirgas. Vaheliistud mustad; 325_Helipidavus: R’tr,s,w = 30 dB; 330_Tulepüsivus: nõudeid ei esitata; 335_Välispiire: yes; 340_Soojusläbivus: 0; 350_Klaaspakett: Kolmekordne klaaspakett, vaheliistude toon: must, 44.2 lamineering, täpsustada TP-staadiumis; 355_Pindala: 1.7625 m2; 375_Viimistlus-seest: MUDELIS: Avatäide: raam värv antrasiit RAL7016; Avatäide: raam värv antrasiit RAL7016; MÄRKUS: Matt antrasiit RAL7016, toonitud puit; 376_Viimistlus-väljast: MUDELIS: Avatäide: raam värv antrasiit RAL7016; Avatäide: raam värv antrasiit RAL7016; MÄRKUS: Matt antrasiit RAL7016; 900_Tootja: ootel; 905_Mudel: ootel; 910_Tooteinfo: ootel; 915_Kasutus-ja-hooldusjuhend: ootel; 306_Ava-laius: 1250 mm; 307_Ava-kõrgus: 1410 mm; 379_Käepide: ilma rosetita Hoppe Toulon, viimistlus: F9714M matt must; 395_Veeplekk: Valtsitud terasplekist veeplekk, min t=0,7 mm, viimistlus: pulbervärvitud antratsiit RAL7016, vt. AR-osa sõlmlahendusi; 396_Aknalaud: Harjatud kuuse ristkihtpuitplaat (Dold) 19mm, viimistletud Osmo 3111 + Osmo 3065. Paled samuti. vt. SA-osa sk ja AR-osa sõlmlahendusi; 345_Päikesekiirgus-tegur: 0
AC_Pset_RenovationAndPhasing - Renovation Status: New
